###############################################################
#  Generated by:      Cadence Innovus 22.12-s080_1
#  OS:                Linux x86_64(Host ID apcw301i-10-205-43-14.nxdi.in-awsc1.nxp.com)
#  Generated on:      Tue Aug  8 16:31:20 2023
#  Design:            CortexM3Integration
#  Command:           write_lef_abstract 1234.lef
###############################################################

VERSION 5.8 ;

BUSBITCHARS "[]" ;
DIVIDERCHAR "/" ;

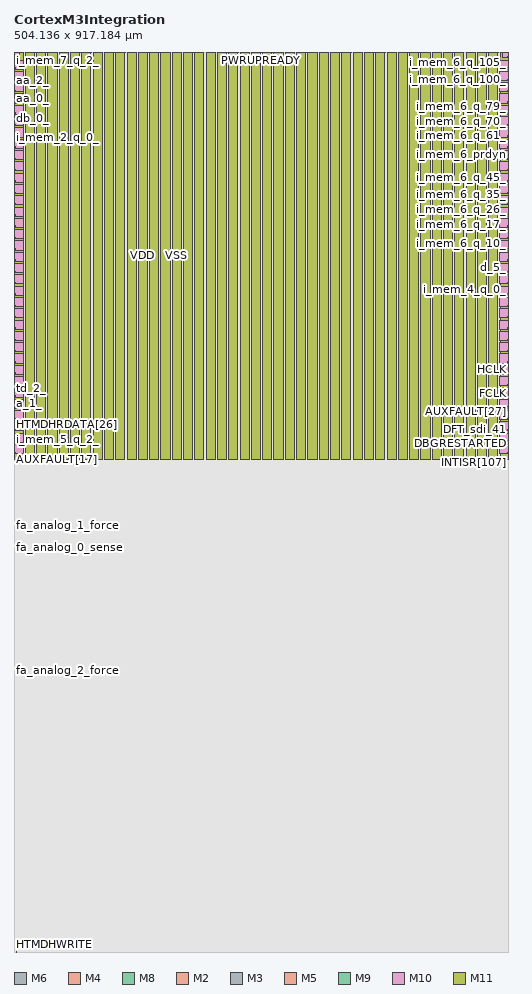
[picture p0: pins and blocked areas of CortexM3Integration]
MACRO CortexM3Integration
  FIXEDMASK ;
  CLASS BLOCK ;
  SIZE 504.136000 BY 917.184000 ;
  FOREIGN CortexM3Integration 0.000000 0.000000 ;
  ORIGIN 0 0 ;
  SYMMETRY X Y R90 ;
  PIN PWRUP
    DIRECTION INPUT ;
    USE SIGNAL ;
    PORT
      LAYER M6 ;
        RECT 0.000000 518.900000 0.375000 518.940000 ;
    END
  END PWRUP
  PIN ISOLATEn
    DIRECTION INPUT ;
    USE SIGNAL ;
    PORT
      LAYER M4 ;
        RECT 503.761000 518.500000 504.136000 518.540000 ;
    END
  END ISOLATEn
  PIN RETAINn
    DIRECTION INPUT ;
    USE SIGNAL ;
    PORT
      LAYER M6 ;
        RECT 503.761000 501.780000 504.136000 501.820000 ;
    END
  END RETAINn
  PIN nTRST
    DIRECTION INPUT ;
    USE SIGNAL ;
    PORT
      LAYER M6 ;
        RECT 0.000000 519.060000 0.375000 519.100000 ;
    END
  END nTRST
  PIN SWCLKTCK
    DIRECTION INPUT ;
    USE SIGNAL ;
    PORT
      LAYER M8 ;
        RECT 504.018000 518.371000 504.136000 518.557000 ;
    END
  END SWCLKTCK
  PIN SWDITMS
    DIRECTION INPUT ;
    USE SIGNAL ;
    PORT
      LAYER M2 ;
        RECT MASK 2 503.907000 518.512000 504.136000 518.544000 ;
    END
  END SWDITMS
  PIN TDI
    DIRECTION INPUT ;
    USE SIGNAL ;
    PORT
      LAYER M8 ;
        RECT 0.000000 519.073000 0.354000 519.135000 ;
    END
  END TDI
  PIN PORESETn
    DIRECTION INPUT ;
    USE SIGNAL ;
    PORT
      LAYER M8 ;
        RECT 503.782000 518.945000 504.136000 519.007000 ;
    END
  END PORESETn
  PIN SYSRESETn
    DIRECTION INPUT ;
    USE SIGNAL ;
    PORT
      LAYER M4 ;
        RECT 503.761000 517.380000 504.136000 517.420000 ;
    END
  END SYSRESETn
  PIN RSTBYPASS
    DIRECTION INPUT ;
    USE SIGNAL ;
    PORT
      LAYER M6 ;
        RECT 0.000000 519.220000 0.375000 519.260000 ;
    END
  END RSTBYPASS
  PIN CGBYPASS
    DIRECTION INPUT ;
    USE SIGNAL ;
    PORT
      LAYER M4 ;
        RECT 503.761000 501.780000 504.136000 501.820000 ;
    END
  END CGBYPASS
  PIN FCLK
    DIRECTION INPUT ;
    USE SIGNAL ;
    PORT
      LAYER M8 ;
        RECT 504.018000 561.507000 504.136000 561.693000 ;
    END
  END FCLK
  PIN HCLK
    DIRECTION INPUT ;
    USE SIGNAL ;
    PORT
      LAYER M8 ;
        RECT 504.018000 593.379000 504.136000 593.565000 ;
    END
  END HCLK
  PIN TRACECLKIN
    DIRECTION INPUT ;
    USE SIGNAL ;
    PORT
      LAYER M6 ;
        RECT 0.000000 519.380000 0.375000 519.420000 ;
    END
  END TRACECLKIN
  PIN STCLK
    DIRECTION INPUT ;
    USE SIGNAL ;
    PORT
      LAYER M8 ;
        RECT 0.000000 519.329000 0.354000 519.391000 ;
    END
  END STCLK
  PIN STCALIB[25]
    DIRECTION INPUT ;
    USE SIGNAL ;
    PORT
      LAYER M2 ;
        RECT MASK 2 503.907000 515.952000 504.136000 515.984000 ;
    END
  END STCALIB[25]
  PIN STCALIB[24]
    DIRECTION INPUT ;
    USE SIGNAL ;
    PORT
      LAYER M6 ;
        RECT 0.000000 518.100000 0.375000 518.140000 ;
    END
  END STCALIB[24]
  PIN STCALIB[23]
    DIRECTION INPUT ;
    USE SIGNAL ;
    PORT
      LAYER M8 ;
        RECT 0.000000 518.049000 0.354000 518.111000 ;
    END
  END STCALIB[23]
  PIN STCALIB[22]
    DIRECTION INPUT ;
    USE SIGNAL ;
    PORT
      LAYER M6 ;
        RECT 503.761000 516.740000 504.136000 516.780000 ;
    END
  END STCALIB[22]
  PIN STCALIB[21]
    DIRECTION INPUT ;
    USE SIGNAL ;
    PORT
      LAYER M8 ;
        RECT 503.782000 516.129000 504.136000 516.191000 ;
    END
  END STCALIB[21]
  PIN STCALIB[20]
    DIRECTION INPUT ;
    USE SIGNAL ;
    PORT
      LAYER M4 ;
        RECT 503.761000 516.740000 504.136000 516.780000 ;
    END
  END STCALIB[20]
  PIN STCALIB[19]
    DIRECTION INPUT ;
    USE SIGNAL ;
    PORT
      LAYER M6 ;
        RECT 503.761000 516.180000 504.136000 516.220000 ;
    END
  END STCALIB[19]
  PIN STCALIB[18]
    DIRECTION INPUT ;
    USE SIGNAL ;
    PORT
      LAYER M6 ;
        RECT 503.761000 518.180000 504.136000 518.220000 ;
    END
  END STCALIB[18]
  PIN STCALIB[17]
    DIRECTION INPUT ;
    USE SIGNAL ;
    PORT
      LAYER M6 ;
        RECT 0.000000 518.260000 0.375000 518.300000 ;
    END
  END STCALIB[17]
  PIN STCALIB[16]
    DIRECTION INPUT ;
    USE SIGNAL ;
    PORT
      LAYER M6 ;
        RECT 503.761000 517.380000 504.136000 517.420000 ;
    END
  END STCALIB[16]
  PIN STCALIB[15]
    DIRECTION INPUT ;
    USE SIGNAL ;
    PORT
      LAYER M2 ;
        RECT MASK 2 503.907000 519.408000 504.136000 519.440000 ;
    END
  END STCALIB[15]
  PIN STCALIB[14]
    DIRECTION INPUT ;
    USE SIGNAL ;
    PORT
      LAYER M8 ;
        RECT 0.000000 518.305000 0.354000 518.367000 ;
    END
  END STCALIB[14]
  PIN STCALIB[13]
    DIRECTION INPUT ;
    USE SIGNAL ;
    PORT
      LAYER M2 ;
        RECT MASK 2 503.907000 518.256000 504.136000 518.288000 ;
    END
  END STCALIB[13]
  PIN STCALIB[12]
    DIRECTION INPUT ;
    USE SIGNAL ;
    PORT
      LAYER M4 ;
        RECT 503.761000 518.180000 504.136000 518.220000 ;
    END
  END STCALIB[12]
  PIN STCALIB[11]
    DIRECTION INPUT ;
    USE SIGNAL ;
    PORT
      LAYER M6 ;
        RECT 0.000000 518.420000 0.375000 518.460000 ;
    END
  END STCALIB[11]
  PIN STCALIB[10]
    DIRECTION INPUT ;
    USE SIGNAL ;
    PORT
      LAYER M2 ;
        RECT MASK 2 503.907000 518.000000 504.136000 518.032000 ;
    END
  END STCALIB[10]
  PIN STCALIB[9]
    DIRECTION INPUT ;
    USE SIGNAL ;
    PORT
      LAYER M8 ;
        RECT 503.782000 517.793000 504.136000 517.855000 ;
    END
  END STCALIB[9]
  PIN STCALIB[8]
    DIRECTION INPUT ;
    USE SIGNAL ;
    PORT
      LAYER M4 ;
        RECT 503.761000 519.220000 504.136000 519.260000 ;
    END
  END STCALIB[8]
  PIN STCALIB[7]
    DIRECTION INPUT ;
    USE SIGNAL ;
    PORT
      LAYER M6 ;
        RECT 0.000000 518.580000 0.375000 518.620000 ;
    END
  END STCALIB[7]
  PIN STCALIB[6]
    DIRECTION INPUT ;
    USE SIGNAL ;
    PORT
      LAYER M8 ;
        RECT 0.000000 518.561000 0.354000 518.623000 ;
    END
  END STCALIB[6]
  PIN STCALIB[5]
    DIRECTION INPUT ;
    USE SIGNAL ;
    PORT
      LAYER M2 ;
        RECT MASK 2 503.907000 517.104000 504.136000 517.136000 ;
    END
  END STCALIB[5]
  PIN STCALIB[4]
    DIRECTION INPUT ;
    USE SIGNAL ;
    PORT
      LAYER M8 ;
        RECT 503.782000 517.281000 504.136000 517.343000 ;
    END
  END STCALIB[4]
  PIN STCALIB[3]
    DIRECTION INPUT ;
    USE SIGNAL ;
    PORT
      LAYER M8 ;
        RECT 503.782000 516.641000 504.136000 516.703000 ;
    END
  END STCALIB[3]
  PIN STCALIB[2]
    DIRECTION INPUT ;
    USE SIGNAL ;
    PORT
      LAYER M8 ;
        RECT 503.782000 519.457000 504.136000 519.519000 ;
    END
  END STCALIB[2]
  PIN STCALIB[1]
    DIRECTION INPUT ;
    USE SIGNAL ;
    PORT
      LAYER M6 ;
        RECT 0.000000 518.740000 0.375000 518.780000 ;
    END
  END STCALIB[1]
  PIN STCALIB[0]
    DIRECTION INPUT ;
    USE SIGNAL ;
    PORT
      LAYER M4 ;
        RECT 503.761000 517.860000 504.136000 517.900000 ;
    END
  END STCALIB[0]
  PIN AUXFAULT[31]
    DIRECTION INPUT ;
    USE SIGNAL ;
    PORT
      LAYER M2 ;
        RECT MASK 2 0.000000 501.744000 0.229000 501.776000 ;
    END
  END AUXFAULT[31]
  PIN AUXFAULT[30]
    DIRECTION INPUT ;
    USE SIGNAL ;
    PORT
      LAYER M4 ;
        RECT 503.761000 551.060000 504.136000 551.100000 ;
    END
  END AUXFAULT[30]
  PIN AUXFAULT[29]
    DIRECTION INPUT ;
    USE SIGNAL ;
    PORT
      LAYER M4 ;
        RECT 0.000000 501.780000 0.375000 501.820000 ;
    END
  END AUXFAULT[29]
  PIN AUXFAULT[28]
    DIRECTION INPUT ;
    USE SIGNAL ;
    PORT
      LAYER M6 ;
        RECT 0.000000 501.780000 0.375000 501.820000 ;
    END
  END AUXFAULT[28]
  PIN AUXFAULT[27]
    DIRECTION INPUT ;
    USE SIGNAL ;
    PORT
      LAYER M2 ;
        RECT MASK 1 503.907000 550.960000 504.136000 550.992000 ;
    END
  END AUXFAULT[27]
  PIN AUXFAULT[26]
    DIRECTION INPUT ;
    USE SIGNAL ;
    PORT
      LAYER M8 ;
        RECT 503.782000 550.817000 504.136000 550.879000 ;
    END
  END AUXFAULT[26]
  PIN AUXFAULT[25]
    DIRECTION INPUT ;
    USE SIGNAL ;
    PORT
      LAYER M8 ;
        RECT 0.000000 501.793000 0.354000 501.855000 ;
    END
  END AUXFAULT[25]
  PIN AUXFAULT[24]
    DIRECTION INPUT ;
    USE SIGNAL ;
    PORT
      LAYER M6 ;
        RECT 503.761000 550.820000 504.136000 550.860000 ;
    END
  END AUXFAULT[24]
  PIN AUXFAULT[23]
    DIRECTION INPUT ;
    USE SIGNAL ;
    PORT
      LAYER M2 ;
        RECT MASK 2 0.000000 501.872000 0.229000 501.904000 ;
    END
  END AUXFAULT[23]
  PIN AUXFAULT[22]
    DIRECTION INPUT ;
    USE SIGNAL ;
    PORT
      LAYER M4 ;
        RECT 503.761000 550.740000 504.136000 550.780000 ;
    END
  END AUXFAULT[22]
  PIN AUXFAULT[21]
    DIRECTION INPUT ;
    USE SIGNAL ;
    PORT
      LAYER M4 ;
        RECT 0.000000 501.940000 0.375000 501.980000 ;
    END
  END AUXFAULT[21]
  PIN AUXFAULT[20]
    DIRECTION INPUT ;
    USE SIGNAL ;
    PORT
      LAYER M6 ;
        RECT 0.000000 501.940000 0.375000 501.980000 ;
    END
  END AUXFAULT[20]
  PIN AUXFAULT[19]
    DIRECTION INPUT ;
    USE SIGNAL ;
    PORT
      LAYER M2 ;
        RECT MASK 1 503.907000 550.704000 504.136000 550.736000 ;
    END
  END AUXFAULT[19]
  PIN AUXFAULT[18]
    DIRECTION INPUT ;
    USE SIGNAL ;
    PORT
      LAYER M6 ;
        RECT 503.761000 550.500000 504.136000 550.540000 ;
    END
  END AUXFAULT[18]
  PIN AUXFAULT[17]
    DIRECTION INPUT ;
    USE SIGNAL ;
    PORT
      LAYER M2 ;
        RECT MASK 2 0.000000 502.000000 0.229000 502.032000 ;
    END
  END AUXFAULT[17]
  PIN AUXFAULT[16]
    DIRECTION INPUT ;
    USE SIGNAL ;
    PORT
      LAYER M2 ;
        RECT MASK 1 503.907000 550.448000 504.136000 550.480000 ;
    END
  END AUXFAULT[16]
  PIN AUXFAULT[15]
    DIRECTION INPUT ;
    USE SIGNAL ;
    PORT
      LAYER M4 ;
        RECT 0.000000 502.100000 0.375000 502.140000 ;
    END
  END AUXFAULT[15]
  PIN AUXFAULT[14]
    DIRECTION INPUT ;
    USE SIGNAL ;
    PORT
      LAYER M6 ;
        RECT 0.000000 502.100000 0.375000 502.140000 ;
    END
  END AUXFAULT[14]
  PIN AUXFAULT[13]
    DIRECTION INPUT ;
    USE SIGNAL ;
    PORT
      LAYER M8 ;
        RECT 0.000000 502.049000 0.354000 502.111000 ;
    END
  END AUXFAULT[13]
  PIN AUXFAULT[12]
    DIRECTION INPUT ;
    USE SIGNAL ;
    PORT
      LAYER M4 ;
        RECT 503.761000 550.420000 504.136000 550.460000 ;
    END
  END AUXFAULT[12]
  PIN AUXFAULT[11]
    DIRECTION INPUT ;
    USE SIGNAL ;
    PORT
      LAYER M8 ;
        RECT 503.782000 550.305000 504.136000 550.367000 ;
    END
  END AUXFAULT[11]
  PIN AUXFAULT[10]
    DIRECTION INPUT ;
    USE SIGNAL ;
    PORT
      LAYER M2 ;
        RECT MASK 1 503.907000 550.192000 504.136000 550.224000 ;
    END
  END AUXFAULT[10]
  PIN AUXFAULT[9]
    DIRECTION INPUT ;
    USE SIGNAL ;
    PORT
      LAYER M2 ;
        RECT MASK 2 0.000000 502.128000 0.229000 502.160000 ;
    END
  END AUXFAULT[9]
  PIN AUXFAULT[8]
    DIRECTION INPUT ;
    USE SIGNAL ;
    PORT
      LAYER M6 ;
        RECT 503.761000 550.180000 504.136000 550.220000 ;
    END
  END AUXFAULT[8]
  PIN AUXFAULT[7]
    DIRECTION INPUT ;
    USE SIGNAL ;
    PORT
      LAYER M2 ;
        RECT MASK 2 0.000000 502.256000 0.229000 502.288000 ;
    END
  END AUXFAULT[7]
  PIN AUXFAULT[6]
    DIRECTION INPUT ;
    USE SIGNAL ;
    PORT
      LAYER M4 ;
        RECT 503.761000 550.100000 504.136000 550.140000 ;
    END
  END AUXFAULT[6]
  PIN AUXFAULT[5]
    DIRECTION INPUT ;
    USE SIGNAL ;
    PORT
      LAYER M4 ;
        RECT 0.000000 502.260000 0.375000 502.300000 ;
    END
  END AUXFAULT[5]
  PIN AUXFAULT[4]
    DIRECTION INPUT ;
    USE SIGNAL ;
    PORT
      LAYER M6 ;
        RECT 0.000000 502.260000 0.375000 502.300000 ;
    END
  END AUXFAULT[4]
  PIN AUXFAULT[3]
    DIRECTION INPUT ;
    USE SIGNAL ;
    PORT
      LAYER M2 ;
        RECT MASK 1 503.907000 549.936000 504.136000 549.968000 ;
    END
  END AUXFAULT[3]
  PIN AUXFAULT[2]
    DIRECTION INPUT ;
    USE SIGNAL ;
    PORT
      LAYER M6 ;
        RECT 503.761000 549.860000 504.136000 549.900000 ;
    END
  END AUXFAULT[2]
  PIN AUXFAULT[1]
    DIRECTION INPUT ;
    USE SIGNAL ;
    PORT
      LAYER M8 ;
        RECT 0.000000 502.305000 0.354000 502.367000 ;
    END
  END AUXFAULT[1]
  PIN AUXFAULT[0]
    DIRECTION INPUT ;
    USE SIGNAL ;
    PORT
      LAYER M8 ;
        RECT 503.782000 549.793000 504.136000 549.855000 ;
    END
  END AUXFAULT[0]
  PIN BIGEND
    DIRECTION INPUT ;
    USE SIGNAL ;
    PORT
      LAYER M2 ;
        RECT MASK 2 503.907000 517.360000 504.136000 517.392000 ;
    END
  END BIGEND
  PIN INTISR[239]
    DIRECTION INPUT ;
    USE SIGNAL ;
    PORT
      LAYER M6 ;
        RECT 503.761000 533.860000 504.136000 533.900000 ;
    END
  END INTISR[239]
  PIN INTISR[238]
    DIRECTION INPUT ;
    USE SIGNAL ;
    PORT
      LAYER M2 ;
        RECT MASK 1 503.907000 533.808000 504.136000 533.840000 ;
    END
  END INTISR[238]
  PIN INTISR[237]
    DIRECTION INPUT ;
    USE SIGNAL ;
    PORT
      LAYER M6 ;
        RECT 0.000000 511.060000 0.375000 511.100000 ;
    END
  END INTISR[237]
  PIN INTISR[236]
    DIRECTION INPUT ;
    USE SIGNAL ;
    PORT
      LAYER M4 ;
        RECT 503.761000 533.780000 504.136000 533.820000 ;
    END
  END INTISR[236]
  PIN INTISR[235]
    DIRECTION INPUT ;
    USE SIGNAL ;
    PORT
      LAYER M8 ;
        RECT 503.782000 533.665000 504.136000 533.727000 ;
    END
  END INTISR[235]
  PIN INTISR[234]
    DIRECTION INPUT ;
    USE SIGNAL ;
    PORT
      LAYER M2 ;
        RECT MASK 1 503.907000 533.552000 504.136000 533.584000 ;
    END
  END INTISR[234]
  PIN INTISR[233]
    DIRECTION INPUT ;
    USE SIGNAL ;
    PORT
      LAYER M8 ;
        RECT 0.000000 511.137000 0.354000 511.199000 ;
    END
  END INTISR[233]
  PIN INTISR[232]
    DIRECTION INPUT ;
    USE SIGNAL ;
    PORT
      LAYER M6 ;
        RECT 503.761000 533.540000 504.136000 533.580000 ;
    END
  END INTISR[232]
  PIN INTISR[231]
    DIRECTION INPUT ;
    USE SIGNAL ;
    PORT
      LAYER M4 ;
        RECT 503.761000 533.460000 504.136000 533.500000 ;
    END
  END INTISR[231]
  PIN INTISR[230]
    DIRECTION INPUT ;
    USE SIGNAL ;
    PORT
      LAYER M6 ;
        RECT 0.000000 511.220000 0.375000 511.260000 ;
    END
  END INTISR[230]
  PIN INTISR[229]
    DIRECTION INPUT ;
    USE SIGNAL ;
    PORT
      LAYER M2 ;
        RECT MASK 1 503.907000 533.296000 504.136000 533.328000 ;
    END
  END INTISR[229]
  PIN INTISR[228]
    DIRECTION INPUT ;
    USE SIGNAL ;
    PORT
      LAYER M6 ;
        RECT 503.761000 533.220000 504.136000 533.260000 ;
    END
  END INTISR[228]
  PIN INTISR[227]
    DIRECTION INPUT ;
    USE SIGNAL ;
    PORT
      LAYER M8 ;
        RECT 503.782000 533.153000 504.136000 533.215000 ;
    END
  END INTISR[227]
  PIN INTISR[226]
    DIRECTION INPUT ;
    USE SIGNAL ;
    PORT
      LAYER M6 ;
        RECT 0.000000 511.380000 0.375000 511.420000 ;
    END
  END INTISR[226]
  PIN INTISR[225]
    DIRECTION INPUT ;
    USE SIGNAL ;
    PORT
      LAYER M4 ;
        RECT 503.761000 533.140000 504.136000 533.180000 ;
    END
  END INTISR[225]
  PIN INTISR[224]
    DIRECTION INPUT ;
    USE SIGNAL ;
    PORT
      LAYER M2 ;
        RECT MASK 1 503.907000 533.040000 504.136000 533.072000 ;
    END
  END INTISR[224]
  PIN INTISR[223]
    DIRECTION INPUT ;
    USE SIGNAL ;
    PORT
      LAYER M8 ;
        RECT 0.000000 511.393000 0.354000 511.455000 ;
    END
  END INTISR[223]
  PIN INTISR[222]
    DIRECTION INPUT ;
    USE SIGNAL ;
    PORT
      LAYER M2 ;
        RECT MASK 1 503.907000 534.064000 504.136000 534.096000 ;
    END
  END INTISR[222]
  PIN INTISR[221]
    DIRECTION INPUT ;
    USE SIGNAL ;
    PORT
      LAYER M2 ;
        RECT MASK 1 503.907000 532.016000 504.136000 532.048000 ;
    END
  END INTISR[221]
  PIN INTISR[220]
    DIRECTION INPUT ;
    USE SIGNAL ;
    PORT
      LAYER M6 ;
        RECT 0.000000 511.540000 0.375000 511.580000 ;
    END
  END INTISR[220]
  PIN INTISR[219]
    DIRECTION INPUT ;
    USE SIGNAL ;
    PORT
      LAYER M6 ;
        RECT 503.761000 531.940000 504.136000 531.980000 ;
    END
  END INTISR[219]
  PIN INTISR[218]
    DIRECTION INPUT ;
    USE SIGNAL ;
    PORT
      LAYER M4 ;
        RECT 503.761000 531.860000 504.136000 531.900000 ;
    END
  END INTISR[218]
  PIN INTISR[217]
    DIRECTION INPUT ;
    USE SIGNAL ;
    PORT
      LAYER M2 ;
        RECT MASK 1 503.907000 531.760000 504.136000 531.792000 ;
    END
  END INTISR[217]
  PIN INTISR[216]
    DIRECTION INPUT ;
    USE SIGNAL ;
    PORT
      LAYER M6 ;
        RECT 0.000000 511.700000 0.375000 511.740000 ;
    END
  END INTISR[216]
  PIN INTISR[215]
    DIRECTION INPUT ;
    USE SIGNAL ;
    PORT
      LAYER M8 ;
        RECT 0.000000 511.649000 0.354000 511.711000 ;
    END
  END INTISR[215]
  PIN INTISR[214]
    DIRECTION INPUT ;
    USE SIGNAL ;
    PORT
      LAYER M6 ;
        RECT 503.761000 531.620000 504.136000 531.660000 ;
    END
  END INTISR[214]
  PIN INTISR[213]
    DIRECTION INPUT ;
    USE SIGNAL ;
    PORT
      LAYER M4 ;
        RECT 503.761000 531.540000 504.136000 531.580000 ;
    END
  END INTISR[213]
  PIN INTISR[212]
    DIRECTION INPUT ;
    USE SIGNAL ;
    PORT
      LAYER M2 ;
        RECT MASK 1 503.907000 531.504000 504.136000 531.536000 ;
    END
  END INTISR[212]
  PIN INTISR[211]
    DIRECTION INPUT ;
    USE SIGNAL ;
    PORT
      LAYER M6 ;
        RECT 503.761000 531.300000 504.136000 531.340000 ;
    END
  END INTISR[211]
  PIN INTISR[210]
    DIRECTION INPUT ;
    USE SIGNAL ;
    PORT
      LAYER M2 ;
        RECT MASK 1 503.907000 531.248000 504.136000 531.280000 ;
    END
  END INTISR[210]
  PIN INTISR[209]
    DIRECTION INPUT ;
    USE SIGNAL ;
    PORT
      LAYER M6 ;
        RECT 0.000000 511.860000 0.375000 511.900000 ;
    END
  END INTISR[209]
  PIN INTISR[208]
    DIRECTION INPUT ;
    USE SIGNAL ;
    PORT
      LAYER M6 ;
        RECT 503.761000 513.620000 504.136000 513.660000 ;
    END
  END INTISR[208]
  PIN INTISR[207]
    DIRECTION INPUT ;
    USE SIGNAL ;
    PORT
      LAYER M2 ;
        RECT MASK 2 503.907000 513.392000 504.136000 513.424000 ;
    END
  END INTISR[207]
  PIN INTISR[206]
    DIRECTION INPUT ;
    USE SIGNAL ;
    PORT
      LAYER M8 ;
        RECT 0.000000 511.905000 0.354000 511.967000 ;
    END
  END INTISR[206]
  PIN INTISR[205]
    DIRECTION INPUT ;
    USE SIGNAL ;
    PORT
      LAYER M6 ;
        RECT 503.761000 513.300000 504.136000 513.340000 ;
    END
  END INTISR[205]
  PIN INTISR[204]
    DIRECTION INPUT ;
    USE SIGNAL ;
    PORT
      LAYER M8 ;
        RECT 503.782000 513.185000 504.136000 513.247000 ;
    END
  END INTISR[204]
  PIN INTISR[203]
    DIRECTION INPUT ;
    USE SIGNAL ;
    PORT
      LAYER M6 ;
        RECT 0.000000 512.020000 0.375000 512.060000 ;
    END
  END INTISR[203]
  PIN INTISR[202]
    DIRECTION INPUT ;
    USE SIGNAL ;
    PORT
      LAYER M6 ;
        RECT 503.761000 512.980000 504.136000 513.020000 ;
    END
  END INTISR[202]
  PIN INTISR[201]
    DIRECTION INPUT ;
    USE SIGNAL ;
    PORT
      LAYER M2 ;
        RECT MASK 2 503.907000 512.752000 504.136000 512.784000 ;
    END
  END INTISR[201]
  PIN INTISR[200]
    DIRECTION INPUT ;
    USE SIGNAL ;
    PORT
      LAYER M8 ;
        RECT 503.782000 512.673000 504.136000 512.735000 ;
    END
  END INTISR[200]
  PIN INTISR[199]
    DIRECTION INPUT ;
    USE SIGNAL ;
    PORT
      LAYER M6 ;
        RECT 0.000000 512.180000 0.375000 512.220000 ;
    END
  END INTISR[199]
  PIN INTISR[198]
    DIRECTION INPUT ;
    USE SIGNAL ;
    PORT
      LAYER M8 ;
        RECT 0.000000 512.161000 0.354000 512.223000 ;
    END
  END INTISR[198]
  PIN INTISR[197]
    DIRECTION INPUT ;
    USE SIGNAL ;
    PORT
      LAYER M6 ;
        RECT 503.761000 512.660000 504.136000 512.700000 ;
    END
  END INTISR[197]
  PIN INTISR[196]
    DIRECTION INPUT ;
    USE SIGNAL ;
    PORT
      LAYER M4 ;
        RECT 503.761000 512.660000 504.136000 512.700000 ;
    END
  END INTISR[196]
  PIN INTISR[195]
    DIRECTION INPUT ;
    USE SIGNAL ;
    PORT
      LAYER M2 ;
        RECT MASK 2 503.907000 512.496000 504.136000 512.528000 ;
    END
  END INTISR[195]
  PIN INTISR[194]
    DIRECTION INPUT ;
    USE SIGNAL ;
    PORT
      LAYER M6 ;
        RECT 503.761000 512.340000 504.136000 512.380000 ;
    END
  END INTISR[194]
  PIN INTISR[193]
    DIRECTION INPUT ;
    USE SIGNAL ;
    PORT
      LAYER M6 ;
        RECT 0.000000 512.340000 0.375000 512.380000 ;
    END
  END INTISR[193]
  PIN INTISR[192]
    DIRECTION INPUT ;
    USE SIGNAL ;
    PORT
      LAYER M6 ;
        RECT 503.761000 512.020000 504.136000 512.060000 ;
    END
  END INTISR[192]
  PIN INTISR[191]
    DIRECTION INPUT ;
    USE SIGNAL ;
    PORT
      LAYER M4 ;
        RECT 503.761000 512.020000 504.136000 512.060000 ;
    END
  END INTISR[191]
  PIN INTISR[190]
    DIRECTION INPUT ;
    USE SIGNAL ;
    PORT
      LAYER M2 ;
        RECT MASK 2 503.907000 511.984000 504.136000 512.016000 ;
    END
  END INTISR[190]
  PIN INTISR[189]
    DIRECTION INPUT ;
    USE SIGNAL ;
    PORT
      LAYER M8 ;
        RECT 0.000000 512.417000 0.354000 512.479000 ;
    END
  END INTISR[189]
  PIN INTISR[188]
    DIRECTION INPUT ;
    USE SIGNAL ;
    PORT
      LAYER M2 ;
        RECT MASK 2 503.907000 511.728000 504.136000 511.760000 ;
    END
  END INTISR[188]
  PIN INTISR[187]
    DIRECTION INPUT ;
    USE SIGNAL ;
    PORT
      LAYER M6 ;
        RECT 503.761000 511.700000 504.136000 511.740000 ;
    END
  END INTISR[187]
  PIN INTISR[186]
    DIRECTION INPUT ;
    USE SIGNAL ;
    PORT
      LAYER M6 ;
        RECT 0.000000 512.500000 0.375000 512.540000 ;
    END
  END INTISR[186]
  PIN INTISR[185]
    DIRECTION INPUT ;
    USE SIGNAL ;
    PORT
      LAYER M4 ;
        RECT 503.761000 511.700000 504.136000 511.740000 ;
    END
  END INTISR[185]
  PIN INTISR[184]
    DIRECTION INPUT ;
    USE SIGNAL ;
    PORT
      LAYER M8 ;
        RECT 503.782000 511.649000 504.136000 511.711000 ;
    END
  END INTISR[184]
  PIN INTISR[183]
    DIRECTION INPUT ;
    USE SIGNAL ;
    PORT
      LAYER M2 ;
        RECT MASK 2 503.907000 511.472000 504.136000 511.504000 ;
    END
  END INTISR[183]
  PIN INTISR[182]
    DIRECTION INPUT ;
    USE SIGNAL ;
    PORT
      LAYER M6 ;
        RECT 0.000000 512.660000 0.375000 512.700000 ;
    END
  END INTISR[182]
  PIN INTISR[181]
    DIRECTION INPUT ;
    USE SIGNAL ;
    PORT
      LAYER M6 ;
        RECT 503.761000 511.380000 504.136000 511.420000 ;
    END
  END INTISR[181]
  PIN INTISR[180]
    DIRECTION INPUT ;
    USE SIGNAL ;
    PORT
      LAYER M4 ;
        RECT 503.761000 511.380000 504.136000 511.420000 ;
    END
  END INTISR[180]
  PIN INTISR[179]
    DIRECTION INPUT ;
    USE SIGNAL ;
    PORT
      LAYER M8 ;
        RECT 0.000000 512.673000 0.354000 512.735000 ;
    END
  END INTISR[179]
  PIN INTISR[178]
    DIRECTION INPUT ;
    USE SIGNAL ;
    PORT
      LAYER M2 ;
        RECT MASK 2 503.907000 511.216000 504.136000 511.248000 ;
    END
  END INTISR[178]
  PIN INTISR[177]
    DIRECTION INPUT ;
    USE SIGNAL ;
    PORT
      LAYER M8 ;
        RECT 503.782000 511.137000 504.136000 511.199000 ;
    END
  END INTISR[177]
  PIN INTISR[176]
    DIRECTION INPUT ;
    USE SIGNAL ;
    PORT
      LAYER M6 ;
        RECT 0.000000 512.820000 0.375000 512.860000 ;
    END
  END INTISR[176]
  PIN INTISR[175]
    DIRECTION INPUT ;
    USE SIGNAL ;
    PORT
      LAYER M6 ;
        RECT 503.761000 511.060000 504.136000 511.100000 ;
    END
  END INTISR[175]
  PIN INTISR[174]
    DIRECTION INPUT ;
    USE SIGNAL ;
    PORT
      LAYER M4 ;
        RECT 503.761000 511.060000 504.136000 511.100000 ;
    END
  END INTISR[174]
  PIN INTISR[173]
    DIRECTION INPUT ;
    USE SIGNAL ;
    PORT
      LAYER M2 ;
        RECT MASK 2 503.907000 510.960000 504.136000 510.992000 ;
    END
  END INTISR[173]
  PIN INTISR[172]
    DIRECTION INPUT ;
    USE SIGNAL ;
    PORT
      LAYER M6 ;
        RECT 0.000000 512.980000 0.375000 513.020000 ;
    END
  END INTISR[172]
  PIN INTISR[171]
    DIRECTION INPUT ;
    USE SIGNAL ;
    PORT
      LAYER M8 ;
        RECT 0.000000 512.929000 0.354000 512.991000 ;
    END
  END INTISR[171]
  PIN INTISR[170]
    DIRECTION INPUT ;
    USE SIGNAL ;
    PORT
      LAYER M6 ;
        RECT 503.761000 510.740000 504.136000 510.780000 ;
    END
  END INTISR[170]
  PIN INTISR[169]
    DIRECTION INPUT ;
    USE SIGNAL ;
    PORT
      LAYER M4 ;
        RECT 503.761000 510.740000 504.136000 510.780000 ;
    END
  END INTISR[169]
  PIN INTISR[168]
    DIRECTION INPUT ;
    USE SIGNAL ;
    PORT
      LAYER M2 ;
        RECT MASK 2 503.907000 510.704000 504.136000 510.736000 ;
    END
  END INTISR[168]
  PIN INTISR[167]
    DIRECTION INPUT ;
    USE SIGNAL ;
    PORT
      LAYER M8 ;
        RECT 503.782000 510.625000 504.136000 510.687000 ;
    END
  END INTISR[167]
  PIN INTISR[166]
    DIRECTION INPUT ;
    USE SIGNAL ;
    PORT
      LAYER M2 ;
        RECT MASK 2 503.907000 510.448000 504.136000 510.480000 ;
    END
  END INTISR[166]
  PIN INTISR[165]
    DIRECTION INPUT ;
    USE SIGNAL ;
    PORT
      LAYER M6 ;
        RECT 0.000000 513.140000 0.375000 513.180000 ;
    END
  END INTISR[165]
  PIN INTISR[164]
    DIRECTION INPUT ;
    USE SIGNAL ;
    PORT
      LAYER M6 ;
        RECT 503.761000 510.420000 504.136000 510.460000 ;
    END
  END INTISR[164]
  PIN INTISR[163]
    DIRECTION INPUT ;
    USE SIGNAL ;
    PORT
      LAYER M4 ;
        RECT 503.761000 510.420000 504.136000 510.460000 ;
    END
  END INTISR[163]
  PIN INTISR[162]
    DIRECTION INPUT ;
    USE SIGNAL ;
    PORT
      LAYER M8 ;
        RECT 0.000000 513.185000 0.354000 513.247000 ;
    END
  END INTISR[162]
  PIN INTISR[161]
    DIRECTION INPUT ;
    USE SIGNAL ;
    PORT
      LAYER M8 ;
        RECT 503.782000 512.161000 504.136000 512.223000 ;
    END
  END INTISR[161]
  PIN INTISR[160]
    DIRECTION INPUT ;
    USE SIGNAL ;
    PORT
      LAYER M2 ;
        RECT MASK 2 503.907000 510.192000 504.136000 510.224000 ;
    END
  END INTISR[160]
  PIN INTISR[159]
    DIRECTION INPUT ;
    USE SIGNAL ;
    PORT
      LAYER M6 ;
        RECT 0.000000 513.300000 0.375000 513.340000 ;
    END
  END INTISR[159]
  PIN INTISR[158]
    DIRECTION INPUT ;
    USE SIGNAL ;
    PORT
      LAYER M8 ;
        RECT 503.782000 510.113000 504.136000 510.175000 ;
    END
  END INTISR[158]
  PIN INTISR[157]
    DIRECTION INPUT ;
    USE SIGNAL ;
    PORT
      LAYER M6 ;
        RECT 503.761000 510.100000 504.136000 510.140000 ;
    END
  END INTISR[157]
  PIN INTISR[156]
    DIRECTION INPUT ;
    USE SIGNAL ;
    PORT
      LAYER M4 ;
        RECT 503.761000 510.100000 504.136000 510.140000 ;
    END
  END INTISR[156]
  PIN INTISR[155]
    DIRECTION INPUT ;
    USE SIGNAL ;
    PORT
      LAYER M6 ;
        RECT 0.000000 513.460000 0.375000 513.500000 ;
    END
  END INTISR[155]
  PIN INTISR[154]
    DIRECTION INPUT ;
    USE SIGNAL ;
    PORT
      LAYER M8 ;
        RECT 0.000000 513.441000 0.354000 513.503000 ;
    END
  END INTISR[154]
  PIN INTISR[153]
    DIRECTION INPUT ;
    USE SIGNAL ;
    PORT
      LAYER M2 ;
        RECT MASK 2 503.907000 509.936000 504.136000 509.968000 ;
    END
  END INTISR[153]
  PIN INTISR[152]
    DIRECTION INPUT ;
    USE SIGNAL ;
    PORT
      LAYER M6 ;
        RECT 503.761000 509.780000 504.136000 509.820000 ;
    END
  END INTISR[152]
  PIN INTISR[151]
    DIRECTION INPUT ;
    USE SIGNAL ;
    PORT
      LAYER M4 ;
        RECT 503.761000 509.780000 504.136000 509.820000 ;
    END
  END INTISR[151]
  PIN INTISR[150]
    DIRECTION INPUT ;
    USE SIGNAL ;
    PORT
      LAYER M2 ;
        RECT MASK 2 503.907000 509.680000 504.136000 509.712000 ;
    END
  END INTISR[150]
  PIN INTISR[149]
    DIRECTION INPUT ;
    USE SIGNAL ;
    PORT
      LAYER M6 ;
        RECT 0.000000 513.620000 0.375000 513.660000 ;
    END
  END INTISR[149]
  PIN INTISR[148]
    DIRECTION INPUT ;
    USE SIGNAL ;
    PORT
      LAYER M8 ;
        RECT 503.782000 509.601000 504.136000 509.663000 ;
    END
  END INTISR[148]
  PIN INTISR[147]
    DIRECTION INPUT ;
    USE SIGNAL ;
    PORT
      LAYER M6 ;
        RECT 503.761000 509.460000 504.136000 509.500000 ;
    END
  END INTISR[147]
  PIN INTISR[146]
    DIRECTION INPUT ;
    USE SIGNAL ;
    PORT
      LAYER M4 ;
        RECT 503.761000 509.460000 504.136000 509.500000 ;
    END
  END INTISR[146]
  PIN INTISR[145]
    DIRECTION INPUT ;
    USE SIGNAL ;
    PORT
      LAYER M8 ;
        RECT 0.000000 513.697000 0.354000 513.759000 ;
    END
  END INTISR[145]
  PIN INTISR[144]
    DIRECTION INPUT ;
    USE SIGNAL ;
    PORT
      LAYER M2 ;
        RECT MASK 2 503.907000 509.424000 504.136000 509.456000 ;
    END
  END INTISR[144]
  PIN INTISR[143]
    DIRECTION INPUT ;
    USE SIGNAL ;
    PORT
      LAYER M2 ;
        RECT MASK 2 503.907000 509.168000 504.136000 509.200000 ;
    END
  END INTISR[143]
  PIN INTISR[142]
    DIRECTION INPUT ;
    USE SIGNAL ;
    PORT
      LAYER M6 ;
        RECT 0.000000 513.780000 0.375000 513.820000 ;
    END
  END INTISR[142]
  PIN INTISR[141]
    DIRECTION INPUT ;
    USE SIGNAL ;
    PORT
      LAYER M6 ;
        RECT 503.761000 509.140000 504.136000 509.180000 ;
    END
  END INTISR[141]
  PIN INTISR[140]
    DIRECTION INPUT ;
    USE SIGNAL ;
    PORT
      LAYER M4 ;
        RECT 503.761000 509.140000 504.136000 509.180000 ;
    END
  END INTISR[140]
  PIN INTISR[139]
    DIRECTION INPUT ;
    USE SIGNAL ;
    PORT
      LAYER M2 ;
        RECT MASK 2 503.907000 508.912000 504.136000 508.944000 ;
    END
  END INTISR[139]
  PIN INTISR[138]
    DIRECTION INPUT ;
    USE SIGNAL ;
    PORT
      LAYER M6 ;
        RECT 0.000000 513.940000 0.375000 513.980000 ;
    END
  END INTISR[138]
  PIN INTISR[137]
    DIRECTION INPUT ;
    USE SIGNAL ;
    PORT
      LAYER M6 ;
        RECT 503.761000 508.820000 504.136000 508.860000 ;
    END
  END INTISR[137]
  PIN INTISR[136]
    DIRECTION INPUT ;
    USE SIGNAL ;
    PORT
      LAYER M4 ;
        RECT 503.761000 508.820000 504.136000 508.860000 ;
    END
  END INTISR[136]
  PIN INTISR[135]
    DIRECTION INPUT ;
    USE SIGNAL ;
    PORT
      LAYER M8 ;
        RECT 0.000000 513.953000 0.354000 514.015000 ;
    END
  END INTISR[135]
  PIN INTISR[134]
    DIRECTION INPUT ;
    USE SIGNAL ;
    PORT
      LAYER M2 ;
        RECT MASK 2 503.907000 508.656000 504.136000 508.688000 ;
    END
  END INTISR[134]
  PIN INTISR[133]
    DIRECTION INPUT ;
    USE SIGNAL ;
    PORT
      LAYER M6 ;
        RECT 503.761000 508.500000 504.136000 508.540000 ;
    END
  END INTISR[133]
  PIN INTISR[132]
    DIRECTION INPUT ;
    USE SIGNAL ;
    PORT
      LAYER M6 ;
        RECT 0.000000 514.100000 0.375000 514.140000 ;
    END
  END INTISR[132]
  PIN INTISR[131]
    DIRECTION INPUT ;
    USE SIGNAL ;
    PORT
      LAYER M4 ;
        RECT 503.761000 512.340000 504.136000 512.380000 ;
    END
  END INTISR[131]
  PIN INTISR[130]
    DIRECTION INPUT ;
    USE SIGNAL ;
    PORT
      LAYER M2 ;
        RECT MASK 2 503.907000 512.240000 504.136000 512.272000 ;
    END
  END INTISR[130]
  PIN INTISR[129]
    DIRECTION INPUT ;
    USE SIGNAL ;
    PORT
      LAYER M2 ;
        RECT MASK 2 503.907000 508.400000 504.136000 508.432000 ;
    END
  END INTISR[129]
  PIN INTISR[128]
    DIRECTION INPUT ;
    USE SIGNAL ;
    PORT
      LAYER M6 ;
        RECT 0.000000 514.260000 0.375000 514.300000 ;
    END
  END INTISR[128]
  PIN INTISR[127]
    DIRECTION INPUT ;
    USE SIGNAL ;
    PORT
      LAYER M8 ;
        RECT 0.000000 514.209000 0.354000 514.271000 ;
    END
  END INTISR[127]
  PIN INTISR[126]
    DIRECTION INPUT ;
    USE SIGNAL ;
    PORT
      LAYER M6 ;
        RECT 503.761000 508.180000 504.136000 508.220000 ;
    END
  END INTISR[126]
  PIN INTISR[125]
    DIRECTION INPUT ;
    USE SIGNAL ;
    PORT
      LAYER M4 ;
        RECT 503.761000 508.180000 504.136000 508.220000 ;
    END
  END INTISR[125]
  PIN INTISR[124]
    DIRECTION INPUT ;
    USE SIGNAL ;
    PORT
      LAYER M2 ;
        RECT MASK 2 503.907000 508.144000 504.136000 508.176000 ;
    END
  END INTISR[124]
  PIN INTISR[123]
    DIRECTION INPUT ;
    USE SIGNAL ;
    PORT
      LAYER M8 ;
        RECT 503.782000 507.937000 504.136000 507.999000 ;
    END
  END INTISR[123]
  PIN INTISR[122]
    DIRECTION INPUT ;
    USE SIGNAL ;
    PORT
      LAYER M2 ;
        RECT MASK 2 503.907000 507.888000 504.136000 507.920000 ;
    END
  END INTISR[122]
  PIN INTISR[121]
    DIRECTION INPUT ;
    USE SIGNAL ;
    PORT
      LAYER M6 ;
        RECT 0.000000 514.420000 0.375000 514.460000 ;
    END
  END INTISR[121]
  PIN INTISR[120]
    DIRECTION INPUT ;
    USE SIGNAL ;
    PORT
      LAYER M6 ;
        RECT 503.761000 507.860000 504.136000 507.900000 ;
    END
  END INTISR[120]
  PIN INTISR[119]
    DIRECTION INPUT ;
    USE SIGNAL ;
    PORT
      LAYER M4 ;
        RECT 503.761000 507.860000 504.136000 507.900000 ;
    END
  END INTISR[119]
  PIN INTISR[118]
    DIRECTION INPUT ;
    USE SIGNAL ;
    PORT
      LAYER M8 ;
        RECT 0.000000 514.465000 0.354000 514.527000 ;
    END
  END INTISR[118]
  PIN INTISR[117]
    DIRECTION INPUT ;
    USE SIGNAL ;
    PORT
      LAYER M2 ;
        RECT MASK 2 503.907000 507.632000 504.136000 507.664000 ;
    END
  END INTISR[117]
  PIN INTISR[116]
    DIRECTION INPUT ;
    USE SIGNAL ;
    PORT
      LAYER M6 ;
        RECT 503.761000 507.540000 504.136000 507.580000 ;
    END
  END INTISR[116]
  PIN INTISR[115]
    DIRECTION INPUT ;
    USE SIGNAL ;
    PORT
      LAYER M6 ;
        RECT 0.000000 514.580000 0.375000 514.620000 ;
    END
  END INTISR[115]
  PIN INTISR[114]
    DIRECTION INPUT ;
    USE SIGNAL ;
    PORT
      LAYER M4 ;
        RECT 503.761000 507.540000 504.136000 507.580000 ;
    END
  END INTISR[114]
  PIN INTISR[113]
    DIRECTION INPUT ;
    USE SIGNAL ;
    PORT
      LAYER M8 ;
        RECT 503.782000 507.425000 504.136000 507.487000 ;
    END
  END INTISR[113]
  PIN INTISR[112]
    DIRECTION INPUT ;
    USE SIGNAL ;
    PORT
      LAYER M2 ;
        RECT MASK 2 503.907000 507.376000 504.136000 507.408000 ;
    END
  END INTISR[112]
  PIN INTISR[111]
    DIRECTION INPUT ;
    USE SIGNAL ;
    PORT
      LAYER M6 ;
        RECT 0.000000 514.740000 0.375000 514.780000 ;
    END
  END INTISR[111]
  PIN INTISR[110]
    DIRECTION INPUT ;
    USE SIGNAL ;
    PORT
      LAYER M8 ;
        RECT 0.000000 514.721000 0.354000 514.783000 ;
    END
  END INTISR[110]
  PIN INTISR[109]
    DIRECTION INPUT ;
    USE SIGNAL ;
    PORT
      LAYER M6 ;
        RECT 503.761000 507.220000 504.136000 507.260000 ;
    END
  END INTISR[109]
  PIN INTISR[108]
    DIRECTION INPUT ;
    USE SIGNAL ;
    PORT
      LAYER M4 ;
        RECT 503.761000 507.220000 504.136000 507.260000 ;
    END
  END INTISR[108]
  PIN INTISR[107]
    DIRECTION INPUT ;
    USE SIGNAL ;
    PORT
      LAYER M2 ;
        RECT MASK 2 503.907000 507.120000 504.136000 507.152000 ;
    END
  END INTISR[107]
  PIN INTISR[106]
    DIRECTION INPUT ;
    USE SIGNAL ;
    PORT
      LAYER M8 ;
        RECT 503.782000 506.913000 504.136000 506.975000 ;
    END
  END INTISR[106]
  PIN INTISR[105]
    DIRECTION INPUT ;
    USE SIGNAL ;
    PORT
      LAYER M6 ;
        RECT 0.000000 514.900000 0.375000 514.940000 ;
    END
  END INTISR[105]
  PIN INTISR[104]
    DIRECTION INPUT ;
    USE SIGNAL ;
    PORT
      LAYER M6 ;
        RECT 503.761000 506.900000 504.136000 506.940000 ;
    END
  END INTISR[104]
  PIN INTISR[103]
    DIRECTION INPUT ;
    USE SIGNAL ;
    PORT
      LAYER M4 ;
        RECT 503.761000 506.900000 504.136000 506.940000 ;
    END
  END INTISR[103]
  PIN INTISR[102]
    DIRECTION INPUT ;
    USE SIGNAL ;
    PORT
      LAYER M2 ;
        RECT MASK 2 503.907000 506.864000 504.136000 506.896000 ;
    END
  END INTISR[102]
  PIN INTISR[101]
    DIRECTION INPUT ;
    USE SIGNAL ;
    PORT
      LAYER M8 ;
        RECT 0.000000 514.977000 0.354000 515.039000 ;
    END
  END INTISR[101]
  PIN INTISR[100]
    DIRECTION INPUT ;
    USE SIGNAL ;
    PORT
      LAYER M4 ;
        RECT 503.761000 508.500000 504.136000 508.540000 ;
    END
  END INTISR[100]
  PIN INTISR[99]
    DIRECTION INPUT ;
    USE SIGNAL ;
    PORT
      LAYER M2 ;
        RECT MASK 2 503.907000 506.608000 504.136000 506.640000 ;
    END
  END INTISR[99]
  PIN INTISR[98]
    DIRECTION INPUT ;
    USE SIGNAL ;
    PORT
      LAYER M6 ;
        RECT 0.000000 515.060000 0.375000 515.100000 ;
    END
  END INTISR[98]
  PIN INTISR[97]
    DIRECTION INPUT ;
    USE SIGNAL ;
    PORT
      LAYER M6 ;
        RECT 503.761000 506.580000 504.136000 506.620000 ;
    END
  END INTISR[97]
  PIN INTISR[96]
    DIRECTION INPUT ;
    USE SIGNAL ;
    PORT
      LAYER M4 ;
        RECT 503.761000 506.580000 504.136000 506.620000 ;
    END
  END INTISR[96]
  PIN INTISR[95]
    DIRECTION INPUT ;
    USE SIGNAL ;
    PORT
      LAYER M8 ;
        RECT 503.782000 506.401000 504.136000 506.463000 ;
    END
  END INTISR[95]
  PIN INTISR[94]
    DIRECTION INPUT ;
    USE SIGNAL ;
    PORT
      LAYER M6 ;
        RECT 0.000000 515.220000 0.375000 515.260000 ;
    END
  END INTISR[94]
  PIN INTISR[93]
    DIRECTION INPUT ;
    USE SIGNAL ;
    PORT
      LAYER M2 ;
        RECT MASK 2 503.907000 506.352000 504.136000 506.384000 ;
    END
  END INTISR[93]
  PIN INTISR[92]
    DIRECTION INPUT ;
    USE SIGNAL ;
    PORT
      LAYER M6 ;
        RECT 503.761000 506.260000 504.136000 506.300000 ;
    END
  END INTISR[92]
  PIN INTISR[91]
    DIRECTION INPUT ;
    USE SIGNAL ;
    PORT
      LAYER M8 ;
        RECT 0.000000 515.233000 0.354000 515.295000 ;
    END
  END INTISR[91]
  PIN INTISR[90]
    DIRECTION INPUT ;
    USE SIGNAL ;
    PORT
      LAYER M4 ;
        RECT 503.761000 506.260000 504.136000 506.300000 ;
    END
  END INTISR[90]
  PIN INTISR[89]
    DIRECTION INPUT ;
    USE SIGNAL ;
    PORT
      LAYER M2 ;
        RECT MASK 2 503.907000 506.096000 504.136000 506.128000 ;
    END
  END INTISR[89]
  PIN INTISR[88]
    DIRECTION INPUT ;
    USE SIGNAL ;
    PORT
      LAYER M6 ;
        RECT 0.000000 515.380000 0.375000 515.420000 ;
    END
  END INTISR[88]
  PIN INTISR[87]
    DIRECTION INPUT ;
    USE SIGNAL ;
    PORT
      LAYER M6 ;
        RECT 503.761000 505.940000 504.136000 505.980000 ;
    END
  END INTISR[87]
  PIN INTISR[86]
    DIRECTION INPUT ;
    USE SIGNAL ;
    PORT
      LAYER M4 ;
        RECT 503.761000 505.940000 504.136000 505.980000 ;
    END
  END INTISR[86]
  PIN INTISR[85]
    DIRECTION INPUT ;
    USE SIGNAL ;
    PORT
      LAYER M8 ;
        RECT 503.782000 505.889000 504.136000 505.951000 ;
    END
  END INTISR[85]
  PIN INTISR[84]
    DIRECTION INPUT ;
    USE SIGNAL ;
    PORT
      LAYER M6 ;
        RECT 0.000000 515.540000 0.375000 515.580000 ;
    END
  END INTISR[84]
  PIN INTISR[83]
    DIRECTION INPUT ;
    USE SIGNAL ;
    PORT
      LAYER M8 ;
        RECT 0.000000 515.489000 0.354000 515.551000 ;
    END
  END INTISR[83]
  PIN INTISR[82]
    DIRECTION INPUT ;
    USE SIGNAL ;
    PORT
      LAYER M2 ;
        RECT MASK 2 503.907000 505.840000 504.136000 505.872000 ;
    END
  END INTISR[82]
  PIN INTISR[81]
    DIRECTION INPUT ;
    USE SIGNAL ;
    PORT
      LAYER M6 ;
        RECT 503.761000 505.620000 504.136000 505.660000 ;
    END
  END INTISR[81]
  PIN INTISR[80]
    DIRECTION INPUT ;
    USE SIGNAL ;
    PORT
      LAYER M4 ;
        RECT 503.761000 505.620000 504.136000 505.660000 ;
    END
  END INTISR[80]
  PIN INTISR[79]
    DIRECTION INPUT ;
    USE SIGNAL ;
    PORT
      LAYER M2 ;
        RECT MASK 2 503.907000 505.584000 504.136000 505.616000 ;
    END
  END INTISR[79]
  PIN INTISR[78]
    DIRECTION INPUT ;
    USE SIGNAL ;
    PORT
      LAYER M8 ;
        RECT 503.782000 505.377000 504.136000 505.439000 ;
    END
  END INTISR[78]
  PIN INTISR[77]
    DIRECTION INPUT ;
    USE SIGNAL ;
    PORT
      LAYER M6 ;
        RECT 0.000000 515.700000 0.375000 515.740000 ;
    END
  END INTISR[77]
  PIN INTISR[76]
    DIRECTION INPUT ;
    USE SIGNAL ;
    PORT
      LAYER M2 ;
        RECT MASK 2 503.907000 505.328000 504.136000 505.360000 ;
    END
  END INTISR[76]
  PIN INTISR[75]
    DIRECTION INPUT ;
    USE SIGNAL ;
    PORT
      LAYER M6 ;
        RECT 503.761000 505.300000 504.136000 505.340000 ;
    END
  END INTISR[75]
  PIN INTISR[74]
    DIRECTION INPUT ;
    USE SIGNAL ;
    PORT
      LAYER M8 ;
        RECT 0.000000 515.745000 0.354000 515.807000 ;
    END
  END INTISR[74]
  PIN INTISR[73]
    DIRECTION INPUT ;
    USE SIGNAL ;
    PORT
      LAYER M4 ;
        RECT 503.761000 505.300000 504.136000 505.340000 ;
    END
  END INTISR[73]
  PIN INTISR[72]
    DIRECTION INPUT ;
    USE SIGNAL ;
    PORT
      LAYER M2 ;
        RECT MASK 2 503.907000 505.072000 504.136000 505.104000 ;
    END
  END INTISR[72]
  PIN INTISR[71]
    DIRECTION INPUT ;
    USE SIGNAL ;
    PORT
      LAYER M6 ;
        RECT 0.000000 515.860000 0.375000 515.900000 ;
    END
  END INTISR[71]
  PIN INTISR[70]
    DIRECTION INPUT ;
    USE SIGNAL ;
    PORT
      LAYER M6 ;
        RECT 503.761000 504.980000 504.136000 505.020000 ;
    END
  END INTISR[70]
  PIN INTISR[69]
    DIRECTION INPUT ;
    USE SIGNAL ;
    PORT
      LAYER M4 ;
        RECT 503.761000 504.980000 504.136000 505.020000 ;
    END
  END INTISR[69]
  PIN INTISR[68]
    DIRECTION INPUT ;
    USE SIGNAL ;
    PORT
      LAYER M2 ;
        RECT MASK 2 503.907000 504.816000 504.136000 504.848000 ;
    END
  END INTISR[68]
  PIN INTISR[67]
    DIRECTION INPUT ;
    USE SIGNAL ;
    PORT
      LAYER M6 ;
        RECT 0.000000 516.020000 0.375000 516.060000 ;
    END
  END INTISR[67]
  PIN INTISR[66]
    DIRECTION INPUT ;
    USE SIGNAL ;
    PORT
      LAYER M8 ;
        RECT 0.000000 516.001000 0.354000 516.063000 ;
    END
  END INTISR[66]
  PIN INTISR[65]
    DIRECTION INPUT ;
    USE SIGNAL ;
    PORT
      LAYER M6 ;
        RECT 503.761000 504.660000 504.136000 504.700000 ;
    END
  END INTISR[65]
  PIN INTISR[64]
    DIRECTION INPUT ;
    USE SIGNAL ;
    PORT
      LAYER M4 ;
        RECT 503.761000 504.660000 504.136000 504.700000 ;
    END
  END INTISR[64]
  PIN INTISR[63]
    DIRECTION INPUT ;
    USE SIGNAL ;
    PORT
      LAYER M2 ;
        RECT MASK 2 503.907000 504.560000 504.136000 504.592000 ;
    END
  END INTISR[63]
  PIN INTISR[62]
    DIRECTION INPUT ;
    USE SIGNAL ;
    PORT
      LAYER M8 ;
        RECT 503.782000 504.353000 504.136000 504.415000 ;
    END
  END INTISR[62]
  PIN INTISR[61]
    DIRECTION INPUT ;
    USE SIGNAL ;
    PORT
      LAYER M6 ;
        RECT 0.000000 516.180000 0.375000 516.220000 ;
    END
  END INTISR[61]
  PIN INTISR[60]
    DIRECTION INPUT ;
    USE SIGNAL ;
    PORT
      LAYER M6 ;
        RECT 503.761000 504.340000 504.136000 504.380000 ;
    END
  END INTISR[60]
  PIN INTISR[59]
    DIRECTION INPUT ;
    USE SIGNAL ;
    PORT
      LAYER M4 ;
        RECT 503.761000 504.340000 504.136000 504.380000 ;
    END
  END INTISR[59]
  PIN INTISR[58]
    DIRECTION INPUT ;
    USE SIGNAL ;
    PORT
      LAYER M2 ;
        RECT MASK 2 503.907000 504.304000 504.136000 504.336000 ;
    END
  END INTISR[58]
  PIN INTISR[57]
    DIRECTION INPUT ;
    USE SIGNAL ;
    PORT
      LAYER M8 ;
        RECT 0.000000 516.257000 0.354000 516.319000 ;
    END
  END INTISR[57]
  PIN INTISR[56]
    DIRECTION INPUT ;
    USE SIGNAL ;
    PORT
      LAYER M2 ;
        RECT MASK 2 503.907000 504.048000 504.136000 504.080000 ;
    END
  END INTISR[56]
  PIN INTISR[55]
    DIRECTION INPUT ;
    USE SIGNAL ;
    PORT
      LAYER M6 ;
        RECT 503.761000 504.020000 504.136000 504.060000 ;
    END
  END INTISR[55]
  PIN INTISR[54]
    DIRECTION INPUT ;
    USE SIGNAL ;
    PORT
      LAYER M6 ;
        RECT 0.000000 516.340000 0.375000 516.380000 ;
    END
  END INTISR[54]
  PIN INTISR[53]
    DIRECTION INPUT ;
    USE SIGNAL ;
    PORT
      LAYER M4 ;
        RECT 503.761000 504.020000 504.136000 504.060000 ;
    END
  END INTISR[53]
  PIN INTISR[52]
    DIRECTION INPUT ;
    USE SIGNAL ;
    PORT
      LAYER M8 ;
        RECT 503.782000 503.841000 504.136000 503.903000 ;
    END
  END INTISR[52]
  PIN INTISR[51]
    DIRECTION INPUT ;
    USE SIGNAL ;
    PORT
      LAYER M2 ;
        RECT MASK 2 503.907000 503.792000 504.136000 503.824000 ;
    END
  END INTISR[51]
  PIN INTISR[50]
    DIRECTION INPUT ;
    USE SIGNAL ;
    PORT
      LAYER M6 ;
        RECT 0.000000 516.500000 0.375000 516.540000 ;
    END
  END INTISR[50]
  PIN INTISR[49]
    DIRECTION INPUT ;
    USE SIGNAL ;
    PORT
      LAYER M6 ;
        RECT 503.761000 503.700000 504.136000 503.740000 ;
    END
  END INTISR[49]
  PIN INTISR[48]
    DIRECTION INPUT ;
    USE SIGNAL ;
    PORT
      LAYER M4 ;
        RECT 503.761000 503.700000 504.136000 503.740000 ;
    END
  END INTISR[48]
  PIN INTISR[47]
    DIRECTION INPUT ;
    USE SIGNAL ;
    PORT
      LAYER M8 ;
        RECT 0.000000 516.513000 0.354000 516.575000 ;
    END
  END INTISR[47]
  PIN INTISR[46]
    DIRECTION INPUT ;
    USE SIGNAL ;
    PORT
      LAYER M2 ;
        RECT MASK 2 503.907000 503.536000 504.136000 503.568000 ;
    END
  END INTISR[46]
  PIN INTISR[45]
    DIRECTION INPUT ;
    USE SIGNAL ;
    PORT
      LAYER M6 ;
        RECT 503.761000 503.380000 504.136000 503.420000 ;
    END
  END INTISR[45]
  PIN INTISR[44]
    DIRECTION INPUT ;
    USE SIGNAL ;
    PORT
      LAYER M6 ;
        RECT 0.000000 516.660000 0.375000 516.700000 ;
    END
  END INTISR[44]
  PIN INTISR[43]
    DIRECTION INPUT ;
    USE SIGNAL ;
    PORT
      LAYER M4 ;
        RECT 503.761000 503.380000 504.136000 503.420000 ;
    END
  END INTISR[43]
  PIN INTISR[42]
    DIRECTION INPUT ;
    USE SIGNAL ;
    PORT
      LAYER M8 ;
        RECT 503.782000 503.329000 504.136000 503.391000 ;
    END
  END INTISR[42]
  PIN INTISR[41]
    DIRECTION INPUT ;
    USE SIGNAL ;
    PORT
      LAYER M2 ;
        RECT MASK 2 503.907000 503.280000 504.136000 503.312000 ;
    END
  END INTISR[41]
  PIN INTISR[40]
    DIRECTION INPUT ;
    USE SIGNAL ;
    PORT
      LAYER M6 ;
        RECT 0.000000 516.820000 0.375000 516.860000 ;
    END
  END INTISR[40]
  PIN INTISR[39]
    DIRECTION INPUT ;
    USE SIGNAL ;
    PORT
      LAYER M8 ;
        RECT 0.000000 516.769000 0.354000 516.831000 ;
    END
  END INTISR[39]
  PIN INTISR[38]
    DIRECTION INPUT ;
    USE SIGNAL ;
    PORT
      LAYER M6 ;
        RECT 503.761000 503.060000 504.136000 503.100000 ;
    END
  END INTISR[38]
  PIN INTISR[37]
    DIRECTION INPUT ;
    USE SIGNAL ;
    PORT
      LAYER M4 ;
        RECT 503.761000 503.060000 504.136000 503.100000 ;
    END
  END INTISR[37]
  PIN INTISR[36]
    DIRECTION INPUT ;
    USE SIGNAL ;
    PORT
      LAYER M8 ;
        RECT 503.782000 504.865000 504.136000 504.927000 ;
    END
  END INTISR[36]
  PIN INTISR[35]
    DIRECTION INPUT ;
    USE SIGNAL ;
    PORT
      LAYER M2 ;
        RECT MASK 2 503.907000 503.024000 504.136000 503.056000 ;
    END
  END INTISR[35]
  PIN INTISR[34]
    DIRECTION INPUT ;
    USE SIGNAL ;
    PORT
      LAYER M8 ;
        RECT 503.782000 502.817000 504.136000 502.879000 ;
    END
  END INTISR[34]
  PIN INTISR[33]
    DIRECTION INPUT ;
    USE SIGNAL ;
    PORT
      LAYER M6 ;
        RECT 0.000000 516.980000 0.375000 517.020000 ;
    END
  END INTISR[33]
  PIN INTISR[32]
    DIRECTION INPUT ;
    USE SIGNAL ;
    PORT
      LAYER M2 ;
        RECT MASK 2 503.907000 502.768000 504.136000 502.800000 ;
    END
  END INTISR[32]
  PIN INTISR[31]
    DIRECTION INPUT ;
    USE SIGNAL ;
    PORT
      LAYER M6 ;
        RECT 503.761000 502.740000 504.136000 502.780000 ;
    END
  END INTISR[31]
  PIN INTISR[30]
    DIRECTION INPUT ;
    USE SIGNAL ;
    PORT
      LAYER M8 ;
        RECT 0.000000 517.025000 0.354000 517.087000 ;
    END
  END INTISR[30]
  PIN INTISR[29]
    DIRECTION INPUT ;
    USE SIGNAL ;
    PORT
      LAYER M4 ;
        RECT 503.761000 502.740000 504.136000 502.780000 ;
    END
  END INTISR[29]
  PIN INTISR[28]
    DIRECTION INPUT ;
    USE SIGNAL ;
    PORT
      LAYER M2 ;
        RECT MASK 2 503.907000 502.512000 504.136000 502.544000 ;
    END
  END INTISR[28]
  PIN INTISR[27]
    DIRECTION INPUT ;
    USE SIGNAL ;
    PORT
      LAYER M6 ;
        RECT 0.000000 517.140000 0.375000 517.180000 ;
    END
  END INTISR[27]
  PIN INTISR[26]
    DIRECTION INPUT ;
    USE SIGNAL ;
    PORT
      LAYER M6 ;
        RECT 503.761000 502.420000 504.136000 502.460000 ;
    END
  END INTISR[26]
  PIN INTISR[25]
    DIRECTION INPUT ;
    USE SIGNAL ;
    PORT
      LAYER M4 ;
        RECT 503.761000 502.420000 504.136000 502.460000 ;
    END
  END INTISR[25]
  PIN INTISR[24]
    DIRECTION INPUT ;
    USE SIGNAL ;
    PORT
      LAYER M8 ;
        RECT 503.782000 502.305000 504.136000 502.367000 ;
    END
  END INTISR[24]
  PIN INTISR[23]
    DIRECTION INPUT ;
    USE SIGNAL ;
    PORT
      LAYER M6 ;
        RECT 0.000000 517.300000 0.375000 517.340000 ;
    END
  END INTISR[23]
  PIN INTISR[22]
    DIRECTION INPUT ;
    USE SIGNAL ;
    PORT
      LAYER M8 ;
        RECT 0.000000 517.281000 0.354000 517.343000 ;
    END
  END INTISR[22]
  PIN INTISR[21]
    DIRECTION INPUT ;
    USE SIGNAL ;
    PORT
      LAYER M2 ;
        RECT MASK 2 503.907000 502.256000 504.136000 502.288000 ;
    END
  END INTISR[21]
  PIN INTISR[20]
    DIRECTION INPUT ;
    USE SIGNAL ;
    PORT
      LAYER M6 ;
        RECT 503.761000 502.100000 504.136000 502.140000 ;
    END
  END INTISR[20]
  PIN INTISR[19]
    DIRECTION INPUT ;
    USE SIGNAL ;
    PORT
      LAYER M4 ;
        RECT 503.761000 502.100000 504.136000 502.140000 ;
    END
  END INTISR[19]
  PIN INTISR[18]
    DIRECTION INPUT ;
    USE SIGNAL ;
    PORT
      LAYER M2 ;
        RECT MASK 2 503.907000 502.000000 504.136000 502.032000 ;
    END
  END INTISR[18]
  PIN INTISR[17]
    DIRECTION INPUT ;
    USE SIGNAL ;
    PORT
      LAYER M6 ;
        RECT 0.000000 517.460000 0.375000 517.500000 ;
    END
  END INTISR[17]
  PIN INTISR[16]
    DIRECTION INPUT ;
    USE SIGNAL ;
    PORT
      LAYER M8 ;
        RECT 503.782000 501.793000 504.136000 501.855000 ;
    END
  END INTISR[16]
  PIN INTISR[15]
    DIRECTION INPUT ;
    USE SIGNAL ;
    PORT
      LAYER M2 ;
        RECT MASK 2 503.907000 513.648000 504.136000 513.680000 ;
    END
  END INTISR[15]
  PIN INTISR[14]
    DIRECTION INPUT ;
    USE SIGNAL ;
    PORT
      LAYER M6 ;
        RECT 503.761000 515.780000 504.136000 515.820000 ;
    END
  END INTISR[14]
  PIN INTISR[13]
    DIRECTION INPUT ;
    USE SIGNAL ;
    PORT
      LAYER M8 ;
        RECT 0.000000 517.537000 0.354000 517.599000 ;
    END
  END INTISR[13]
  PIN INTISR[12]
    DIRECTION INPUT ;
    USE SIGNAL ;
    PORT
      LAYER M4 ;
        RECT 503.761000 515.780000 504.136000 515.820000 ;
    END
  END INTISR[12]
  PIN INTISR[11]
    DIRECTION INPUT ;
    USE SIGNAL ;
    PORT
      LAYER M6 ;
        RECT 503.761000 517.060000 504.136000 517.100000 ;
    END
  END INTISR[11]
  PIN INTISR[10]
    DIRECTION INPUT ;
    USE SIGNAL ;
    PORT
      LAYER M6 ;
        RECT 0.000000 517.620000 0.375000 517.660000 ;
    END
  END INTISR[10]
  PIN INTISR[9]
    DIRECTION INPUT ;
    USE SIGNAL ;
    PORT
      LAYER M2 ;
        RECT MASK 2 503.907000 516.464000 504.136000 516.496000 ;
    END
  END INTISR[9]
  PIN INTISR[8]
    DIRECTION INPUT ;
    USE SIGNAL ;
    PORT
      LAYER M4 ;
        RECT 503.761000 517.060000 504.136000 517.100000 ;
    END
  END INTISR[8]
  PIN INTISR[7]
    DIRECTION INPUT ;
    USE SIGNAL ;
    PORT
      LAYER M6 ;
        RECT 503.761000 517.860000 504.136000 517.900000 ;
    END
  END INTISR[7]
  PIN INTISR[6]
    DIRECTION INPUT ;
    USE SIGNAL ;
    PORT
      LAYER M6 ;
        RECT 0.000000 517.780000 0.375000 517.820000 ;
    END
  END INTISR[6]
  PIN INTISR[5]
    DIRECTION INPUT ;
    USE SIGNAL ;
    PORT
      LAYER M6 ;
        RECT 503.761000 518.500000 504.136000 518.540000 ;
    END
  END INTISR[5]
  PIN INTISR[4]
    DIRECTION INPUT ;
    USE SIGNAL ;
    PORT
      LAYER M2 ;
        RECT MASK 2 503.907000 516.720000 504.136000 516.752000 ;
    END
  END INTISR[4]
  PIN INTISR[3]
    DIRECTION INPUT ;
    USE SIGNAL ;
    PORT
      LAYER M8 ;
        RECT 0.000000 517.793000 0.354000 517.855000 ;
    END
  END INTISR[3]
  PIN INTISR[2]
    DIRECTION INPUT ;
    USE SIGNAL ;
    PORT
      LAYER M2 ;
        RECT MASK 2 503.907000 519.152000 504.136000 519.184000 ;
    END
  END INTISR[2]
  PIN INTISR[1]
    DIRECTION INPUT ;
    USE SIGNAL ;
    PORT
      LAYER M4 ;
        RECT 503.761000 516.180000 504.136000 516.220000 ;
    END
  END INTISR[1]
  PIN INTISR[0]
    DIRECTION INPUT ;
    USE SIGNAL ;
    PORT
      LAYER M6 ;
        RECT 0.000000 517.940000 0.375000 517.980000 ;
    END
  END INTISR[0]
  PIN INTNMI
    DIRECTION INPUT ;
    USE SIGNAL ;
    PORT
      LAYER M6 ;
        RECT 503.761000 519.540000 504.136000 519.580000 ;
    END
  END INTNMI
  PIN HREADYI
    DIRECTION INPUT ;
    USE SIGNAL ;
    PORT
      LAYER M6 ;
        RECT 503.761000 520.500000 504.136000 520.540000 ;
    END
  END HREADYI
  PIN HRDATAI[31]
    DIRECTION INPUT ;
    USE SIGNAL ;
    PORT
      LAYER M4 ;
        RECT 503.761000 542.420000 504.136000 542.460000 ;
    END
  END HRDATAI[31]
  PIN HRDATAI[30]
    DIRECTION INPUT ;
    USE SIGNAL ;
    PORT
      LAYER M8 ;
        RECT 503.782000 542.369000 504.136000 542.431000 ;
    END
  END HRDATAI[30]
  PIN HRDATAI[29]
    DIRECTION INPUT ;
    USE SIGNAL ;
    PORT
      LAYER M6 ;
        RECT 0.000000 506.580000 0.375000 506.620000 ;
    END
  END HRDATAI[29]
  PIN HRDATAI[28]
    DIRECTION INPUT ;
    USE SIGNAL ;
    PORT
      LAYER M2 ;
        RECT MASK 1 503.907000 542.256000 504.136000 542.288000 ;
    END
  END HRDATAI[28]
  PIN HRDATAI[27]
    DIRECTION INPUT ;
    USE SIGNAL ;
    PORT
      LAYER M6 ;
        RECT 503.761000 542.180000 504.136000 542.220000 ;
    END
  END HRDATAI[27]
  PIN HRDATAI[26]
    DIRECTION INPUT ;
    USE SIGNAL ;
    PORT
      LAYER M4 ;
        RECT 503.761000 542.100000 504.136000 542.140000 ;
    END
  END HRDATAI[26]
  PIN HRDATAI[25]
    DIRECTION INPUT ;
    USE SIGNAL ;
    PORT
      LAYER M8 ;
        RECT 0.000000 506.657000 0.354000 506.719000 ;
    END
  END HRDATAI[25]
  PIN HRDATAI[24]
    DIRECTION INPUT ;
    USE SIGNAL ;
    PORT
      LAYER M2 ;
        RECT MASK 1 503.907000 542.000000 504.136000 542.032000 ;
    END
  END HRDATAI[24]
  PIN HRDATAI[23]
    DIRECTION INPUT ;
    USE SIGNAL ;
    PORT
      LAYER M8 ;
        RECT 503.782000 541.857000 504.136000 541.919000 ;
    END
  END HRDATAI[23]
  PIN HRDATAI[22]
    DIRECTION INPUT ;
    USE SIGNAL ;
    PORT
      LAYER M6 ;
        RECT 0.000000 506.740000 0.375000 506.780000 ;
    END
  END HRDATAI[22]
  PIN HRDATAI[21]
    DIRECTION INPUT ;
    USE SIGNAL ;
    PORT
      LAYER M6 ;
        RECT 503.761000 541.860000 504.136000 541.900000 ;
    END
  END HRDATAI[21]
  PIN HRDATAI[20]
    DIRECTION INPUT ;
    USE SIGNAL ;
    PORT
      LAYER M4 ;
        RECT 503.761000 541.780000 504.136000 541.820000 ;
    END
  END HRDATAI[20]
  PIN HRDATAI[19]
    DIRECTION INPUT ;
    USE SIGNAL ;
    PORT
      LAYER M2 ;
        RECT MASK 1 503.907000 541.744000 504.136000 541.776000 ;
    END
  END HRDATAI[19]
  PIN HRDATAI[18]
    DIRECTION INPUT ;
    USE SIGNAL ;
    PORT
      LAYER M6 ;
        RECT 0.000000 506.900000 0.375000 506.940000 ;
    END
  END HRDATAI[18]
  PIN HRDATAI[17]
    DIRECTION INPUT ;
    USE SIGNAL ;
    PORT
      LAYER M6 ;
        RECT 503.761000 541.540000 504.136000 541.580000 ;
    END
  END HRDATAI[17]
  PIN HRDATAI[16]
    DIRECTION INPUT ;
    USE SIGNAL ;
    PORT
      LAYER M2 ;
        RECT MASK 1 503.907000 541.488000 504.136000 541.520000 ;
    END
  END HRDATAI[16]
  PIN HRDATAI[15]
    DIRECTION INPUT ;
    USE SIGNAL ;
    PORT
      LAYER M8 ;
        RECT 0.000000 506.913000 0.354000 506.975000 ;
    END
  END HRDATAI[15]
  PIN HRDATAI[14]
    DIRECTION INPUT ;
    USE SIGNAL ;
    PORT
      LAYER M4 ;
        RECT 503.761000 544.340000 504.136000 544.380000 ;
    END
  END HRDATAI[14]
  PIN HRDATAI[13]
    DIRECTION INPUT ;
    USE SIGNAL ;
    PORT
      LAYER M6 ;
        RECT 503.761000 540.580000 504.136000 540.620000 ;
    END
  END HRDATAI[13]
  PIN HRDATAI[12]
    DIRECTION INPUT ;
    USE SIGNAL ;
    PORT
      LAYER M6 ;
        RECT 0.000000 507.060000 0.375000 507.100000 ;
    END
  END HRDATAI[12]
  PIN HRDATAI[11]
    DIRECTION INPUT ;
    USE SIGNAL ;
    PORT
      LAYER M4 ;
        RECT 503.761000 540.500000 504.136000 540.540000 ;
    END
  END HRDATAI[11]
  PIN HRDATAI[10]
    DIRECTION INPUT ;
    USE SIGNAL ;
    PORT
      LAYER M2 ;
        RECT MASK 1 503.907000 540.464000 504.136000 540.496000 ;
    END
  END HRDATAI[10]
  PIN HRDATAI[9]
    DIRECTION INPUT ;
    USE SIGNAL ;
    PORT
      LAYER M8 ;
        RECT 503.782000 540.321000 504.136000 540.383000 ;
    END
  END HRDATAI[9]
  PIN HRDATAI[8]
    DIRECTION INPUT ;
    USE SIGNAL ;
    PORT
      LAYER M6 ;
        RECT 0.000000 507.220000 0.375000 507.260000 ;
    END
  END HRDATAI[8]
  PIN HRDATAI[7]
    DIRECTION INPUT ;
    USE SIGNAL ;
    PORT
      LAYER M8 ;
        RECT 0.000000 507.169000 0.354000 507.231000 ;
    END
  END HRDATAI[7]
  PIN HRDATAI[6]
    DIRECTION INPUT ;
    USE SIGNAL ;
    PORT
      LAYER M6 ;
        RECT 503.761000 540.260000 504.136000 540.300000 ;
    END
  END HRDATAI[6]
  PIN HRDATAI[5]
    DIRECTION INPUT ;
    USE SIGNAL ;
    PORT
      LAYER M2 ;
        RECT MASK 1 503.907000 540.208000 504.136000 540.240000 ;
    END
  END HRDATAI[5]
  PIN HRDATAI[4]
    DIRECTION INPUT ;
    USE SIGNAL ;
    PORT
      LAYER M4 ;
        RECT 503.761000 540.180000 504.136000 540.220000 ;
    END
  END HRDATAI[4]
  PIN HRDATAI[3]
    DIRECTION INPUT ;
    USE SIGNAL ;
    PORT
      LAYER M2 ;
        RECT MASK 1 503.907000 539.952000 504.136000 539.984000 ;
    END
  END HRDATAI[3]
  PIN HRDATAI[2]
    DIRECTION INPUT ;
    USE SIGNAL ;
    PORT
      LAYER M6 ;
        RECT 503.761000 539.940000 504.136000 539.980000 ;
    END
  END HRDATAI[2]
  PIN HRDATAI[1]
    DIRECTION INPUT ;
    USE SIGNAL ;
    PORT
      LAYER M6 ;
        RECT 0.000000 507.380000 0.375000 507.420000 ;
    END
  END HRDATAI[1]
  PIN HRDATAI[0]
    DIRECTION INPUT ;
    USE SIGNAL ;
    PORT
      LAYER M4 ;
        RECT 503.761000 539.860000 504.136000 539.900000 ;
    END
  END HRDATAI[0]
  PIN HRESPI[1]
    DIRECTION INPUT ;
    USE SIGNAL ;
    PORT
      LAYER M2 ;
        RECT MASK 1 503.907000 538.928000 504.136000 538.960000 ;
    END
  END HRESPI[1]
  PIN HRESPI[0]
    DIRECTION INPUT ;
    USE SIGNAL ;
    PORT
      LAYER M4 ;
        RECT 503.761000 538.900000 504.136000 538.940000 ;
    END
  END HRESPI[0]
  PIN IFLUSH
    DIRECTION INPUT ;
    USE SIGNAL ;
    PORT
      LAYER M6 ;
        RECT 503.761000 519.860000 504.136000 519.900000 ;
    END
  END IFLUSH
  PIN HREADYD
    DIRECTION INPUT ;
    USE SIGNAL ;
    PORT
      LAYER M4 ;
        RECT 503.761000 519.540000 504.136000 519.580000 ;
    END
  END HREADYD
  PIN HRDATAD[31]
    DIRECTION INPUT ;
    USE SIGNAL ;
    PORT
      LAYER M2 ;
        RECT MASK 1 503.907000 544.304000 504.136000 544.336000 ;
    END
  END HRDATAD[31]
  PIN HRDATAD[30]
    DIRECTION INPUT ;
    USE SIGNAL ;
    PORT
      LAYER M6 ;
        RECT 0.000000 505.620000 0.375000 505.660000 ;
    END
  END HRDATAD[30]
  PIN HRDATAD[29]
    DIRECTION INPUT ;
    USE SIGNAL ;
    PORT
      LAYER M8 ;
        RECT 503.782000 544.161000 504.136000 544.223000 ;
    END
  END HRDATAD[29]
  PIN HRDATAD[28]
    DIRECTION INPUT ;
    USE SIGNAL ;
    PORT
      LAYER M6 ;
        RECT 503.761000 544.100000 504.136000 544.140000 ;
    END
  END HRDATAD[28]
  PIN HRDATAD[27]
    DIRECTION INPUT ;
    USE SIGNAL ;
    PORT
      LAYER M8 ;
        RECT 0.000000 505.633000 0.354000 505.695000 ;
    END
  END HRDATAD[27]
  PIN HRDATAD[26]
    DIRECTION INPUT ;
    USE SIGNAL ;
    PORT
      LAYER M2 ;
        RECT MASK 1 503.907000 544.048000 504.136000 544.080000 ;
    END
  END HRDATAD[26]
  PIN HRDATAD[25]
    DIRECTION INPUT ;
    USE SIGNAL ;
    PORT
      LAYER M4 ;
        RECT 503.761000 544.020000 504.136000 544.060000 ;
    END
  END HRDATAD[25]
  PIN HRDATAD[24]
    DIRECTION INPUT ;
    USE SIGNAL ;
    PORT
      LAYER M6 ;
        RECT 0.000000 505.780000 0.375000 505.820000 ;
    END
  END HRDATAD[24]
  PIN HRDATAD[23]
    DIRECTION INPUT ;
    USE SIGNAL ;
    PORT
      LAYER M2 ;
        RECT MASK 1 503.907000 543.792000 504.136000 543.824000 ;
    END
  END HRDATAD[23]
  PIN HRDATAD[22]
    DIRECTION INPUT ;
    USE SIGNAL ;
    PORT
      LAYER M6 ;
        RECT 503.761000 543.780000 504.136000 543.820000 ;
    END
  END HRDATAD[22]
  PIN HRDATAD[21]
    DIRECTION INPUT ;
    USE SIGNAL ;
    PORT
      LAYER M4 ;
        RECT 503.761000 543.700000 504.136000 543.740000 ;
    END
  END HRDATAD[21]
  PIN HRDATAD[20]
    DIRECTION INPUT ;
    USE SIGNAL ;
    PORT
      LAYER M6 ;
        RECT 0.000000 505.940000 0.375000 505.980000 ;
    END
  END HRDATAD[20]
  PIN HRDATAD[19]
    DIRECTION INPUT ;
    USE SIGNAL ;
    PORT
      LAYER M8 ;
        RECT 0.000000 505.889000 0.354000 505.951000 ;
    END
  END HRDATAD[19]
  PIN HRDATAD[18]
    DIRECTION INPUT ;
    USE SIGNAL ;
    PORT
      LAYER M2 ;
        RECT MASK 1 503.907000 543.536000 504.136000 543.568000 ;
    END
  END HRDATAD[18]
  PIN HRDATAD[17]
    DIRECTION INPUT ;
    USE SIGNAL ;
    PORT
      LAYER M6 ;
        RECT 503.761000 543.460000 504.136000 543.500000 ;
    END
  END HRDATAD[17]
  PIN HRDATAD[16]
    DIRECTION INPUT ;
    USE SIGNAL ;
    PORT
      LAYER M4 ;
        RECT 503.761000 543.380000 504.136000 543.420000 ;
    END
  END HRDATAD[16]
  PIN HRDATAD[15]
    DIRECTION INPUT ;
    USE SIGNAL ;
    PORT
      LAYER M2 ;
        RECT MASK 1 503.907000 543.280000 504.136000 543.312000 ;
    END
  END HRDATAD[15]
  PIN HRDATAD[14]
    DIRECTION INPUT ;
    USE SIGNAL ;
    PORT
      LAYER M4 ;
        RECT 503.761000 541.460000 504.136000 541.500000 ;
    END
  END HRDATAD[14]
  PIN HRDATAD[13]
    DIRECTION INPUT ;
    USE SIGNAL ;
    PORT
      LAYER M6 ;
        RECT 0.000000 506.100000 0.375000 506.140000 ;
    END
  END HRDATAD[13]
  PIN HRDATAD[12]
    DIRECTION INPUT ;
    USE SIGNAL ;
    PORT
      LAYER M8 ;
        RECT 503.782000 541.345000 504.136000 541.407000 ;
    END
  END HRDATAD[12]
  PIN HRDATAD[11]
    DIRECTION INPUT ;
    USE SIGNAL ;
    PORT
      LAYER M2 ;
        RECT MASK 1 503.907000 541.232000 504.136000 541.264000 ;
    END
  END HRDATAD[11]
  PIN HRDATAD[10]
    DIRECTION INPUT ;
    USE SIGNAL ;
    PORT
      LAYER M8 ;
        RECT 0.000000 506.145000 0.354000 506.207000 ;
    END
  END HRDATAD[10]
  PIN HRDATAD[9]
    DIRECTION INPUT ;
    USE SIGNAL ;
    PORT
      LAYER M6 ;
        RECT 503.761000 541.220000 504.136000 541.260000 ;
    END
  END HRDATAD[9]
  PIN HRDATAD[8]
    DIRECTION INPUT ;
    USE SIGNAL ;
    PORT
      LAYER M4 ;
        RECT 503.761000 541.140000 504.136000 541.180000 ;
    END
  END HRDATAD[8]
  PIN HRDATAD[7]
    DIRECTION INPUT ;
    USE SIGNAL ;
    PORT
      LAYER M6 ;
        RECT 0.000000 506.260000 0.375000 506.300000 ;
    END
  END HRDATAD[7]
  PIN HRDATAD[6]
    DIRECTION INPUT ;
    USE SIGNAL ;
    PORT
      LAYER M2 ;
        RECT MASK 1 503.907000 540.976000 504.136000 541.008000 ;
    END
  END HRDATAD[6]
  PIN HRDATAD[5]
    DIRECTION INPUT ;
    USE SIGNAL ;
    PORT
      LAYER M6 ;
        RECT 503.761000 540.900000 504.136000 540.940000 ;
    END
  END HRDATAD[5]
  PIN HRDATAD[4]
    DIRECTION INPUT ;
    USE SIGNAL ;
    PORT
      LAYER M8 ;
        RECT 503.782000 540.833000 504.136000 540.895000 ;
    END
  END HRDATAD[4]
  PIN HRDATAD[3]
    DIRECTION INPUT ;
    USE SIGNAL ;
    PORT
      LAYER M6 ;
        RECT 0.000000 506.420000 0.375000 506.460000 ;
    END
  END HRDATAD[3]
  PIN HRDATAD[2]
    DIRECTION INPUT ;
    USE SIGNAL ;
    PORT
      LAYER M8 ;
        RECT 0.000000 506.401000 0.354000 506.463000 ;
    END
  END HRDATAD[2]
  PIN HRDATAD[1]
    DIRECTION INPUT ;
    USE SIGNAL ;
    PORT
      LAYER M4 ;
        RECT 503.761000 540.820000 504.136000 540.860000 ;
    END
  END HRDATAD[1]
  PIN HRDATAD[0]
    DIRECTION INPUT ;
    USE SIGNAL ;
    PORT
      LAYER M2 ;
        RECT MASK 1 503.907000 540.720000 504.136000 540.752000 ;
    END
  END HRDATAD[0]
  PIN HRESPD[1]
    DIRECTION INPUT ;
    USE SIGNAL ;
    PORT
      LAYER M8 ;
        RECT 503.782000 538.785000 504.136000 538.847000 ;
    END
  END HRESPD[1]
  PIN HRESPD[0]
    DIRECTION INPUT ;
    USE SIGNAL ;
    PORT
      LAYER M6 ;
        RECT 0.000000 508.500000 0.375000 508.540000 ;
    END
  END HRESPD[0]
  PIN EXRESPD
    DIRECTION INPUT ;
    USE SIGNAL ;
    PORT
      LAYER M6 ;
        RECT 0.000000 519.540000 0.375000 519.580000 ;
    END
  END EXRESPD
  PIN SE
    DIRECTION INPUT ;
    USE SIGNAL ;
    PORT
      LAYER M2 ;
        RECT MASK 2 503.907000 501.744000 504.136000 501.776000 ;
    END
  END SE
  PIN HREADYS
    DIRECTION INPUT ;
    USE SIGNAL ;
    PORT
      LAYER M2 ;
        RECT MASK 2 503.907000 519.664000 504.136000 519.696000 ;
    END
  END HREADYS
  PIN HRDATAS[31]
    DIRECTION INPUT ;
    USE SIGNAL ;
    PORT
      LAYER M8 ;
        RECT 503.782000 539.809000 504.136000 539.871000 ;
    END
  END HRDATAS[31]
  PIN HRDATAS[30]
    DIRECTION INPUT ;
    USE SIGNAL ;
    PORT
      LAYER M8 ;
        RECT 0.000000 507.425000 0.354000 507.487000 ;
    END
  END HRDATAS[30]
  PIN HRDATAS[29]
    DIRECTION INPUT ;
    USE SIGNAL ;
    PORT
      LAYER M2 ;
        RECT MASK 1 503.907000 539.696000 504.136000 539.728000 ;
    END
  END HRDATAS[29]
  PIN HRDATAS[28]
    DIRECTION INPUT ;
    USE SIGNAL ;
    PORT
      LAYER M6 ;
        RECT 503.761000 539.620000 504.136000 539.660000 ;
    END
  END HRDATAS[28]
  PIN HRDATAS[27]
    DIRECTION INPUT ;
    USE SIGNAL ;
    PORT
      LAYER M6 ;
        RECT 0.000000 507.540000 0.375000 507.580000 ;
    END
  END HRDATAS[27]
  PIN HRDATAS[26]
    DIRECTION INPUT ;
    USE SIGNAL ;
    PORT
      LAYER M4 ;
        RECT 503.761000 539.540000 504.136000 539.580000 ;
    END
  END HRDATAS[26]
  PIN HRDATAS[25]
    DIRECTION INPUT ;
    USE SIGNAL ;
    PORT
      LAYER M2 ;
        RECT MASK 1 503.907000 539.440000 504.136000 539.472000 ;
    END
  END HRDATAS[25]
  PIN HRDATAS[24]
    DIRECTION INPUT ;
    USE SIGNAL ;
    PORT
      LAYER M8 ;
        RECT 503.782000 539.297000 504.136000 539.359000 ;
    END
  END HRDATAS[24]
  PIN HRDATAS[23]
    DIRECTION INPUT ;
    USE SIGNAL ;
    PORT
      LAYER M6 ;
        RECT 0.000000 507.700000 0.375000 507.740000 ;
    END
  END HRDATAS[23]
  PIN HRDATAS[22]
    DIRECTION INPUT ;
    USE SIGNAL ;
    PORT
      LAYER M8 ;
        RECT 0.000000 507.681000 0.354000 507.743000 ;
    END
  END HRDATAS[22]
  PIN HRDATAS[21]
    DIRECTION INPUT ;
    USE SIGNAL ;
    PORT
      LAYER M6 ;
        RECT 503.761000 539.300000 504.136000 539.340000 ;
    END
  END HRDATAS[21]
  PIN HRDATAS[20]
    DIRECTION INPUT ;
    USE SIGNAL ;
    PORT
      LAYER M4 ;
        RECT 503.761000 539.220000 504.136000 539.260000 ;
    END
  END HRDATAS[20]
  PIN HRDATAS[19]
    DIRECTION INPUT ;
    USE SIGNAL ;
    PORT
      LAYER M2 ;
        RECT MASK 1 503.907000 539.184000 504.136000 539.216000 ;
    END
  END HRDATAS[19]
  PIN HRDATAS[18]
    DIRECTION INPUT ;
    USE SIGNAL ;
    PORT
      LAYER M6 ;
        RECT 503.761000 538.980000 504.136000 539.020000 ;
    END
  END HRDATAS[18]
  PIN HRDATAS[17]
    DIRECTION INPUT ;
    USE SIGNAL ;
    PORT
      LAYER M6 ;
        RECT 0.000000 507.860000 0.375000 507.900000 ;
    END
  END HRDATAS[17]
  PIN HRDATAS[16]
    DIRECTION INPUT ;
    USE SIGNAL ;
    PORT
      LAYER M2 ;
        RECT MASK 1 503.907000 538.672000 504.136000 538.704000 ;
    END
  END HRDATAS[16]
  PIN HRDATAS[15]
    DIRECTION INPUT ;
    USE SIGNAL ;
    PORT
      LAYER M6 ;
        RECT 503.761000 538.660000 504.136000 538.700000 ;
    END
  END HRDATAS[15]
  PIN HRDATAS[14]
    DIRECTION INPUT ;
    USE SIGNAL ;
    PORT
      LAYER M4 ;
        RECT 503.761000 538.580000 504.136000 538.620000 ;
    END
  END HRDATAS[14]
  PIN HRDATAS[13]
    DIRECTION INPUT ;
    USE SIGNAL ;
    PORT
      LAYER M8 ;
        RECT 0.000000 507.937000 0.354000 507.999000 ;
    END
  END HRDATAS[13]
  PIN HRDATAS[12]
    DIRECTION INPUT ;
    USE SIGNAL ;
    PORT
      LAYER M2 ;
        RECT MASK 1 503.907000 538.416000 504.136000 538.448000 ;
    END
  END HRDATAS[12]
  PIN HRDATAS[11]
    DIRECTION INPUT ;
    USE SIGNAL ;
    PORT
      LAYER M6 ;
        RECT 503.761000 538.340000 504.136000 538.380000 ;
    END
  END HRDATAS[11]
  PIN HRDATAS[10]
    DIRECTION INPUT ;
    USE SIGNAL ;
    PORT
      LAYER M6 ;
        RECT 0.000000 508.020000 0.375000 508.060000 ;
    END
  END HRDATAS[10]
  PIN HRDATAS[9]
    DIRECTION INPUT ;
    USE SIGNAL ;
    PORT
      LAYER M8 ;
        RECT 503.782000 538.273000 504.136000 538.335000 ;
    END
  END HRDATAS[9]
  PIN HRDATAS[8]
    DIRECTION INPUT ;
    USE SIGNAL ;
    PORT
      LAYER M4 ;
        RECT 503.761000 538.260000 504.136000 538.300000 ;
    END
  END HRDATAS[8]
  PIN HRDATAS[7]
    DIRECTION INPUT ;
    USE SIGNAL ;
    PORT
      LAYER M2 ;
        RECT MASK 1 503.907000 538.160000 504.136000 538.192000 ;
    END
  END HRDATAS[7]
  PIN HRDATAS[6]
    DIRECTION INPUT ;
    USE SIGNAL ;
    PORT
      LAYER M6 ;
        RECT 0.000000 508.180000 0.375000 508.220000 ;
    END
  END HRDATAS[6]
  PIN HRDATAS[5]
    DIRECTION INPUT ;
    USE SIGNAL ;
    PORT
      LAYER M6 ;
        RECT 503.761000 538.020000 504.136000 538.060000 ;
    END
  END HRDATAS[5]
  PIN HRDATAS[4]
    DIRECTION INPUT ;
    USE SIGNAL ;
    PORT
      LAYER M4 ;
        RECT 503.761000 537.940000 504.136000 537.980000 ;
    END
  END HRDATAS[4]
  PIN HRDATAS[3]
    DIRECTION INPUT ;
    USE SIGNAL ;
    PORT
      LAYER M2 ;
        RECT MASK 1 503.907000 537.904000 504.136000 537.936000 ;
    END
  END HRDATAS[3]
  PIN HRDATAS[2]
    DIRECTION INPUT ;
    USE SIGNAL ;
    PORT
      LAYER M6 ;
        RECT 0.000000 508.340000 0.375000 508.380000 ;
    END
  END HRDATAS[2]
  PIN HRDATAS[1]
    DIRECTION INPUT ;
    USE SIGNAL ;
    PORT
      LAYER M8 ;
        RECT 503.782000 537.761000 504.136000 537.823000 ;
    END
  END HRDATAS[1]
  PIN HRDATAS[0]
    DIRECTION INPUT ;
    USE SIGNAL ;
    PORT
      LAYER M6 ;
        RECT 503.761000 537.700000 504.136000 537.740000 ;
    END
  END HRDATAS[0]
  PIN HRESPS[1]
    DIRECTION INPUT ;
    USE SIGNAL ;
    PORT
      LAYER M2 ;
        RECT MASK 1 503.907000 537.648000 504.136000 537.680000 ;
    END
  END HRESPS[1]
  PIN HRESPS[0]
    DIRECTION INPUT ;
    USE SIGNAL ;
    PORT
      LAYER M4 ;
        RECT 503.761000 537.620000 504.136000 537.660000 ;
    END
  END HRESPS[0]
  PIN EXRESPS
    DIRECTION INPUT ;
    USE SIGNAL ;
    PORT
      LAYER M2 ;
        RECT MASK 2 503.907000 516.208000 504.136000 516.240000 ;
    END
  END EXRESPS
  PIN EDBGRQ
    DIRECTION INPUT ;
    USE SIGNAL ;
    PORT
      LAYER M6 ;
        RECT 0.000000 519.700000 0.375000 519.740000 ;
    END
  END EDBGRQ
  PIN DBGRESTART
    DIRECTION INPUT ;
    USE SIGNAL ;
    PORT
      LAYER M2 ;
        RECT MASK 2 503.907000 519.920000 504.136000 519.952000 ;
    END
  END DBGRESTART
  PIN RXEV
    DIRECTION INPUT ;
    USE SIGNAL ;
    PORT
      LAYER M6 ;
        RECT 503.761000 518.980000 504.136000 519.020000 ;
    END
  END RXEV
  PIN SLEEPHOLDREQn
    DIRECTION INPUT ;
    USE SIGNAL ;
    PORT
      LAYER M4 ;
        RECT 503.761000 520.340000 504.136000 520.380000 ;
    END
  END SLEEPHOLDREQn
  PIN WICENREQ
    DIRECTION INPUT ;
    USE SIGNAL ;
    PORT
      LAYER M6 ;
        RECT 0.000000 519.860000 0.375000 519.900000 ;
    END
  END WICENREQ
  PIN FIXMASTERTYPE
    DIRECTION INPUT ;
    USE SIGNAL ;
    PORT
      LAYER M2 ;
        RECT MASK 2 503.907000 520.560000 504.136000 520.592000 ;
    END
  END FIXMASTERTYPE
  PIN TDO
    DIRECTION OUTPUT ;
    USE SIGNAL ;
    PORT
      LAYER M4 ;
        RECT 503.761000 513.140000 504.136000 513.180000 ;
    END
  END TDO
  PIN nTDOEN
    DIRECTION OUTPUT ;
    USE SIGNAL ;
    PORT
      LAYER M2 ;
        RECT MASK 2 503.907000 515.696000 504.136000 515.728000 ;
    END
  END nTDOEN
  PIN SWDOEN
    DIRECTION OUTPUT ;
    USE SIGNAL ;
    PORT
      LAYER M8 ;
        RECT 503.782000 514.465000 504.136000 514.527000 ;
    END
  END SWDOEN
  PIN SWDO
    DIRECTION OUTPUT ;
    USE SIGNAL ;
    PORT
      LAYER M6 ;
        RECT 0.000000 520.020000 0.375000 520.060000 ;
    END
  END SWDO
  PIN SWV
    DIRECTION OUTPUT ;
    USE SIGNAL ;
    PORT
      LAYER M4 ;
        RECT 503.761000 515.140000 504.136000 515.180000 ;
    END
  END SWV
  PIN JTAGNSW
    DIRECTION OUTPUT ;
    USE SIGNAL ;
    PORT
      LAYER M8 ;
        RECT 503.782000 515.361000 504.136000 515.423000 ;
    END
  END JTAGNSW
  PIN TRACECLK
    DIRECTION OUTPUT ;
    USE SIGNAL ;
    PORT
      LAYER M6 ;
        RECT 503.761000 515.460000 504.136000 515.500000 ;
    END
  END TRACECLK
  PIN TRACEDATA[3]
    DIRECTION OUTPUT ;
    USE SIGNAL ;
    PORT
      LAYER M4 ;
        RECT 503.761000 514.820000 504.136000 514.860000 ;
    END
  END TRACEDATA[3]
  PIN TRACEDATA[2]
    DIRECTION OUTPUT ;
    USE SIGNAL ;
    PORT
      LAYER M2 ;
        RECT MASK 2 503.907000 514.544000 504.136000 514.576000 ;
    END
  END TRACEDATA[2]
  PIN TRACEDATA[1]
    DIRECTION OUTPUT ;
    USE SIGNAL ;
    PORT
      LAYER M8 ;
        RECT 0.000000 518.817000 0.354000 518.879000 ;
    END
  END TRACEDATA[1]
  PIN TRACEDATA[0]
    DIRECTION OUTPUT ;
    USE SIGNAL ;
    PORT
      LAYER M6 ;
        RECT 503.761000 515.140000 504.136000 515.180000 ;
    END
  END TRACEDATA[0]
  PIN HTRANSI[1]
    DIRECTION OUTPUT ;
    USE SIGNAL ;
    PORT
      LAYER M6 ;
        RECT 503.761000 537.060000 504.136000 537.100000 ;
    END
  END HTRANSI[1]
  PIN HTRANSI[0]
    DIRECTION OUTPUT ;
    USE SIGNAL ;
    PORT
      LAYER M2 ;
        RECT MASK 1 503.907000 529.968000 504.136000 530.000000 ;
    END
  END HTRANSI[0]
  PIN HSIZEI[2]
    DIRECTION OUTPUT ;
    USE SIGNAL ;
    PORT
      LAYER M6 ;
        RECT 503.761000 530.020000 504.136000 530.060000 ;
    END
  END HSIZEI[2]
  PIN HSIZEI[1]
    DIRECTION OUTPUT ;
    USE SIGNAL ;
    PORT
      LAYER M4 ;
        RECT 503.761000 530.580000 504.136000 530.620000 ;
    END
  END HSIZEI[1]
  PIN HSIZEI[0]
    DIRECTION OUTPUT ;
    USE SIGNAL ;
    PORT
      LAYER M8 ;
        RECT 503.782000 528.801000 504.136000 528.863000 ;
    END
  END HSIZEI[0]
  PIN HADDRI[31]
    DIRECTION OUTPUT ;
    USE SIGNAL ;
    PORT
      LAYER M8 ;
        RECT 503.782000 526.497000 504.136000 526.559000 ;
    END
  END HADDRI[31]
  PIN HADDRI[30]
    DIRECTION OUTPUT ;
    USE SIGNAL ;
    PORT
      LAYER M6 ;
        RECT 503.761000 527.700000 504.136000 527.740000 ;
    END
  END HADDRI[30]
  PIN HADDRI[29]
    DIRECTION OUTPUT ;
    USE SIGNAL ;
    PORT
      LAYER M2 ;
        RECT MASK 1 503.907000 528.816000 504.136000 528.848000 ;
    END
  END HADDRI[29]
  PIN HADDRI[28]
    DIRECTION OUTPUT ;
    USE SIGNAL ;
    PORT
      LAYER M6 ;
        RECT 503.761000 551.140000 504.136000 551.180000 ;
    END
  END HADDRI[28]
  PIN HADDRI[27]
    DIRECTION OUTPUT ;
    USE SIGNAL ;
    PORT
      LAYER M4 ;
        RECT 503.761000 547.860000 504.136000 547.900000 ;
    END
  END HADDRI[27]
  PIN HADDRI[26]
    DIRECTION OUTPUT ;
    USE SIGNAL ;
    PORT
      LAYER M8 ;
        RECT 503.782000 547.745000 504.136000 547.807000 ;
    END
  END HADDRI[26]
  PIN HADDRI[25]
    DIRECTION OUTPUT ;
    USE SIGNAL ;
    PORT
      LAYER M6 ;
        RECT 0.000000 503.540000 0.375000 503.580000 ;
    END
  END HADDRI[25]
  PIN HADDRI[24]
    DIRECTION OUTPUT ;
    USE SIGNAL ;
    PORT
      LAYER M2 ;
        RECT MASK 1 503.907000 547.632000 504.136000 547.664000 ;
    END
  END HADDRI[24]
  PIN HADDRI[23]
    DIRECTION OUTPUT ;
    USE SIGNAL ;
    PORT
      LAYER M6 ;
        RECT 503.761000 547.620000 504.136000 547.660000 ;
    END
  END HADDRI[23]
  PIN HADDRI[22]
    DIRECTION OUTPUT ;
    USE SIGNAL ;
    PORT
      LAYER M8 ;
        RECT 0.000000 503.585000 0.354000 503.647000 ;
    END
  END HADDRI[22]
  PIN HADDRI[21]
    DIRECTION OUTPUT ;
    USE SIGNAL ;
    PORT
      LAYER M4 ;
        RECT 503.761000 547.540000 504.136000 547.580000 ;
    END
  END HADDRI[21]
  PIN HADDRI[20]
    DIRECTION OUTPUT ;
    USE SIGNAL ;
    PORT
      LAYER M2 ;
        RECT MASK 1 503.907000 547.376000 504.136000 547.408000 ;
    END
  END HADDRI[20]
  PIN HADDRI[19]
    DIRECTION OUTPUT ;
    USE SIGNAL ;
    PORT
      LAYER M6 ;
        RECT 0.000000 503.700000 0.375000 503.740000 ;
    END
  END HADDRI[19]
  PIN HADDRI[18]
    DIRECTION OUTPUT ;
    USE SIGNAL ;
    PORT
      LAYER M6 ;
        RECT 503.761000 547.300000 504.136000 547.340000 ;
    END
  END HADDRI[18]
  PIN HADDRI[17]
    DIRECTION OUTPUT ;
    USE SIGNAL ;
    PORT
      LAYER M8 ;
        RECT 503.782000 547.233000 504.136000 547.295000 ;
    END
  END HADDRI[17]
  PIN HADDRI[16]
    DIRECTION OUTPUT ;
    USE SIGNAL ;
    PORT
      LAYER M4 ;
        RECT 503.761000 547.220000 504.136000 547.260000 ;
    END
  END HADDRI[16]
  PIN HADDRI[15]
    DIRECTION OUTPUT ;
    USE SIGNAL ;
    PORT
      LAYER M6 ;
        RECT 0.000000 503.860000 0.375000 503.900000 ;
    END
  END HADDRI[15]
  PIN HADDRI[14]
    DIRECTION OUTPUT ;
    USE SIGNAL ;
    PORT
      LAYER M8 ;
        RECT 0.000000 503.841000 0.354000 503.903000 ;
    END
  END HADDRI[14]
  PIN HADDRI[13]
    DIRECTION OUTPUT ;
    USE SIGNAL ;
    PORT
      LAYER M2 ;
        RECT MASK 1 503.907000 547.120000 504.136000 547.152000 ;
    END
  END HADDRI[13]
  PIN HADDRI[12]
    DIRECTION OUTPUT ;
    USE SIGNAL ;
    PORT
      LAYER M6 ;
        RECT 503.761000 546.980000 504.136000 547.020000 ;
    END
  END HADDRI[12]
  PIN HADDRI[11]
    DIRECTION OUTPUT ;
    USE SIGNAL ;
    PORT
      LAYER M4 ;
        RECT 503.761000 546.900000 504.136000 546.940000 ;
    END
  END HADDRI[11]
  PIN HADDRI[10]
    DIRECTION OUTPUT ;
    USE SIGNAL ;
    PORT
      LAYER M2 ;
        RECT MASK 1 503.907000 546.864000 504.136000 546.896000 ;
    END
  END HADDRI[10]
  PIN HADDRI[9]
    DIRECTION OUTPUT ;
    USE SIGNAL ;
    PORT
      LAYER M6 ;
        RECT 0.000000 504.020000 0.375000 504.060000 ;
    END
  END HADDRI[9]
  PIN HADDRI[8]
    DIRECTION OUTPUT ;
    USE SIGNAL ;
    PORT
      LAYER M8 ;
        RECT 503.782000 546.721000 504.136000 546.783000 ;
    END
  END HADDRI[8]
  PIN HADDRI[7]
    DIRECTION OUTPUT ;
    USE SIGNAL ;
    PORT
      LAYER M6 ;
        RECT 503.761000 546.660000 504.136000 546.700000 ;
    END
  END HADDRI[7]
  PIN HADDRI[6]
    DIRECTION OUTPUT ;
    USE SIGNAL ;
    PORT
      LAYER M2 ;
        RECT MASK 1 503.907000 546.608000 504.136000 546.640000 ;
    END
  END HADDRI[6]
  PIN HADDRI[5]
    DIRECTION OUTPUT ;
    USE SIGNAL ;
    PORT
      LAYER M8 ;
        RECT 0.000000 504.097000 0.354000 504.159000 ;
    END
  END HADDRI[5]
  PIN HADDRI[4]
    DIRECTION OUTPUT ;
    USE SIGNAL ;
    PORT
      LAYER M4 ;
        RECT 503.761000 546.580000 504.136000 546.620000 ;
    END
  END HADDRI[4]
  PIN HADDRI[3]
    DIRECTION OUTPUT ;
    USE SIGNAL ;
    PORT
      LAYER M2 ;
        RECT MASK 1 503.907000 546.352000 504.136000 546.384000 ;
    END
  END HADDRI[3]
  PIN HADDRI[2]
    DIRECTION OUTPUT ;
    USE SIGNAL ;
    PORT
      LAYER M6 ;
        RECT 0.000000 504.180000 0.375000 504.220000 ;
    END
  END HADDRI[2]
  PIN HADDRI[1]
    DIRECTION OUTPUT ;
    USE SIGNAL ;
    PORT
      LAYER M6 ;
        RECT 0.000000 527.380000 0.375000 527.420000 ;
    END
  END HADDRI[1]
  PIN HADDRI[0]
    DIRECTION OUTPUT ;
    USE SIGNAL ;
    PORT
      LAYER M6 ;
        RECT 0.000000 527.540000 0.375000 527.580000 ;
    END
  END HADDRI[0]
  PIN HBURSTI[2]
    DIRECTION OUTPUT ;
    USE SIGNAL ;
    PORT
      LAYER M8 ;
        RECT 0.000000 527.393000 0.354000 527.455000 ;
    END
  END HBURSTI[2]
  PIN HBURSTI[1]
    DIRECTION OUTPUT ;
    USE SIGNAL ;
    PORT
      LAYER M8 ;
        RECT 0.000000 527.137000 0.354000 527.199000 ;
    END
  END HBURSTI[1]
  PIN HBURSTI[0]
    DIRECTION OUTPUT ;
    USE SIGNAL ;
    PORT
      LAYER M8 ;
        RECT 0.000000 527.649000 0.354000 527.711000 ;
    END
  END HBURSTI[0]
  PIN HPROTI[3]
    DIRECTION OUTPUT ;
    USE SIGNAL ;
    PORT
      LAYER M8 ;
        RECT 0.000000 527.905000 0.354000 527.967000 ;
    END
  END HPROTI[3]
  PIN HPROTI[2]
    DIRECTION OUTPUT ;
    USE SIGNAL ;
    PORT
      LAYER M6 ;
        RECT 0.000000 527.940000 0.375000 527.980000 ;
    END
  END HPROTI[2]
  PIN HPROTI[1]
    DIRECTION OUTPUT ;
    USE SIGNAL ;
    PORT
      LAYER M8 ;
        RECT 0.000000 505.377000 0.354000 505.439000 ;
    END
  END HPROTI[1]
  PIN HPROTI[0]
    DIRECTION OUTPUT ;
    USE SIGNAL ;
    PORT
      LAYER M6 ;
        RECT 503.761000 543.140000 504.136000 543.180000 ;
    END
  END HPROTI[0]
  PIN MEMATTRI[1]
    DIRECTION OUTPUT ;
    USE SIGNAL ;
    PORT
      LAYER M8 ;
        RECT 0.000000 528.161000 0.354000 528.223000 ;
    END
  END MEMATTRI[1]
  PIN MEMATTRI[0]
    DIRECTION OUTPUT ;
    USE SIGNAL ;
    PORT
      LAYER M6 ;
        RECT 0.000000 528.180000 0.375000 528.220000 ;
    END
  END MEMATTRI[0]
  PIN HTRANSD[1]
    DIRECTION OUTPUT ;
    USE SIGNAL ;
    PORT
      LAYER M6 ;
        RECT 0.000000 508.820000 0.375000 508.860000 ;
    END
  END HTRANSD[1]
  PIN HTRANSD[0]
    DIRECTION OUTPUT ;
    USE SIGNAL ;
    PORT
      LAYER M4 ;
        RECT 503.761000 536.980000 504.136000 537.020000 ;
    END
  END HTRANSD[0]
  PIN HSIZED[2]
    DIRECTION OUTPUT ;
    USE SIGNAL ;
    PORT
      LAYER M6 ;
        RECT 0.000000 527.700000 0.375000 527.740000 ;
    END
  END HSIZED[2]
  PIN HSIZED[1]
    DIRECTION OUTPUT ;
    USE SIGNAL ;
    PORT
      LAYER M6 ;
        RECT 0.000000 508.660000 0.375000 508.700000 ;
    END
  END HSIZED[1]
  PIN HSIZED[0]
    DIRECTION OUTPUT ;
    USE SIGNAL ;
    PORT
      LAYER M2 ;
        RECT MASK 1 503.907000 537.392000 504.136000 537.424000 ;
    END
  END HSIZED[0]
  PIN HADDRD[31]
    DIRECTION OUTPUT ;
    USE SIGNAL ;
    PORT
      LAYER M4 ;
        RECT 503.761000 527.140000 504.136000 527.180000 ;
    END
  END HADDRD[31]
  PIN HADDRD[30]
    DIRECTION OUTPUT ;
    USE SIGNAL ;
    PORT
      LAYER M6 ;
        RECT 503.761000 528.260000 504.136000 528.300000 ;
    END
  END HADDRD[30]
  PIN HADDRD[29]
    DIRECTION OUTPUT ;
    USE SIGNAL ;
    PORT
      LAYER M4 ;
        RECT 503.761000 529.380000 504.136000 529.420000 ;
    END
  END HADDRD[29]
  PIN HADDRD[28]
    DIRECTION OUTPUT ;
    USE SIGNAL ;
    PORT
      LAYER M4 ;
        RECT 503.761000 549.460000 504.136000 549.500000 ;
    END
  END HADDRD[28]
  PIN HADDRD[27]
    DIRECTION OUTPUT ;
    USE SIGNAL ;
    PORT
      LAYER M2 ;
        RECT MASK 1 503.907000 549.424000 504.136000 549.456000 ;
    END
  END HADDRD[27]
  PIN HADDRD[26]
    DIRECTION OUTPUT ;
    USE SIGNAL ;
    PORT
      LAYER M8 ;
        RECT 503.782000 549.281000 504.136000 549.343000 ;
    END
  END HADDRD[26]
  PIN HADDRD[25]
    DIRECTION OUTPUT ;
    USE SIGNAL ;
    PORT
      LAYER M8 ;
        RECT 0.000000 502.817000 0.354000 502.879000 ;
    END
  END HADDRD[25]
  PIN HADDRD[24]
    DIRECTION OUTPUT ;
    USE SIGNAL ;
    PORT
      LAYER M6 ;
        RECT 503.761000 549.220000 504.136000 549.260000 ;
    END
  END HADDRD[24]
  PIN HADDRD[23]
    DIRECTION OUTPUT ;
    USE SIGNAL ;
    PORT
      LAYER M2 ;
        RECT MASK 2 0.000000 502.896000 0.229000 502.928000 ;
    END
  END HADDRD[23]
  PIN HADDRD[22]
    DIRECTION OUTPUT ;
    USE SIGNAL ;
    PORT
      LAYER M2 ;
        RECT MASK 1 503.907000 549.168000 504.136000 549.200000 ;
    END
  END HADDRD[22]
  PIN HADDRD[21]
    DIRECTION OUTPUT ;
    USE SIGNAL ;
    PORT
      LAYER M4 ;
        RECT 0.000000 502.900000 0.375000 502.940000 ;
    END
  END HADDRD[21]
  PIN HADDRD[20]
    DIRECTION OUTPUT ;
    USE SIGNAL ;
    PORT
      LAYER M6 ;
        RECT 0.000000 502.900000 0.375000 502.940000 ;
    END
  END HADDRD[20]
  PIN HADDRD[19]
    DIRECTION OUTPUT ;
    USE SIGNAL ;
    PORT
      LAYER M4 ;
        RECT 503.761000 549.140000 504.136000 549.180000 ;
    END
  END HADDRD[19]
  PIN HADDRD[18]
    DIRECTION OUTPUT ;
    USE SIGNAL ;
    PORT
      LAYER M2 ;
        RECT MASK 1 503.907000 548.912000 504.136000 548.944000 ;
    END
  END HADDRD[18]
  PIN HADDRD[17]
    DIRECTION OUTPUT ;
    USE SIGNAL ;
    PORT
      LAYER M2 ;
        RECT MASK 2 0.000000 503.024000 0.229000 503.056000 ;
    END
  END HADDRD[17]
  PIN HADDRD[16]
    DIRECTION OUTPUT ;
    USE SIGNAL ;
    PORT
      LAYER M6 ;
        RECT 503.761000 548.900000 504.136000 548.940000 ;
    END
  END HADDRD[16]
  PIN HADDRD[15]
    DIRECTION OUTPUT ;
    USE SIGNAL ;
    PORT
      LAYER M4 ;
        RECT 0.000000 503.060000 0.375000 503.100000 ;
    END
  END HADDRD[15]
  PIN HADDRD[14]
    DIRECTION OUTPUT ;
    USE SIGNAL ;
    PORT
      LAYER M6 ;
        RECT 0.000000 503.060000 0.375000 503.100000 ;
    END
  END HADDRD[14]
  PIN HADDRD[13]
    DIRECTION OUTPUT ;
    USE SIGNAL ;
    PORT
      LAYER M4 ;
        RECT 503.761000 548.820000 504.136000 548.860000 ;
    END
  END HADDRD[13]
  PIN HADDRD[12]
    DIRECTION OUTPUT ;
    USE SIGNAL ;
    PORT
      LAYER M8 ;
        RECT 503.782000 548.769000 504.136000 548.831000 ;
    END
  END HADDRD[12]
  PIN HADDRD[11]
    DIRECTION OUTPUT ;
    USE SIGNAL ;
    PORT
      LAYER M8 ;
        RECT 0.000000 503.073000 0.354000 503.135000 ;
    END
  END HADDRD[11]
  PIN HADDRD[10]
    DIRECTION OUTPUT ;
    USE SIGNAL ;
    PORT
      LAYER M2 ;
        RECT MASK 1 503.907000 548.656000 504.136000 548.688000 ;
    END
  END HADDRD[10]
  PIN HADDRD[9]
    DIRECTION OUTPUT ;
    USE SIGNAL ;
    PORT
      LAYER M2 ;
        RECT MASK 2 0.000000 503.152000 0.229000 503.184000 ;
    END
  END HADDRD[9]
  PIN HADDRD[8]
    DIRECTION OUTPUT ;
    USE SIGNAL ;
    PORT
      LAYER M6 ;
        RECT 503.761000 548.580000 504.136000 548.620000 ;
    END
  END HADDRD[8]
  PIN HADDRD[7]
    DIRECTION OUTPUT ;
    USE SIGNAL ;
    PORT
      LAYER M6 ;
        RECT 0.000000 503.220000 0.375000 503.260000 ;
    END
  END HADDRD[7]
  PIN HADDRD[6]
    DIRECTION OUTPUT ;
    USE SIGNAL ;
    PORT
      LAYER M4 ;
        RECT 503.761000 548.500000 504.136000 548.540000 ;
    END
  END HADDRD[6]
  PIN HADDRD[5]
    DIRECTION OUTPUT ;
    USE SIGNAL ;
    PORT
      LAYER M2 ;
        RECT MASK 1 503.907000 548.400000 504.136000 548.432000 ;
    END
  END HADDRD[5]
  PIN HADDRD[4]
    DIRECTION OUTPUT ;
    USE SIGNAL ;
    PORT
      LAYER M8 ;
        RECT 503.782000 548.257000 504.136000 548.319000 ;
    END
  END HADDRD[4]
  PIN HADDRD[3]
    DIRECTION OUTPUT ;
    USE SIGNAL ;
    PORT
      LAYER M6 ;
        RECT 0.000000 503.380000 0.375000 503.420000 ;
    END
  END HADDRD[3]
  PIN HADDRD[2]
    DIRECTION OUTPUT ;
    USE SIGNAL ;
    PORT
      LAYER M8 ;
        RECT 0.000000 503.329000 0.354000 503.391000 ;
    END
  END HADDRD[2]
  PIN HADDRD[1]
    DIRECTION OUTPUT ;
    USE SIGNAL ;
    PORT
      LAYER M6 ;
        RECT 503.761000 546.340000 504.136000 546.380000 ;
    END
  END HADDRD[1]
  PIN HADDRD[0]
    DIRECTION OUTPUT ;
    USE SIGNAL ;
    PORT
      LAYER M4 ;
        RECT 503.761000 546.260000 504.136000 546.300000 ;
    END
  END HADDRD[0]
  PIN HBURSTD[2]
    DIRECTION OUTPUT ;
    USE SIGNAL ;
    PORT
      LAYER M2 ;
        RECT MASK 2 503.907000 527.600000 504.136000 527.632000 ;
    END
  END HBURSTD[2]
  PIN HBURSTD[1]
    DIRECTION OUTPUT ;
    USE SIGNAL ;
    PORT
      LAYER M8 ;
        RECT 503.782000 527.649000 504.136000 527.711000 ;
    END
  END HBURSTD[1]
  PIN HBURSTD[0]
    DIRECTION OUTPUT ;
    USE SIGNAL ;
    PORT
      LAYER M4 ;
        RECT 503.761000 551.380000 504.136000 551.420000 ;
    END
  END HBURSTD[0]
  PIN HPROTD[3]
    DIRECTION OUTPUT ;
    USE SIGNAL ;
    PORT
      LAYER M8 ;
        RECT 503.782000 529.441000 504.136000 529.503000 ;
    END
  END HPROTD[3]
  PIN HPROTD[2]
    DIRECTION OUTPUT ;
    USE SIGNAL ;
    PORT
      LAYER M6 ;
        RECT 503.761000 528.820000 504.136000 528.860000 ;
    END
  END HPROTD[2]
  PIN HPROTD[1]
    DIRECTION OUTPUT ;
    USE SIGNAL ;
    PORT
      LAYER M4 ;
        RECT 503.761000 543.060000 504.136000 543.100000 ;
    END
  END HPROTD[1]
  PIN HPROTD[0]
    DIRECTION OUTPUT ;
    USE SIGNAL ;
    PORT
      LAYER M2 ;
        RECT MASK 1 503.907000 543.024000 504.136000 543.056000 ;
    END
  END HPROTD[0]
  PIN MEMATTRD[1]
    DIRECTION OUTPUT ;
    USE SIGNAL ;
    PORT
      LAYER M4 ;
        RECT 503.761000 527.700000 504.136000 527.740000 ;
    END
  END MEMATTRD[1]
  PIN MEMATTRD[0]
    DIRECTION OUTPUT ;
    USE SIGNAL ;
    PORT
      LAYER M4 ;
        RECT 503.761000 530.020000 504.136000 530.060000 ;
    END
  END MEMATTRD[0]
  PIN HMASTERD[1]
    DIRECTION OUTPUT ;
    USE SIGNAL ;
    PORT
      LAYER M8 ;
        RECT 503.782000 551.329000 504.136000 551.391000 ;
    END
  END HMASTERD[1]
  PIN HMASTERD[0]
    DIRECTION OUTPUT ;
    USE SIGNAL ;
    PORT
      LAYER M6 ;
        RECT 503.761000 542.820000 504.136000 542.860000 ;
    END
  END HMASTERD[0]
  PIN EXREQD
    DIRECTION OUTPUT ;
    USE SIGNAL ;
    PORT
      LAYER M2 ;
        RECT MASK 1 503.907000 514.992000 504.136000 515.024000 ;
    END
  END EXREQD
  PIN HWRITED
    DIRECTION OUTPUT ;
    USE SIGNAL ;
    PORT
      LAYER M6 ;
        RECT 0.000000 520.180000 0.375000 520.220000 ;
    END
  END HWRITED
  PIN HWDATAD[31]
    DIRECTION OUTPUT ;
    USE SIGNAL ;
    PORT
      LAYER M2 ;
        RECT MASK 1 503.907000 536.880000 504.136000 536.912000 ;
    END
  END HWDATAD[31]
  PIN HWDATAD[30]
    DIRECTION OUTPUT ;
    USE SIGNAL ;
    PORT
      LAYER M8 ;
        RECT 503.782000 536.737000 504.136000 536.799000 ;
    END
  END HWDATAD[30]
  PIN HWDATAD[29]
    DIRECTION OUTPUT ;
    USE SIGNAL ;
    PORT
      LAYER M6 ;
        RECT 503.761000 536.740000 504.136000 536.780000 ;
    END
  END HWDATAD[29]
  PIN HWDATAD[28]
    DIRECTION OUTPUT ;
    USE SIGNAL ;
    PORT
      LAYER M6 ;
        RECT 0.000000 509.140000 0.375000 509.180000 ;
    END
  END HWDATAD[28]
  PIN HWDATAD[27]
    DIRECTION OUTPUT ;
    USE SIGNAL ;
    PORT
      LAYER M4 ;
        RECT 503.761000 536.660000 504.136000 536.700000 ;
    END
  END HWDATAD[27]
  PIN HWDATAD[26]
    DIRECTION OUTPUT ;
    USE SIGNAL ;
    PORT
      LAYER M2 ;
        RECT MASK 1 503.907000 536.624000 504.136000 536.656000 ;
    END
  END HWDATAD[26]
  PIN HWDATAD[25]
    DIRECTION OUTPUT ;
    USE SIGNAL ;
    PORT
      LAYER M6 ;
        RECT 503.761000 536.420000 504.136000 536.460000 ;
    END
  END HWDATAD[25]
  PIN HWDATAD[24]
    DIRECTION OUTPUT ;
    USE SIGNAL ;
    PORT
      LAYER M2 ;
        RECT MASK 1 503.907000 536.368000 504.136000 536.400000 ;
    END
  END HWDATAD[24]
  PIN HWDATAD[23]
    DIRECTION OUTPUT ;
    USE SIGNAL ;
    PORT
      LAYER M6 ;
        RECT 0.000000 509.300000 0.375000 509.340000 ;
    END
  END HWDATAD[23]
  PIN HWDATAD[22]
    DIRECTION OUTPUT ;
    USE SIGNAL ;
    PORT
      LAYER M4 ;
        RECT 503.761000 536.340000 504.136000 536.380000 ;
    END
  END HWDATAD[22]
  PIN HWDATAD[21]
    DIRECTION OUTPUT ;
    USE SIGNAL ;
    PORT
      LAYER M8 ;
        RECT 503.782000 536.225000 504.136000 536.287000 ;
    END
  END HWDATAD[21]
  PIN HWDATAD[20]
    DIRECTION OUTPUT ;
    USE SIGNAL ;
    PORT
      LAYER M2 ;
        RECT MASK 1 503.907000 536.112000 504.136000 536.144000 ;
    END
  END HWDATAD[20]
  PIN HWDATAD[19]
    DIRECTION OUTPUT ;
    USE SIGNAL ;
    PORT
      LAYER M6 ;
        RECT 0.000000 509.460000 0.375000 509.500000 ;
    END
  END HWDATAD[19]
  PIN HWDATAD[18]
    DIRECTION OUTPUT ;
    USE SIGNAL ;
    PORT
      LAYER M6 ;
        RECT 503.761000 536.100000 504.136000 536.140000 ;
    END
  END HWDATAD[18]
  PIN HWDATAD[17]
    DIRECTION OUTPUT ;
    USE SIGNAL ;
    PORT
      LAYER M4 ;
        RECT 503.761000 536.020000 504.136000 536.060000 ;
    END
  END HWDATAD[17]
  PIN HWDATAD[16]
    DIRECTION OUTPUT ;
    USE SIGNAL ;
    PORT
      LAYER M2 ;
        RECT MASK 1 503.907000 535.856000 504.136000 535.888000 ;
    END
  END HWDATAD[16]
  PIN HWDATAD[15]
    DIRECTION OUTPUT ;
    USE SIGNAL ;
    PORT
      LAYER M6 ;
        RECT 0.000000 509.620000 0.375000 509.660000 ;
    END
  END HWDATAD[15]
  PIN HWDATAD[14]
    DIRECTION OUTPUT ;
    USE SIGNAL ;
    PORT
      LAYER M8 ;
        RECT 0.000000 509.601000 0.354000 509.663000 ;
    END
  END HWDATAD[14]
  PIN HWDATAD[13]
    DIRECTION OUTPUT ;
    USE SIGNAL ;
    PORT
      LAYER M4 ;
        RECT 503.761000 537.300000 504.136000 537.340000 ;
    END
  END HWDATAD[13]
  PIN HWDATAD[12]
    DIRECTION OUTPUT ;
    USE SIGNAL ;
    PORT
      LAYER M8 ;
        RECT 503.782000 537.249000 504.136000 537.311000 ;
    END
  END HWDATAD[12]
  PIN HWDATAD[11]
    DIRECTION OUTPUT ;
    USE SIGNAL ;
    PORT
      LAYER M2 ;
        RECT MASK 1 503.907000 537.136000 504.136000 537.168000 ;
    END
  END HWDATAD[11]
  PIN HWDATAD[10]
    DIRECTION OUTPUT ;
    USE SIGNAL ;
    PORT
      LAYER M4 ;
        RECT 503.761000 535.700000 504.136000 535.740000 ;
    END
  END HWDATAD[10]
  PIN HWDATAD[9]
    DIRECTION OUTPUT ;
    USE SIGNAL ;
    PORT
      LAYER M6 ;
        RECT 0.000000 509.780000 0.375000 509.820000 ;
    END
  END HWDATAD[9]
  PIN HWDATAD[8]
    DIRECTION OUTPUT ;
    USE SIGNAL ;
    PORT
      LAYER M2 ;
        RECT MASK 1 503.907000 535.600000 504.136000 535.632000 ;
    END
  END HWDATAD[8]
  PIN HWDATAD[7]
    DIRECTION OUTPUT ;
    USE SIGNAL ;
    PORT
      LAYER M6 ;
        RECT 503.761000 535.460000 504.136000 535.500000 ;
    END
  END HWDATAD[7]
  PIN HWDATAD[6]
    DIRECTION OUTPUT ;
    USE SIGNAL ;
    PORT
      LAYER M4 ;
        RECT 503.761000 535.380000 504.136000 535.420000 ;
    END
  END HWDATAD[6]
  PIN HWDATAD[5]
    DIRECTION OUTPUT ;
    USE SIGNAL ;
    PORT
      LAYER M8 ;
        RECT 0.000000 509.857000 0.354000 509.919000 ;
    END
  END HWDATAD[5]
  PIN HWDATAD[4]
    DIRECTION OUTPUT ;
    USE SIGNAL ;
    PORT
      LAYER M2 ;
        RECT MASK 1 503.907000 535.344000 504.136000 535.376000 ;
    END
  END HWDATAD[4]
  PIN HWDATAD[3]
    DIRECTION OUTPUT ;
    USE SIGNAL ;
    PORT
      LAYER M8 ;
        RECT 503.782000 535.201000 504.136000 535.263000 ;
    END
  END HWDATAD[3]
  PIN HWDATAD[2]
    DIRECTION OUTPUT ;
    USE SIGNAL ;
    PORT
      LAYER M6 ;
        RECT 0.000000 509.940000 0.375000 509.980000 ;
    END
  END HWDATAD[2]
  PIN HWDATAD[1]
    DIRECTION OUTPUT ;
    USE SIGNAL ;
    PORT
      LAYER M6 ;
        RECT 503.761000 535.140000 504.136000 535.180000 ;
    END
  END HWDATAD[1]
  PIN HWDATAD[0]
    DIRECTION OUTPUT ;
    USE SIGNAL ;
    PORT
      LAYER M2 ;
        RECT MASK 1 503.907000 535.088000 504.136000 535.120000 ;
    END
  END HWDATAD[0]
  PIN HTRANSS[1]
    DIRECTION OUTPUT ;
    USE SIGNAL ;
    PORT
      LAYER M6 ;
        RECT 503.761000 535.780000 504.136000 535.820000 ;
    END
  END HTRANSS[1]
  PIN HTRANSS[0]
    DIRECTION OUTPUT ;
    USE SIGNAL ;
    PORT
      LAYER M6 ;
        RECT 0.000000 508.980000 0.375000 509.020000 ;
    END
  END HTRANSS[0]
  PIN HSIZES[2]
    DIRECTION OUTPUT ;
    USE SIGNAL ;
    PORT
      LAYER M4 ;
        RECT 503.761000 528.820000 504.136000 528.860000 ;
    END
  END HSIZES[2]
  PIN HSIZES[1]
    DIRECTION OUTPUT ;
    USE SIGNAL ;
    PORT
      LAYER M6 ;
        RECT 503.761000 537.380000 504.136000 537.420000 ;
    END
  END HSIZES[1]
  PIN HSIZES[0]
    DIRECTION OUTPUT ;
    USE SIGNAL ;
    PORT
      LAYER M8 ;
        RECT 503.782000 535.713000 504.136000 535.775000 ;
    END
  END HSIZES[0]
  PIN HADDRS[31]
    DIRECTION OUTPUT ;
    USE SIGNAL ;
    PORT
      LAYER M8 ;
        RECT 503.782000 546.209000 504.136000 546.271000 ;
    END
  END HADDRS[31]
  PIN HADDRS[30]
    DIRECTION OUTPUT ;
    USE SIGNAL ;
    PORT
      LAYER M2 ;
        RECT MASK 1 503.907000 546.096000 504.136000 546.128000 ;
    END
  END HADDRS[30]
  PIN HADDRS[29]
    DIRECTION OUTPUT ;
    USE SIGNAL ;
    PORT
      LAYER M6 ;
        RECT 503.761000 546.020000 504.136000 546.060000 ;
    END
  END HADDRS[29]
  PIN HADDRS[28]
    DIRECTION OUTPUT ;
    USE SIGNAL ;
    PORT
      LAYER M6 ;
        RECT 0.000000 504.340000 0.375000 504.380000 ;
    END
  END HADDRS[28]
  PIN HADDRS[27]
    DIRECTION OUTPUT ;
    USE SIGNAL ;
    PORT
      LAYER M4 ;
        RECT 503.761000 545.940000 504.136000 545.980000 ;
    END
  END HADDRS[27]
  PIN HADDRS[26]
    DIRECTION OUTPUT ;
    USE SIGNAL ;
    PORT
      LAYER M2 ;
        RECT MASK 1 503.907000 545.840000 504.136000 545.872000 ;
    END
  END HADDRS[26]
  PIN HADDRS[25]
    DIRECTION OUTPUT ;
    USE SIGNAL ;
    PORT
      LAYER M8 ;
        RECT 0.000000 504.353000 0.354000 504.415000 ;
    END
  END HADDRS[25]
  PIN HADDRS[24]
    DIRECTION OUTPUT ;
    USE SIGNAL ;
    PORT
      LAYER M8 ;
        RECT 503.782000 545.697000 504.136000 545.759000 ;
    END
  END HADDRS[24]
  PIN HADDRS[23]
    DIRECTION OUTPUT ;
    USE SIGNAL ;
    PORT
      LAYER M6 ;
        RECT 503.761000 545.700000 504.136000 545.740000 ;
    END
  END HADDRS[23]
  PIN HADDRS[22]
    DIRECTION OUTPUT ;
    USE SIGNAL ;
    PORT
      LAYER M6 ;
        RECT 0.000000 504.500000 0.375000 504.540000 ;
    END
  END HADDRS[22]
  PIN HADDRS[21]
    DIRECTION OUTPUT ;
    USE SIGNAL ;
    PORT
      LAYER M4 ;
        RECT 503.761000 545.620000 504.136000 545.660000 ;
    END
  END HADDRS[21]
  PIN HADDRS[20]
    DIRECTION OUTPUT ;
    USE SIGNAL ;
    PORT
      LAYER M2 ;
        RECT MASK 1 503.907000 545.584000 504.136000 545.616000 ;
    END
  END HADDRS[20]
  PIN HADDRS[19]
    DIRECTION OUTPUT ;
    USE SIGNAL ;
    PORT
      LAYER M6 ;
        RECT 503.761000 545.380000 504.136000 545.420000 ;
    END
  END HADDRS[19]
  PIN HADDRS[18]
    DIRECTION OUTPUT ;
    USE SIGNAL ;
    PORT
      LAYER M6 ;
        RECT 0.000000 504.660000 0.375000 504.700000 ;
    END
  END HADDRS[18]
  PIN HADDRS[17]
    DIRECTION OUTPUT ;
    USE SIGNAL ;
    PORT
      LAYER M8 ;
        RECT 0.000000 504.609000 0.354000 504.671000 ;
    END
  END HADDRS[17]
  PIN HADDRS[16]
    DIRECTION OUTPUT ;
    USE SIGNAL ;
    PORT
      LAYER M2 ;
        RECT MASK 1 503.907000 545.328000 504.136000 545.360000 ;
    END
  END HADDRS[16]
  PIN HADDRS[15]
    DIRECTION OUTPUT ;
    USE SIGNAL ;
    PORT
      LAYER M4 ;
        RECT 503.761000 545.300000 504.136000 545.340000 ;
    END
  END HADDRS[15]
  PIN HADDRS[14]
    DIRECTION OUTPUT ;
    USE SIGNAL ;
    PORT
      LAYER M8 ;
        RECT 503.782000 545.185000 504.136000 545.247000 ;
    END
  END HADDRS[14]
  PIN HADDRS[13]
    DIRECTION OUTPUT ;
    USE SIGNAL ;
    PORT
      LAYER M2 ;
        RECT MASK 1 503.907000 545.072000 504.136000 545.104000 ;
    END
  END HADDRS[13]
  PIN HADDRS[12]
    DIRECTION OUTPUT ;
    USE SIGNAL ;
    PORT
      LAYER M6 ;
        RECT 503.761000 545.060000 504.136000 545.100000 ;
    END
  END HADDRS[12]
  PIN HADDRS[11]
    DIRECTION OUTPUT ;
    USE SIGNAL ;
    PORT
      LAYER M6 ;
        RECT 0.000000 504.820000 0.375000 504.860000 ;
    END
  END HADDRS[11]
  PIN HADDRS[10]
    DIRECTION OUTPUT ;
    USE SIGNAL ;
    PORT
      LAYER M4 ;
        RECT 503.761000 544.980000 504.136000 545.020000 ;
    END
  END HADDRS[10]
  PIN HADDRS[9]
    DIRECTION OUTPUT ;
    USE SIGNAL ;
    PORT
      LAYER M2 ;
        RECT MASK 1 503.907000 544.816000 504.136000 544.848000 ;
    END
  END HADDRS[9]
  PIN HADDRS[8]
    DIRECTION OUTPUT ;
    USE SIGNAL ;
    PORT
      LAYER M8 ;
        RECT 0.000000 504.865000 0.354000 504.927000 ;
    END
  END HADDRS[8]
  PIN HADDRS[7]
    DIRECTION OUTPUT ;
    USE SIGNAL ;
    PORT
      LAYER M6 ;
        RECT 503.761000 544.740000 504.136000 544.780000 ;
    END
  END HADDRS[7]
  PIN HADDRS[6]
    DIRECTION OUTPUT ;
    USE SIGNAL ;
    PORT
      LAYER M8 ;
        RECT 503.782000 544.673000 504.136000 544.735000 ;
    END
  END HADDRS[6]
  PIN HADDRS[5]
    DIRECTION OUTPUT ;
    USE SIGNAL ;
    PORT
      LAYER M6 ;
        RECT 0.000000 504.980000 0.375000 505.020000 ;
    END
  END HADDRS[5]
  PIN HADDRS[4]
    DIRECTION OUTPUT ;
    USE SIGNAL ;
    PORT
      LAYER M4 ;
        RECT 503.761000 544.660000 504.136000 544.700000 ;
    END
  END HADDRS[4]
  PIN HADDRS[3]
    DIRECTION OUTPUT ;
    USE SIGNAL ;
    PORT
      LAYER M2 ;
        RECT MASK 1 503.907000 544.560000 504.136000 544.592000 ;
    END
  END HADDRS[3]
  PIN HADDRS[2]
    DIRECTION OUTPUT ;
    USE SIGNAL ;
    PORT
      LAYER M6 ;
        RECT 503.761000 544.420000 504.136000 544.460000 ;
    END
  END HADDRS[2]
  PIN HADDRS[1]
    DIRECTION OUTPUT ;
    USE SIGNAL ;
    PORT
      LAYER M6 ;
        RECT 0.000000 505.140000 0.375000 505.180000 ;
    END
  END HADDRS[1]
  PIN HADDRS[0]
    DIRECTION OUTPUT ;
    USE SIGNAL ;
    PORT
      LAYER M8 ;
        RECT 0.000000 505.121000 0.354000 505.183000 ;
    END
  END HADDRS[0]
  PIN HBURSTS[2]
    DIRECTION OUTPUT ;
    USE SIGNAL ;
    PORT
      LAYER M4 ;
        RECT 503.761000 528.260000 504.136000 528.300000 ;
    END
  END HBURSTS[2]
  PIN HBURSTS[1]
    DIRECTION OUTPUT ;
    USE SIGNAL ;
    PORT
      LAYER M2 ;
        RECT MASK 2 503.907000 529.392000 504.136000 529.424000 ;
    END
  END HBURSTS[1]
  PIN HBURSTS[0]
    DIRECTION OUTPUT ;
    USE SIGNAL ;
    PORT
      LAYER M2 ;
        RECT MASK 1 503.907000 551.216000 504.136000 551.248000 ;
    END
  END HBURSTS[0]
  PIN HPROTS[3]
    DIRECTION OUTPUT ;
    USE SIGNAL ;
    PORT
      LAYER M2 ;
        RECT MASK 1 503.907000 542.768000 504.136000 542.800000 ;
    END
  END HPROTS[3]
  PIN HPROTS[2]
    DIRECTION OUTPUT ;
    USE SIGNAL ;
    PORT
      LAYER M6 ;
        RECT 0.000000 505.460000 0.375000 505.500000 ;
    END
  END HPROTS[2]
  PIN HPROTS[1]
    DIRECTION OUTPUT ;
    USE SIGNAL ;
    PORT
      LAYER M4 ;
        RECT 503.761000 542.740000 504.136000 542.780000 ;
    END
  END HPROTS[1]
  PIN HPROTS[0]
    DIRECTION OUTPUT ;
    USE SIGNAL ;
    PORT
      LAYER M2 ;
        RECT MASK 1 503.907000 542.512000 504.136000 542.544000 ;
    END
  END HPROTS[0]
  PIN MEMATTRS[1]
    DIRECTION OUTPUT ;
    USE SIGNAL ;
    PORT
      LAYER M4 ;
        RECT 503.761000 513.700000 504.136000 513.740000 ;
    END
  END MEMATTRS[1]
  PIN MEMATTRS[0]
    DIRECTION OUTPUT ;
    USE SIGNAL ;
    PORT
      LAYER M6 ;
        RECT 503.761000 514.820000 504.136000 514.860000 ;
    END
  END MEMATTRS[0]
  PIN HMASTERS[1]
    DIRECTION OUTPUT ;
    USE SIGNAL ;
    PORT
      LAYER M6 ;
        RECT 0.000000 505.300000 0.375000 505.340000 ;
    END
  END HMASTERS[1]
  PIN HMASTERS[0]
    DIRECTION OUTPUT ;
    USE SIGNAL ;
    PORT
      LAYER M6 ;
        RECT 503.761000 542.500000 504.136000 542.540000 ;
    END
  END HMASTERS[0]
  PIN EXREQS
    DIRECTION OUTPUT ;
    USE SIGNAL ;
    PORT
      LAYER M4 ;
        RECT 503.761000 515.460000 504.136000 515.500000 ;
    END
  END EXREQS
  PIN HWRITES
    DIRECTION OUTPUT ;
    USE SIGNAL ;
    PORT
      LAYER M2 ;
        RECT MASK 2 503.907000 515.440000 504.136000 515.472000 ;
    END
  END HWRITES
  PIN HWDATAS[31]
    DIRECTION OUTPUT ;
    USE SIGNAL ;
    PORT
      LAYER M4 ;
        RECT 503.761000 535.060000 504.136000 535.100000 ;
    END
  END HWDATAS[31]
  PIN HWDATAS[30]
    DIRECTION OUTPUT ;
    USE SIGNAL ;
    PORT
      LAYER M6 ;
        RECT 0.000000 510.100000 0.375000 510.140000 ;
    END
  END HWDATAS[30]
  PIN HWDATAS[29]
    DIRECTION OUTPUT ;
    USE SIGNAL ;
    PORT
      LAYER M2 ;
        RECT MASK 1 503.907000 534.832000 504.136000 534.864000 ;
    END
  END HWDATAS[29]
  PIN HWDATAS[28]
    DIRECTION OUTPUT ;
    USE SIGNAL ;
    PORT
      LAYER M6 ;
        RECT 503.761000 534.820000 504.136000 534.860000 ;
    END
  END HWDATAS[28]
  PIN HWDATAS[27]
    DIRECTION OUTPUT ;
    USE SIGNAL ;
    PORT
      LAYER M8 ;
        RECT 0.000000 510.113000 0.354000 510.175000 ;
    END
  END HWDATAS[27]
  PIN HWDATAS[26]
    DIRECTION OUTPUT ;
    USE SIGNAL ;
    PORT
      LAYER M4 ;
        RECT 503.761000 534.740000 504.136000 534.780000 ;
    END
  END HWDATAS[26]
  PIN HWDATAS[25]
    DIRECTION OUTPUT ;
    USE SIGNAL ;
    PORT
      LAYER M8 ;
        RECT 503.782000 534.689000 504.136000 534.751000 ;
    END
  END HWDATAS[25]
  PIN HWDATAS[24]
    DIRECTION OUTPUT ;
    USE SIGNAL ;
    PORT
      LAYER M6 ;
        RECT 0.000000 510.260000 0.375000 510.300000 ;
    END
  END HWDATAS[24]
  PIN HWDATAS[23]
    DIRECTION OUTPUT ;
    USE SIGNAL ;
    PORT
      LAYER M2 ;
        RECT MASK 1 503.907000 534.576000 504.136000 534.608000 ;
    END
  END HWDATAS[23]
  PIN HWDATAS[22]
    DIRECTION OUTPUT ;
    USE SIGNAL ;
    PORT
      LAYER M6 ;
        RECT 503.761000 534.500000 504.136000 534.540000 ;
    END
  END HWDATAS[22]
  PIN HWDATAS[21]
    DIRECTION OUTPUT ;
    USE SIGNAL ;
    PORT
      LAYER M4 ;
        RECT 503.761000 534.420000 504.136000 534.460000 ;
    END
  END HWDATAS[21]
  PIN HWDATAS[20]
    DIRECTION OUTPUT ;
    USE SIGNAL ;
    PORT
      LAYER M6 ;
        RECT 0.000000 510.420000 0.375000 510.460000 ;
    END
  END HWDATAS[20]
  PIN HWDATAS[19]
    DIRECTION OUTPUT ;
    USE SIGNAL ;
    PORT
      LAYER M8 ;
        RECT 0.000000 510.369000 0.354000 510.431000 ;
    END
  END HWDATAS[19]
  PIN HWDATAS[18]
    DIRECTION OUTPUT ;
    USE SIGNAL ;
    PORT
      LAYER M2 ;
        RECT MASK 1 503.907000 534.320000 504.136000 534.352000 ;
    END
  END HWDATAS[18]
  PIN HWDATAS[17]
    DIRECTION OUTPUT ;
    USE SIGNAL ;
    PORT
      LAYER M8 ;
        RECT 503.782000 534.177000 504.136000 534.239000 ;
    END
  END HWDATAS[17]
  PIN HWDATAS[16]
    DIRECTION OUTPUT ;
    USE SIGNAL ;
    PORT
      LAYER M6 ;
        RECT 503.761000 534.180000 504.136000 534.220000 ;
    END
  END HWDATAS[16]
  PIN HWDATAS[15]
    DIRECTION OUTPUT ;
    USE SIGNAL ;
    PORT
      LAYER M4 ;
        RECT 503.761000 534.100000 504.136000 534.140000 ;
    END
  END HWDATAS[15]
  PIN HWDATAS[14]
    DIRECTION OUTPUT ;
    USE SIGNAL ;
    PORT
      LAYER M6 ;
        RECT 503.761000 532.900000 504.136000 532.940000 ;
    END
  END HWDATAS[14]
  PIN HWDATAS[13]
    DIRECTION OUTPUT ;
    USE SIGNAL ;
    PORT
      LAYER M6 ;
        RECT 0.000000 510.580000 0.375000 510.620000 ;
    END
  END HWDATAS[13]
  PIN HWDATAS[12]
    DIRECTION OUTPUT ;
    USE SIGNAL ;
    PORT
      LAYER M4 ;
        RECT 503.761000 532.820000 504.136000 532.860000 ;
    END
  END HWDATAS[12]
  PIN HWDATAS[11]
    DIRECTION OUTPUT ;
    USE SIGNAL ;
    PORT
      LAYER M2 ;
        RECT MASK 1 503.907000 532.784000 504.136000 532.816000 ;
    END
  END HWDATAS[11]
  PIN HWDATAS[10]
    DIRECTION OUTPUT ;
    USE SIGNAL ;
    PORT
      LAYER M8 ;
        RECT 0.000000 510.625000 0.354000 510.687000 ;
    END
  END HWDATAS[10]
  PIN HWDATAS[9]
    DIRECTION OUTPUT ;
    USE SIGNAL ;
    PORT
      LAYER M8 ;
        RECT 503.782000 532.641000 504.136000 532.703000 ;
    END
  END HWDATAS[9]
  PIN HWDATAS[8]
    DIRECTION OUTPUT ;
    USE SIGNAL ;
    PORT
      LAYER M6 ;
        RECT 503.761000 532.580000 504.136000 532.620000 ;
    END
  END HWDATAS[8]
  PIN HWDATAS[7]
    DIRECTION OUTPUT ;
    USE SIGNAL ;
    PORT
      LAYER M6 ;
        RECT 0.000000 510.740000 0.375000 510.780000 ;
    END
  END HWDATAS[7]
  PIN HWDATAS[6]
    DIRECTION OUTPUT ;
    USE SIGNAL ;
    PORT
      LAYER M2 ;
        RECT MASK 1 503.907000 532.528000 504.136000 532.560000 ;
    END
  END HWDATAS[6]
  PIN HWDATAS[5]
    DIRECTION OUTPUT ;
    USE SIGNAL ;
    PORT
      LAYER M4 ;
        RECT 503.761000 532.500000 504.136000 532.540000 ;
    END
  END HWDATAS[5]
  PIN HWDATAS[4]
    DIRECTION OUTPUT ;
    USE SIGNAL ;
    PORT
      LAYER M2 ;
        RECT MASK 1 503.907000 532.272000 504.136000 532.304000 ;
    END
  END HWDATAS[4]
  PIN HWDATAS[3]
    DIRECTION OUTPUT ;
    USE SIGNAL ;
    PORT
      LAYER M6 ;
        RECT 0.000000 510.900000 0.375000 510.940000 ;
    END
  END HWDATAS[3]
  PIN HWDATAS[2]
    DIRECTION OUTPUT ;
    USE SIGNAL ;
    PORT
      LAYER M8 ;
        RECT 0.000000 510.881000 0.354000 510.943000 ;
    END
  END HWDATAS[2]
  PIN HWDATAS[1]
    DIRECTION OUTPUT ;
    USE SIGNAL ;
    PORT
      LAYER M6 ;
        RECT 503.761000 532.260000 504.136000 532.300000 ;
    END
  END HWDATAS[1]
  PIN HWDATAS[0]
    DIRECTION OUTPUT ;
    USE SIGNAL ;
    PORT
      LAYER M4 ;
        RECT 503.761000 532.180000 504.136000 532.220000 ;
    END
  END HWDATAS[0]
  PIN HMASTLOCKS
    DIRECTION OUTPUT ;
    USE SIGNAL ;
    PORT
      LAYER M4 ;
        RECT 503.761000 514.340000 504.136000 514.380000 ;
    END
  END HMASTLOCKS
  PIN BRCHSTAT[3]
    DIRECTION OUTPUT ;
    USE SIGNAL ;
    PORT
      LAYER M2 ;
        RECT MASK 2 0.000000 502.384000 0.229000 502.416000 ;
    END
  END BRCHSTAT[3]
  PIN BRCHSTAT[2]
    DIRECTION OUTPUT ;
    USE SIGNAL ;
    PORT
      LAYER M4 ;
        RECT 503.761000 549.780000 504.136000 549.820000 ;
    END
  END BRCHSTAT[2]
  PIN BRCHSTAT[1]
    DIRECTION OUTPUT ;
    USE SIGNAL ;
    PORT
      LAYER M4 ;
        RECT 0.000000 502.420000 0.375000 502.460000 ;
    END
  END BRCHSTAT[1]
  PIN BRCHSTAT[0]
    DIRECTION OUTPUT ;
    USE SIGNAL ;
    PORT
      LAYER M6 ;
        RECT 0.000000 502.420000 0.375000 502.460000 ;
    END
  END BRCHSTAT[0]
  PIN HALTED
    DIRECTION OUTPUT ;
    USE SIGNAL ;
    PORT
      LAYER M6 ;
        RECT 0.000000 520.340000 0.375000 520.380000 ;
    END
  END HALTED
  PIN LOCKUP
    DIRECTION OUTPUT ;
    USE SIGNAL ;
    PORT
      LAYER M2 ;
        RECT MASK 2 503.907000 513.136000 504.136000 513.168000 ;
    END
  END LOCKUP
  PIN SLEEPING
    DIRECTION OUTPUT ;
    USE SIGNAL ;
    PORT
      LAYER M8 ;
        RECT 503.782000 513.953000 504.136000 514.015000 ;
    END
  END SLEEPING
  PIN SLEEPDEEP
    DIRECTION OUTPUT ;
    USE SIGNAL ;
    PORT
      LAYER M6 ;
        RECT 503.761000 514.260000 504.136000 514.300000 ;
    END
  END SLEEPDEEP
  PIN ETMINTNUM[8]
    DIRECTION OUTPUT ;
    USE SIGNAL ;
    PORT
      LAYER M6 ;
        RECT 503.761000 548.260000 504.136000 548.300000 ;
    END
  END ETMINTNUM[8]
  PIN ETMINTNUM[7]
    DIRECTION OUTPUT ;
    USE SIGNAL ;
    PORT
      LAYER M4 ;
        RECT 0.000000 502.580000 0.375000 502.620000 ;
    END
  END ETMINTNUM[7]
  PIN ETMINTNUM[6]
    DIRECTION OUTPUT ;
    USE SIGNAL ;
    PORT
      LAYER M6 ;
        RECT 0.000000 502.580000 0.375000 502.620000 ;
    END
  END ETMINTNUM[6]
  PIN ETMINTNUM[5]
    DIRECTION OUTPUT ;
    USE SIGNAL ;
    PORT
      LAYER M8 ;
        RECT 0.000000 502.561000 0.354000 502.623000 ;
    END
  END ETMINTNUM[5]
  PIN ETMINTNUM[4]
    DIRECTION OUTPUT ;
    USE SIGNAL ;
    PORT
      LAYER M4 ;
        RECT 503.761000 548.180000 504.136000 548.220000 ;
    END
  END ETMINTNUM[4]
  PIN ETMINTNUM[3]
    DIRECTION OUTPUT ;
    USE SIGNAL ;
    PORT
      LAYER M2 ;
        RECT MASK 1 503.907000 548.144000 504.136000 548.176000 ;
    END
  END ETMINTNUM[3]
  PIN ETMINTNUM[2]
    DIRECTION OUTPUT ;
    USE SIGNAL ;
    PORT
      LAYER M6 ;
        RECT 503.761000 547.940000 504.136000 547.980000 ;
    END
  END ETMINTNUM[2]
  PIN ETMINTNUM[1]
    DIRECTION OUTPUT ;
    USE SIGNAL ;
    PORT
      LAYER M2 ;
        RECT MASK 2 0.000000 502.640000 0.229000 502.672000 ;
    END
  END ETMINTNUM[1]
  PIN ETMINTNUM[0]
    DIRECTION OUTPUT ;
    USE SIGNAL ;
    PORT
      LAYER M2 ;
        RECT MASK 1 503.907000 547.888000 504.136000 547.920000 ;
    END
  END ETMINTNUM[0]
  PIN ETMINTSTAT[2]
    DIRECTION OUTPUT ;
    USE SIGNAL ;
    PORT
      LAYER M2 ;
        RECT MASK 2 0.000000 502.768000 0.229000 502.800000 ;
    END
  END ETMINTSTAT[2]
  PIN ETMINTSTAT[1]
    DIRECTION OUTPUT ;
    USE SIGNAL ;
    PORT
      LAYER M4 ;
        RECT 0.000000 502.740000 0.375000 502.780000 ;
    END
  END ETMINTSTAT[1]
  PIN ETMINTSTAT[0]
    DIRECTION OUTPUT ;
    USE SIGNAL ;
    PORT
      LAYER M6 ;
        RECT 0.000000 502.740000 0.375000 502.780000 ;
    END
  END ETMINTSTAT[0]
  PIN SYSRESETREQ
    DIRECTION OUTPUT ;
    USE SIGNAL ;
    PORT
      LAYER M6 ;
        RECT 0.000000 520.500000 0.375000 520.540000 ;
    END
  END SYSRESETREQ
  PIN TXEV
    DIRECTION OUTPUT ;
    USE SIGNAL ;
    PORT
      LAYER M6 ;
        RECT 503.761000 520.180000 504.136000 520.220000 ;
    END
  END TXEV
  PIN CURRPRI[7]
    DIRECTION OUTPUT ;
    USE SIGNAL ;
    PORT
      LAYER M2 ;
        RECT MASK 1 503.907000 549.680000 504.136000 549.712000 ;
    END
  END CURRPRI[7]
  PIN CURRPRI[6]
    DIRECTION OUTPUT ;
    USE SIGNAL ;
    PORT
      LAYER M6 ;
        RECT 503.761000 549.540000 504.136000 549.580000 ;
    END
  END CURRPRI[6]
  PIN CURRPRI[5]
    DIRECTION OUTPUT ;
    USE SIGNAL ;
    PORT
      LAYER M2 ;
        RECT MASK 2 0.000000 502.512000 0.229000 502.544000 ;
    END
  END CURRPRI[5]
  PIN CURRPRI[4]
    DIRECTION OUTPUT ;
    USE SIGNAL ;
    PORT
      LAYER M6 ;
        RECT 0.000000 528.340000 0.375000 528.380000 ;
    END
  END CURRPRI[4]
  PIN CURRPRI[3]
    DIRECTION OUTPUT ;
    USE SIGNAL ;
    PORT
      LAYER M6 ;
        RECT 0.000000 528.500000 0.375000 528.540000 ;
    END
  END CURRPRI[3]
  PIN CURRPRI[2]
    DIRECTION OUTPUT ;
    USE SIGNAL ;
    PORT
      LAYER M6 ;
        RECT 0.000000 528.660000 0.375000 528.700000 ;
    END
  END CURRPRI[2]
  PIN CURRPRI[1]
    DIRECTION OUTPUT ;
    USE SIGNAL ;
    PORT
      LAYER M6 ;
        RECT 0.000000 528.820000 0.375000 528.860000 ;
    END
  END CURRPRI[1]
  PIN CURRPRI[0]
    DIRECTION OUTPUT ;
    USE SIGNAL ;
    PORT
      LAYER M6 ;
        RECT 0.000000 528.980000 0.375000 529.020000 ;
    END
  END CURRPRI[0]
  PIN DBGRESTARTED
    DIRECTION OUTPUT ;
    USE SIGNAL ;
    PORT
      LAYER M2 ;
        RECT MASK 2 503.907000 517.744000 504.136000 517.776000 ;
    END
  END DBGRESTARTED
  PIN SLEEPHOLDACKn
    DIRECTION OUTPUT ;
    USE SIGNAL ;
    PORT
      LAYER M4 ;
        RECT 503.761000 518.900000 504.136000 518.940000 ;
    END
  END SLEEPHOLDACKn
  PIN GATEHCLK
    DIRECTION OUTPUT ;
    USE SIGNAL ;
    PORT
      LAYER M6 ;
        RECT 0.000000 520.660000 0.375000 520.700000 ;
    END
  END GATEHCLK
  PIN INTERNALSTATE[148]
    DIRECTION OUTPUT ;
    USE SIGNAL ;
    PORT
      LAYER M8 ;
        RECT 0.000000 528.801000 0.354000 528.863000 ;
    END
  END INTERNALSTATE[148]
  PIN INTERNALSTATE[147]
    DIRECTION OUTPUT ;
    USE SIGNAL ;
    PORT
      LAYER M8 ;
        RECT 0.000000 528.545000 0.354000 528.607000 ;
    END
  END INTERNALSTATE[147]
  PIN INTERNALSTATE[146]
    DIRECTION OUTPUT ;
    USE SIGNAL ;
    PORT
      LAYER M8 ;
        RECT 0.000000 529.057000 0.354000 529.119000 ;
    END
  END INTERNALSTATE[146]
  PIN INTERNALSTATE[145]
    DIRECTION OUTPUT ;
    USE SIGNAL ;
    PORT
      LAYER M8 ;
        RECT 0.000000 529.313000 0.354000 529.375000 ;
    END
  END INTERNALSTATE[145]
  PIN INTERNALSTATE[144]
    DIRECTION OUTPUT ;
    USE SIGNAL ;
    PORT
      LAYER M6 ;
        RECT 0.000000 529.300000 0.375000 529.340000 ;
    END
  END INTERNALSTATE[144]
  PIN INTERNALSTATE[143]
    DIRECTION OUTPUT ;
    USE SIGNAL ;
    PORT
      LAYER M6 ;
        RECT 0.000000 529.140000 0.375000 529.180000 ;
    END
  END INTERNALSTATE[143]
  PIN INTERNALSTATE[142]
    DIRECTION OUTPUT ;
    USE SIGNAL ;
    PORT
      LAYER M6 ;
        RECT 0.000000 529.460000 0.375000 529.500000 ;
    END
  END INTERNALSTATE[142]
  PIN INTERNALSTATE[141]
    DIRECTION OUTPUT ;
    USE SIGNAL ;
    PORT
      LAYER M6 ;
        RECT 0.000000 529.620000 0.375000 529.660000 ;
    END
  END INTERNALSTATE[141]
  PIN INTERNALSTATE[140]
    DIRECTION OUTPUT ;
    USE SIGNAL ;
    PORT
      LAYER M6 ;
        RECT 0.000000 529.780000 0.375000 529.820000 ;
    END
  END INTERNALSTATE[140]
  PIN INTERNALSTATE[139]
    DIRECTION OUTPUT ;
    USE SIGNAL ;
    PORT
      LAYER M6 ;
        RECT 0.000000 529.940000 0.375000 529.980000 ;
    END
  END INTERNALSTATE[139]
  PIN INTERNALSTATE[138]
    DIRECTION OUTPUT ;
    USE SIGNAL ;
    PORT
      LAYER M6 ;
        RECT 0.000000 530.100000 0.375000 530.140000 ;
    END
  END INTERNALSTATE[138]
  PIN INTERNALSTATE[137]
    DIRECTION OUTPUT ;
    USE SIGNAL ;
    PORT
      LAYER M6 ;
        RECT 0.000000 530.260000 0.375000 530.300000 ;
    END
  END INTERNALSTATE[137]
  PIN INTERNALSTATE[136]
    DIRECTION OUTPUT ;
    USE SIGNAL ;
    PORT
      LAYER M6 ;
        RECT 0.000000 530.420000 0.375000 530.460000 ;
    END
  END INTERNALSTATE[136]
  PIN INTERNALSTATE[135]
    DIRECTION OUTPUT ;
    USE SIGNAL ;
    PORT
      LAYER M6 ;
        RECT 0.000000 530.580000 0.375000 530.620000 ;
    END
  END INTERNALSTATE[135]
  PIN INTERNALSTATE[134]
    DIRECTION OUTPUT ;
    USE SIGNAL ;
    PORT
      LAYER M6 ;
        RECT 0.000000 530.740000 0.375000 530.780000 ;
    END
  END INTERNALSTATE[134]
  PIN INTERNALSTATE[133]
    DIRECTION OUTPUT ;
    USE SIGNAL ;
    PORT
      LAYER M6 ;
        RECT 0.000000 530.900000 0.375000 530.940000 ;
    END
  END INTERNALSTATE[133]
  PIN INTERNALSTATE[132]
    DIRECTION OUTPUT ;
    USE SIGNAL ;
    PORT
      LAYER M6 ;
        RECT 0.000000 531.060000 0.375000 531.100000 ;
    END
  END INTERNALSTATE[132]
  PIN INTERNALSTATE[131]
    DIRECTION OUTPUT ;
    USE SIGNAL ;
    PORT
      LAYER M6 ;
        RECT 0.000000 531.220000 0.375000 531.260000 ;
    END
  END INTERNALSTATE[131]
  PIN INTERNALSTATE[130]
    DIRECTION OUTPUT ;
    USE SIGNAL ;
    PORT
      LAYER M6 ;
        RECT 0.000000 531.380000 0.375000 531.420000 ;
    END
  END INTERNALSTATE[130]
  PIN INTERNALSTATE[129]
    DIRECTION OUTPUT ;
    USE SIGNAL ;
    PORT
      LAYER M6 ;
        RECT 0.000000 531.540000 0.375000 531.580000 ;
    END
  END INTERNALSTATE[129]
  PIN INTERNALSTATE[128]
    DIRECTION OUTPUT ;
    USE SIGNAL ;
    PORT
      LAYER M6 ;
        RECT 0.000000 531.700000 0.375000 531.740000 ;
    END
  END INTERNALSTATE[128]
  PIN INTERNALSTATE[127]
    DIRECTION OUTPUT ;
    USE SIGNAL ;
    PORT
      LAYER M6 ;
        RECT 0.000000 531.860000 0.375000 531.900000 ;
    END
  END INTERNALSTATE[127]
  PIN INTERNALSTATE[126]
    DIRECTION OUTPUT ;
    USE SIGNAL ;
    PORT
      LAYER M6 ;
        RECT 0.000000 532.020000 0.375000 532.060000 ;
    END
  END INTERNALSTATE[126]
  PIN INTERNALSTATE[125]
    DIRECTION OUTPUT ;
    USE SIGNAL ;
    PORT
      LAYER M6 ;
        RECT 0.000000 532.180000 0.375000 532.220000 ;
    END
  END INTERNALSTATE[125]
  PIN INTERNALSTATE[124]
    DIRECTION OUTPUT ;
    USE SIGNAL ;
    PORT
      LAYER M6 ;
        RECT 0.000000 532.340000 0.375000 532.380000 ;
    END
  END INTERNALSTATE[124]
  PIN INTERNALSTATE[123]
    DIRECTION OUTPUT ;
    USE SIGNAL ;
    PORT
      LAYER M6 ;
        RECT 0.000000 532.500000 0.375000 532.540000 ;
    END
  END INTERNALSTATE[123]
  PIN INTERNALSTATE[122]
    DIRECTION OUTPUT ;
    USE SIGNAL ;
    PORT
      LAYER M6 ;
        RECT 0.000000 532.660000 0.375000 532.700000 ;
    END
  END INTERNALSTATE[122]
  PIN INTERNALSTATE[121]
    DIRECTION OUTPUT ;
    USE SIGNAL ;
    PORT
      LAYER M6 ;
        RECT 0.000000 532.820000 0.375000 532.860000 ;
    END
  END INTERNALSTATE[121]
  PIN INTERNALSTATE[120]
    DIRECTION OUTPUT ;
    USE SIGNAL ;
    PORT
      LAYER M6 ;
        RECT 0.000000 532.980000 0.375000 533.020000 ;
    END
  END INTERNALSTATE[120]
  PIN INTERNALSTATE[119]
    DIRECTION OUTPUT ;
    USE SIGNAL ;
    PORT
      LAYER M6 ;
        RECT 0.000000 533.140000 0.375000 533.180000 ;
    END
  END INTERNALSTATE[119]
  PIN INTERNALSTATE[118]
    DIRECTION OUTPUT ;
    USE SIGNAL ;
    PORT
      LAYER M6 ;
        RECT 0.000000 533.300000 0.375000 533.340000 ;
    END
  END INTERNALSTATE[118]
  PIN INTERNALSTATE[117]
    DIRECTION OUTPUT ;
    USE SIGNAL ;
    PORT
      LAYER M6 ;
        RECT 0.000000 533.460000 0.375000 533.500000 ;
    END
  END INTERNALSTATE[117]
  PIN INTERNALSTATE[116]
    DIRECTION OUTPUT ;
    USE SIGNAL ;
    PORT
      LAYER M6 ;
        RECT 0.000000 533.620000 0.375000 533.660000 ;
    END
  END INTERNALSTATE[116]
  PIN INTERNALSTATE[115]
    DIRECTION OUTPUT ;
    USE SIGNAL ;
    PORT
      LAYER M6 ;
        RECT 0.000000 533.780000 0.375000 533.820000 ;
    END
  END INTERNALSTATE[115]
  PIN INTERNALSTATE[114]
    DIRECTION OUTPUT ;
    USE SIGNAL ;
    PORT
      LAYER M6 ;
        RECT 0.000000 533.940000 0.375000 533.980000 ;
    END
  END INTERNALSTATE[114]
  PIN INTERNALSTATE[113]
    DIRECTION OUTPUT ;
    USE SIGNAL ;
    PORT
      LAYER M6 ;
        RECT 0.000000 534.100000 0.375000 534.140000 ;
    END
  END INTERNALSTATE[113]
  PIN INTERNALSTATE[112]
    DIRECTION OUTPUT ;
    USE SIGNAL ;
    PORT
      LAYER M6 ;
        RECT 0.000000 534.260000 0.375000 534.300000 ;
    END
  END INTERNALSTATE[112]
  PIN INTERNALSTATE[111]
    DIRECTION OUTPUT ;
    USE SIGNAL ;
    PORT
      LAYER M6 ;
        RECT 0.000000 534.420000 0.375000 534.460000 ;
    END
  END INTERNALSTATE[111]
  PIN INTERNALSTATE[110]
    DIRECTION OUTPUT ;
    USE SIGNAL ;
    PORT
      LAYER M6 ;
        RECT 0.000000 534.580000 0.375000 534.620000 ;
    END
  END INTERNALSTATE[110]
  PIN INTERNALSTATE[109]
    DIRECTION OUTPUT ;
    USE SIGNAL ;
    PORT
      LAYER M6 ;
        RECT 0.000000 534.740000 0.375000 534.780000 ;
    END
  END INTERNALSTATE[109]
  PIN INTERNALSTATE[108]
    DIRECTION OUTPUT ;
    USE SIGNAL ;
    PORT
      LAYER M6 ;
        RECT 0.000000 534.900000 0.375000 534.940000 ;
    END
  END INTERNALSTATE[108]
  PIN INTERNALSTATE[107]
    DIRECTION OUTPUT ;
    USE SIGNAL ;
    PORT
      LAYER M6 ;
        RECT 0.000000 535.060000 0.375000 535.100000 ;
    END
  END INTERNALSTATE[107]
  PIN INTERNALSTATE[106]
    DIRECTION OUTPUT ;
    USE SIGNAL ;
    PORT
      LAYER M6 ;
        RECT 0.000000 535.220000 0.375000 535.260000 ;
    END
  END INTERNALSTATE[106]
  PIN INTERNALSTATE[105]
    DIRECTION OUTPUT ;
    USE SIGNAL ;
    PORT
      LAYER M6 ;
        RECT 0.000000 535.380000 0.375000 535.420000 ;
    END
  END INTERNALSTATE[105]
  PIN INTERNALSTATE[104]
    DIRECTION OUTPUT ;
    USE SIGNAL ;
    PORT
      LAYER M6 ;
        RECT 0.000000 535.540000 0.375000 535.580000 ;
    END
  END INTERNALSTATE[104]
  PIN INTERNALSTATE[103]
    DIRECTION OUTPUT ;
    USE SIGNAL ;
    PORT
      LAYER M6 ;
        RECT 0.000000 535.700000 0.375000 535.740000 ;
    END
  END INTERNALSTATE[103]
  PIN INTERNALSTATE[102]
    DIRECTION OUTPUT ;
    USE SIGNAL ;
    PORT
      LAYER M6 ;
        RECT 0.000000 535.860000 0.375000 535.900000 ;
    END
  END INTERNALSTATE[102]
  PIN INTERNALSTATE[101]
    DIRECTION OUTPUT ;
    USE SIGNAL ;
    PORT
      LAYER M6 ;
        RECT 0.000000 536.020000 0.375000 536.060000 ;
    END
  END INTERNALSTATE[101]
  PIN INTERNALSTATE[100]
    DIRECTION OUTPUT ;
    USE SIGNAL ;
    PORT
      LAYER M6 ;
        RECT 0.000000 536.180000 0.375000 536.220000 ;
    END
  END INTERNALSTATE[100]
  PIN INTERNALSTATE[99]
    DIRECTION OUTPUT ;
    USE SIGNAL ;
    PORT
      LAYER M6 ;
        RECT 0.000000 536.340000 0.375000 536.380000 ;
    END
  END INTERNALSTATE[99]
  PIN INTERNALSTATE[98]
    DIRECTION OUTPUT ;
    USE SIGNAL ;
    PORT
      LAYER M6 ;
        RECT 0.000000 536.500000 0.375000 536.540000 ;
    END
  END INTERNALSTATE[98]
  PIN INTERNALSTATE[97]
    DIRECTION OUTPUT ;
    USE SIGNAL ;
    PORT
      LAYER M6 ;
        RECT 0.000000 536.660000 0.375000 536.700000 ;
    END
  END INTERNALSTATE[97]
  PIN INTERNALSTATE[96]
    DIRECTION OUTPUT ;
    USE SIGNAL ;
    PORT
      LAYER M6 ;
        RECT 0.000000 536.820000 0.375000 536.860000 ;
    END
  END INTERNALSTATE[96]
  PIN INTERNALSTATE[95]
    DIRECTION OUTPUT ;
    USE SIGNAL ;
    PORT
      LAYER M6 ;
        RECT 0.000000 536.980000 0.375000 537.020000 ;
    END
  END INTERNALSTATE[95]
  PIN INTERNALSTATE[94]
    DIRECTION OUTPUT ;
    USE SIGNAL ;
    PORT
      LAYER M6 ;
        RECT 0.000000 537.140000 0.375000 537.180000 ;
    END
  END INTERNALSTATE[94]
  PIN INTERNALSTATE[93]
    DIRECTION OUTPUT ;
    USE SIGNAL ;
    PORT
      LAYER M6 ;
        RECT 0.000000 537.300000 0.375000 537.340000 ;
    END
  END INTERNALSTATE[93]
  PIN INTERNALSTATE[92]
    DIRECTION OUTPUT ;
    USE SIGNAL ;
    PORT
      LAYER M6 ;
        RECT 0.000000 537.460000 0.375000 537.500000 ;
    END
  END INTERNALSTATE[92]
  PIN INTERNALSTATE[91]
    DIRECTION OUTPUT ;
    USE SIGNAL ;
    PORT
      LAYER M6 ;
        RECT 0.000000 537.620000 0.375000 537.660000 ;
    END
  END INTERNALSTATE[91]
  PIN INTERNALSTATE[90]
    DIRECTION OUTPUT ;
    USE SIGNAL ;
    PORT
      LAYER M6 ;
        RECT 0.000000 537.780000 0.375000 537.820000 ;
    END
  END INTERNALSTATE[90]
  PIN INTERNALSTATE[89]
    DIRECTION OUTPUT ;
    USE SIGNAL ;
    PORT
      LAYER M6 ;
        RECT 0.000000 537.940000 0.375000 537.980000 ;
    END
  END INTERNALSTATE[89]
  PIN INTERNALSTATE[88]
    DIRECTION OUTPUT ;
    USE SIGNAL ;
    PORT
      LAYER M6 ;
        RECT 0.000000 538.100000 0.375000 538.140000 ;
    END
  END INTERNALSTATE[88]
  PIN INTERNALSTATE[87]
    DIRECTION OUTPUT ;
    USE SIGNAL ;
    PORT
      LAYER M6 ;
        RECT 0.000000 538.260000 0.375000 538.300000 ;
    END
  END INTERNALSTATE[87]
  PIN INTERNALSTATE[86]
    DIRECTION OUTPUT ;
    USE SIGNAL ;
    PORT
      LAYER M6 ;
        RECT 0.000000 538.420000 0.375000 538.460000 ;
    END
  END INTERNALSTATE[86]
  PIN INTERNALSTATE[85]
    DIRECTION OUTPUT ;
    USE SIGNAL ;
    PORT
      LAYER M6 ;
        RECT 0.000000 538.580000 0.375000 538.620000 ;
    END
  END INTERNALSTATE[85]
  PIN INTERNALSTATE[84]
    DIRECTION OUTPUT ;
    USE SIGNAL ;
    PORT
      LAYER M6 ;
        RECT 0.000000 538.740000 0.375000 538.780000 ;
    END
  END INTERNALSTATE[84]
  PIN INTERNALSTATE[83]
    DIRECTION OUTPUT ;
    USE SIGNAL ;
    PORT
      LAYER M6 ;
        RECT 0.000000 538.900000 0.375000 538.940000 ;
    END
  END INTERNALSTATE[83]
  PIN INTERNALSTATE[82]
    DIRECTION OUTPUT ;
    USE SIGNAL ;
    PORT
      LAYER M6 ;
        RECT 0.000000 539.060000 0.375000 539.100000 ;
    END
  END INTERNALSTATE[82]
  PIN INTERNALSTATE[81]
    DIRECTION OUTPUT ;
    USE SIGNAL ;
    PORT
      LAYER M6 ;
        RECT 0.000000 539.220000 0.375000 539.260000 ;
    END
  END INTERNALSTATE[81]
  PIN INTERNALSTATE[80]
    DIRECTION OUTPUT ;
    USE SIGNAL ;
    PORT
      LAYER M6 ;
        RECT 0.000000 539.380000 0.375000 539.420000 ;
    END
  END INTERNALSTATE[80]
  PIN INTERNALSTATE[79]
    DIRECTION OUTPUT ;
    USE SIGNAL ;
    PORT
      LAYER M6 ;
        RECT 0.000000 539.540000 0.375000 539.580000 ;
    END
  END INTERNALSTATE[79]
  PIN INTERNALSTATE[78]
    DIRECTION OUTPUT ;
    USE SIGNAL ;
    PORT
      LAYER M6 ;
        RECT 0.000000 539.700000 0.375000 539.740000 ;
    END
  END INTERNALSTATE[78]
  PIN INTERNALSTATE[77]
    DIRECTION OUTPUT ;
    USE SIGNAL ;
    PORT
      LAYER M6 ;
        RECT 0.000000 539.860000 0.375000 539.900000 ;
    END
  END INTERNALSTATE[77]
  PIN INTERNALSTATE[76]
    DIRECTION OUTPUT ;
    USE SIGNAL ;
    PORT
      LAYER M6 ;
        RECT 0.000000 540.020000 0.375000 540.060000 ;
    END
  END INTERNALSTATE[76]
  PIN INTERNALSTATE[75]
    DIRECTION OUTPUT ;
    USE SIGNAL ;
    PORT
      LAYER M6 ;
        RECT 0.000000 540.180000 0.375000 540.220000 ;
    END
  END INTERNALSTATE[75]
  PIN INTERNALSTATE[74]
    DIRECTION OUTPUT ;
    USE SIGNAL ;
    PORT
      LAYER M6 ;
        RECT 0.000000 540.340000 0.375000 540.380000 ;
    END
  END INTERNALSTATE[74]
  PIN INTERNALSTATE[73]
    DIRECTION OUTPUT ;
    USE SIGNAL ;
    PORT
      LAYER M6 ;
        RECT 0.000000 540.500000 0.375000 540.540000 ;
    END
  END INTERNALSTATE[73]
  PIN INTERNALSTATE[72]
    DIRECTION OUTPUT ;
    USE SIGNAL ;
    PORT
      LAYER M6 ;
        RECT 0.000000 540.660000 0.375000 540.700000 ;
    END
  END INTERNALSTATE[72]
  PIN INTERNALSTATE[71]
    DIRECTION OUTPUT ;
    USE SIGNAL ;
    PORT
      LAYER M6 ;
        RECT 0.000000 540.820000 0.375000 540.860000 ;
    END
  END INTERNALSTATE[71]
  PIN INTERNALSTATE[70]
    DIRECTION OUTPUT ;
    USE SIGNAL ;
    PORT
      LAYER M6 ;
        RECT 0.000000 540.980000 0.375000 541.020000 ;
    END
  END INTERNALSTATE[70]
  PIN INTERNALSTATE[69]
    DIRECTION OUTPUT ;
    USE SIGNAL ;
    PORT
      LAYER M6 ;
        RECT 0.000000 541.140000 0.375000 541.180000 ;
    END
  END INTERNALSTATE[69]
  PIN INTERNALSTATE[68]
    DIRECTION OUTPUT ;
    USE SIGNAL ;
    PORT
      LAYER M6 ;
        RECT 0.000000 541.300000 0.375000 541.340000 ;
    END
  END INTERNALSTATE[68]
  PIN INTERNALSTATE[67]
    DIRECTION OUTPUT ;
    USE SIGNAL ;
    PORT
      LAYER M6 ;
        RECT 0.000000 541.460000 0.375000 541.500000 ;
    END
  END INTERNALSTATE[67]
  PIN INTERNALSTATE[66]
    DIRECTION OUTPUT ;
    USE SIGNAL ;
    PORT
      LAYER M6 ;
        RECT 0.000000 541.620000 0.375000 541.660000 ;
    END
  END INTERNALSTATE[66]
  PIN INTERNALSTATE[65]
    DIRECTION OUTPUT ;
    USE SIGNAL ;
    PORT
      LAYER M6 ;
        RECT 0.000000 541.780000 0.375000 541.820000 ;
    END
  END INTERNALSTATE[65]
  PIN INTERNALSTATE[64]
    DIRECTION OUTPUT ;
    USE SIGNAL ;
    PORT
      LAYER M6 ;
        RECT 0.000000 541.940000 0.375000 541.980000 ;
    END
  END INTERNALSTATE[64]
  PIN INTERNALSTATE[63]
    DIRECTION OUTPUT ;
    USE SIGNAL ;
    PORT
      LAYER M6 ;
        RECT 0.000000 542.100000 0.375000 542.140000 ;
    END
  END INTERNALSTATE[63]
  PIN INTERNALSTATE[62]
    DIRECTION OUTPUT ;
    USE SIGNAL ;
    PORT
      LAYER M6 ;
        RECT 0.000000 542.260000 0.375000 542.300000 ;
    END
  END INTERNALSTATE[62]
  PIN INTERNALSTATE[61]
    DIRECTION OUTPUT ;
    USE SIGNAL ;
    PORT
      LAYER M6 ;
        RECT 0.000000 542.420000 0.375000 542.460000 ;
    END
  END INTERNALSTATE[61]
  PIN INTERNALSTATE[60]
    DIRECTION OUTPUT ;
    USE SIGNAL ;
    PORT
      LAYER M6 ;
        RECT 0.000000 542.580000 0.375000 542.620000 ;
    END
  END INTERNALSTATE[60]
  PIN INTERNALSTATE[59]
    DIRECTION OUTPUT ;
    USE SIGNAL ;
    PORT
      LAYER M6 ;
        RECT 0.000000 542.740000 0.375000 542.780000 ;
    END
  END INTERNALSTATE[59]
  PIN INTERNALSTATE[58]
    DIRECTION OUTPUT ;
    USE SIGNAL ;
    PORT
      LAYER M6 ;
        RECT 0.000000 542.900000 0.375000 542.940000 ;
    END
  END INTERNALSTATE[58]
  PIN INTERNALSTATE[57]
    DIRECTION OUTPUT ;
    USE SIGNAL ;
    PORT
      LAYER M6 ;
        RECT 0.000000 543.060000 0.375000 543.100000 ;
    END
  END INTERNALSTATE[57]
  PIN INTERNALSTATE[56]
    DIRECTION OUTPUT ;
    USE SIGNAL ;
    PORT
      LAYER M6 ;
        RECT 0.000000 543.220000 0.375000 543.260000 ;
    END
  END INTERNALSTATE[56]
  PIN INTERNALSTATE[55]
    DIRECTION OUTPUT ;
    USE SIGNAL ;
    PORT
      LAYER M6 ;
        RECT 0.000000 543.380000 0.375000 543.420000 ;
    END
  END INTERNALSTATE[55]
  PIN INTERNALSTATE[54]
    DIRECTION OUTPUT ;
    USE SIGNAL ;
    PORT
      LAYER M6 ;
        RECT 0.000000 543.540000 0.375000 543.580000 ;
    END
  END INTERNALSTATE[54]
  PIN INTERNALSTATE[53]
    DIRECTION OUTPUT ;
    USE SIGNAL ;
    PORT
      LAYER M6 ;
        RECT 0.000000 543.700000 0.375000 543.740000 ;
    END
  END INTERNALSTATE[53]
  PIN INTERNALSTATE[52]
    DIRECTION OUTPUT ;
    USE SIGNAL ;
    PORT
      LAYER M6 ;
        RECT 0.000000 543.860000 0.375000 543.900000 ;
    END
  END INTERNALSTATE[52]
  PIN INTERNALSTATE[51]
    DIRECTION OUTPUT ;
    USE SIGNAL ;
    PORT
      LAYER M6 ;
        RECT 0.000000 544.020000 0.375000 544.060000 ;
    END
  END INTERNALSTATE[51]
  PIN INTERNALSTATE[50]
    DIRECTION OUTPUT ;
    USE SIGNAL ;
    PORT
      LAYER M6 ;
        RECT 0.000000 544.180000 0.375000 544.220000 ;
    END
  END INTERNALSTATE[50]
  PIN INTERNALSTATE[49]
    DIRECTION OUTPUT ;
    USE SIGNAL ;
    PORT
      LAYER M6 ;
        RECT 0.000000 544.340000 0.375000 544.380000 ;
    END
  END INTERNALSTATE[49]
  PIN INTERNALSTATE[48]
    DIRECTION OUTPUT ;
    USE SIGNAL ;
    PORT
      LAYER M6 ;
        RECT 0.000000 544.500000 0.375000 544.540000 ;
    END
  END INTERNALSTATE[48]
  PIN INTERNALSTATE[47]
    DIRECTION OUTPUT ;
    USE SIGNAL ;
    PORT
      LAYER M6 ;
        RECT 0.000000 544.660000 0.375000 544.700000 ;
    END
  END INTERNALSTATE[47]
  PIN INTERNALSTATE[46]
    DIRECTION OUTPUT ;
    USE SIGNAL ;
    PORT
      LAYER M6 ;
        RECT 0.000000 544.820000 0.375000 544.860000 ;
    END
  END INTERNALSTATE[46]
  PIN INTERNALSTATE[45]
    DIRECTION OUTPUT ;
    USE SIGNAL ;
    PORT
      LAYER M6 ;
        RECT 0.000000 544.980000 0.375000 545.020000 ;
    END
  END INTERNALSTATE[45]
  PIN INTERNALSTATE[44]
    DIRECTION OUTPUT ;
    USE SIGNAL ;
    PORT
      LAYER M6 ;
        RECT 0.000000 545.140000 0.375000 545.180000 ;
    END
  END INTERNALSTATE[44]
  PIN INTERNALSTATE[43]
    DIRECTION OUTPUT ;
    USE SIGNAL ;
    PORT
      LAYER M6 ;
        RECT 0.000000 545.300000 0.375000 545.340000 ;
    END
  END INTERNALSTATE[43]
  PIN INTERNALSTATE[42]
    DIRECTION OUTPUT ;
    USE SIGNAL ;
    PORT
      LAYER M6 ;
        RECT 0.000000 545.460000 0.375000 545.500000 ;
    END
  END INTERNALSTATE[42]
  PIN INTERNALSTATE[41]
    DIRECTION OUTPUT ;
    USE SIGNAL ;
    PORT
      LAYER M6 ;
        RECT 0.000000 545.620000 0.375000 545.660000 ;
    END
  END INTERNALSTATE[41]
  PIN INTERNALSTATE[40]
    DIRECTION OUTPUT ;
    USE SIGNAL ;
    PORT
      LAYER M6 ;
        RECT 0.000000 545.780000 0.375000 545.820000 ;
    END
  END INTERNALSTATE[40]
  PIN INTERNALSTATE[39]
    DIRECTION OUTPUT ;
    USE SIGNAL ;
    PORT
      LAYER M6 ;
        RECT 0.000000 545.940000 0.375000 545.980000 ;
    END
  END INTERNALSTATE[39]
  PIN INTERNALSTATE[38]
    DIRECTION OUTPUT ;
    USE SIGNAL ;
    PORT
      LAYER M6 ;
        RECT 0.000000 546.100000 0.375000 546.140000 ;
    END
  END INTERNALSTATE[38]
  PIN INTERNALSTATE[37]
    DIRECTION OUTPUT ;
    USE SIGNAL ;
    PORT
      LAYER M6 ;
        RECT 0.000000 546.260000 0.375000 546.300000 ;
    END
  END INTERNALSTATE[37]
  PIN INTERNALSTATE[36]
    DIRECTION OUTPUT ;
    USE SIGNAL ;
    PORT
      LAYER M6 ;
        RECT 0.000000 546.420000 0.375000 546.460000 ;
    END
  END INTERNALSTATE[36]
  PIN INTERNALSTATE[35]
    DIRECTION OUTPUT ;
    USE SIGNAL ;
    PORT
      LAYER M6 ;
        RECT 0.000000 546.580000 0.375000 546.620000 ;
    END
  END INTERNALSTATE[35]
  PIN INTERNALSTATE[34]
    DIRECTION OUTPUT ;
    USE SIGNAL ;
    PORT
      LAYER M6 ;
        RECT 0.000000 546.740000 0.375000 546.780000 ;
    END
  END INTERNALSTATE[34]
  PIN INTERNALSTATE[33]
    DIRECTION OUTPUT ;
    USE SIGNAL ;
    PORT
      LAYER M6 ;
        RECT 0.000000 546.900000 0.375000 546.940000 ;
    END
  END INTERNALSTATE[33]
  PIN INTERNALSTATE[32]
    DIRECTION OUTPUT ;
    USE SIGNAL ;
    PORT
      LAYER M6 ;
        RECT 0.000000 547.060000 0.375000 547.100000 ;
    END
  END INTERNALSTATE[32]
  PIN INTERNALSTATE[31]
    DIRECTION OUTPUT ;
    USE SIGNAL ;
    PORT
      LAYER M6 ;
        RECT 0.000000 547.220000 0.375000 547.260000 ;
    END
  END INTERNALSTATE[31]
  PIN INTERNALSTATE[30]
    DIRECTION OUTPUT ;
    USE SIGNAL ;
    PORT
      LAYER M6 ;
        RECT 0.000000 547.380000 0.375000 547.420000 ;
    END
  END INTERNALSTATE[30]
  PIN INTERNALSTATE[29]
    DIRECTION OUTPUT ;
    USE SIGNAL ;
    PORT
      LAYER M6 ;
        RECT 0.000000 547.540000 0.375000 547.580000 ;
    END
  END INTERNALSTATE[29]
  PIN INTERNALSTATE[28]
    DIRECTION OUTPUT ;
    USE SIGNAL ;
    PORT
      LAYER M6 ;
        RECT 0.000000 547.700000 0.375000 547.740000 ;
    END
  END INTERNALSTATE[28]
  PIN INTERNALSTATE[27]
    DIRECTION OUTPUT ;
    USE SIGNAL ;
    PORT
      LAYER M6 ;
        RECT 0.000000 547.860000 0.375000 547.900000 ;
    END
  END INTERNALSTATE[27]
  PIN INTERNALSTATE[26]
    DIRECTION OUTPUT ;
    USE SIGNAL ;
    PORT
      LAYER M6 ;
        RECT 0.000000 548.020000 0.375000 548.060000 ;
    END
  END INTERNALSTATE[26]
  PIN INTERNALSTATE[25]
    DIRECTION OUTPUT ;
    USE SIGNAL ;
    PORT
      LAYER M6 ;
        RECT 0.000000 548.180000 0.375000 548.220000 ;
    END
  END INTERNALSTATE[25]
  PIN INTERNALSTATE[24]
    DIRECTION OUTPUT ;
    USE SIGNAL ;
    PORT
      LAYER M6 ;
        RECT 0.000000 548.340000 0.375000 548.380000 ;
    END
  END INTERNALSTATE[24]
  PIN INTERNALSTATE[23]
    DIRECTION OUTPUT ;
    USE SIGNAL ;
    PORT
      LAYER M6 ;
        RECT 0.000000 548.500000 0.375000 548.540000 ;
    END
  END INTERNALSTATE[23]
  PIN INTERNALSTATE[22]
    DIRECTION OUTPUT ;
    USE SIGNAL ;
    PORT
      LAYER M6 ;
        RECT 0.000000 548.660000 0.375000 548.700000 ;
    END
  END INTERNALSTATE[22]
  PIN INTERNALSTATE[21]
    DIRECTION OUTPUT ;
    USE SIGNAL ;
    PORT
      LAYER M6 ;
        RECT 0.000000 548.820000 0.375000 548.860000 ;
    END
  END INTERNALSTATE[21]
  PIN INTERNALSTATE[20]
    DIRECTION OUTPUT ;
    USE SIGNAL ;
    PORT
      LAYER M6 ;
        RECT 0.000000 548.980000 0.375000 549.020000 ;
    END
  END INTERNALSTATE[20]
  PIN INTERNALSTATE[19]
    DIRECTION OUTPUT ;
    USE SIGNAL ;
    PORT
      LAYER M6 ;
        RECT 0.000000 549.140000 0.375000 549.180000 ;
    END
  END INTERNALSTATE[19]
  PIN INTERNALSTATE[18]
    DIRECTION OUTPUT ;
    USE SIGNAL ;
    PORT
      LAYER M6 ;
        RECT 0.000000 549.300000 0.375000 549.340000 ;
    END
  END INTERNALSTATE[18]
  PIN INTERNALSTATE[17]
    DIRECTION OUTPUT ;
    USE SIGNAL ;
    PORT
      LAYER M6 ;
        RECT 0.000000 549.460000 0.375000 549.500000 ;
    END
  END INTERNALSTATE[17]
  PIN INTERNALSTATE[16]
    DIRECTION OUTPUT ;
    USE SIGNAL ;
    PORT
      LAYER M6 ;
        RECT 0.000000 549.620000 0.375000 549.660000 ;
    END
  END INTERNALSTATE[16]
  PIN INTERNALSTATE[15]
    DIRECTION OUTPUT ;
    USE SIGNAL ;
    PORT
      LAYER M6 ;
        RECT 0.000000 549.780000 0.375000 549.820000 ;
    END
  END INTERNALSTATE[15]
  PIN INTERNALSTATE[14]
    DIRECTION OUTPUT ;
    USE SIGNAL ;
    PORT
      LAYER M6 ;
        RECT 0.000000 549.940000 0.375000 549.980000 ;
    END
  END INTERNALSTATE[14]
  PIN INTERNALSTATE[13]
    DIRECTION OUTPUT ;
    USE SIGNAL ;
    PORT
      LAYER M6 ;
        RECT 0.000000 550.100000 0.375000 550.140000 ;
    END
  END INTERNALSTATE[13]
  PIN INTERNALSTATE[12]
    DIRECTION OUTPUT ;
    USE SIGNAL ;
    PORT
      LAYER M6 ;
        RECT 0.000000 550.260000 0.375000 550.300000 ;
    END
  END INTERNALSTATE[12]
  PIN INTERNALSTATE[11]
    DIRECTION OUTPUT ;
    USE SIGNAL ;
    PORT
      LAYER M6 ;
        RECT 0.000000 550.420000 0.375000 550.460000 ;
    END
  END INTERNALSTATE[11]
  PIN INTERNALSTATE[10]
    DIRECTION OUTPUT ;
    USE SIGNAL ;
    PORT
      LAYER M6 ;
        RECT 0.000000 550.580000 0.375000 550.620000 ;
    END
  END INTERNALSTATE[10]
  PIN INTERNALSTATE[9]
    DIRECTION OUTPUT ;
    USE SIGNAL ;
    PORT
      LAYER M6 ;
        RECT 0.000000 550.740000 0.375000 550.780000 ;
    END
  END INTERNALSTATE[9]
  PIN INTERNALSTATE[8]
    DIRECTION OUTPUT ;
    USE SIGNAL ;
    PORT
      LAYER M6 ;
        RECT 0.000000 550.900000 0.375000 550.940000 ;
    END
  END INTERNALSTATE[8]
  PIN INTERNALSTATE[7]
    DIRECTION OUTPUT ;
    USE SIGNAL ;
    PORT
      LAYER M6 ;
        RECT 0.000000 551.060000 0.375000 551.100000 ;
    END
  END INTERNALSTATE[7]
  PIN INTERNALSTATE[6]
    DIRECTION OUTPUT ;
    USE SIGNAL ;
    PORT
      LAYER M6 ;
        RECT 0.000000 551.220000 0.375000 551.260000 ;
    END
  END INTERNALSTATE[6]
  PIN INTERNALSTATE[5]
    DIRECTION OUTPUT ;
    USE SIGNAL ;
    PORT
      LAYER M6 ;
        RECT 0.000000 551.380000 0.375000 551.420000 ;
    END
  END INTERNALSTATE[5]
  PIN INTERNALSTATE[4]
    DIRECTION OUTPUT ;
    USE SIGNAL ;
    PORT
      LAYER M6 ;
        RECT 0.000000 551.540000 0.375000 551.580000 ;
    END
  END INTERNALSTATE[4]
  PIN INTERNALSTATE[3]
    DIRECTION OUTPUT ;
    USE SIGNAL ;
    PORT
      LAYER M6 ;
        RECT 0.000000 551.700000 0.375000 551.740000 ;
    END
  END INTERNALSTATE[3]
  PIN INTERNALSTATE[2]
    DIRECTION OUTPUT ;
    USE SIGNAL ;
    PORT
      LAYER M6 ;
        RECT 0.000000 551.860000 0.375000 551.900000 ;
    END
  END INTERNALSTATE[2]
  PIN INTERNALSTATE[1]
    DIRECTION OUTPUT ;
    USE SIGNAL ;
    PORT
      LAYER M6 ;
        RECT 0.000000 552.020000 0.375000 552.060000 ;
    END
  END INTERNALSTATE[1]
  PIN INTERNALSTATE[0]
    DIRECTION OUTPUT ;
    USE SIGNAL ;
    PORT
      LAYER M6 ;
        RECT 0.000000 552.180000 0.375000 552.220000 ;
    END
  END INTERNALSTATE[0]
  PIN HTMDHADDR[31]
    DIRECTION OUTPUT ;
    USE SIGNAL ;
    PORT
      LAYER M8 ;
        RECT 0.000000 551.969000 0.354000 552.031000 ;
    END
  END HTMDHADDR[31]
  PIN HTMDHADDR[30]
    DIRECTION OUTPUT ;
    USE SIGNAL ;
    PORT
      LAYER M8 ;
        RECT 0.000000 551.713000 0.354000 551.775000 ;
    END
  END HTMDHADDR[30]
  PIN HTMDHADDR[29]
    DIRECTION OUTPUT ;
    USE SIGNAL ;
    PORT
      LAYER M8 ;
        RECT 0.000000 551.457000 0.354000 551.519000 ;
    END
  END HTMDHADDR[29]
  PIN HTMDHADDR[28]
    DIRECTION OUTPUT ;
    USE SIGNAL ;
    PORT
      LAYER M8 ;
        RECT 0.000000 551.201000 0.354000 551.263000 ;
    END
  END HTMDHADDR[28]
  PIN HTMDHADDR[27]
    DIRECTION OUTPUT ;
    USE SIGNAL ;
    PORT
      LAYER M8 ;
        RECT 0.000000 550.945000 0.354000 551.007000 ;
    END
  END HTMDHADDR[27]
  PIN HTMDHADDR[26]
    DIRECTION OUTPUT ;
    USE SIGNAL ;
    PORT
      LAYER M8 ;
        RECT 0.000000 550.689000 0.354000 550.751000 ;
    END
  END HTMDHADDR[26]
  PIN HTMDHADDR[25]
    DIRECTION OUTPUT ;
    USE SIGNAL ;
    PORT
      LAYER M8 ;
        RECT 0.000000 550.433000 0.354000 550.495000 ;
    END
  END HTMDHADDR[25]
  PIN HTMDHADDR[24]
    DIRECTION OUTPUT ;
    USE SIGNAL ;
    PORT
      LAYER M8 ;
        RECT 0.000000 550.177000 0.354000 550.239000 ;
    END
  END HTMDHADDR[24]
  PIN HTMDHADDR[23]
    DIRECTION OUTPUT ;
    USE SIGNAL ;
    PORT
      LAYER M8 ;
        RECT 0.000000 549.921000 0.354000 549.983000 ;
    END
  END HTMDHADDR[23]
  PIN HTMDHADDR[22]
    DIRECTION OUTPUT ;
    USE SIGNAL ;
    PORT
      LAYER M8 ;
        RECT 0.000000 549.665000 0.354000 549.727000 ;
    END
  END HTMDHADDR[22]
  PIN HTMDHADDR[21]
    DIRECTION OUTPUT ;
    USE SIGNAL ;
    PORT
      LAYER M8 ;
        RECT 0.000000 549.409000 0.354000 549.471000 ;
    END
  END HTMDHADDR[21]
  PIN HTMDHADDR[20]
    DIRECTION OUTPUT ;
    USE SIGNAL ;
    PORT
      LAYER M8 ;
        RECT 0.000000 549.153000 0.354000 549.215000 ;
    END
  END HTMDHADDR[20]
  PIN HTMDHADDR[19]
    DIRECTION OUTPUT ;
    USE SIGNAL ;
    PORT
      LAYER M8 ;
        RECT 0.000000 548.897000 0.354000 548.959000 ;
    END
  END HTMDHADDR[19]
  PIN HTMDHADDR[18]
    DIRECTION OUTPUT ;
    USE SIGNAL ;
    PORT
      LAYER M8 ;
        RECT 0.000000 548.641000 0.354000 548.703000 ;
    END
  END HTMDHADDR[18]
  PIN HTMDHADDR[17]
    DIRECTION OUTPUT ;
    USE SIGNAL ;
    PORT
      LAYER M8 ;
        RECT 0.000000 548.385000 0.354000 548.447000 ;
    END
  END HTMDHADDR[17]
  PIN HTMDHADDR[16]
    DIRECTION OUTPUT ;
    USE SIGNAL ;
    PORT
      LAYER M8 ;
        RECT 0.000000 548.129000 0.354000 548.191000 ;
    END
  END HTMDHADDR[16]
  PIN HTMDHADDR[15]
    DIRECTION OUTPUT ;
    USE SIGNAL ;
    PORT
      LAYER M8 ;
        RECT 0.000000 547.873000 0.354000 547.935000 ;
    END
  END HTMDHADDR[15]
  PIN HTMDHADDR[14]
    DIRECTION OUTPUT ;
    USE SIGNAL ;
    PORT
      LAYER M8 ;
        RECT 0.000000 547.617000 0.354000 547.679000 ;
    END
  END HTMDHADDR[14]
  PIN HTMDHADDR[13]
    DIRECTION OUTPUT ;
    USE SIGNAL ;
    PORT
      LAYER M8 ;
        RECT 0.000000 547.361000 0.354000 547.423000 ;
    END
  END HTMDHADDR[13]
  PIN HTMDHADDR[12]
    DIRECTION OUTPUT ;
    USE SIGNAL ;
    PORT
      LAYER M8 ;
        RECT 0.000000 547.105000 0.354000 547.167000 ;
    END
  END HTMDHADDR[12]
  PIN HTMDHADDR[11]
    DIRECTION OUTPUT ;
    USE SIGNAL ;
    PORT
      LAYER M8 ;
        RECT 0.000000 546.849000 0.354000 546.911000 ;
    END
  END HTMDHADDR[11]
  PIN HTMDHADDR[10]
    DIRECTION OUTPUT ;
    USE SIGNAL ;
    PORT
      LAYER M8 ;
        RECT 0.000000 546.593000 0.354000 546.655000 ;
    END
  END HTMDHADDR[10]
  PIN HTMDHADDR[9]
    DIRECTION OUTPUT ;
    USE SIGNAL ;
    PORT
      LAYER M8 ;
        RECT 0.000000 546.337000 0.354000 546.399000 ;
    END
  END HTMDHADDR[9]
  PIN HTMDHADDR[8]
    DIRECTION OUTPUT ;
    USE SIGNAL ;
    PORT
      LAYER M8 ;
        RECT 0.000000 546.081000 0.354000 546.143000 ;
    END
  END HTMDHADDR[8]
  PIN HTMDHADDR[7]
    DIRECTION OUTPUT ;
    USE SIGNAL ;
    PORT
      LAYER M8 ;
        RECT 0.000000 545.825000 0.354000 545.887000 ;
    END
  END HTMDHADDR[7]
  PIN HTMDHADDR[6]
    DIRECTION OUTPUT ;
    USE SIGNAL ;
    PORT
      LAYER M8 ;
        RECT 0.000000 545.569000 0.354000 545.631000 ;
    END
  END HTMDHADDR[6]
  PIN HTMDHADDR[5]
    DIRECTION OUTPUT ;
    USE SIGNAL ;
    PORT
      LAYER M8 ;
        RECT 0.000000 545.313000 0.354000 545.375000 ;
    END
  END HTMDHADDR[5]
  PIN HTMDHADDR[4]
    DIRECTION OUTPUT ;
    USE SIGNAL ;
    PORT
      LAYER M8 ;
        RECT 0.000000 545.057000 0.354000 545.119000 ;
    END
  END HTMDHADDR[4]
  PIN HTMDHADDR[3]
    DIRECTION OUTPUT ;
    USE SIGNAL ;
    PORT
      LAYER M8 ;
        RECT 0.000000 544.801000 0.354000 544.863000 ;
    END
  END HTMDHADDR[3]
  PIN HTMDHADDR[2]
    DIRECTION OUTPUT ;
    USE SIGNAL ;
    PORT
      LAYER M8 ;
        RECT 0.000000 544.545000 0.354000 544.607000 ;
    END
  END HTMDHADDR[2]
  PIN HTMDHADDR[1]
    DIRECTION OUTPUT ;
    USE SIGNAL ;
    PORT
      LAYER M8 ;
        RECT 0.000000 544.289000 0.354000 544.351000 ;
    END
  END HTMDHADDR[1]
  PIN HTMDHADDR[0]
    DIRECTION OUTPUT ;
    USE SIGNAL ;
    PORT
      LAYER M8 ;
        RECT 0.000000 542.497000 0.354000 542.559000 ;
    END
  END HTMDHADDR[0]
  PIN HTMDHTRANS[1]
    DIRECTION OUTPUT ;
    USE SIGNAL ;
    PORT
      LAYER M8 ;
        RECT 0.000000 542.241000 0.354000 542.303000 ;
    END
  END HTMDHTRANS[1]
  PIN HTMDHTRANS[0]
    DIRECTION OUTPUT ;
    USE SIGNAL ;
    PORT
      LAYER M8 ;
        RECT 0.000000 541.985000 0.354000 542.047000 ;
    END
  END HTMDHTRANS[0]
  PIN HTMDHSIZE[2]
    DIRECTION OUTPUT ;
    USE SIGNAL ;
    PORT
      LAYER M8 ;
        RECT 0.000000 541.729000 0.354000 541.791000 ;
    END
  END HTMDHSIZE[2]
  PIN HTMDHSIZE[1]
    DIRECTION OUTPUT ;
    USE SIGNAL ;
    PORT
      LAYER M8 ;
        RECT 0.000000 541.473000 0.354000 541.535000 ;
    END
  END HTMDHSIZE[1]
  PIN HTMDHSIZE[0]
    DIRECTION OUTPUT ;
    USE SIGNAL ;
    PORT
      LAYER M8 ;
        RECT 0.000000 541.217000 0.354000 541.279000 ;
    END
  END HTMDHSIZE[0]
  PIN HTMDHBURST[2]
    DIRECTION OUTPUT ;
    USE SIGNAL ;
    PORT
      LAYER M8 ;
        RECT 0.000000 540.961000 0.354000 541.023000 ;
    END
  END HTMDHBURST[2]
  PIN HTMDHBURST[1]
    DIRECTION OUTPUT ;
    USE SIGNAL ;
    PORT
      LAYER M8 ;
        RECT 0.000000 540.705000 0.354000 540.767000 ;
    END
  END HTMDHBURST[1]
  PIN HTMDHBURST[0]
    DIRECTION OUTPUT ;
    USE SIGNAL ;
    PORT
      LAYER M8 ;
        RECT 0.000000 540.449000 0.354000 540.511000 ;
    END
  END HTMDHBURST[0]
  PIN HTMDHPROT[3]
    DIRECTION OUTPUT ;
    USE SIGNAL ;
    PORT
      LAYER M8 ;
        RECT 0.000000 540.193000 0.354000 540.255000 ;
    END
  END HTMDHPROT[3]
  PIN HTMDHPROT[2]
    DIRECTION OUTPUT ;
    USE SIGNAL ;
    PORT
      LAYER M8 ;
        RECT 0.000000 539.937000 0.354000 539.999000 ;
    END
  END HTMDHPROT[2]
  PIN HTMDHPROT[1]
    DIRECTION OUTPUT ;
    USE SIGNAL ;
    PORT
      LAYER M8 ;
        RECT 0.000000 539.681000 0.354000 539.743000 ;
    END
  END HTMDHPROT[1]
  PIN HTMDHPROT[0]
    DIRECTION OUTPUT ;
    USE SIGNAL ;
    PORT
      LAYER M8 ;
        RECT 0.000000 539.425000 0.354000 539.487000 ;
    END
  END HTMDHPROT[0]
  PIN HTMDHWDATA[31]
    DIRECTION OUTPUT ;
    USE SIGNAL ;
    PORT
      LAYER M8 ;
        RECT 0.000000 539.169000 0.354000 539.231000 ;
    END
  END HTMDHWDATA[31]
  PIN HTMDHWDATA[30]
    DIRECTION OUTPUT ;
    USE SIGNAL ;
    PORT
      LAYER M8 ;
        RECT 0.000000 538.913000 0.354000 538.975000 ;
    END
  END HTMDHWDATA[30]
  PIN HTMDHWDATA[29]
    DIRECTION OUTPUT ;
    USE SIGNAL ;
    PORT
      LAYER M8 ;
        RECT 0.000000 538.657000 0.354000 538.719000 ;
    END
  END HTMDHWDATA[29]
  PIN HTMDHWDATA[28]
    DIRECTION OUTPUT ;
    USE SIGNAL ;
    PORT
      LAYER M8 ;
        RECT 0.000000 538.401000 0.354000 538.463000 ;
    END
  END HTMDHWDATA[28]
  PIN HTMDHWDATA[27]
    DIRECTION OUTPUT ;
    USE SIGNAL ;
    PORT
      LAYER M8 ;
        RECT 0.000000 538.145000 0.354000 538.207000 ;
    END
  END HTMDHWDATA[27]
  PIN HTMDHWDATA[26]
    DIRECTION OUTPUT ;
    USE SIGNAL ;
    PORT
      LAYER M8 ;
        RECT 0.000000 537.889000 0.354000 537.951000 ;
    END
  END HTMDHWDATA[26]
  PIN HTMDHWDATA[25]
    DIRECTION OUTPUT ;
    USE SIGNAL ;
    PORT
      LAYER M8 ;
        RECT 0.000000 537.633000 0.354000 537.695000 ;
    END
  END HTMDHWDATA[25]
  PIN HTMDHWDATA[24]
    DIRECTION OUTPUT ;
    USE SIGNAL ;
    PORT
      LAYER M8 ;
        RECT 0.000000 537.377000 0.354000 537.439000 ;
    END
  END HTMDHWDATA[24]
  PIN HTMDHWDATA[23]
    DIRECTION OUTPUT ;
    USE SIGNAL ;
    PORT
      LAYER M8 ;
        RECT 0.000000 537.121000 0.354000 537.183000 ;
    END
  END HTMDHWDATA[23]
  PIN HTMDHWDATA[22]
    DIRECTION OUTPUT ;
    USE SIGNAL ;
    PORT
      LAYER M8 ;
        RECT 0.000000 536.865000 0.354000 536.927000 ;
    END
  END HTMDHWDATA[22]
  PIN HTMDHWDATA[21]
    DIRECTION OUTPUT ;
    USE SIGNAL ;
    PORT
      LAYER M8 ;
        RECT 0.000000 536.609000 0.354000 536.671000 ;
    END
  END HTMDHWDATA[21]
  PIN HTMDHWDATA[20]
    DIRECTION OUTPUT ;
    USE SIGNAL ;
    PORT
      LAYER M8 ;
        RECT 0.000000 536.353000 0.354000 536.415000 ;
    END
  END HTMDHWDATA[20]
  PIN HTMDHWDATA[19]
    DIRECTION OUTPUT ;
    USE SIGNAL ;
    PORT
      LAYER M8 ;
        RECT 0.000000 536.097000 0.354000 536.159000 ;
    END
  END HTMDHWDATA[19]
  PIN HTMDHWDATA[18]
    DIRECTION OUTPUT ;
    USE SIGNAL ;
    PORT
      LAYER M8 ;
        RECT 0.000000 535.841000 0.354000 535.903000 ;
    END
  END HTMDHWDATA[18]
  PIN HTMDHWDATA[17]
    DIRECTION OUTPUT ;
    USE SIGNAL ;
    PORT
      LAYER M8 ;
        RECT 0.000000 535.585000 0.354000 535.647000 ;
    END
  END HTMDHWDATA[17]
  PIN HTMDHWDATA[16]
    DIRECTION OUTPUT ;
    USE SIGNAL ;
    PORT
      LAYER M8 ;
        RECT 0.000000 535.329000 0.354000 535.391000 ;
    END
  END HTMDHWDATA[16]
  PIN HTMDHWDATA[15]
    DIRECTION OUTPUT ;
    USE SIGNAL ;
    PORT
      LAYER M8 ;
        RECT 0.000000 535.073000 0.354000 535.135000 ;
    END
  END HTMDHWDATA[15]
  PIN HTMDHWDATA[14]
    DIRECTION OUTPUT ;
    USE SIGNAL ;
    PORT
      LAYER M8 ;
        RECT 0.000000 534.817000 0.354000 534.879000 ;
    END
  END HTMDHWDATA[14]
  PIN HTMDHWDATA[13]
    DIRECTION OUTPUT ;
    USE SIGNAL ;
    PORT
      LAYER M8 ;
        RECT 0.000000 534.561000 0.354000 534.623000 ;
    END
  END HTMDHWDATA[13]
  PIN HTMDHWDATA[12]
    DIRECTION OUTPUT ;
    USE SIGNAL ;
    PORT
      LAYER M8 ;
        RECT 0.000000 534.305000 0.354000 534.367000 ;
    END
  END HTMDHWDATA[12]
  PIN HTMDHWDATA[11]
    DIRECTION OUTPUT ;
    USE SIGNAL ;
    PORT
      LAYER M8 ;
        RECT 0.000000 534.049000 0.354000 534.111000 ;
    END
  END HTMDHWDATA[11]
  PIN HTMDHWDATA[10]
    DIRECTION OUTPUT ;
    USE SIGNAL ;
    PORT
      LAYER M8 ;
        RECT 0.000000 533.793000 0.354000 533.855000 ;
    END
  END HTMDHWDATA[10]
  PIN HTMDHWDATA[9]
    DIRECTION OUTPUT ;
    USE SIGNAL ;
    PORT
      LAYER M8 ;
        RECT 0.000000 533.537000 0.354000 533.599000 ;
    END
  END HTMDHWDATA[9]
  PIN HTMDHWDATA[8]
    DIRECTION OUTPUT ;
    USE SIGNAL ;
    PORT
      LAYER M8 ;
        RECT 0.000000 533.281000 0.354000 533.343000 ;
    END
  END HTMDHWDATA[8]
  PIN HTMDHWDATA[7]
    DIRECTION OUTPUT ;
    USE SIGNAL ;
    PORT
      LAYER M8 ;
        RECT 0.000000 533.025000 0.354000 533.087000 ;
    END
  END HTMDHWDATA[7]
  PIN HTMDHWDATA[6]
    DIRECTION OUTPUT ;
    USE SIGNAL ;
    PORT
      LAYER M8 ;
        RECT 0.000000 532.769000 0.354000 532.831000 ;
    END
  END HTMDHWDATA[6]
  PIN HTMDHWDATA[5]
    DIRECTION OUTPUT ;
    USE SIGNAL ;
    PORT
      LAYER M8 ;
        RECT 0.000000 530.977000 0.354000 531.039000 ;
    END
  END HTMDHWDATA[5]
  PIN HTMDHWDATA[4]
    DIRECTION OUTPUT ;
    USE SIGNAL ;
    PORT
      LAYER M8 ;
        RECT 0.000000 530.721000 0.354000 530.783000 ;
    END
  END HTMDHWDATA[4]
  PIN HTMDHWDATA[3]
    DIRECTION OUTPUT ;
    USE SIGNAL ;
    PORT
      LAYER M8 ;
        RECT 0.000000 530.465000 0.354000 530.527000 ;
    END
  END HTMDHWDATA[3]
  PIN HTMDHWDATA[2]
    DIRECTION OUTPUT ;
    USE SIGNAL ;
    PORT
      LAYER M8 ;
        RECT 0.000000 530.209000 0.354000 530.271000 ;
    END
  END HTMDHWDATA[2]
  PIN HTMDHWDATA[1]
    DIRECTION OUTPUT ;
    USE SIGNAL ;
    PORT
      LAYER M8 ;
        RECT 0.000000 529.953000 0.354000 530.015000 ;
    END
  END HTMDHWDATA[1]
  PIN HTMDHWDATA[0]
    DIRECTION OUTPUT ;
    USE SIGNAL ;
    PORT
      LAYER M8 ;
        RECT 0.000000 529.697000 0.354000 529.759000 ;
    END
  END HTMDHWDATA[0]
  PIN HTMDHWRITE
    DIRECTION OUTPUT ;
    USE SIGNAL ;
    PORT
      LAYER M2 ;
        RECT MASK 1 0.000000 1.968000 0.229000 2.000000 ;
    END
  END HTMDHWRITE
  PIN HTMDHRDATA[31]
    DIRECTION OUTPUT ;
    USE SIGNAL ;
    PORT
      LAYER M4 ;
        RECT 0.000000 537.140000 0.375000 537.180000 ;
    END
  END HTMDHRDATA[31]
  PIN HTMDHRDATA[30]
    DIRECTION OUTPUT ;
    USE SIGNAL ;
    PORT
      LAYER M2 ;
        RECT MASK 1 0.000000 537.136000 0.229000 537.168000 ;
    END
  END HTMDHRDATA[30]
  PIN HTMDHRDATA[29]
    DIRECTION OUTPUT ;
    USE SIGNAL ;
    PORT
      LAYER M2 ;
        RECT MASK 1 0.000000 537.264000 0.229000 537.296000 ;
    END
  END HTMDHRDATA[29]
  PIN HTMDHRDATA[28]
    DIRECTION OUTPUT ;
    USE SIGNAL ;
    PORT
      LAYER M2 ;
        RECT MASK 1 0.000000 537.392000 0.229000 537.424000 ;
    END
  END HTMDHRDATA[28]
  PIN HTMDHRDATA[27]
    DIRECTION OUTPUT ;
    USE SIGNAL ;
    PORT
      LAYER M2 ;
        RECT MASK 1 0.000000 537.520000 0.229000 537.552000 ;
    END
  END HTMDHRDATA[27]
  PIN HTMDHRDATA[26]
    DIRECTION OUTPUT ;
    USE SIGNAL ;
    PORT
      LAYER M2 ;
        RECT MASK 1 0.000000 537.648000 0.229000 537.680000 ;
    END
  END HTMDHRDATA[26]
  PIN HTMDHRDATA[25]
    DIRECTION OUTPUT ;
    USE SIGNAL ;
    PORT
      LAYER M4 ;
        RECT 0.000000 537.620000 0.375000 537.660000 ;
    END
  END HTMDHRDATA[25]
  PIN HTMDHRDATA[24]
    DIRECTION OUTPUT ;
    USE SIGNAL ;
    PORT
      LAYER M4 ;
        RECT 0.000000 537.460000 0.375000 537.500000 ;
    END
  END HTMDHRDATA[24]
  PIN HTMDHRDATA[23]
    DIRECTION OUTPUT ;
    USE SIGNAL ;
    PORT
      LAYER M4 ;
        RECT 0.000000 537.300000 0.375000 537.340000 ;
    END
  END HTMDHRDATA[23]
  PIN HTMDHRDATA[22]
    DIRECTION OUTPUT ;
    USE SIGNAL ;
    PORT
      LAYER M6 ;
        RECT 0.000000 552.340000 0.375000 552.380000 ;
    END
  END HTMDHRDATA[22]
  PIN HTMDHRDATA[21]
    DIRECTION OUTPUT ;
    USE SIGNAL ;
    PORT
      LAYER M6 ;
        RECT 0.000000 552.500000 0.375000 552.540000 ;
    END
  END HTMDHRDATA[21]
  PIN HTMDHRDATA[20]
    DIRECTION OUTPUT ;
    USE SIGNAL ;
    PORT
      LAYER M6 ;
        RECT 0.000000 552.660000 0.375000 552.700000 ;
    END
  END HTMDHRDATA[20]
  PIN HTMDHRDATA[19]
    DIRECTION OUTPUT ;
    USE SIGNAL ;
    PORT
      LAYER M6 ;
        RECT 0.000000 552.820000 0.375000 552.860000 ;
    END
  END HTMDHRDATA[19]
  PIN HTMDHRDATA[18]
    DIRECTION OUTPUT ;
    USE SIGNAL ;
    PORT
      LAYER M6 ;
        RECT 0.000000 552.980000 0.375000 553.020000 ;
    END
  END HTMDHRDATA[18]
  PIN HTMDHRDATA[17]
    DIRECTION OUTPUT ;
    USE SIGNAL ;
    PORT
      LAYER M6 ;
        RECT 0.000000 553.140000 0.375000 553.180000 ;
    END
  END HTMDHRDATA[17]
  PIN HTMDHRDATA[16]
    DIRECTION OUTPUT ;
    USE SIGNAL ;
    PORT
      LAYER M6 ;
        RECT 0.000000 553.300000 0.375000 553.340000 ;
    END
  END HTMDHRDATA[16]
  PIN HTMDHRDATA[15]
    DIRECTION OUTPUT ;
    USE SIGNAL ;
    PORT
      LAYER M6 ;
        RECT 0.000000 553.460000 0.375000 553.500000 ;
    END
  END HTMDHRDATA[15]
  PIN HTMDHRDATA[14]
    DIRECTION OUTPUT ;
    USE SIGNAL ;
    PORT
      LAYER M6 ;
        RECT 0.000000 553.620000 0.375000 553.660000 ;
    END
  END HTMDHRDATA[14]
  PIN HTMDHRDATA[13]
    DIRECTION OUTPUT ;
    USE SIGNAL ;
    PORT
      LAYER M6 ;
        RECT 0.000000 553.780000 0.375000 553.820000 ;
    END
  END HTMDHRDATA[13]
  PIN HTMDHRDATA[12]
    DIRECTION OUTPUT ;
    USE SIGNAL ;
    PORT
      LAYER M6 ;
        RECT 0.000000 553.940000 0.375000 553.980000 ;
    END
  END HTMDHRDATA[12]
  PIN HTMDHRDATA[11]
    DIRECTION OUTPUT ;
    USE SIGNAL ;
    PORT
      LAYER M6 ;
        RECT 0.000000 554.100000 0.375000 554.140000 ;
    END
  END HTMDHRDATA[11]
  PIN HTMDHRDATA[10]
    DIRECTION OUTPUT ;
    USE SIGNAL ;
    PORT
      LAYER M6 ;
        RECT 0.000000 554.260000 0.375000 554.300000 ;
    END
  END HTMDHRDATA[10]
  PIN HTMDHRDATA[9]
    DIRECTION OUTPUT ;
    USE SIGNAL ;
    PORT
      LAYER M6 ;
        RECT 0.000000 554.420000 0.375000 554.460000 ;
    END
  END HTMDHRDATA[9]
  PIN HTMDHRDATA[8]
    DIRECTION OUTPUT ;
    USE SIGNAL ;
    PORT
      LAYER M6 ;
        RECT 0.000000 554.580000 0.375000 554.620000 ;
    END
  END HTMDHRDATA[8]
  PIN HTMDHRDATA[7]
    DIRECTION OUTPUT ;
    USE SIGNAL ;
    PORT
      LAYER M6 ;
        RECT 0.000000 554.740000 0.375000 554.780000 ;
    END
  END HTMDHRDATA[7]
  PIN HTMDHRDATA[6]
    DIRECTION OUTPUT ;
    USE SIGNAL ;
    PORT
      LAYER M6 ;
        RECT 0.000000 554.900000 0.375000 554.940000 ;
    END
  END HTMDHRDATA[6]
  PIN HTMDHRDATA[5]
    DIRECTION OUTPUT ;
    USE SIGNAL ;
    PORT
      LAYER M6 ;
        RECT 0.000000 555.060000 0.375000 555.100000 ;
    END
  END HTMDHRDATA[5]
  PIN HTMDHRDATA[4]
    DIRECTION OUTPUT ;
    USE SIGNAL ;
    PORT
      LAYER M6 ;
        RECT 0.000000 555.220000 0.375000 555.260000 ;
    END
  END HTMDHRDATA[4]
  PIN HTMDHRDATA[3]
    DIRECTION OUTPUT ;
    USE SIGNAL ;
    PORT
      LAYER M6 ;
        RECT 0.000000 555.380000 0.375000 555.420000 ;
    END
  END HTMDHRDATA[3]
  PIN HTMDHRDATA[2]
    DIRECTION OUTPUT ;
    USE SIGNAL ;
    PORT
      LAYER M6 ;
        RECT 0.000000 555.540000 0.375000 555.580000 ;
    END
  END HTMDHRDATA[2]
  PIN HTMDHRDATA[1]
    DIRECTION OUTPUT ;
    USE SIGNAL ;
    PORT
      LAYER M6 ;
        RECT 0.000000 555.700000 0.375000 555.740000 ;
    END
  END HTMDHRDATA[1]
  PIN HTMDHRDATA[0]
    DIRECTION OUTPUT ;
    USE SIGNAL ;
    PORT
      LAYER M6 ;
        RECT 0.000000 555.860000 0.375000 555.900000 ;
    END
  END HTMDHRDATA[0]
  PIN HTMDHREADY
    DIRECTION OUTPUT ;
    USE SIGNAL ;
    PORT
      LAYER M4 ;
        RECT 0.000000 1.940000 0.375000 1.980000 ;
    END
  END HTMDHREADY
  PIN HTMDHRESP[1]
    DIRECTION OUTPUT ;
    USE SIGNAL ;
    PORT
      LAYER M8 ;
        RECT 0.000000 555.681000 0.354000 555.743000 ;
    END
  END HTMDHRESP[1]
  PIN HTMDHRESP[0]
    DIRECTION OUTPUT ;
    USE SIGNAL ;
    PORT
      LAYER M8 ;
        RECT 0.000000 555.937000 0.354000 555.999000 ;
    END
  END HTMDHRESP[0]
  PIN WICENACK
    DIRECTION OUTPUT ;
    USE SIGNAL ;
    PORT
      LAYER M6 ;
        RECT 0.000000 1.940000 0.375000 1.980000 ;
    END
  END WICENACK
  PIN WAKEUP
    DIRECTION OUTPUT ;
    USE SIGNAL ;
    PORT
      LAYER M8 ;
        RECT 0.000000 552.225000 0.354000 552.287000 ;
    END
  END WAKEUP
  PIN PWRUPREADY
    DIRECTION OUTPUT ;
    USE SIGNAL ;
    PORT
      LAYER M3 ;
        RECT MASK 2 252.086000 916.991000 252.124000 917.184000 ;
    END
  END PWRUPREADY
  PIN dft_scanenable
    DIRECTION INPUT ;
    USE SIGNAL ;
    PORT
      LAYER M6 ;
        RECT 503.761000 520.820000 504.136000 520.860000 ;
    END
  END dft_scanenable
  PIN dft_tstmode
    DIRECTION INPUT ;
    USE SIGNAL ;
    PORT
      LAYER M2 ;
        RECT MASK 2 503.907000 521.072000 504.136000 521.104000 ;
    END
  END dft_tstmode
  PIN DFT_sdi_1
    DIRECTION INPUT ;
    USE SIGNAL ;
    PORT
      LAYER M6 ;
        RECT 503.761000 521.620000 504.136000 521.660000 ;
    END
  END DFT_sdi_1
  PIN DFT_sdo_1
    DIRECTION OUTPUT ;
    USE SIGNAL ;
    PORT
      LAYER M2 ;
        RECT MASK 2 503.907000 518.896000 504.136000 518.928000 ;
    END
  END DFT_sdo_1
  PIN DFT_sdi_2
    DIRECTION INPUT ;
    USE SIGNAL ;
    PORT
      LAYER M6 ;
        RECT 0.000000 520.820000 0.375000 520.860000 ;
    END
  END DFT_sdi_2
  PIN DFT_sdo_2
    DIRECTION OUTPUT ;
    USE SIGNAL ;
    PORT
      LAYER M4 ;
        RECT 503.761000 520.020000 504.136000 520.060000 ;
    END
  END DFT_sdo_2
  PIN DFT_sdi_3
    DIRECTION INPUT ;
    USE SIGNAL ;
    PORT
      LAYER M4 ;
        RECT 503.761000 520.820000 504.136000 520.860000 ;
    END
  END DFT_sdi_3
  PIN DFT_sdo_3
    DIRECTION OUTPUT ;
    USE SIGNAL ;
    PORT
      LAYER M4 ;
        RECT 503.761000 514.020000 504.136000 514.060000 ;
    END
  END DFT_sdo_3
  PIN DFT_sdi_4
    DIRECTION INPUT ;
    USE SIGNAL ;
    PORT
      LAYER M6 ;
        RECT 0.000000 520.980000 0.375000 521.020000 ;
    END
  END DFT_sdi_4
  PIN DFT_sdo_4
    DIRECTION OUTPUT ;
    USE SIGNAL ;
    PORT
      LAYER M2 ;
        RECT MASK 2 503.907000 514.288000 504.136000 514.320000 ;
    END
  END DFT_sdo_4
  PIN DFT_sdi_5
    DIRECTION INPUT ;
    USE SIGNAL ;
    PORT
      LAYER M2 ;
        RECT MASK 2 503.907000 520.816000 504.136000 520.848000 ;
    END
  END DFT_sdi_5
  PIN DFT_sdo_5
    DIRECTION OUTPUT ;
    USE SIGNAL ;
    PORT
      LAYER M2 ;
        RECT MASK 1 503.907000 530.992000 504.136000 531.024000 ;
    END
  END DFT_sdo_5
  PIN DFT_sdi_6
    DIRECTION INPUT ;
    USE SIGNAL ;
    PORT
      LAYER M6 ;
        RECT 0.000000 521.140000 0.375000 521.180000 ;
    END
  END DFT_sdi_6
  PIN DFT_sdo_6
    DIRECTION OUTPUT ;
    USE SIGNAL ;
    PORT
      LAYER M8 ;
        RECT 0.000000 521.121000 0.354000 521.183000 ;
    END
  END DFT_sdo_6
  PIN DFT_sdi_7
    DIRECTION INPUT ;
    USE SIGNAL ;
    PORT
      LAYER M8 ;
        RECT 503.782000 521.249000 504.136000 521.311000 ;
    END
  END DFT_sdi_7
  PIN DFT_sdo_7
    DIRECTION OUTPUT ;
    USE SIGNAL ;
    PORT
      LAYER M6 ;
        RECT 503.761000 530.980000 504.136000 531.020000 ;
    END
  END DFT_sdo_7
  PIN DFT_sdi_8
    DIRECTION INPUT ;
    USE SIGNAL ;
    PORT
      LAYER M4 ;
        RECT 503.761000 521.620000 504.136000 521.660000 ;
    END
  END DFT_sdi_8
  PIN DFT_sdo_8
    DIRECTION OUTPUT ;
    USE SIGNAL ;
    PORT
      LAYER M4 ;
        RECT 503.761000 530.900000 504.136000 530.940000 ;
    END
  END DFT_sdo_8
  PIN DFT_sdi_9
    DIRECTION INPUT ;
    USE SIGNAL ;
    PORT
      LAYER M6 ;
        RECT 0.000000 521.300000 0.375000 521.340000 ;
    END
  END DFT_sdi_9
  PIN DFT_sdo_9
    DIRECTION OUTPUT ;
    USE SIGNAL ;
    PORT
      LAYER M2 ;
        RECT MASK 1 503.907000 530.736000 504.136000 530.768000 ;
    END
  END DFT_sdo_9
  PIN DFT_sdi_10
    DIRECTION INPUT ;
    USE SIGNAL ;
    PORT
      LAYER M2 ;
        RECT MASK 2 503.907000 520.176000 504.136000 520.208000 ;
    END
  END DFT_sdi_10
  PIN DFT_sdo_10
    DIRECTION OUTPUT ;
    USE SIGNAL ;
    PORT
      LAYER M6 ;
        RECT 503.761000 530.660000 504.136000 530.700000 ;
    END
  END DFT_sdo_10
  PIN DFT_sdi_11
    DIRECTION INPUT ;
    USE SIGNAL ;
    PORT
      LAYER M8 ;
        RECT 0.000000 521.377000 0.354000 521.439000 ;
    END
  END DFT_sdi_11
  PIN DFT_sdo_11
    DIRECTION OUTPUT ;
    USE SIGNAL ;
    PORT
      LAYER M2 ;
        RECT MASK 2 503.907000 522.224000 504.136000 522.256000 ;
    END
  END DFT_sdo_11
  PIN DFT_sdi_12
    DIRECTION INPUT ;
    USE SIGNAL ;
    PORT
      LAYER M8 ;
        RECT 503.782000 522.401000 504.136000 522.463000 ;
    END
  END DFT_sdi_12
  PIN DFT_sdo_12
    DIRECTION OUTPUT ;
    USE SIGNAL ;
    PORT
      LAYER M6 ;
        RECT 0.000000 521.460000 0.375000 521.500000 ;
    END
  END DFT_sdo_12
  PIN DFT_sdi_13
    DIRECTION INPUT ;
    USE SIGNAL ;
    PORT
      LAYER M2 ;
        RECT MASK 2 503.907000 513.904000 504.136000 513.936000 ;
    END
  END DFT_sdi_13
  PIN DFT_sdo_13
    DIRECTION OUTPUT ;
    USE SIGNAL ;
    PORT
      LAYER M6 ;
        RECT 503.761000 522.820000 504.136000 522.860000 ;
    END
  END DFT_sdo_13
  PIN DFT_sdi_14
    DIRECTION INPUT ;
    USE SIGNAL ;
    PORT
      LAYER M4 ;
        RECT 503.761000 522.820000 504.136000 522.860000 ;
    END
  END DFT_sdi_14
  PIN DFT_sdo_14
    DIRECTION OUTPUT ;
    USE SIGNAL ;
    PORT
      LAYER M6 ;
        RECT 0.000000 521.620000 0.375000 521.660000 ;
    END
  END DFT_sdo_14
  PIN DFT_sdi_15
    DIRECTION INPUT ;
    USE SIGNAL ;
    PORT
      LAYER M6 ;
        RECT 503.761000 521.300000 504.136000 521.340000 ;
    END
  END DFT_sdi_15
  PIN DFT_sdo_15
    DIRECTION OUTPUT ;
    USE SIGNAL ;
    PORT
      LAYER M2 ;
        RECT MASK 2 503.907000 522.864000 504.136000 522.896000 ;
    END
  END DFT_sdo_15
  PIN DFT_sdi_16
    DIRECTION INPUT ;
    USE SIGNAL ;
    PORT
      LAYER M8 ;
        RECT 0.000000 521.633000 0.354000 521.695000 ;
    END
  END DFT_sdi_16
  PIN DFT_sdo_16
    DIRECTION OUTPUT ;
    USE SIGNAL ;
    PORT
      LAYER M8 ;
        RECT 503.782000 530.465000 504.136000 530.527000 ;
    END
  END DFT_sdo_16
  PIN DFT_sdi_17
    DIRECTION INPUT ;
    USE SIGNAL ;
    PORT
      LAYER M8 ;
        RECT 503.782000 521.889000 504.136000 521.951000 ;
    END
  END DFT_sdi_17
  PIN DFT_sdo_17
    DIRECTION OUTPUT ;
    USE SIGNAL ;
    PORT
      LAYER M6 ;
        RECT 0.000000 521.780000 0.375000 521.820000 ;
    END
  END DFT_sdo_17
  PIN DFT_sdi_18
    DIRECTION INPUT ;
    USE SIGNAL ;
    PORT
      LAYER M6 ;
        RECT 503.761000 521.940000 504.136000 521.980000 ;
    END
  END DFT_sdi_18
  PIN DFT_sdo_18
    DIRECTION OUTPUT ;
    USE SIGNAL ;
    PORT
      LAYER M2 ;
        RECT MASK 1 503.907000 530.480000 504.136000 530.512000 ;
    END
  END DFT_sdo_18
  PIN DFT_sdi_19
    DIRECTION INPUT ;
    USE SIGNAL ;
    PORT
      LAYER M4 ;
        RECT 503.761000 521.940000 504.136000 521.980000 ;
    END
  END DFT_sdi_19
  PIN DFT_sdo_19
    DIRECTION OUTPUT ;
    USE SIGNAL ;
    PORT
      LAYER M6 ;
        RECT 0.000000 521.940000 0.375000 521.980000 ;
    END
  END DFT_sdo_19
  PIN DFT_sdi_20
    DIRECTION INPUT ;
    USE SIGNAL ;
    PORT
      LAYER M8 ;
        RECT 0.000000 521.889000 0.354000 521.951000 ;
    END
  END DFT_sdi_20
  PIN DFT_sdo_20
    DIRECTION OUTPUT ;
    USE SIGNAL ;
    PORT
      LAYER M6 ;
        RECT 503.761000 530.340000 504.136000 530.380000 ;
    END
  END DFT_sdo_20
  PIN DFT_sdi_21
    DIRECTION INPUT ;
    USE SIGNAL ;
    PORT
      LAYER M2 ;
        RECT MASK 2 503.907000 521.968000 504.136000 522.000000 ;
    END
  END DFT_sdi_21
  PIN DFT_sdo_21
    DIRECTION OUTPUT ;
    USE SIGNAL ;
    PORT
      LAYER M8 ;
        RECT 503.782000 523.169000 504.136000 523.231000 ;
    END
  END DFT_sdo_21
  PIN DFT_sdi_22
    DIRECTION INPUT ;
    USE SIGNAL ;
    PORT
      LAYER M2 ;
        RECT MASK 2 503.907000 523.376000 504.136000 523.408000 ;
    END
  END DFT_sdi_22
  PIN DFT_sdo_22
    DIRECTION OUTPUT ;
    USE SIGNAL ;
    PORT
      LAYER M8 ;
        RECT 503.782000 523.681000 504.136000 523.743000 ;
    END
  END DFT_sdo_22
  PIN DFT_sdi_23
    DIRECTION INPUT ;
    USE SIGNAL ;
    PORT
      LAYER M6 ;
        RECT 0.000000 522.100000 0.375000 522.140000 ;
    END
  END DFT_sdi_23
  PIN DFT_sdo_23
    DIRECTION OUTPUT ;
    USE SIGNAL ;
    PORT
      LAYER M6 ;
        RECT 503.761000 523.940000 504.136000 523.980000 ;
    END
  END DFT_sdo_23
  PIN DFT_sdi_24
    DIRECTION INPUT ;
    USE SIGNAL ;
    PORT
      LAYER M4 ;
        RECT 503.761000 521.300000 504.136000 521.340000 ;
    END
  END DFT_sdi_24
  PIN DFT_sdo_24
    DIRECTION OUTPUT ;
    USE SIGNAL ;
    PORT
      LAYER M8 ;
        RECT 0.000000 522.145000 0.354000 522.207000 ;
    END
  END DFT_sdo_24
  PIN DFT_sdi_25
    DIRECTION INPUT ;
    USE SIGNAL ;
    PORT
      LAYER M2 ;
        RECT MASK 2 503.907000 521.712000 504.136000 521.744000 ;
    END
  END DFT_sdi_25
  PIN DFT_sdo_25
    DIRECTION OUTPUT ;
    USE SIGNAL ;
    PORT
      LAYER M4 ;
        RECT 503.761000 523.940000 504.136000 523.980000 ;
    END
  END DFT_sdo_25
  PIN DFT_sdi_26
    DIRECTION INPUT ;
    USE SIGNAL ;
    PORT
      LAYER M6 ;
        RECT 0.000000 522.260000 0.375000 522.300000 ;
    END
  END DFT_sdi_26
  PIN DFT_sdo_26
    DIRECTION OUTPUT ;
    USE SIGNAL ;
    PORT
      LAYER M2 ;
        RECT MASK 1 503.907000 530.224000 504.136000 530.256000 ;
    END
  END DFT_sdo_26
  PIN DFT_sdi_27
    DIRECTION INPUT ;
    USE SIGNAL ;
    PORT
      LAYER M6 ;
        RECT 503.761000 523.140000 504.136000 523.180000 ;
    END
  END DFT_sdi_27
  PIN DFT_sdo_27
    DIRECTION OUTPUT ;
    USE SIGNAL ;
    PORT
      LAYER M8 ;
        RECT 503.782000 529.953000 504.136000 530.015000 ;
    END
  END DFT_sdo_27
  PIN DFT_sdi_28
    DIRECTION INPUT ;
    USE SIGNAL ;
    PORT
      LAYER M6 ;
        RECT 0.000000 522.420000 0.375000 522.460000 ;
    END
  END DFT_sdi_28
  PIN DFT_sdo_28
    DIRECTION OUTPUT ;
    USE SIGNAL ;
    PORT
      LAYER M8 ;
        RECT 0.000000 522.401000 0.354000 522.463000 ;
    END
  END DFT_sdo_28
  PIN DFT_sdi_29
    DIRECTION INPUT ;
    USE SIGNAL ;
    PORT
      LAYER M6 ;
        RECT 503.761000 522.500000 504.136000 522.540000 ;
    END
  END DFT_sdi_29
  PIN DFT_sdo_29
    DIRECTION OUTPUT ;
    USE SIGNAL ;
    PORT
      LAYER M4 ;
        RECT 503.761000 529.700000 504.136000 529.740000 ;
    END
  END DFT_sdo_29
  PIN DFT_sdi_30
    DIRECTION INPUT ;
    USE SIGNAL ;
    PORT
      LAYER M4 ;
        RECT 503.761000 523.140000 504.136000 523.180000 ;
    END
  END DFT_sdi_30
  PIN DFT_sdo_30
    DIRECTION OUTPUT ;
    USE SIGNAL ;
    PORT
      LAYER M2 ;
        RECT MASK 2 503.907000 529.648000 504.136000 529.680000 ;
    END
  END DFT_sdo_30
  PIN DFT_sdi_31
    DIRECTION INPUT ;
    USE SIGNAL ;
    PORT
      LAYER M6 ;
        RECT 0.000000 522.580000 0.375000 522.620000 ;
    END
  END DFT_sdi_31
  PIN DFT_sdo_31
    DIRECTION OUTPUT ;
    USE SIGNAL ;
    PORT
      LAYER M6 ;
        RECT 503.761000 529.460000 504.136000 529.500000 ;
    END
  END DFT_sdo_31
  PIN DFT_sdi_32
    DIRECTION INPUT ;
    USE SIGNAL ;
    PORT
      LAYER M4 ;
        RECT 503.761000 522.500000 504.136000 522.540000 ;
    END
  END DFT_sdi_32
  PIN DFT_sdo_32
    DIRECTION OUTPUT ;
    USE SIGNAL ;
    PORT
      LAYER M2 ;
        RECT MASK 2 503.907000 524.016000 504.136000 524.048000 ;
    END
  END DFT_sdo_32
  PIN DFT_sdi_33
    DIRECTION INPUT ;
    USE SIGNAL ;
    PORT
      LAYER M8 ;
        RECT 0.000000 522.657000 0.354000 522.719000 ;
    END
  END DFT_sdi_33
  PIN DFT_sdo_33
    DIRECTION OUTPUT ;
    USE SIGNAL ;
    PORT
      LAYER M2 ;
        RECT MASK 2 503.907000 525.040000 504.136000 525.072000 ;
    END
  END DFT_sdo_33
  PIN DFT_sdi_34
    DIRECTION INPUT ;
    USE SIGNAL ;
    PORT
      LAYER M2 ;
        RECT MASK 2 503.907000 523.120000 504.136000 523.152000 ;
    END
  END DFT_sdi_34
  PIN DFT_sdo_34
    DIRECTION OUTPUT ;
    USE SIGNAL ;
    PORT
      LAYER M6 ;
        RECT 0.000000 522.740000 0.375000 522.780000 ;
    END
  END DFT_sdo_34
  PIN DFT_sdi_35
    DIRECTION INPUT ;
    USE SIGNAL ;
    PORT
      LAYER M2 ;
        RECT MASK 2 503.907000 521.328000 504.136000 521.360000 ;
    END
  END DFT_sdi_35
  PIN DFT_sdo_35
    DIRECTION OUTPUT ;
    USE SIGNAL ;
    PORT
      LAYER M6 ;
        RECT 503.761000 526.260000 504.136000 526.300000 ;
    END
  END DFT_sdo_35
  PIN DFT_sdi_36
    DIRECTION INPUT ;
    USE SIGNAL ;
    PORT
      LAYER M8 ;
        RECT 503.782000 524.193000 504.136000 524.255000 ;
    END
  END DFT_sdi_36
  PIN DFT_sdo_36
    DIRECTION OUTPUT ;
    USE SIGNAL ;
    PORT
      LAYER M6 ;
        RECT 0.000000 522.900000 0.375000 522.940000 ;
    END
  END DFT_sdo_36
  PIN DFT_sdi_37
    DIRECTION INPUT ;
    USE SIGNAL ;
    PORT
      LAYER M6 ;
        RECT 503.761000 524.260000 504.136000 524.300000 ;
    END
  END DFT_sdi_37
  PIN DFT_sdo_37
    DIRECTION OUTPUT ;
    USE SIGNAL ;
    PORT
      LAYER M6 ;
        RECT 503.761000 529.140000 504.136000 529.180000 ;
    END
  END DFT_sdo_37
  PIN DFT_sdi_38
    DIRECTION INPUT ;
    USE SIGNAL ;
    PORT
      LAYER M8 ;
        RECT 0.000000 522.913000 0.354000 522.975000 ;
    END
  END DFT_sdi_38
  PIN DFT_sdo_38
    DIRECTION OUTPUT ;
    USE SIGNAL ;
    PORT
      LAYER M2 ;
        RECT MASK 1 503.907000 529.072000 504.136000 529.104000 ;
    END
  END DFT_sdo_38
  PIN DFT_sdi_39
    DIRECTION INPUT ;
    USE SIGNAL ;
    PORT
      LAYER M4 ;
        RECT 503.761000 524.260000 504.136000 524.300000 ;
    END
  END DFT_sdi_39
  PIN DFT_sdo_39
    DIRECTION OUTPUT ;
    USE SIGNAL ;
    PORT
      LAYER M6 ;
        RECT 0.000000 523.060000 0.375000 523.100000 ;
    END
  END DFT_sdo_39
  PIN DFT_sdi_40
    DIRECTION INPUT ;
    USE SIGNAL ;
    PORT
      LAYER M4 ;
        RECT 503.761000 531.220000 504.136000 531.260000 ;
    END
  END DFT_sdi_40
  PIN DFT_sdo_40
    DIRECTION OUTPUT ;
    USE SIGNAL ;
    PORT
      LAYER M8 ;
        RECT 503.782000 530.977000 504.136000 531.039000 ;
    END
  END DFT_sdo_40
  PIN DFT_sdi_41
    DIRECTION INPUT ;
    USE SIGNAL ;
    PORT
      LAYER M2 ;
        RECT MASK 2 503.907000 524.528000 504.136000 524.560000 ;
    END
  END DFT_sdi_41
  PIN DFT_sdo_41
    DIRECTION OUTPUT ;
    USE SIGNAL ;
    PORT
      LAYER M6 ;
        RECT 0.000000 523.220000 0.375000 523.260000 ;
    END
  END DFT_sdo_41
  PIN DFT_sdi_42
    DIRECTION INPUT ;
    USE SIGNAL ;
    PORT
      LAYER M8 ;
        RECT 0.000000 523.169000 0.354000 523.231000 ;
    END
  END DFT_sdi_42
  PIN DFT_sdo_42
    DIRECTION OUTPUT ;
    USE SIGNAL ;
    PORT
      LAYER M2 ;
        RECT MASK 2 503.907000 526.064000 504.136000 526.096000 ;
    END
  END DFT_sdo_42
  PIN DFT_sdi_43
    DIRECTION INPUT ;
    USE SIGNAL ;
    PORT
      LAYER M2 ;
        RECT MASK 2 503.907000 522.480000 504.136000 522.512000 ;
    END
  END DFT_sdi_43
  PIN DFT_sdo_43
    DIRECTION OUTPUT ;
    USE SIGNAL ;
    PORT
      LAYER M2 ;
        RECT MASK 2 503.907000 527.344000 504.136000 527.376000 ;
    END
  END DFT_sdo_43
  PIN DFT_sdi_44
    DIRECTION INPUT ;
    USE SIGNAL ;
    PORT
      LAYER M6 ;
        RECT 503.761000 523.620000 504.136000 523.660000 ;
    END
  END DFT_sdi_44
  PIN DFT_sdo_44
    DIRECTION OUTPUT ;
    USE SIGNAL ;
    PORT
      LAYER M2 ;
        RECT MASK 2 503.907000 528.368000 504.136000 528.400000 ;
    END
  END DFT_sdo_44
  PIN DFT_sdi_45
    DIRECTION INPUT ;
    USE SIGNAL ;
    PORT
      LAYER M6 ;
        RECT 0.000000 523.380000 0.375000 523.420000 ;
    END
  END DFT_sdi_45
  PIN DFT_sdo_45
    DIRECTION OUTPUT ;
    USE SIGNAL ;
    PORT
      LAYER M6 ;
        RECT 503.761000 527.220000 504.136000 527.260000 ;
    END
  END DFT_sdo_45
  PIN DFT_sdi_46
    DIRECTION INPUT ;
    USE SIGNAL ;
    PORT
      LAYER M4 ;
        RECT 503.761000 525.060000 504.136000 525.100000 ;
    END
  END DFT_sdi_46
  PIN DFT_sdo_46
    DIRECTION OUTPUT ;
    USE SIGNAL ;
    PORT
      LAYER M8 ;
        RECT 0.000000 523.425000 0.354000 523.487000 ;
    END
  END DFT_sdo_46
  PIN DFT_sdi_47
    DIRECTION INPUT ;
    USE SIGNAL ;
    PORT
      LAYER M6 ;
        RECT 503.761000 525.220000 504.136000 525.260000 ;
    END
  END DFT_sdi_47
  PIN DFT_sdo_47
    DIRECTION OUTPUT ;
    USE SIGNAL ;
    PORT
      LAYER M8 ;
        RECT 503.782000 527.009000 504.136000 527.071000 ;
    END
  END DFT_sdo_47
  PIN DFT_sdi_48
    DIRECTION INPUT ;
    USE SIGNAL ;
    PORT
      LAYER M6 ;
        RECT 0.000000 523.540000 0.375000 523.580000 ;
    END
  END DFT_sdi_48
  PIN DFT_sdo_48
    DIRECTION OUTPUT ;
    USE SIGNAL ;
    PORT
      LAYER M2 ;
        RECT MASK 2 503.907000 526.448000 504.136000 526.480000 ;
    END
  END DFT_sdo_48
  PIN DFT_sdi_49
    DIRECTION INPUT ;
    USE SIGNAL ;
    PORT
      LAYER M8 ;
        RECT 503.782000 525.217000 504.136000 525.279000 ;
    END
  END DFT_sdi_49
  PIN DFT_sdo_49
    DIRECTION OUTPUT ;
    USE SIGNAL ;
    PORT
      LAYER M2 ;
        RECT MASK 2 503.907000 525.296000 504.136000 525.328000 ;
    END
  END DFT_sdo_49
  PIN DFT_sdi_50
    DIRECTION INPUT ;
    USE SIGNAL ;
    PORT
      LAYER M6 ;
        RECT 0.000000 523.700000 0.375000 523.740000 ;
    END
  END DFT_sdi_50
  PIN DFT_sdo_50
    DIRECTION OUTPUT ;
    USE SIGNAL ;
    PORT
      LAYER M8 ;
        RECT 0.000000 523.681000 0.354000 523.743000 ;
    END
  END DFT_sdo_50
  PIN DFT_sdi_51
    DIRECTION INPUT ;
    USE SIGNAL ;
    PORT
      LAYER M2 ;
        RECT MASK 2 503.907000 524.272000 504.136000 524.304000 ;
    END
  END DFT_sdi_51
  PIN DFT_sdo_51
    DIRECTION OUTPUT ;
    USE SIGNAL ;
    PORT
      LAYER M8 ;
        RECT 503.782000 525.729000 504.136000 525.791000 ;
    END
  END DFT_sdo_51
  PIN DFT_sdi_52
    DIRECTION INPUT ;
    USE SIGNAL ;
    PORT
      LAYER M4 ;
        RECT 503.761000 523.620000 504.136000 523.660000 ;
    END
  END DFT_sdi_52
  PIN DFT_sdo_52
    DIRECTION OUTPUT ;
    USE SIGNAL ;
    PORT
      LAYER M8 ;
        RECT 503.782000 528.161000 504.136000 528.223000 ;
    END
  END DFT_sdo_52
  PIN DFT_sdi_53
    DIRECTION INPUT ;
    USE SIGNAL ;
    PORT
      LAYER M6 ;
        RECT 0.000000 523.860000 0.375000 523.900000 ;
    END
  END DFT_sdi_53
  PIN DFT_sdo_53
    DIRECTION OUTPUT ;
    USE SIGNAL ;
    PORT
      LAYER M6 ;
        RECT 503.761000 525.540000 504.136000 525.580000 ;
    END
  END DFT_sdo_53
  PIN DFT_sdi_54
    DIRECTION INPUT ;
    USE SIGNAL ;
    PORT
      LAYER M8 ;
        RECT 503.782000 524.705000 504.136000 524.767000 ;
    END
  END DFT_sdi_54
  PIN DFT_sdo_54
    DIRECTION OUTPUT ;
    USE SIGNAL ;
    PORT
      LAYER M6 ;
        RECT 503.761000 526.900000 504.136000 526.940000 ;
    END
  END DFT_sdo_54
  PIN DFT_sdi_55
    DIRECTION INPUT ;
    USE SIGNAL ;
    PORT
      LAYER M8 ;
        RECT 0.000000 523.937000 0.354000 523.999000 ;
    END
  END DFT_sdi_55
  PIN DFT_sdo_55
    DIRECTION OUTPUT ;
    USE SIGNAL ;
    PORT
      LAYER M4 ;
        RECT 503.761000 526.260000 504.136000 526.300000 ;
    END
  END DFT_sdo_55
  PIN DFT_sdi_56
    DIRECTION INPUT ;
    USE SIGNAL ;
    PORT
      LAYER M6 ;
        RECT 503.761000 525.940000 504.136000 525.980000 ;
    END
  END DFT_sdi_56
  PIN DFT_sdo_56
    DIRECTION OUTPUT ;
    USE SIGNAL ;
    PORT
      LAYER M6 ;
        RECT 0.000000 524.020000 0.375000 524.060000 ;
    END
  END DFT_sdo_56
  PIN DFT_sdi_57
    DIRECTION INPUT ;
    USE SIGNAL ;
    PORT
      LAYER M4 ;
        RECT 503.761000 525.940000 504.136000 525.980000 ;
    END
  END DFT_sdi_57
  PIN DFT_sdo_57
    DIRECTION OUTPUT ;
    USE SIGNAL ;
    PORT
      LAYER M6 ;
        RECT 503.761000 524.660000 504.136000 524.700000 ;
    END
  END DFT_sdo_57
  PIN DFT_sdi_58
    DIRECTION INPUT ;
    USE SIGNAL ;
    PORT
      LAYER M6 ;
        RECT 503.761000 526.580000 504.136000 526.620000 ;
    END
  END DFT_sdi_58
  PIN DFT_sdo_58
    DIRECTION OUTPUT ;
    USE SIGNAL ;
    PORT
      LAYER M6 ;
        RECT 0.000000 524.180000 0.375000 524.220000 ;
    END
  END DFT_sdo_58
  PIN DFT_sdi_59
    DIRECTION INPUT ;
    USE SIGNAL ;
    PORT
      LAYER M2 ;
        RECT MASK 2 503.907000 527.088000 504.136000 527.120000 ;
    END
  END DFT_sdi_59
  PIN DFT_sdo_59
    DIRECTION OUTPUT ;
    USE SIGNAL ;
    PORT
      LAYER M2 ;
        RECT MASK 2 503.907000 525.808000 504.136000 525.840000 ;
    END
  END DFT_sdo_59
  PIN DFT_sdi_60
    DIRECTION INPUT ;
    USE SIGNAL ;
    PORT
      LAYER M8 ;
        RECT 0.000000 524.193000 0.354000 524.255000 ;
    END
  END DFT_sdi_60
  PIN DFT_sdo_60
    DIRECTION OUTPUT ;
    USE SIGNAL ;
    PORT
      LAYER M2 ;
        RECT MASK 2 503.907000 528.112000 504.136000 528.144000 ;
    END
  END DFT_sdo_60
  PIN DFT_sdi_61
    DIRECTION INPUT ;
    USE SIGNAL ;
    PORT
      LAYER M4 ;
        RECT 503.761000 526.580000 504.136000 526.620000 ;
    END
  END DFT_sdi_61
  PIN DFT_sdo_61
    DIRECTION OUTPUT ;
    USE SIGNAL ;
    PORT
      LAYER M6 ;
        RECT 0.000000 524.340000 0.375000 524.380000 ;
    END
  END DFT_sdo_61
  PIN DFT_sdi_62
    DIRECTION INPUT ;
    USE SIGNAL ;
    PORT
      LAYER M4 ;
        RECT 503.761000 525.380000 504.136000 525.420000 ;
    END
  END DFT_sdi_62
  PIN DFT_sdo_62
    DIRECTION OUTPUT ;
    USE SIGNAL ;
    PORT
      LAYER M2 ;
        RECT MASK 2 503.907000 525.552000 504.136000 525.584000 ;
    END
  END DFT_sdo_62
  PIN DFT_sdi_63
    DIRECTION INPUT ;
    USE SIGNAL ;
    PORT
      LAYER M4 ;
        RECT 503.761000 524.740000 504.136000 524.780000 ;
    END
  END DFT_sdi_63
  PIN DFT_sdo_63
    DIRECTION OUTPUT ;
    USE SIGNAL ;
    PORT
      LAYER M6 ;
        RECT 0.000000 524.500000 0.375000 524.540000 ;
    END
  END DFT_sdo_63
  PIN DFT_sdi_64
    DIRECTION INPUT ;
    USE SIGNAL ;
    PORT
      LAYER M8 ;
        RECT 0.000000 524.449000 0.354000 524.511000 ;
    END
  END DFT_sdi_64
  PIN DFT_sdo_64
    DIRECTION OUTPUT ;
    USE SIGNAL ;
    PORT
      LAYER M2 ;
        RECT MASK 2 503.907000 526.704000 504.136000 526.736000 ;
    END
  END DFT_sdo_64
  PIN DFT_sdi_65
    DIRECTION INPUT ;
    USE SIGNAL ;
    PORT
      LAYER M2 ;
        RECT MASK 2 503.907000 523.632000 504.136000 523.664000 ;
    END
  END DFT_sdi_65
  PIN DFT_sdo_65
    DIRECTION OUTPUT ;
    USE SIGNAL ;
    PORT
      LAYER M6 ;
        RECT 503.761000 513.940000 504.136000 513.980000 ;
    END
  END DFT_sdo_65
  PIN DFT_sdi_66
    DIRECTION INPUT ;
    USE SIGNAL ;
    PORT
      LAYER M2 ;
        RECT MASK 2 503.907000 524.784000 504.136000 524.816000 ;
    END
  END DFT_sdi_66
  PIN DFT_sdo_66
    DIRECTION OUTPUT ;
    USE SIGNAL ;
    PORT
      LAYER M2 ;
        RECT MASK 2 503.907000 527.856000 504.136000 527.888000 ;
    END
  END DFT_sdo_66
  PIN cen
    DIRECTION INPUT ;
    USE SIGNAL ;
    PORT
      LAYER M2 ;
        RECT MASK 1 0.000000 562.239000 0.229000 562.271000 ;
    END
  END cen
  PIN clk
    DIRECTION INPUT ;
    USE SIGNAL ;
    PORT
      LAYER M2 ;
        RECT MASK 2 0.000000 553.567000 0.229000 553.599000 ;
    END
  END clk
  PIN ctlsi
    DIRECTION INPUT ;
    USE SIGNAL ;
    PORT
      LAYER M2 ;
        RECT MASK 1 0.000000 551.487000 0.229000 551.519000 ;
    END
  END ctlsi
  PIN dftrambyp
    DIRECTION INPUT ;
    USE SIGNAL ;
    PORT
      LAYER M2 ;
        RECT MASK 1 0.000000 549.567000 0.229000 549.599000 ;
    END
  END dftrambyp
  PIN emas
    DIRECTION INPUT ;
    USE SIGNAL ;
    PORT
      LAYER M2 ;
        RECT MASK 1 0.000000 551.103000 0.229000 551.135000 ;
    END
  END emas
  PIN gwen
    DIRECTION INPUT ;
    USE SIGNAL ;
    PORT
      LAYER M2 ;
        RECT MASK 2 0.000000 549.727000 0.229000 549.759000 ;
    END
  END gwen
  PIN rawl
    DIRECTION INPUT ;
    USE SIGNAL ;
    PORT
      LAYER M2 ;
        RECT MASK 1 0.000000 546.111000 0.229000 546.143000 ;
    END
  END rawl
  PIN rdt
    DIRECTION INPUT ;
    USE SIGNAL ;
    PORT
      LAYER M2 ;
        RECT MASK 2 0.000000 558.945000 0.229000 558.977000 ;
    END
  END rdt
  PIN ret1n
    DIRECTION INPUT ;
    USE SIGNAL ;
    PORT
      LAYER M2 ;
        RECT MASK 2 0.000000 550.111000 0.229000 550.143000 ;
    END
  END ret1n
  PIN se
    DIRECTION INPUT ;
    USE SIGNAL ;
    PORT
      LAYER M4 ;
        RECT 0.000000 558.500000 0.375000 558.540000 ;
    END
  END se
  PIN stov
    DIRECTION INPUT ;
    USE SIGNAL ;
    PORT
      LAYER M2 ;
        RECT MASK 2 0.000000 551.263000 0.229000 551.295000 ;
    END
  END stov
  PIN tcen
    DIRECTION INPUT ;
    USE SIGNAL ;
    PORT
      LAYER M2 ;
        RECT MASK 2 0.000000 551.647000 0.229000 551.679000 ;
    END
  END tcen
  PIN ten
    DIRECTION INPUT ;
    USE SIGNAL ;
    PORT
      LAYER M2 ;
        RECT MASK 2 0.000000 548.959000 0.229000 548.991000 ;
    END
  END ten
  PIN tgwen
    DIRECTION INPUT ;
    USE SIGNAL ;
    PORT
      LAYER M2 ;
        RECT MASK 1 0.000000 551.871000 0.229000 551.903000 ;
    END
  END tgwen
  PIN wabl
    DIRECTION INPUT ;
    USE SIGNAL ;
    PORT
      LAYER M2 ;
        RECT MASK 2 0.000000 563.935000 0.229000 563.967000 ;
    END
  END wabl
  PIN warasi
    DIRECTION INPUT ;
    USE SIGNAL ;
    PORT
      LAYER M2 ;
        RECT MASK 2 0.000000 564.319000 0.229000 564.351000 ;
    END
  END warasi
  PIN i_mem_1_ctlso
    DIRECTION OUTPUT ;
    USE SIGNAL ;
    PORT
      LAYER M2 ;
        RECT MASK 1 0.000000 549.185000 0.229000 549.217000 ;
    END
  END i_mem_1_ctlso
  PIN i_mem_1_waraso
    DIRECTION OUTPUT ;
    USE SIGNAL ;
    PORT
      LAYER M2 ;
        RECT MASK 2 0.000000 552.416000 0.229000 552.448000 ;
    END
  END i_mem_1_waraso
  PIN cena
    DIRECTION INPUT ;
    USE SIGNAL ;
    PORT
      LAYER M2 ;
        RECT MASK 1 0.000000 878.271000 0.229000 878.303000 ;
    END
  END cena
  PIN cenb
    DIRECTION INPUT ;
    USE SIGNAL ;
    PORT
      LAYER M2 ;
        RECT MASK 2 0.000000 878.431000 0.229000 878.463000 ;
    END
  END cenb
  PIN emap
    DIRECTION INPUT ;
    USE SIGNAL ;
    PORT
      LAYER M2 ;
        RECT MASK 1 0.000000 867.648000 0.229000 867.680000 ;
    END
  END emap
  PIN stovab
    DIRECTION INPUT ;
    USE SIGNAL ;
    PORT
      LAYER M2 ;
        RECT MASK 1 0.000000 872.896000 0.229000 872.928000 ;
    END
  END stovab
  PIN cl
    DIRECTION INPUT ;
    USE SIGNAL ;
    PORT
      LAYER M2 ;
        RECT MASK 1 503.907000 687.904000 504.136000 687.936000 ;
    END
  END cl
  PIN cs
    DIRECTION INPUT ;
    USE SIGNAL ;
    PORT
      LAYER M2 ;
        RECT MASK 1 503.907000 688.204000 504.136000 688.236000 ;
    END
  END cs
  PIN ipt_byp_sc
    DIRECTION INPUT ;
    USE SIGNAL ;
    PORT
      LAYER M2 ;
        RECT MASK 1 503.907000 691.504000 504.136000 691.536000 ;
    END
  END ipt_byp_sc
  PIN ipt_mem_se
    DIRECTION INPUT ;
    USE SIGNAL ;
    PORT
      LAYER M2 ;
        RECT MASK 2 503.907000 691.204000 504.136000 691.236000 ;
    END
  END ipt_mem_se
  PIN ipt_mode
    DIRECTION INPUT ;
    USE SIGNAL ;
    PORT
      LAYER M2 ;
        RECT MASK 2 503.907000 690.306000 504.136000 690.338000 ;
    END
  END ipt_mode
  PIN ipt_rst_q
    DIRECTION INPUT ;
    USE SIGNAL ;
    PORT
      LAYER M2 ;
        RECT MASK 1 503.907000 690.604000 504.136000 690.636000 ;
    END
  END ipt_rst_q
  PIN ipt_si_dl
    DIRECTION INPUT ;
    USE SIGNAL ;
    PORT
      LAYER M2 ;
        RECT MASK 2 503.907000 674.274000 504.136000 674.306000 ;
    END
  END ipt_si_dl
  PIN ipt_si_dr
    DIRECTION INPUT ;
    USE SIGNAL ;
    PORT
      LAYER M2 ;
        RECT MASK 1 503.907000 701.856000 504.136000 701.888000 ;
    END
  END ipt_si_dr
  PIN ipt_si_i
    DIRECTION INPUT ;
    USE SIGNAL ;
    PORT
      LAYER M2 ;
        RECT MASK 1 503.907000 696.492000 504.136000 696.524000 ;
    END
  END ipt_si_i
  PIN ipt_st_dis
    DIRECTION INPUT ;
    USE SIGNAL ;
    PORT
      LAYER M2 ;
        RECT MASK 2 503.907000 690.904000 504.136000 690.936000 ;
    END
  END ipt_st_dis
  PIN web
    DIRECTION INPUT ;
    USE SIGNAL ;
    PORT
      LAYER M2 ;
        RECT MASK 2 503.907000 688.504000 504.136000 688.536000 ;
    END
  END web
  PIN i_mem_4_ipt_so_dl
    DIRECTION OUTPUT ;
    USE SIGNAL ;
    PORT
      LAYER M2 ;
        RECT MASK 2 503.907000 677.482000 504.136000 677.514000 ;
    END
  END i_mem_4_ipt_so_dl
  PIN i_mem_4_ipt_so_dr
    DIRECTION OUTPUT ;
    USE SIGNAL ;
    PORT
      LAYER M2 ;
        RECT MASK 2 503.907000 696.192000 504.136000 696.224000 ;
    END
  END i_mem_4_ipt_so_dr
  PIN i_mem_4_ipt_so_i
    DIRECTION OUTPUT ;
    USE SIGNAL ;
    PORT
      LAYER M2 ;
        RECT MASK 1 503.907000 694.804000 504.136000 694.836000 ;
    END
  END i_mem_4_ipt_so_i
  PIN i_mem_5_ctlso
    DIRECTION OUTPUT ;
    USE SIGNAL ;
    PORT
      LAYER M2 ;
        RECT MASK 1 0.000000 514.625000 0.229000 514.657000 ;
    END
  END i_mem_5_ctlso
  PIN i_mem_5_waraso
    DIRECTION OUTPUT ;
    USE SIGNAL ;
    PORT
      LAYER M2 ;
        RECT MASK 2 0.000000 517.856000 0.229000 517.888000 ;
    END
  END i_mem_5_waraso
  PIN ken
    DIRECTION INPUT ;
    USE SIGNAL ;
    PORT
      LAYER M2 ;
        RECT MASK 1 503.907000 811.792000 504.136000 811.824000 ;
    END
  END ken
  PIN pgen
    DIRECTION INPUT ;
    USE SIGNAL ;
    PORT
      LAYER M2 ;
        RECT MASK 2 503.907000 807.154000 504.136000 807.186000 ;
    END
  END pgen
  PIN i_mem_6_ctlso
    DIRECTION OUTPUT ;
    USE SIGNAL ;
    PORT
      LAYER M2 ;
        RECT MASK 2 503.907000 814.194000 504.136000 814.226000 ;
    END
  END i_mem_6_ctlso
  PIN i_mem_6_prdyn
    DIRECTION OUTPUT ;
    USE SIGNAL ;
    PORT
      LAYER M2 ;
        RECT MASK 2 503.907000 812.912000 504.136000 812.944000 ;
    END
  END i_mem_6_prdyn
  PIN fa_aux_input
    DIRECTION INPUT ;
    USE SIGNAL ;
    PORT
      LAYER M6 ;
        RECT 0.000000 524.660000 0.375000 524.700000 ;
    END
  END fa_aux_input
  PIN fa_cnt_en
    DIRECTION INPUT ;
    USE SIGNAL ;
    PORT
      LAYER M6 ;
        RECT 0.000000 524.820000 0.375000 524.860000 ;
    END
  END fa_cnt_en
  PIN fa_reset_b
    DIRECTION INPUT ;
    USE SIGNAL ;
    PORT
      LAYER M6 ;
        RECT 0.000000 524.980000 0.375000 525.020000 ;
    END
  END fa_reset_b
  PIN fa_sclk
    DIRECTION INPUT ;
    USE SIGNAL ;
    PORT
      LAYER M8 ;
        RECT 0.000000 524.705000 0.354000 524.767000 ;
    END
  END fa_sclk
  PIN fa_sdi
    DIRECTION INPUT ;
    USE SIGNAL ;
    PORT
      LAYER M6 ;
        RECT 0.000000 525.140000 0.375000 525.180000 ;
    END
  END fa_sdi
  PIN fa_sh_en
    DIRECTION INPUT ;
    USE SIGNAL ;
    PORT
      LAYER M6 ;
        RECT 0.000000 525.300000 0.375000 525.340000 ;
    END
  END fa_sh_en
  PIN fa_sh_out_en
    DIRECTION INPUT ;
    USE SIGNAL ;
    PORT
      LAYER M8 ;
        RECT 0.000000 524.961000 0.354000 525.023000 ;
    END
  END fa_sh_out_en
  PIN i_mem_8_fa_out
    DIRECTION OUTPUT ;
    USE SIGNAL ;
    PORT
      LAYER M6 ;
        RECT 0.000000 525.460000 0.375000 525.500000 ;
    END
  END i_mem_8_fa_out
  PIN a_9_
    DIRECTION INPUT ;
    USE SIGNAL ;
    PORT
      LAYER M2 ;
        RECT MASK 2 0.000000 560.863000 0.229000 560.895000 ;
    END
  END a_9_
  PIN a_8_
    DIRECTION INPUT ;
    USE SIGNAL ;
    PORT
      LAYER M2 ;
        RECT MASK 2 0.000000 559.711000 0.229000 559.743000 ;
    END
  END a_8_
  PIN a_7_
    DIRECTION INPUT ;
    USE SIGNAL ;
    PORT
      LAYER M2 ;
        RECT MASK 2 0.000000 559.327000 0.229000 559.359000 ;
    END
  END a_7_
  PIN a_6_
    DIRECTION INPUT ;
    USE SIGNAL ;
    PORT
      LAYER M2 ;
        RECT MASK 2 0.000000 558.560000 0.229000 558.592000 ;
    END
  END a_6_
  PIN a_5_
    DIRECTION INPUT ;
    USE SIGNAL ;
    PORT
      LAYER M2 ;
        RECT MASK 2 0.000000 557.023000 0.229000 557.055000 ;
    END
  END a_5_
  PIN a_4_
    DIRECTION INPUT ;
    USE SIGNAL ;
    PORT
      LAYER M2 ;
        RECT MASK 2 0.000000 555.103000 0.229000 555.135000 ;
    END
  END a_4_
  PIN a_3_
    DIRECTION INPUT ;
    USE SIGNAL ;
    PORT
      LAYER M2 ;
        RECT MASK 2 0.000000 556.639000 0.229000 556.671000 ;
    END
  END a_3_
  PIN a_2_
    DIRECTION INPUT ;
    USE SIGNAL ;
    PORT
      LAYER M2 ;
        RECT MASK 1 0.000000 559.551000 0.229000 559.583000 ;
    END
  END a_2_
  PIN a_1_
    DIRECTION INPUT ;
    USE SIGNAL ;
    PORT
      LAYER M2 ;
        RECT MASK 2 0.000000 550.879000 0.229000 550.911000 ;
    END
  END a_1_
  PIN a_0_
    DIRECTION INPUT ;
    USE SIGNAL ;
    PORT
      LAYER M2 ;
        RECT MASK 2 0.000000 552.799000 0.229000 552.831000 ;
    END
  END a_0_
  PIN d_3_
    DIRECTION INPUT ;
    USE SIGNAL ;
    PORT
      LAYER M2 ;
        RECT MASK 2 0.000000 568.079000 0.229000 568.111000 ;
    END
  END d_3_
  PIN d_2_
    DIRECTION INPUT ;
    USE SIGNAL ;
    PORT
      LAYER M2 ;
        RECT MASK 1 0.000000 564.815000 0.229000 564.847000 ;
    END
  END d_2_
  PIN d_1_
    DIRECTION INPUT ;
    USE SIGNAL ;
    PORT
      LAYER M2 ;
        RECT MASK 1 0.000000 544.577000 0.229000 544.609000 ;
    END
  END d_1_
  PIN d_0_
    DIRECTION INPUT ;
    USE SIGNAL ;
    PORT
      LAYER M2 ;
        RECT MASK 2 0.000000 541.313000 0.229000 541.345000 ;
    END
  END d_0_
  PIN ema_2_
    DIRECTION INPUT ;
    USE SIGNAL ;
    PORT
      LAYER M2 ;
        RECT MASK 1 0.000000 549.951000 0.229000 549.983000 ;
    END
  END ema_2_
  PIN ema_1_
    DIRECTION INPUT ;
    USE SIGNAL ;
    PORT
      LAYER M2 ;
        RECT MASK 1 0.000000 547.647000 0.229000 547.679000 ;
    END
  END ema_1_
  PIN ema_0_
    DIRECTION INPUT ;
    USE SIGNAL ;
    PORT
      LAYER M2 ;
        RECT MASK 2 0.000000 547.423000 0.229000 547.455000 ;
    END
  END ema_0_
  PIN emaw_1_
    DIRECTION INPUT ;
    USE SIGNAL ;
    PORT
      LAYER M2 ;
        RECT MASK 2 0.000000 548.191000 0.229000 548.223000 ;
    END
  END emaw_1_
  PIN emaw_0_
    DIRECTION INPUT ;
    USE SIGNAL ;
    PORT
      LAYER M2 ;
        RECT MASK 1 0.000000 548.031000 0.229000 548.063000 ;
    END
  END emaw_0_
  PIN rawlm_1_
    DIRECTION INPUT ;
    USE SIGNAL ;
    PORT
      LAYER M2 ;
        RECT MASK 2 0.000000 558.175000 0.229000 558.207000 ;
    END
  END rawlm_1_
  PIN rawlm_0_
    DIRECTION INPUT ;
    USE SIGNAL ;
    PORT
      LAYER M2 ;
        RECT MASK 1 0.000000 555.713000 0.229000 555.745000 ;
    END
  END rawlm_0_
  PIN si_1_
    DIRECTION INPUT ;
    USE SIGNAL ;
    PORT
      LAYER M2 ;
        RECT MASK 1 0.000000 571.408000 0.229000 571.440000 ;
    END
  END si_1_
  PIN si_0_
    DIRECTION INPUT ;
    USE SIGNAL ;
    PORT
      LAYER M2 ;
        RECT MASK 2 0.000000 537.984000 0.229000 538.016000 ;
    END
  END si_0_
  PIN ta_9_
    DIRECTION INPUT ;
    USE SIGNAL ;
    PORT
      LAYER M2 ;
        RECT MASK 2 0.000000 562.015000 0.229000 562.047000 ;
    END
  END ta_9_
  PIN ta_8_
    DIRECTION INPUT ;
    USE SIGNAL ;
    PORT
      LAYER M2 ;
        RECT MASK 1 0.000000 559.167000 0.229000 559.199000 ;
    END
  END ta_8_
  PIN ta_7_
    DIRECTION INPUT ;
    USE SIGNAL ;
    PORT
      LAYER M2 ;
        RECT MASK 2 0.000000 560.479000 0.229000 560.511000 ;
    END
  END ta_7_
  PIN ta_6_
    DIRECTION INPUT ;
    USE SIGNAL ;
    PORT
      LAYER M2 ;
        RECT MASK 1 0.000000 558.400000 0.229000 558.432000 ;
    END
  END ta_6_
  PIN ta_5_
    DIRECTION INPUT ;
    USE SIGNAL ;
    PORT
      LAYER M2 ;
        RECT MASK 1 0.000000 557.248000 0.229000 557.280000 ;
    END
  END ta_5_
  PIN ta_4_
    DIRECTION INPUT ;
    USE SIGNAL ;
    PORT
      LAYER M2 ;
        RECT MASK 2 0.000000 554.335000 0.229000 554.367000 ;
    END
  END ta_4_
  PIN ta_3_
    DIRECTION INPUT ;
    USE SIGNAL ;
    PORT
      LAYER M2 ;
        RECT MASK 1 0.000000 556.479000 0.229000 556.511000 ;
    END
  END ta_3_
  PIN ta_2_
    DIRECTION INPUT ;
    USE SIGNAL ;
    PORT
      LAYER M2 ;
        RECT MASK 2 0.000000 554.719000 0.229000 554.751000 ;
    END
  END ta_2_
  PIN ta_1_
    DIRECTION INPUT ;
    USE SIGNAL ;
    PORT
      LAYER M2 ;
        RECT MASK 2 0.000000 553.951000 0.229000 553.983000 ;
    END
  END ta_1_
  PIN ta_0_
    DIRECTION INPUT ;
    USE SIGNAL ;
    PORT
      LAYER M2 ;
        RECT MASK 2 0.000000 553.183000 0.229000 553.215000 ;
    END
  END ta_0_
  PIN td_3_
    DIRECTION INPUT ;
    USE SIGNAL ;
    PORT
      LAYER M2 ;
        RECT MASK 2 0.000000 569.103000 0.229000 569.135000 ;
    END
  END td_3_
  PIN td_2_
    DIRECTION INPUT ;
    USE SIGNAL ;
    PORT
      LAYER M2 ;
        RECT MASK 1 0.000000 565.839000 0.229000 565.871000 ;
    END
  END td_2_
  PIN td_1_
    DIRECTION INPUT ;
    USE SIGNAL ;
    PORT
      LAYER M2 ;
        RECT MASK 1 0.000000 543.553000 0.229000 543.585000 ;
    END
  END td_1_
  PIN td_0_
    DIRECTION INPUT ;
    USE SIGNAL ;
    PORT
      LAYER M2 ;
        RECT MASK 2 0.000000 540.289000 0.229000 540.321000 ;
    END
  END td_0_
  PIN wablm_1_
    DIRECTION INPUT ;
    USE SIGNAL ;
    PORT
      LAYER M2 ;
        RECT MASK 1 0.000000 557.360000 0.229000 557.392000 ;
    END
  END wablm_1_
  PIN wablm_0_
    DIRECTION INPUT ;
    USE SIGNAL ;
    PORT
      LAYER M2 ;
        RECT MASK 1 0.000000 545.727000 0.229000 545.759000 ;
    END
  END wablm_0_
  PIN aa_5_
    DIRECTION INPUT ;
    USE SIGNAL ;
    PORT
      LAYER M2 ;
        RECT MASK 1 0.000000 874.943000 0.229000 874.975000 ;
    END
  END aa_5_
  PIN aa_4_
    DIRECTION INPUT ;
    USE SIGNAL ;
    PORT
      LAYER M2 ;
        RECT MASK 2 0.000000 874.079000 0.229000 874.111000 ;
    END
  END aa_4_
  PIN aa_3_
    DIRECTION INPUT ;
    USE SIGNAL ;
    PORT
      LAYER M2 ;
        RECT MASK 1 0.000000 873.759000 0.229000 873.791000 ;
    END
  END aa_3_
  PIN aa_2_
    DIRECTION INPUT ;
    USE SIGNAL ;
    PORT
      LAYER M2 ;
        RECT MASK 1 0.000000 880.176000 0.229000 880.208000 ;
    END
  END aa_2_
  PIN aa_1_
    DIRECTION INPUT ;
    USE SIGNAL ;
    PORT
      LAYER M2 ;
        RECT MASK 2 0.000000 869.887000 0.229000 869.919000 ;
    END
  END aa_1_
  PIN aa_0_
    DIRECTION INPUT ;
    USE SIGNAL ;
    PORT
      LAYER M2 ;
        RECT MASK 2 0.000000 869.344000 0.229000 869.376000 ;
    END
  END aa_0_
  PIN ab_5_
    DIRECTION INPUT ;
    USE SIGNAL ;
    PORT
      LAYER M2 ;
        RECT MASK 1 0.000000 874.784000 0.229000 874.816000 ;
    END
  END ab_5_
  PIN ab_4_
    DIRECTION INPUT ;
    USE SIGNAL ;
    PORT
      LAYER M2 ;
        RECT MASK 1 0.000000 874.399000 0.229000 874.431000 ;
    END
  END ab_4_
  PIN ab_3_
    DIRECTION INPUT ;
    USE SIGNAL ;
    PORT
      LAYER M2 ;
        RECT MASK 2 0.000000 873.439000 0.229000 873.471000 ;
    END
  END ab_3_
  PIN ab_2_
    DIRECTION INPUT ;
    USE SIGNAL ;
    PORT
      LAYER M2 ;
        RECT MASK 1 0.000000 880.064000 0.229000 880.096000 ;
    END
  END ab_2_
  PIN ab_1_
    DIRECTION INPUT ;
    USE SIGNAL ;
    PORT
      LAYER M2 ;
        RECT MASK 1 0.000000 870.207000 0.229000 870.239000 ;
    END
  END ab_1_
  PIN ab_0_
    DIRECTION INPUT ;
    USE SIGNAL ;
    PORT
      LAYER M4 ;
        RECT 0.000000 869.300000 0.375000 869.340000 ;
    END
  END ab_0_
  PIN db_3_
    DIRECTION INPUT ;
    USE SIGNAL ;
    PORT
      LAYER M2 ;
        RECT MASK 2 0.000000 884.335000 0.229000 884.367000 ;
    END
  END db_3_
  PIN db_2_
    DIRECTION INPUT ;
    USE SIGNAL ;
    PORT
      LAYER M2 ;
        RECT MASK 2 0.000000 882.319000 0.229000 882.351000 ;
    END
  END db_2_
  PIN db_1_
    DIRECTION INPUT ;
    USE SIGNAL ;
    PORT
      LAYER M2 ;
        RECT MASK 2 0.000000 859.617000 0.229000 859.649000 ;
    END
  END db_1_
  PIN db_0_
    DIRECTION INPUT ;
    USE SIGNAL ;
    PORT
      LAYER M2 ;
        RECT MASK 2 0.000000 857.601000 0.229000 857.633000 ;
    END
  END db_0_
  PIN d_7_
    DIRECTION INPUT ;
    USE SIGNAL ;
    PORT
      LAYER M2 ;
        RECT MASK 1 503.907000 700.488000 504.136000 700.520000 ;
    END
  END d_7_
  PIN d_6_
    DIRECTION INPUT ;
    USE SIGNAL ;
    PORT
      LAYER M2 ;
        RECT MASK 2 503.907000 698.856000 504.136000 698.888000 ;
    END
  END d_6_
  PIN d_5_
    DIRECTION INPUT ;
    USE SIGNAL ;
    PORT
      LAYER M2 ;
        RECT MASK 2 503.907000 697.224000 504.136000 697.256000 ;
    END
  END d_5_
  PIN d_4_
    DIRECTION INPUT ;
    USE SIGNAL ;
    PORT
      LAYER M2 ;
        RECT MASK 1 503.907000 695.592000 504.136000 695.624000 ;
    END
  END d_4_
  PIN pwrmode_3_
    DIRECTION INPUT ;
    USE SIGNAL ;
    PORT
      LAYER M2 ;
        RECT MASK 1 503.907000 688.804000 504.136000 688.836000 ;
    END
  END pwrmode_3_
  PIN pwrmode_2_
    DIRECTION INPUT ;
    USE SIGNAL ;
    PORT
      LAYER M2 ;
        RECT MASK 2 503.907000 689.104000 504.136000 689.136000 ;
    END
  END pwrmode_2_
  PIN pwrmode_1_
    DIRECTION INPUT ;
    USE SIGNAL ;
    PORT
      LAYER M2 ;
        RECT MASK 2 503.907000 689.404000 504.136000 689.436000 ;
    END
  END pwrmode_1_
  PIN pwrmode_0_
    DIRECTION INPUT ;
    USE SIGNAL ;
    PORT
      LAYER M2 ;
        RECT MASK 1 503.907000 689.704000 504.136000 689.736000 ;
    END
  END pwrmode_0_
  PIN ram_1_
    DIRECTION INPUT ;
    USE SIGNAL ;
    PORT
      LAYER M2 ;
        RECT MASK 1 503.907000 687.304000 504.136000 687.336000 ;
    END
  END ram_1_
  PIN ram_0_
    DIRECTION INPUT ;
    USE SIGNAL ;
    PORT
      LAYER M2 ;
        RECT MASK 2 503.907000 687.604000 504.136000 687.636000 ;
    END
  END ram_0_
  PIN rm_4_
    DIRECTION INPUT ;
    USE SIGNAL ;
    PORT
      LAYER M2 ;
        RECT MASK 1 503.907000 692.404000 504.136000 692.436000 ;
    END
  END rm_4_
  PIN rm_3_
    DIRECTION INPUT ;
    USE SIGNAL ;
    PORT
      LAYER M2 ;
        RECT MASK 2 503.907000 692.704000 504.136000 692.736000 ;
    END
  END rm_3_
  PIN rm_2_
    DIRECTION INPUT ;
    USE SIGNAL ;
    PORT
      LAYER M2 ;
        RECT MASK 2 503.907000 693.004000 504.136000 693.036000 ;
    END
  END rm_2_
  PIN rm_1_
    DIRECTION INPUT ;
    USE SIGNAL ;
    PORT
      LAYER M2 ;
        RECT MASK 1 503.907000 693.304000 504.136000 693.336000 ;
    END
  END rm_1_
  PIN rm_0_
    DIRECTION INPUT ;
    USE SIGNAL ;
    PORT
      LAYER M2 ;
        RECT MASK 2 503.907000 693.604000 504.136000 693.636000 ;
    END
  END rm_0_
  PIN wam_1_
    DIRECTION INPUT ;
    USE SIGNAL ;
    PORT
      LAYER M2 ;
        RECT MASK 2 503.907000 691.804000 504.136000 691.836000 ;
    END
  END wam_1_
  PIN wam_0_
    DIRECTION INPUT ;
    USE SIGNAL ;
    PORT
      LAYER M2 ;
        RECT MASK 2 503.907000 692.104000 504.136000 692.136000 ;
    END
  END wam_0_
  PIN wm_2_
    DIRECTION INPUT ;
    USE SIGNAL ;
    PORT
      LAYER M2 ;
        RECT MASK 1 503.907000 693.904000 504.136000 693.936000 ;
    END
  END wm_2_
  PIN wm_1_
    DIRECTION INPUT ;
    USE SIGNAL ;
    PORT
      LAYER M2 ;
        RECT MASK 1 503.907000 694.204000 504.136000 694.236000 ;
    END
  END wm_1_
  PIN wm_0_
    DIRECTION INPUT ;
    USE SIGNAL ;
    PORT
      LAYER M2 ;
        RECT MASK 2 503.907000 694.504000 504.136000 694.536000 ;
    END
  END wm_0_
  PIN fa_block_uid_2_
    DIRECTION INPUT ;
    USE SIGNAL ;
    PORT
      LAYER M6 ;
        RECT 0.000000 525.620000 0.375000 525.660000 ;
    END
  END fa_block_uid_2_
  PIN fa_block_uid_1_
    DIRECTION INPUT ;
    USE SIGNAL ;
    PORT
      LAYER M8 ;
        RECT 0.000000 525.217000 0.354000 525.279000 ;
    END
  END fa_block_uid_1_
  PIN fa_block_uid_0_
    DIRECTION INPUT ;
    USE SIGNAL ;
    PORT
      LAYER M6 ;
        RECT 0.000000 525.780000 0.375000 525.820000 ;
    END
  END fa_block_uid_0_
  PIN i_mem_1_q_3_
    DIRECTION OUTPUT ;
    USE SIGNAL ;
    PORT
      LAYER M2 ;
        RECT MASK 1 0.000000 568.625000 0.229000 568.657000 ;
    END
  END i_mem_1_q_3_
  PIN i_mem_1_q_2_
    DIRECTION OUTPUT ;
    USE SIGNAL ;
    PORT
      LAYER M2 ;
        RECT MASK 2 0.000000 565.361000 0.229000 565.393000 ;
    END
  END i_mem_1_q_2_
  PIN i_mem_1_q_1_
    DIRECTION OUTPUT ;
    USE SIGNAL ;
    PORT
      LAYER M2 ;
        RECT MASK 1 0.000000 544.031000 0.229000 544.063000 ;
    END
  END i_mem_1_q_1_
  PIN i_mem_1_q_0_
    DIRECTION OUTPUT ;
    USE SIGNAL ;
    PORT
      LAYER M2 ;
        RECT MASK 2 0.000000 540.767000 0.229000 540.799000 ;
    END
  END i_mem_1_q_0_
  PIN i_mem_1_so_1_
    DIRECTION OUTPUT ;
    USE SIGNAL ;
    PORT
      LAYER M2 ;
        RECT MASK 1 0.000000 555.327000 0.229000 555.359000 ;
    END
  END i_mem_1_so_1_
  PIN i_mem_1_so_0_
    DIRECTION OUTPUT ;
    USE SIGNAL ;
    PORT
      LAYER M2 ;
        RECT MASK 1 0.000000 560.319000 0.229000 560.351000 ;
    END
  END i_mem_1_so_0_
  PIN i_mem_2_q_3_
    DIRECTION OUTPUT ;
    USE SIGNAL ;
    PORT
      LAYER M2 ;
        RECT MASK 2 0.000000 854.737000 0.229000 854.769000 ;
    END
  END i_mem_2_q_3_
  PIN i_mem_2_q_2_
    DIRECTION OUTPUT ;
    USE SIGNAL ;
    PORT
      LAYER M2 ;
        RECT MASK 2 0.000000 852.721000 0.229000 852.753000 ;
    END
  END i_mem_2_q_2_
  PIN i_mem_2_q_1_
    DIRECTION OUTPUT ;
    USE SIGNAL ;
    PORT
      LAYER M2 ;
        RECT MASK 2 0.000000 831.615000 0.229000 831.647000 ;
    END
  END i_mem_2_q_1_
  PIN i_mem_2_q_0_
    DIRECTION OUTPUT ;
    USE SIGNAL ;
    PORT
      LAYER M2 ;
        RECT MASK 1 0.000000 829.599000 0.229000 829.631000 ;
    END
  END i_mem_2_q_0_
  PIN i_mem_3_qa_3_
    DIRECTION OUTPUT ;
    USE SIGNAL ;
    PORT
      LAYER M2 ;
        RECT MASK 2 0.000000 882.897000 0.229000 882.929000 ;
    END
  END i_mem_3_qa_3_
  PIN i_mem_3_qa_2_
    DIRECTION OUTPUT ;
    USE SIGNAL ;
    PORT
      LAYER M2 ;
        RECT MASK 2 0.000000 880.881000 0.229000 880.913000 ;
    END
  END i_mem_3_qa_2_
  PIN i_mem_3_qa_1_
    DIRECTION OUTPUT ;
    USE SIGNAL ;
    PORT
      LAYER M2 ;
        RECT MASK 2 0.000000 861.055000 0.229000 861.087000 ;
    END
  END i_mem_3_qa_1_
  PIN i_mem_3_qa_0_
    DIRECTION OUTPUT ;
    USE SIGNAL ;
    PORT
      LAYER M2 ;
        RECT MASK 1 0.000000 859.039000 0.229000 859.071000 ;
    END
  END i_mem_3_qa_0_
  PIN i_mem_4_q_7_
    DIRECTION OUTPUT ;
    USE SIGNAL ;
    PORT
      LAYER M2 ;
        RECT MASK 2 503.907000 700.808000 504.136000 700.840000 ;
    END
  END i_mem_4_q_7_
  PIN i_mem_4_q_6_
    DIRECTION OUTPUT ;
    USE SIGNAL ;
    PORT
      LAYER M2 ;
        RECT MASK 1 503.907000 699.176000 504.136000 699.208000 ;
    END
  END i_mem_4_q_6_
  PIN i_mem_4_q_5_
    DIRECTION OUTPUT ;
    USE SIGNAL ;
    PORT
      LAYER M2 ;
        RECT MASK 1 503.907000 697.544000 504.136000 697.576000 ;
    END
  END i_mem_4_q_5_
  PIN i_mem_4_q_4_
    DIRECTION OUTPUT ;
    USE SIGNAL ;
    PORT
      LAYER M2 ;
        RECT MASK 2 503.907000 695.912000 504.136000 695.944000 ;
    END
  END i_mem_4_q_4_
  PIN i_mem_4_q_3_
    DIRECTION OUTPUT ;
    USE SIGNAL ;
    PORT
      LAYER M2 ;
        RECT MASK 2 503.907000 680.072000 504.136000 680.104000 ;
    END
  END i_mem_4_q_3_
  PIN i_mem_4_q_2_
    DIRECTION OUTPUT ;
    USE SIGNAL ;
    PORT
      LAYER M2 ;
        RECT MASK 1 503.907000 678.440000 504.136000 678.472000 ;
    END
  END i_mem_4_q_2_
  PIN i_mem_4_q_1_
    DIRECTION OUTPUT ;
    USE SIGNAL ;
    PORT
      LAYER M2 ;
        RECT MASK 1 503.907000 676.808000 504.136000 676.840000 ;
    END
  END i_mem_4_q_1_
  PIN i_mem_4_q_0_
    DIRECTION OUTPUT ;
    USE SIGNAL ;
    PORT
      LAYER M2 ;
        RECT MASK 2 503.907000 675.176000 504.136000 675.208000 ;
    END
  END i_mem_4_q_0_
  PIN i_mem_5_q_3_
    DIRECTION OUTPUT ;
    USE SIGNAL ;
    PORT
      LAYER M2 ;
        RECT MASK 1 0.000000 534.065000 0.229000 534.097000 ;
    END
  END i_mem_5_q_3_
  PIN i_mem_5_q_2_
    DIRECTION OUTPUT ;
    USE SIGNAL ;
    PORT
      LAYER M2 ;
        RECT MASK 2 0.000000 530.801000 0.229000 530.833000 ;
    END
  END i_mem_5_q_2_
  PIN i_mem_5_q_1_
    DIRECTION OUTPUT ;
    USE SIGNAL ;
    PORT
      LAYER M2 ;
        RECT MASK 1 0.000000 509.471000 0.229000 509.503000 ;
    END
  END i_mem_5_q_1_
  PIN i_mem_5_q_0_
    DIRECTION OUTPUT ;
    USE SIGNAL ;
    PORT
      LAYER M2 ;
        RECT MASK 2 0.000000 506.207000 0.229000 506.239000 ;
    END
  END i_mem_5_q_0_
  PIN i_mem_5_so_1_
    DIRECTION OUTPUT ;
    USE SIGNAL ;
    PORT
      LAYER M2 ;
        RECT MASK 1 0.000000 520.767000 0.229000 520.799000 ;
    END
  END i_mem_5_so_1_
  PIN i_mem_5_so_0_
    DIRECTION OUTPUT ;
    USE SIGNAL ;
    PORT
      LAYER M2 ;
        RECT MASK 1 0.000000 525.759000 0.229000 525.791000 ;
    END
  END i_mem_5_so_0_
  PIN i_mem_6_q_115_
    DIRECTION OUTPUT ;
    USE SIGNAL ;
    PORT
      LAYER M2 ;
        RECT MASK 2 503.907000 914.559000 504.136000 914.591000 ;
    END
  END i_mem_6_q_115_
  PIN i_mem_6_q_114_
    DIRECTION OUTPUT ;
    USE SIGNAL ;
    PORT
      LAYER M2 ;
        RECT MASK 2 503.907000 913.023000 504.136000 913.055000 ;
    END
  END i_mem_6_q_114_
  PIN i_mem_6_q_113_
    DIRECTION OUTPUT ;
    USE SIGNAL ;
    PORT
      LAYER M2 ;
        RECT MASK 2 503.907000 911.487000 504.136000 911.519000 ;
    END
  END i_mem_6_q_113_
  PIN i_mem_6_q_112_
    DIRECTION OUTPUT ;
    USE SIGNAL ;
    PORT
      LAYER M2 ;
        RECT MASK 2 503.907000 909.951000 504.136000 909.983000 ;
    END
  END i_mem_6_q_112_
  PIN i_mem_6_q_111_
    DIRECTION OUTPUT ;
    USE SIGNAL ;
    PORT
      LAYER M2 ;
        RECT MASK 2 503.907000 907.791000 504.136000 907.823000 ;
    END
  END i_mem_6_q_111_
  PIN i_mem_6_q_110_
    DIRECTION OUTPUT ;
    USE SIGNAL ;
    PORT
      LAYER M2 ;
        RECT MASK 2 503.907000 906.255000 504.136000 906.287000 ;
    END
  END i_mem_6_q_110_
  PIN i_mem_6_q_109_
    DIRECTION OUTPUT ;
    USE SIGNAL ;
    PORT
      LAYER M2 ;
        RECT MASK 2 503.907000 904.719000 504.136000 904.751000 ;
    END
  END i_mem_6_q_109_
  PIN i_mem_6_q_108_
    DIRECTION OUTPUT ;
    USE SIGNAL ;
    PORT
      LAYER M2 ;
        RECT MASK 2 503.907000 903.183000 504.136000 903.215000 ;
    END
  END i_mem_6_q_108_
  PIN i_mem_6_q_107_
    DIRECTION OUTPUT ;
    USE SIGNAL ;
    PORT
      LAYER M2 ;
        RECT MASK 1 503.907000 901.023000 504.136000 901.055000 ;
    END
  END i_mem_6_q_107_
  PIN i_mem_6_q_106_
    DIRECTION OUTPUT ;
    USE SIGNAL ;
    PORT
      LAYER M2 ;
        RECT MASK 1 503.907000 899.487000 504.136000 899.519000 ;
    END
  END i_mem_6_q_106_
  PIN i_mem_6_q_105_
    DIRECTION OUTPUT ;
    USE SIGNAL ;
    PORT
      LAYER M2 ;
        RECT MASK 1 503.907000 897.951000 504.136000 897.983000 ;
    END
  END i_mem_6_q_105_
  PIN i_mem_6_q_104_
    DIRECTION OUTPUT ;
    USE SIGNAL ;
    PORT
      LAYER M2 ;
        RECT MASK 1 503.907000 896.415000 504.136000 896.447000 ;
    END
  END i_mem_6_q_104_
  PIN i_mem_6_q_103_
    DIRECTION OUTPUT ;
    USE SIGNAL ;
    PORT
      LAYER M2 ;
        RECT MASK 1 503.907000 894.255000 504.136000 894.287000 ;
    END
  END i_mem_6_q_103_
  PIN i_mem_6_q_102_
    DIRECTION OUTPUT ;
    USE SIGNAL ;
    PORT
      LAYER M2 ;
        RECT MASK 1 503.907000 892.719000 504.136000 892.751000 ;
    END
  END i_mem_6_q_102_
  PIN i_mem_6_q_101_
    DIRECTION OUTPUT ;
    USE SIGNAL ;
    PORT
      LAYER M2 ;
        RECT MASK 1 503.907000 891.183000 504.136000 891.215000 ;
    END
  END i_mem_6_q_101_
  PIN i_mem_6_q_100_
    DIRECTION OUTPUT ;
    USE SIGNAL ;
    PORT
      LAYER M2 ;
        RECT MASK 1 503.907000 889.647000 504.136000 889.679000 ;
    END
  END i_mem_6_q_100_
  PIN i_mem_6_q_99_
    DIRECTION OUTPUT ;
    USE SIGNAL ;
    PORT
      LAYER M2 ;
        RECT MASK 1 503.907000 887.487000 504.136000 887.519000 ;
    END
  END i_mem_6_q_99_
  PIN i_mem_6_q_98_
    DIRECTION OUTPUT ;
    USE SIGNAL ;
    PORT
      LAYER M2 ;
        RECT MASK 1 503.907000 885.951000 504.136000 885.983000 ;
    END
  END i_mem_6_q_98_
  PIN i_mem_6_q_97_
    DIRECTION OUTPUT ;
    USE SIGNAL ;
    PORT
      LAYER M2 ;
        RECT MASK 1 503.907000 884.415000 504.136000 884.447000 ;
    END
  END i_mem_6_q_97_
  PIN i_mem_6_q_96_
    DIRECTION OUTPUT ;
    USE SIGNAL ;
    PORT
      LAYER M2 ;
        RECT MASK 1 503.907000 882.879000 504.136000 882.911000 ;
    END
  END i_mem_6_q_96_
  PIN i_mem_6_q_95_
    DIRECTION OUTPUT ;
    USE SIGNAL ;
    PORT
      LAYER M2 ;
        RECT MASK 1 503.907000 880.719000 504.136000 880.751000 ;
    END
  END i_mem_6_q_95_
  PIN i_mem_6_q_94_
    DIRECTION OUTPUT ;
    USE SIGNAL ;
    PORT
      LAYER M2 ;
        RECT MASK 1 503.907000 879.183000 504.136000 879.215000 ;
    END
  END i_mem_6_q_94_
  PIN i_mem_6_q_93_
    DIRECTION OUTPUT ;
    USE SIGNAL ;
    PORT
      LAYER M2 ;
        RECT MASK 1 503.907000 877.647000 504.136000 877.679000 ;
    END
  END i_mem_6_q_93_
  PIN i_mem_6_q_92_
    DIRECTION OUTPUT ;
    USE SIGNAL ;
    PORT
      LAYER M2 ;
        RECT MASK 1 503.907000 876.111000 504.136000 876.143000 ;
    END
  END i_mem_6_q_92_
  PIN i_mem_6_q_91_
    DIRECTION OUTPUT ;
    USE SIGNAL ;
    PORT
      LAYER M2 ;
        RECT MASK 2 503.907000 873.951000 504.136000 873.983000 ;
    END
  END i_mem_6_q_91_
  PIN i_mem_6_q_90_
    DIRECTION OUTPUT ;
    USE SIGNAL ;
    PORT
      LAYER M2 ;
        RECT MASK 2 503.907000 872.415000 504.136000 872.447000 ;
    END
  END i_mem_6_q_90_
  PIN i_mem_6_q_89_
    DIRECTION OUTPUT ;
    USE SIGNAL ;
    PORT
      LAYER M2 ;
        RECT MASK 2 503.907000 870.879000 504.136000 870.911000 ;
    END
  END i_mem_6_q_89_
  PIN i_mem_6_q_88_
    DIRECTION OUTPUT ;
    USE SIGNAL ;
    PORT
      LAYER M2 ;
        RECT MASK 2 503.907000 869.343000 504.136000 869.375000 ;
    END
  END i_mem_6_q_88_
  PIN i_mem_6_q_87_
    DIRECTION OUTPUT ;
    USE SIGNAL ;
    PORT
      LAYER M2 ;
        RECT MASK 2 503.907000 867.183000 504.136000 867.215000 ;
    END
  END i_mem_6_q_87_
  PIN i_mem_6_q_86_
    DIRECTION OUTPUT ;
    USE SIGNAL ;
    PORT
      LAYER M2 ;
        RECT MASK 2 503.907000 865.647000 504.136000 865.679000 ;
    END
  END i_mem_6_q_86_
  PIN i_mem_6_q_85_
    DIRECTION OUTPUT ;
    USE SIGNAL ;
    PORT
      LAYER M2 ;
        RECT MASK 2 503.907000 864.111000 504.136000 864.143000 ;
    END
  END i_mem_6_q_85_
  PIN i_mem_6_q_84_
    DIRECTION OUTPUT ;
    USE SIGNAL ;
    PORT
      LAYER M2 ;
        RECT MASK 2 503.907000 862.575000 504.136000 862.607000 ;
    END
  END i_mem_6_q_84_
  PIN i_mem_6_q_83_
    DIRECTION OUTPUT ;
    USE SIGNAL ;
    PORT
      LAYER M2 ;
        RECT MASK 2 503.907000 860.415000 504.136000 860.447000 ;
    END
  END i_mem_6_q_83_
  PIN i_mem_6_q_82_
    DIRECTION OUTPUT ;
    USE SIGNAL ;
    PORT
      LAYER M2 ;
        RECT MASK 2 503.907000 858.879000 504.136000 858.911000 ;
    END
  END i_mem_6_q_82_
  PIN i_mem_6_q_81_
    DIRECTION OUTPUT ;
    USE SIGNAL ;
    PORT
      LAYER M2 ;
        RECT MASK 2 503.907000 857.343000 504.136000 857.375000 ;
    END
  END i_mem_6_q_81_
  PIN i_mem_6_q_80_
    DIRECTION OUTPUT ;
    USE SIGNAL ;
    PORT
      LAYER M2 ;
        RECT MASK 2 503.907000 855.807000 504.136000 855.839000 ;
    END
  END i_mem_6_q_80_
  PIN i_mem_6_q_79_
    DIRECTION OUTPUT ;
    USE SIGNAL ;
    PORT
      LAYER M2 ;
        RECT MASK 2 503.907000 853.647000 504.136000 853.679000 ;
    END
  END i_mem_6_q_79_
  PIN i_mem_6_q_78_
    DIRECTION OUTPUT ;
    USE SIGNAL ;
    PORT
      LAYER M2 ;
        RECT MASK 2 503.907000 852.111000 504.136000 852.143000 ;
    END
  END i_mem_6_q_78_
  PIN i_mem_6_q_77_
    DIRECTION OUTPUT ;
    USE SIGNAL ;
    PORT
      LAYER M2 ;
        RECT MASK 2 503.907000 850.575000 504.136000 850.607000 ;
    END
  END i_mem_6_q_77_
  PIN i_mem_6_q_76_
    DIRECTION OUTPUT ;
    USE SIGNAL ;
    PORT
      LAYER M2 ;
        RECT MASK 2 503.907000 849.039000 504.136000 849.071000 ;
    END
  END i_mem_6_q_76_
  PIN i_mem_6_q_75_
    DIRECTION OUTPUT ;
    USE SIGNAL ;
    PORT
      LAYER M2 ;
        RECT MASK 1 503.907000 846.879000 504.136000 846.911000 ;
    END
  END i_mem_6_q_75_
  PIN i_mem_6_q_74_
    DIRECTION OUTPUT ;
    USE SIGNAL ;
    PORT
      LAYER M2 ;
        RECT MASK 1 503.907000 845.343000 504.136000 845.375000 ;
    END
  END i_mem_6_q_74_
  PIN i_mem_6_q_73_
    DIRECTION OUTPUT ;
    USE SIGNAL ;
    PORT
      LAYER M2 ;
        RECT MASK 1 503.907000 843.807000 504.136000 843.839000 ;
    END
  END i_mem_6_q_73_
  PIN i_mem_6_q_72_
    DIRECTION OUTPUT ;
    USE SIGNAL ;
    PORT
      LAYER M2 ;
        RECT MASK 1 503.907000 842.271000 504.136000 842.303000 ;
    END
  END i_mem_6_q_72_
  PIN i_mem_6_q_71_
    DIRECTION OUTPUT ;
    USE SIGNAL ;
    PORT
      LAYER M2 ;
        RECT MASK 1 503.907000 840.111000 504.136000 840.143000 ;
    END
  END i_mem_6_q_71_
  PIN i_mem_6_q_70_
    DIRECTION OUTPUT ;
    USE SIGNAL ;
    PORT
      LAYER M2 ;
        RECT MASK 1 503.907000 838.575000 504.136000 838.607000 ;
    END
  END i_mem_6_q_70_
  PIN i_mem_6_q_69_
    DIRECTION OUTPUT ;
    USE SIGNAL ;
    PORT
      LAYER M2 ;
        RECT MASK 1 503.907000 837.039000 504.136000 837.071000 ;
    END
  END i_mem_6_q_69_
  PIN i_mem_6_q_68_
    DIRECTION OUTPUT ;
    USE SIGNAL ;
    PORT
      LAYER M2 ;
        RECT MASK 1 503.907000 835.503000 504.136000 835.535000 ;
    END
  END i_mem_6_q_68_
  PIN i_mem_6_q_67_
    DIRECTION OUTPUT ;
    USE SIGNAL ;
    PORT
      LAYER M2 ;
        RECT MASK 1 503.907000 833.343000 504.136000 833.375000 ;
    END
  END i_mem_6_q_67_
  PIN i_mem_6_q_66_
    DIRECTION OUTPUT ;
    USE SIGNAL ;
    PORT
      LAYER M2 ;
        RECT MASK 1 503.907000 831.807000 504.136000 831.839000 ;
    END
  END i_mem_6_q_66_
  PIN i_mem_6_q_65_
    DIRECTION OUTPUT ;
    USE SIGNAL ;
    PORT
      LAYER M2 ;
        RECT MASK 1 503.907000 830.271000 504.136000 830.303000 ;
    END
  END i_mem_6_q_65_
  PIN i_mem_6_q_64_
    DIRECTION OUTPUT ;
    USE SIGNAL ;
    PORT
      LAYER M2 ;
        RECT MASK 1 503.907000 828.735000 504.136000 828.767000 ;
    END
  END i_mem_6_q_64_
  PIN i_mem_6_q_63_
    DIRECTION OUTPUT ;
    USE SIGNAL ;
    PORT
      LAYER M2 ;
        RECT MASK 1 503.907000 826.575000 504.136000 826.607000 ;
    END
  END i_mem_6_q_63_
  PIN i_mem_6_q_62_
    DIRECTION OUTPUT ;
    USE SIGNAL ;
    PORT
      LAYER M2 ;
        RECT MASK 1 503.907000 825.039000 504.136000 825.071000 ;
    END
  END i_mem_6_q_62_
  PIN i_mem_6_q_61_
    DIRECTION OUTPUT ;
    USE SIGNAL ;
    PORT
      LAYER M2 ;
        RECT MASK 1 503.907000 823.503000 504.136000 823.535000 ;
    END
  END i_mem_6_q_61_
  PIN i_mem_6_q_60_
    DIRECTION OUTPUT ;
    USE SIGNAL ;
    PORT
      LAYER M2 ;
        RECT MASK 1 503.907000 821.967000 504.136000 821.999000 ;
    END
  END i_mem_6_q_60_
  PIN i_mem_6_q_59_
    DIRECTION OUTPUT ;
    USE SIGNAL ;
    PORT
      LAYER M2 ;
        RECT MASK 2 503.907000 819.807000 504.136000 819.839000 ;
    END
  END i_mem_6_q_59_
  PIN i_mem_6_q_58_
    DIRECTION OUTPUT ;
    USE SIGNAL ;
    PORT
      LAYER M2 ;
        RECT MASK 2 503.907000 818.271000 504.136000 818.303000 ;
    END
  END i_mem_6_q_58_
  PIN i_mem_6_q_57_
    DIRECTION OUTPUT ;
    USE SIGNAL ;
    PORT
      LAYER M2 ;
        RECT MASK 1 503.907000 801.183000 504.136000 801.215000 ;
    END
  END i_mem_6_q_57_
  PIN i_mem_6_q_56_
    DIRECTION OUTPUT ;
    USE SIGNAL ;
    PORT
      LAYER M2 ;
        RECT MASK 1 503.907000 799.647000 504.136000 799.679000 ;
    END
  END i_mem_6_q_56_
  PIN i_mem_6_q_55_
    DIRECTION OUTPUT ;
    USE SIGNAL ;
    PORT
      LAYER M2 ;
        RECT MASK 1 503.907000 797.487000 504.136000 797.519000 ;
    END
  END i_mem_6_q_55_
  PIN i_mem_6_q_54_
    DIRECTION OUTPUT ;
    USE SIGNAL ;
    PORT
      LAYER M2 ;
        RECT MASK 1 503.907000 795.951000 504.136000 795.983000 ;
    END
  END i_mem_6_q_54_
  PIN i_mem_6_q_53_
    DIRECTION OUTPUT ;
    USE SIGNAL ;
    PORT
      LAYER M2 ;
        RECT MASK 1 503.907000 794.415000 504.136000 794.447000 ;
    END
  END i_mem_6_q_53_
  PIN i_mem_6_q_52_
    DIRECTION OUTPUT ;
    USE SIGNAL ;
    PORT
      LAYER M2 ;
        RECT MASK 1 503.907000 792.879000 504.136000 792.911000 ;
    END
  END i_mem_6_q_52_
  PIN i_mem_6_q_51_
    DIRECTION OUTPUT ;
    USE SIGNAL ;
    PORT
      LAYER M2 ;
        RECT MASK 1 503.907000 790.719000 504.136000 790.751000 ;
    END
  END i_mem_6_q_51_
  PIN i_mem_6_q_50_
    DIRECTION OUTPUT ;
    USE SIGNAL ;
    PORT
      LAYER M2 ;
        RECT MASK 1 503.907000 789.183000 504.136000 789.215000 ;
    END
  END i_mem_6_q_50_
  PIN i_mem_6_q_49_
    DIRECTION OUTPUT ;
    USE SIGNAL ;
    PORT
      LAYER M2 ;
        RECT MASK 1 503.907000 787.647000 504.136000 787.679000 ;
    END
  END i_mem_6_q_49_
  PIN i_mem_6_q_48_
    DIRECTION OUTPUT ;
    USE SIGNAL ;
    PORT
      LAYER M2 ;
        RECT MASK 1 503.907000 786.111000 504.136000 786.143000 ;
    END
  END i_mem_6_q_48_
  PIN i_mem_6_q_47_
    DIRECTION OUTPUT ;
    USE SIGNAL ;
    PORT
      LAYER M2 ;
        RECT MASK 1 503.907000 783.951000 504.136000 783.983000 ;
    END
  END i_mem_6_q_47_
  PIN i_mem_6_q_46_
    DIRECTION OUTPUT ;
    USE SIGNAL ;
    PORT
      LAYER M2 ;
        RECT MASK 1 503.907000 782.415000 504.136000 782.447000 ;
    END
  END i_mem_6_q_46_
  PIN i_mem_6_q_45_
    DIRECTION OUTPUT ;
    USE SIGNAL ;
    PORT
      LAYER M2 ;
        RECT MASK 1 503.907000 780.879000 504.136000 780.911000 ;
    END
  END i_mem_6_q_45_
  PIN i_mem_6_q_44_
    DIRECTION OUTPUT ;
    USE SIGNAL ;
    PORT
      LAYER M2 ;
        RECT MASK 1 503.907000 779.343000 504.136000 779.375000 ;
    END
  END i_mem_6_q_44_
  PIN i_mem_6_q_43_
    DIRECTION OUTPUT ;
    USE SIGNAL ;
    PORT
      LAYER M2 ;
        RECT MASK 2 503.907000 777.183000 504.136000 777.215000 ;
    END
  END i_mem_6_q_43_
  PIN i_mem_6_q_42_
    DIRECTION OUTPUT ;
    USE SIGNAL ;
    PORT
      LAYER M2 ;
        RECT MASK 2 503.907000 775.647000 504.136000 775.679000 ;
    END
  END i_mem_6_q_42_
  PIN i_mem_6_q_41_
    DIRECTION OUTPUT ;
    USE SIGNAL ;
    PORT
      LAYER M2 ;
        RECT MASK 2 503.907000 774.111000 504.136000 774.143000 ;
    END
  END i_mem_6_q_41_
  PIN i_mem_6_q_40_
    DIRECTION OUTPUT ;
    USE SIGNAL ;
    PORT
      LAYER M2 ;
        RECT MASK 2 503.907000 772.575000 504.136000 772.607000 ;
    END
  END i_mem_6_q_40_
  PIN i_mem_6_q_39_
    DIRECTION OUTPUT ;
    USE SIGNAL ;
    PORT
      LAYER M2 ;
        RECT MASK 2 503.907000 770.415000 504.136000 770.447000 ;
    END
  END i_mem_6_q_39_
  PIN i_mem_6_q_38_
    DIRECTION OUTPUT ;
    USE SIGNAL ;
    PORT
      LAYER M2 ;
        RECT MASK 2 503.907000 768.879000 504.136000 768.911000 ;
    END
  END i_mem_6_q_38_
  PIN i_mem_6_q_37_
    DIRECTION OUTPUT ;
    USE SIGNAL ;
    PORT
      LAYER M2 ;
        RECT MASK 2 503.907000 767.343000 504.136000 767.375000 ;
    END
  END i_mem_6_q_37_
  PIN i_mem_6_q_36_
    DIRECTION OUTPUT ;
    USE SIGNAL ;
    PORT
      LAYER M2 ;
        RECT MASK 2 503.907000 765.807000 504.136000 765.839000 ;
    END
  END i_mem_6_q_36_
  PIN i_mem_6_q_35_
    DIRECTION OUTPUT ;
    USE SIGNAL ;
    PORT
      LAYER M2 ;
        RECT MASK 2 503.907000 763.647000 504.136000 763.679000 ;
    END
  END i_mem_6_q_35_
  PIN i_mem_6_q_34_
    DIRECTION OUTPUT ;
    USE SIGNAL ;
    PORT
      LAYER M2 ;
        RECT MASK 2 503.907000 762.111000 504.136000 762.143000 ;
    END
  END i_mem_6_q_34_
  PIN i_mem_6_q_33_
    DIRECTION OUTPUT ;
    USE SIGNAL ;
    PORT
      LAYER M2 ;
        RECT MASK 2 503.907000 760.575000 504.136000 760.607000 ;
    END
  END i_mem_6_q_33_
  PIN i_mem_6_q_32_
    DIRECTION OUTPUT ;
    USE SIGNAL ;
    PORT
      LAYER M2 ;
        RECT MASK 2 503.907000 759.039000 504.136000 759.071000 ;
    END
  END i_mem_6_q_32_
  PIN i_mem_6_q_31_
    DIRECTION OUTPUT ;
    USE SIGNAL ;
    PORT
      LAYER M2 ;
        RECT MASK 2 503.907000 756.879000 504.136000 756.911000 ;
    END
  END i_mem_6_q_31_
  PIN i_mem_6_q_30_
    DIRECTION OUTPUT ;
    USE SIGNAL ;
    PORT
      LAYER M2 ;
        RECT MASK 2 503.907000 755.343000 504.136000 755.375000 ;
    END
  END i_mem_6_q_30_
  PIN i_mem_6_q_29_
    DIRECTION OUTPUT ;
    USE SIGNAL ;
    PORT
      LAYER M2 ;
        RECT MASK 2 503.907000 753.807000 504.136000 753.839000 ;
    END
  END i_mem_6_q_29_
  PIN i_mem_6_q_28_
    DIRECTION OUTPUT ;
    USE SIGNAL ;
    PORT
      LAYER M2 ;
        RECT MASK 2 503.907000 752.271000 504.136000 752.303000 ;
    END
  END i_mem_6_q_28_
  PIN i_mem_6_q_27_
    DIRECTION OUTPUT ;
    USE SIGNAL ;
    PORT
      LAYER M2 ;
        RECT MASK 1 503.907000 750.111000 504.136000 750.143000 ;
    END
  END i_mem_6_q_27_
  PIN i_mem_6_q_26_
    DIRECTION OUTPUT ;
    USE SIGNAL ;
    PORT
      LAYER M2 ;
        RECT MASK 1 503.907000 748.575000 504.136000 748.607000 ;
    END
  END i_mem_6_q_26_
  PIN i_mem_6_q_25_
    DIRECTION OUTPUT ;
    USE SIGNAL ;
    PORT
      LAYER M2 ;
        RECT MASK 1 503.907000 747.039000 504.136000 747.071000 ;
    END
  END i_mem_6_q_25_
  PIN i_mem_6_q_24_
    DIRECTION OUTPUT ;
    USE SIGNAL ;
    PORT
      LAYER M2 ;
        RECT MASK 1 503.907000 745.503000 504.136000 745.535000 ;
    END
  END i_mem_6_q_24_
  PIN i_mem_6_q_23_
    DIRECTION OUTPUT ;
    USE SIGNAL ;
    PORT
      LAYER M2 ;
        RECT MASK 1 503.907000 743.343000 504.136000 743.375000 ;
    END
  END i_mem_6_q_23_
  PIN i_mem_6_q_22_
    DIRECTION OUTPUT ;
    USE SIGNAL ;
    PORT
      LAYER M2 ;
        RECT MASK 1 503.907000 741.807000 504.136000 741.839000 ;
    END
  END i_mem_6_q_22_
  PIN i_mem_6_q_21_
    DIRECTION OUTPUT ;
    USE SIGNAL ;
    PORT
      LAYER M2 ;
        RECT MASK 1 503.907000 740.271000 504.136000 740.303000 ;
    END
  END i_mem_6_q_21_
  PIN i_mem_6_q_20_
    DIRECTION OUTPUT ;
    USE SIGNAL ;
    PORT
      LAYER M2 ;
        RECT MASK 1 503.907000 738.735000 504.136000 738.767000 ;
    END
  END i_mem_6_q_20_
  PIN i_mem_6_q_19_
    DIRECTION OUTPUT ;
    USE SIGNAL ;
    PORT
      LAYER M2 ;
        RECT MASK 1 503.907000 736.575000 504.136000 736.607000 ;
    END
  END i_mem_6_q_19_
  PIN i_mem_6_q_18_
    DIRECTION OUTPUT ;
    USE SIGNAL ;
    PORT
      LAYER M2 ;
        RECT MASK 1 503.907000 735.039000 504.136000 735.071000 ;
    END
  END i_mem_6_q_18_
  PIN i_mem_6_q_17_
    DIRECTION OUTPUT ;
    USE SIGNAL ;
    PORT
      LAYER M2 ;
        RECT MASK 1 503.907000 733.503000 504.136000 733.535000 ;
    END
  END i_mem_6_q_17_
  PIN i_mem_6_q_16_
    DIRECTION OUTPUT ;
    USE SIGNAL ;
    PORT
      LAYER M2 ;
        RECT MASK 1 503.907000 731.967000 504.136000 731.999000 ;
    END
  END i_mem_6_q_16_
  PIN i_mem_6_q_15_
    DIRECTION OUTPUT ;
    USE SIGNAL ;
    PORT
      LAYER M2 ;
        RECT MASK 1 503.907000 729.807000 504.136000 729.839000 ;
    END
  END i_mem_6_q_15_
  PIN i_mem_6_q_14_
    DIRECTION OUTPUT ;
    USE SIGNAL ;
    PORT
      LAYER M2 ;
        RECT MASK 1 503.907000 728.271000 504.136000 728.303000 ;
    END
  END i_mem_6_q_14_
  PIN i_mem_6_q_13_
    DIRECTION OUTPUT ;
    USE SIGNAL ;
    PORT
      LAYER M2 ;
        RECT MASK 1 503.907000 726.735000 504.136000 726.767000 ;
    END
  END i_mem_6_q_13_
  PIN i_mem_6_q_12_
    DIRECTION OUTPUT ;
    USE SIGNAL ;
    PORT
      LAYER M2 ;
        RECT MASK 1 503.907000 725.199000 504.136000 725.231000 ;
    END
  END i_mem_6_q_12_
  PIN i_mem_6_q_11_
    DIRECTION OUTPUT ;
    USE SIGNAL ;
    PORT
      LAYER M2 ;
        RECT MASK 2 503.907000 723.039000 504.136000 723.071000 ;
    END
  END i_mem_6_q_11_
  PIN i_mem_6_q_10_
    DIRECTION OUTPUT ;
    USE SIGNAL ;
    PORT
      LAYER M2 ;
        RECT MASK 2 503.907000 721.503000 504.136000 721.535000 ;
    END
  END i_mem_6_q_10_
  PIN i_mem_6_q_9_
    DIRECTION OUTPUT ;
    USE SIGNAL ;
    PORT
      LAYER M2 ;
        RECT MASK 2 503.907000 719.967000 504.136000 719.999000 ;
    END
  END i_mem_6_q_9_
  PIN i_mem_6_q_8_
    DIRECTION OUTPUT ;
    USE SIGNAL ;
    PORT
      LAYER M2 ;
        RECT MASK 2 503.907000 718.431000 504.136000 718.463000 ;
    END
  END i_mem_6_q_8_
  PIN i_mem_6_q_7_
    DIRECTION OUTPUT ;
    USE SIGNAL ;
    PORT
      LAYER M2 ;
        RECT MASK 2 503.907000 716.271000 504.136000 716.303000 ;
    END
  END i_mem_6_q_7_
  PIN i_mem_6_q_6_
    DIRECTION OUTPUT ;
    USE SIGNAL ;
    PORT
      LAYER M2 ;
        RECT MASK 2 503.907000 714.735000 504.136000 714.767000 ;
    END
  END i_mem_6_q_6_
  PIN i_mem_6_q_5_
    DIRECTION OUTPUT ;
    USE SIGNAL ;
    PORT
      LAYER M2 ;
        RECT MASK 2 503.907000 713.199000 504.136000 713.231000 ;
    END
  END i_mem_6_q_5_
  PIN i_mem_6_q_4_
    DIRECTION OUTPUT ;
    USE SIGNAL ;
    PORT
      LAYER M2 ;
        RECT MASK 2 503.907000 711.663000 504.136000 711.695000 ;
    END
  END i_mem_6_q_4_
  PIN i_mem_6_q_3_
    DIRECTION OUTPUT ;
    USE SIGNAL ;
    PORT
      LAYER M2 ;
        RECT MASK 2 503.907000 709.503000 504.136000 709.535000 ;
    END
  END i_mem_6_q_3_
  PIN i_mem_6_q_2_
    DIRECTION OUTPUT ;
    USE SIGNAL ;
    PORT
      LAYER M2 ;
        RECT MASK 2 503.907000 707.967000 504.136000 707.999000 ;
    END
  END i_mem_6_q_2_
  PIN i_mem_6_q_1_
    DIRECTION OUTPUT ;
    USE SIGNAL ;
    PORT
      LAYER M2 ;
        RECT MASK 2 503.907000 706.431000 504.136000 706.463000 ;
    END
  END i_mem_6_q_1_
  PIN i_mem_6_q_0_
    DIRECTION OUTPUT ;
    USE SIGNAL ;
    PORT
      LAYER M2 ;
        RECT MASK 2 503.907000 704.895000 504.136000 704.927000 ;
    END
  END i_mem_6_q_0_
  PIN i_mem_6_so_1_
    DIRECTION OUTPUT ;
    USE SIGNAL ;
    PORT
      LAYER M2 ;
        RECT MASK 2 503.907000 813.552000 504.136000 813.584000 ;
    END
  END i_mem_6_so_1_
  PIN i_mem_6_so_0_
    DIRECTION OUTPUT ;
    USE SIGNAL ;
    PORT
      LAYER M2 ;
        RECT MASK 2 503.907000 814.034000 504.136000 814.066000 ;
    END
  END i_mem_6_so_0_
  PIN i_mem_7_q_3_
    DIRECTION OUTPUT ;
    USE SIGNAL ;
    PORT
      LAYER M2 ;
        RECT MASK 2 0.000000 913.391000 0.229000 913.423000 ;
    END
  END i_mem_7_q_3_
  PIN i_mem_7_q_2_
    DIRECTION OUTPUT ;
    USE SIGNAL ;
    PORT
      LAYER M2 ;
        RECT MASK 2 0.000000 911.375000 0.229000 911.407000 ;
    END
  END i_mem_7_q_2_
  PIN i_mem_7_q_1_
    DIRECTION OUTPUT ;
    USE SIGNAL ;
    PORT
      LAYER M2 ;
        RECT MASK 2 0.000000 890.465000 0.229000 890.497000 ;
    END
  END i_mem_7_q_1_
  PIN i_mem_7_q_0_
    DIRECTION OUTPUT ;
    USE SIGNAL ;
    PORT
      LAYER M2 ;
        RECT MASK 2 0.000000 888.449000 0.229000 888.481000 ;
    END
  END i_mem_7_q_0_
  PIN i_mem_8_fa_aux_ctl_14_
    DIRECTION OUTPUT ;
    USE SIGNAL ;
    PORT
      LAYER M8 ;
        RECT 0.000000 525.473000 0.354000 525.535000 ;
    END
  END i_mem_8_fa_aux_ctl_14_
  PIN i_mem_8_fa_aux_ctl_13_
    DIRECTION OUTPUT ;
    USE SIGNAL ;
    PORT
      LAYER M6 ;
        RECT 0.000000 525.940000 0.375000 525.980000 ;
    END
  END i_mem_8_fa_aux_ctl_13_
  PIN i_mem_8_fa_aux_ctl_12_
    DIRECTION OUTPUT ;
    USE SIGNAL ;
    PORT
      LAYER M6 ;
        RECT 0.000000 526.100000 0.375000 526.140000 ;
    END
  END i_mem_8_fa_aux_ctl_12_
  PIN i_mem_8_fa_aux_ctl_11_
    DIRECTION OUTPUT ;
    USE SIGNAL ;
    PORT
      LAYER M8 ;
        RECT 0.000000 525.729000 0.354000 525.791000 ;
    END
  END i_mem_8_fa_aux_ctl_11_
  PIN i_mem_8_fa_aux_ctl_10_
    DIRECTION OUTPUT ;
    USE SIGNAL ;
    PORT
      LAYER M6 ;
        RECT 0.000000 526.260000 0.375000 526.300000 ;
    END
  END i_mem_8_fa_aux_ctl_10_
  PIN i_mem_8_fa_aux_ctl_9_
    DIRECTION OUTPUT ;
    USE SIGNAL ;
    PORT
      LAYER M8 ;
        RECT 0.000000 525.985000 0.354000 526.047000 ;
    END
  END i_mem_8_fa_aux_ctl_9_
  PIN i_mem_8_fa_aux_ctl_8_
    DIRECTION OUTPUT ;
    USE SIGNAL ;
    PORT
      LAYER M6 ;
        RECT 0.000000 526.420000 0.375000 526.460000 ;
    END
  END i_mem_8_fa_aux_ctl_8_
  PIN i_mem_8_fa_aux_ctl_7_
    DIRECTION OUTPUT ;
    USE SIGNAL ;
    PORT
      LAYER M6 ;
        RECT 0.000000 526.580000 0.375000 526.620000 ;
    END
  END i_mem_8_fa_aux_ctl_7_
  PIN i_mem_8_fa_aux_ctl_6_
    DIRECTION OUTPUT ;
    USE SIGNAL ;
    PORT
      LAYER M8 ;
        RECT 0.000000 526.241000 0.354000 526.303000 ;
    END
  END i_mem_8_fa_aux_ctl_6_
  PIN i_mem_8_fa_aux_ctl_5_
    DIRECTION OUTPUT ;
    USE SIGNAL ;
    PORT
      LAYER M6 ;
        RECT 0.000000 526.740000 0.375000 526.780000 ;
    END
  END i_mem_8_fa_aux_ctl_5_
  PIN i_mem_8_fa_aux_ctl_4_
    DIRECTION OUTPUT ;
    USE SIGNAL ;
    PORT
      LAYER M6 ;
        RECT 0.000000 526.900000 0.375000 526.940000 ;
    END
  END i_mem_8_fa_aux_ctl_4_
  PIN i_mem_8_fa_aux_ctl_3_
    DIRECTION OUTPUT ;
    USE SIGNAL ;
    PORT
      LAYER M8 ;
        RECT 0.000000 526.497000 0.354000 526.559000 ;
    END
  END i_mem_8_fa_aux_ctl_3_
  PIN i_mem_8_fa_aux_ctl_2_
    DIRECTION OUTPUT ;
    USE SIGNAL ;
    PORT
      LAYER M6 ;
        RECT 0.000000 527.060000 0.375000 527.100000 ;
    END
  END i_mem_8_fa_aux_ctl_2_
  PIN i_mem_8_fa_aux_ctl_1_
    DIRECTION OUTPUT ;
    USE SIGNAL ;
    PORT
      LAYER M8 ;
        RECT 0.000000 526.753000 0.354000 526.815000 ;
    END
  END i_mem_8_fa_aux_ctl_1_
  PIN i_mem_8_fa_aux_ctl_0_
    DIRECTION OUTPUT ;
    USE SIGNAL ;
    PORT
      LAYER M6 ;
        RECT 0.000000 527.220000 0.375000 527.260000 ;
    END
  END i_mem_8_fa_aux_ctl_0_
  PIN fa_analog_0_force
    DIRECTION INOUT ;
    USE SIGNAL ;
    PORT
      LAYER M3 ;
        RECT MASK 2 2.046000 0.000000 2.084000 0.193000 ;
    END
  END fa_analog_0_force
  PIN fa_analog_0_sense
    DIRECTION INOUT ;
    USE SIGNAL ;
    PORT
      LAYER M8 ;
        RECT 0.000000 412.449000 0.354000 412.511000 ;
    END
  END fa_analog_0_sense
  PIN fa_analog_1_force
    DIRECTION INOUT ;
    USE SIGNAL ;
    PORT
      LAYER M8 ;
        RECT 0.000000 426.017000 0.354000 426.079000 ;
    END
  END fa_analog_1_force
  PIN fa_analog_1_sense
    DIRECTION INOUT ;
    USE SIGNAL ;
    PORT
      LAYER M8 ;
        RECT 0.000000 291.489000 0.354000 291.551000 ;
    END
  END fa_analog_1_sense
  PIN fa_analog_2_force
    DIRECTION INOUT ;
    USE SIGNAL ;
    PORT
      LAYER M8 ;
        RECT 0.000000 286.369000 0.354000 286.431000 ;
    END
  END fa_analog_2_force
  PIN fa_analog_2_sense
    DIRECTION INOUT ;
    USE SIGNAL ;
    PORT
      LAYER M8 ;
        RECT 0.000000 281.377000 0.354000 281.439000 ;
    END
  END fa_analog_2_sense
  PIN VDD
    DIRECTION INPUT ;
    USE POWER ;
    PORT
      LAYER M5 ;
        RECT 497.060000 916.744000 497.500000 917.184000 ;
    END
    PORT
      LAYER M5 ;
        RECT 489.380000 916.744000 489.820000 917.184000 ;
    END
    PORT
      LAYER M5 ;
        RECT 481.700000 916.744000 482.140000 917.184000 ;
    END
    PORT
      LAYER M5 ;
        RECT 474.020000 916.744000 474.460000 917.184000 ;
    END
    PORT
      LAYER M5 ;
        RECT 466.340000 916.744000 466.780000 917.184000 ;
    END
    PORT
      LAYER M5 ;
        RECT 458.660000 916.744000 459.100000 917.184000 ;
    END
    PORT
      LAYER M5 ;
        RECT 450.980000 916.744000 451.420000 917.184000 ;
    END
    PORT
      LAYER M5 ;
        RECT 443.300000 916.744000 443.740000 917.184000 ;
    END
    PORT
      LAYER M5 ;
        RECT 435.620000 916.744000 436.060000 917.184000 ;
    END
    PORT
      LAYER M5 ;
        RECT 427.940000 916.744000 428.380000 917.184000 ;
    END
    PORT
      LAYER M5 ;
        RECT 420.260000 916.744000 420.700000 917.184000 ;
    END
    PORT
      LAYER M5 ;
        RECT 412.580000 916.744000 413.020000 917.184000 ;
    END
    PORT
      LAYER M5 ;
        RECT 404.900000 916.744000 405.340000 917.184000 ;
    END
    PORT
      LAYER M5 ;
        RECT 397.220000 916.744000 397.660000 917.184000 ;
    END
    PORT
      LAYER M5 ;
        RECT 389.540000 916.744000 389.980000 917.184000 ;
    END
    PORT
      LAYER M5 ;
        RECT 381.860000 916.744000 382.300000 917.184000 ;
    END
    PORT
      LAYER M5 ;
        RECT 374.180000 916.744000 374.620000 917.184000 ;
    END
    PORT
      LAYER M5 ;
        RECT 366.500000 916.744000 366.940000 917.184000 ;
    END
    PORT
      LAYER M5 ;
        RECT 358.820000 916.744000 359.260000 917.184000 ;
    END
    PORT
      LAYER M5 ;
        RECT 351.140000 916.744000 351.580000 917.184000 ;
    END
    PORT
      LAYER M5 ;
        RECT 343.460000 916.744000 343.900000 917.184000 ;
    END
    PORT
      LAYER M5 ;
        RECT 335.780000 916.744000 336.220000 917.184000 ;
    END
    PORT
      LAYER M5 ;
        RECT 328.100000 916.744000 328.540000 917.184000 ;
    END
    PORT
      LAYER M5 ;
        RECT 320.420000 916.744000 320.860000 917.184000 ;
    END
    PORT
      LAYER M5 ;
        RECT 312.740000 916.744000 313.180000 917.184000 ;
    END
    PORT
      LAYER M5 ;
        RECT 305.060000 916.744000 305.500000 917.184000 ;
    END
    PORT
      LAYER M5 ;
        RECT 297.380000 916.744000 297.820000 917.184000 ;
    END
    PORT
      LAYER M5 ;
        RECT 289.700000 916.744000 290.140000 917.184000 ;
    END
    PORT
      LAYER M5 ;
        RECT 282.020000 916.744000 282.460000 917.184000 ;
    END
    PORT
      LAYER M5 ;
        RECT 274.340000 916.744000 274.780000 917.184000 ;
    END
    PORT
      LAYER M5 ;
        RECT 266.660000 916.744000 267.100000 917.184000 ;
    END
    PORT
      LAYER M5 ;
        RECT 258.980000 916.744000 259.420000 917.184000 ;
    END
    PORT
      LAYER M5 ;
        RECT 251.300000 916.744000 251.740000 917.184000 ;
    END
    PORT
      LAYER M5 ;
        RECT 243.620000 916.744000 244.060000 917.184000 ;
    END
    PORT
      LAYER M5 ;
        RECT 235.940000 916.744000 236.380000 917.184000 ;
    END
    PORT
      LAYER M5 ;
        RECT 228.260000 916.744000 228.700000 917.184000 ;
    END
    PORT
      LAYER M5 ;
        RECT 220.580000 916.744000 221.020000 917.184000 ;
    END
    PORT
      LAYER M5 ;
        RECT 212.900000 916.744000 213.340000 917.184000 ;
    END
    PORT
      LAYER M5 ;
        RECT 205.220000 916.744000 205.660000 917.184000 ;
    END
    PORT
      LAYER M5 ;
        RECT 197.540000 916.744000 197.980000 917.184000 ;
    END
    PORT
      LAYER M5 ;
        RECT 189.860000 916.744000 190.300000 917.184000 ;
    END
    PORT
      LAYER M5 ;
        RECT 182.180000 916.744000 182.620000 917.184000 ;
    END
    PORT
      LAYER M5 ;
        RECT 174.500000 916.744000 174.940000 917.184000 ;
    END
    PORT
      LAYER M5 ;
        RECT 166.820000 916.744000 167.260000 917.184000 ;
    END
    PORT
      LAYER M5 ;
        RECT 159.140000 916.744000 159.580000 917.184000 ;
    END
    PORT
      LAYER M5 ;
        RECT 151.460000 916.744000 151.900000 917.184000 ;
    END
    PORT
      LAYER M5 ;
        RECT 143.780000 916.744000 144.220000 917.184000 ;
    END
    PORT
      LAYER M5 ;
        RECT 136.100000 916.744000 136.540000 917.184000 ;
    END
    PORT
      LAYER M5 ;
        RECT 128.420000 916.744000 128.860000 917.184000 ;
    END
    PORT
      LAYER M5 ;
        RECT 120.740000 916.744000 121.180000 917.184000 ;
    END
    PORT
      LAYER M5 ;
        RECT 113.060000 916.744000 113.500000 917.184000 ;
    END
    PORT
      LAYER M5 ;
        RECT 105.380000 916.744000 105.820000 917.184000 ;
    END
    PORT
      LAYER M5 ;
        RECT 97.700000 916.744000 98.140000 917.184000 ;
    END
    PORT
      LAYER M5 ;
        RECT 90.020000 916.744000 90.460000 917.184000 ;
    END
    PORT
      LAYER M5 ;
        RECT 82.340000 916.744000 82.780000 917.184000 ;
    END
    PORT
      LAYER M5 ;
        RECT 74.660000 916.744000 75.100000 917.184000 ;
    END
    PORT
      LAYER M5 ;
        RECT 66.980000 916.744000 67.420000 917.184000 ;
    END
    PORT
      LAYER M5 ;
        RECT 59.300000 916.744000 59.740000 917.184000 ;
    END
    PORT
      LAYER M5 ;
        RECT 51.620000 916.744000 52.060000 917.184000 ;
    END
    PORT
      LAYER M5 ;
        RECT 43.940000 916.744000 44.380000 917.184000 ;
    END
    PORT
      LAYER M5 ;
        RECT 36.260000 916.744000 36.700000 917.184000 ;
    END
    PORT
      LAYER M5 ;
        RECT 28.580000 916.744000 29.020000 917.184000 ;
    END
    PORT
      LAYER M5 ;
        RECT 20.900000 916.744000 21.340000 917.184000 ;
    END
    PORT
      LAYER M5 ;
        RECT 13.220000 916.744000 13.660000 917.184000 ;
    END
    PORT
      LAYER M5 ;
        RECT 5.540000 916.744000 5.980000 917.184000 ;
    END
    PORT
      LAYER M8 ;
        RECT 502.812000 911.338000 504.136000 912.662000 ;
    END
    PORT
      LAYER M8 ;
        RECT 0.000000 911.338000 1.324000 912.662000 ;
    END
    PORT
      LAYER M8 ;
        RECT 502.812000 888.298000 504.136000 889.622000 ;
    END
    PORT
      LAYER M8 ;
        RECT 0.000000 888.298000 1.324000 889.622000 ;
    END
    PORT
      LAYER M8 ;
        RECT 502.812000 865.258000 504.136000 866.582000 ;
    END
    PORT
      LAYER M8 ;
        RECT 0.000000 865.258000 1.324000 866.582000 ;
    END
    PORT
      LAYER M8 ;
        RECT 502.812000 842.218000 504.136000 843.542000 ;
    END
    PORT
      LAYER M8 ;
        RECT 0.000000 842.218000 1.324000 843.542000 ;
    END
    PORT
      LAYER M8 ;
        RECT 502.812000 819.178000 504.136000 820.502000 ;
    END
    PORT
      LAYER M8 ;
        RECT 0.000000 819.178000 1.324000 820.502000 ;
    END
    PORT
      LAYER M8 ;
        RECT 502.812000 796.138000 504.136000 797.462000 ;
    END
    PORT
      LAYER M8 ;
        RECT 0.000000 796.138000 1.324000 797.462000 ;
    END
    PORT
      LAYER M8 ;
        RECT 502.812000 773.098000 504.136000 774.422000 ;
    END
    PORT
      LAYER M8 ;
        RECT 0.000000 773.098000 1.324000 774.422000 ;
    END
    PORT
      LAYER M8 ;
        RECT 502.812000 750.058000 504.136000 751.382000 ;
    END
    PORT
      LAYER M8 ;
        RECT 0.000000 750.058000 1.324000 751.382000 ;
    END
    PORT
      LAYER M8 ;
        RECT 502.812000 727.018000 504.136000 728.342000 ;
    END
    PORT
      LAYER M8 ;
        RECT 0.000000 727.018000 1.324000 728.342000 ;
    END
    PORT
      LAYER M8 ;
        RECT 502.812000 703.978000 504.136000 705.302000 ;
    END
    PORT
      LAYER M8 ;
        RECT 0.000000 703.978000 1.324000 705.302000 ;
    END
    PORT
      LAYER M8 ;
        RECT 502.812000 680.938000 504.136000 682.262000 ;
    END
    PORT
      LAYER M8 ;
        RECT 0.000000 680.938000 1.324000 682.262000 ;
    END
    PORT
      LAYER M8 ;
        RECT 502.812000 657.898000 504.136000 659.222000 ;
    END
    PORT
      LAYER M8 ;
        RECT 0.000000 657.898000 1.324000 659.222000 ;
    END
    PORT
      LAYER M8 ;
        RECT 502.812000 634.858000 504.136000 636.182000 ;
    END
    PORT
      LAYER M8 ;
        RECT 0.000000 634.858000 1.324000 636.182000 ;
    END
    PORT
      LAYER M8 ;
        RECT 502.812000 611.818000 504.136000 613.142000 ;
    END
    PORT
      LAYER M8 ;
        RECT 0.000000 611.818000 1.324000 613.142000 ;
    END
    PORT
      LAYER M8 ;
        RECT 502.812000 588.778000 504.136000 590.102000 ;
    END
    PORT
      LAYER M8 ;
        RECT 0.000000 588.778000 1.324000 590.102000 ;
    END
    PORT
      LAYER M8 ;
        RECT 502.812000 565.738000 504.136000 567.062000 ;
    END
    PORT
      LAYER M8 ;
        RECT 0.000000 565.738000 1.324000 567.062000 ;
    END
    PORT
      LAYER M8 ;
        RECT 502.812000 542.698000 504.136000 544.022000 ;
    END
    PORT
      LAYER M8 ;
        RECT 0.000000 542.698000 1.324000 544.022000 ;
    END
    PORT
      LAYER M8 ;
        RECT 502.812000 519.658000 504.136000 520.982000 ;
    END
    PORT
      LAYER M8 ;
        RECT 0.000000 519.658000 1.324000 520.982000 ;
    END
    PORT
      LAYER M9 ;
        RECT 496.996000 916.616000 497.564000 917.184000 ;
    END
    PORT
      LAYER M9 ;
        RECT 489.316000 916.616000 489.884000 917.184000 ;
    END
    PORT
      LAYER M9 ;
        RECT 481.636000 916.616000 482.204000 917.184000 ;
    END
    PORT
      LAYER M9 ;
        RECT 473.956000 916.616000 474.524000 917.184000 ;
    END
    PORT
      LAYER M9 ;
        RECT 466.276000 916.616000 466.844000 917.184000 ;
    END
    PORT
      LAYER M9 ;
        RECT 458.596000 916.616000 459.164000 917.184000 ;
    END
    PORT
      LAYER M9 ;
        RECT 450.916000 916.616000 451.484000 917.184000 ;
    END
    PORT
      LAYER M9 ;
        RECT 443.236000 916.616000 443.804000 917.184000 ;
    END
    PORT
      LAYER M9 ;
        RECT 435.556000 916.616000 436.124000 917.184000 ;
    END
    PORT
      LAYER M9 ;
        RECT 427.876000 916.616000 428.444000 917.184000 ;
    END
    PORT
      LAYER M9 ;
        RECT 420.196000 916.616000 420.764000 917.184000 ;
    END
    PORT
      LAYER M9 ;
        RECT 412.516000 916.616000 413.084000 917.184000 ;
    END
    PORT
      LAYER M9 ;
        RECT 404.836000 916.616000 405.404000 917.184000 ;
    END
    PORT
      LAYER M9 ;
        RECT 397.156000 916.616000 397.724000 917.184000 ;
    END
    PORT
      LAYER M9 ;
        RECT 389.476000 916.616000 390.044000 917.184000 ;
    END
    PORT
      LAYER M9 ;
        RECT 381.796000 916.616000 382.364000 917.184000 ;
    END
    PORT
      LAYER M9 ;
        RECT 374.116000 916.616000 374.684000 917.184000 ;
    END
    PORT
      LAYER M9 ;
        RECT 366.436000 916.616000 367.004000 917.184000 ;
    END
    PORT
      LAYER M9 ;
        RECT 358.756000 916.616000 359.324000 917.184000 ;
    END
    PORT
      LAYER M9 ;
        RECT 351.076000 916.616000 351.644000 917.184000 ;
    END
    PORT
      LAYER M9 ;
        RECT 343.396000 916.616000 343.964000 917.184000 ;
    END
    PORT
      LAYER M9 ;
        RECT 335.716000 916.616000 336.284000 917.184000 ;
    END
    PORT
      LAYER M9 ;
        RECT 328.036000 916.616000 328.604000 917.184000 ;
    END
    PORT
      LAYER M9 ;
        RECT 320.356000 916.616000 320.924000 917.184000 ;
    END
    PORT
      LAYER M9 ;
        RECT 312.676000 916.616000 313.244000 917.184000 ;
    END
    PORT
      LAYER M9 ;
        RECT 304.996000 916.616000 305.564000 917.184000 ;
    END
    PORT
      LAYER M9 ;
        RECT 297.316000 916.616000 297.884000 917.184000 ;
    END
    PORT
      LAYER M9 ;
        RECT 289.636000 916.616000 290.204000 917.184000 ;
    END
    PORT
      LAYER M9 ;
        RECT 281.956000 916.616000 282.524000 917.184000 ;
    END
    PORT
      LAYER M9 ;
        RECT 274.276000 916.616000 274.844000 917.184000 ;
    END
    PORT
      LAYER M9 ;
        RECT 266.596000 916.616000 267.164000 917.184000 ;
    END
    PORT
      LAYER M9 ;
        RECT 258.916000 916.616000 259.484000 917.184000 ;
    END
    PORT
      LAYER M9 ;
        RECT 251.236000 916.616000 251.804000 917.184000 ;
    END
    PORT
      LAYER M9 ;
        RECT 243.556000 916.616000 244.124000 917.184000 ;
    END
    PORT
      LAYER M9 ;
        RECT 235.876000 916.616000 236.444000 917.184000 ;
    END
    PORT
      LAYER M9 ;
        RECT 228.196000 916.616000 228.764000 917.184000 ;
    END
    PORT
      LAYER M9 ;
        RECT 220.516000 916.616000 221.084000 917.184000 ;
    END
    PORT
      LAYER M9 ;
        RECT 212.836000 916.616000 213.404000 917.184000 ;
    END
    PORT
      LAYER M9 ;
        RECT 205.156000 916.616000 205.724000 917.184000 ;
    END
    PORT
      LAYER M9 ;
        RECT 197.476000 916.616000 198.044000 917.184000 ;
    END
    PORT
      LAYER M9 ;
        RECT 189.796000 916.616000 190.364000 917.184000 ;
    END
    PORT
      LAYER M9 ;
        RECT 182.116000 916.616000 182.684000 917.184000 ;
    END
    PORT
      LAYER M9 ;
        RECT 174.436000 916.616000 175.004000 917.184000 ;
    END
    PORT
      LAYER M9 ;
        RECT 166.756000 916.616000 167.324000 917.184000 ;
    END
    PORT
      LAYER M9 ;
        RECT 159.076000 916.616000 159.644000 917.184000 ;
    END
    PORT
      LAYER M9 ;
        RECT 151.396000 916.616000 151.964000 917.184000 ;
    END
    PORT
      LAYER M9 ;
        RECT 143.716000 916.616000 144.284000 917.184000 ;
    END
    PORT
      LAYER M9 ;
        RECT 136.036000 916.616000 136.604000 917.184000 ;
    END
    PORT
      LAYER M9 ;
        RECT 128.356000 916.616000 128.924000 917.184000 ;
    END
    PORT
      LAYER M9 ;
        RECT 120.676000 916.616000 121.244000 917.184000 ;
    END
    PORT
      LAYER M9 ;
        RECT 112.996000 916.616000 113.564000 917.184000 ;
    END
    PORT
      LAYER M9 ;
        RECT 105.316000 916.616000 105.884000 917.184000 ;
    END
    PORT
      LAYER M9 ;
        RECT 97.636000 916.616000 98.204000 917.184000 ;
    END
    PORT
      LAYER M9 ;
        RECT 89.956000 916.616000 90.524000 917.184000 ;
    END
    PORT
      LAYER M9 ;
        RECT 82.276000 916.616000 82.844000 917.184000 ;
    END
    PORT
      LAYER M9 ;
        RECT 74.596000 916.616000 75.164000 917.184000 ;
    END
    PORT
      LAYER M9 ;
        RECT 66.916000 916.616000 67.484000 917.184000 ;
    END
    PORT
      LAYER M9 ;
        RECT 59.236000 916.616000 59.804000 917.184000 ;
    END
    PORT
      LAYER M9 ;
        RECT 51.556000 916.616000 52.124000 917.184000 ;
    END
    PORT
      LAYER M9 ;
        RECT 43.876000 916.616000 44.444000 917.184000 ;
    END
    PORT
      LAYER M9 ;
        RECT 36.196000 916.616000 36.764000 917.184000 ;
    END
    PORT
      LAYER M9 ;
        RECT 28.516000 916.616000 29.084000 917.184000 ;
    END
    PORT
      LAYER M9 ;
        RECT 20.836000 916.616000 21.404000 917.184000 ;
    END
    PORT
      LAYER M9 ;
        RECT 13.156000 916.616000 13.724000 917.184000 ;
    END
    PORT
      LAYER M9 ;
        RECT 5.476000 916.616000 6.044000 917.184000 ;
    END
    PORT
      LAYER M10 ;
        RECT 498.142000 911.190000 504.136000 917.184000 ;
    END
    PORT
      LAYER M10 ;
        RECT 0.000000 911.190000 5.994000 917.184000 ;
    END
    PORT
      LAYER M10 ;
        RECT 494.836000 888.150000 504.136000 897.450000 ;
    END
    PORT
      LAYER M10 ;
        RECT 0.000000 888.150000 9.300000 897.450000 ;
    END
    PORT
      LAYER M10 ;
        RECT 494.836000 865.110000 504.136000 874.410000 ;
    END
    PORT
      LAYER M10 ;
        RECT 0.000000 865.110000 9.300000 874.410000 ;
    END
    PORT
      LAYER M10 ;
        RECT 494.836000 842.070000 504.136000 851.370000 ;
    END
    PORT
      LAYER M10 ;
        RECT 0.000000 842.070000 9.300000 851.370000 ;
    END
    PORT
      LAYER M10 ;
        RECT 494.836000 819.030000 504.136000 828.330000 ;
    END
    PORT
      LAYER M10 ;
        RECT 0.000000 819.030000 9.300000 828.330000 ;
    END
    PORT
      LAYER M10 ;
        RECT 494.836000 795.990000 504.136000 805.290000 ;
    END
    PORT
      LAYER M10 ;
        RECT 0.000000 795.990000 9.300000 805.290000 ;
    END
    PORT
      LAYER M10 ;
        RECT 494.836000 772.950000 504.136000 782.250000 ;
    END
    PORT
      LAYER M10 ;
        RECT 0.000000 772.950000 9.300000 782.250000 ;
    END
    PORT
      LAYER M10 ;
        RECT 494.836000 749.910000 504.136000 759.210000 ;
    END
    PORT
      LAYER M10 ;
        RECT 0.000000 749.910000 9.300000 759.210000 ;
    END
    PORT
      LAYER M10 ;
        RECT 494.836000 726.870000 504.136000 736.170000 ;
    END
    PORT
      LAYER M10 ;
        RECT 0.000000 726.870000 9.300000 736.170000 ;
    END
    PORT
      LAYER M10 ;
        RECT 494.836000 703.830000 504.136000 713.130000 ;
    END
    PORT
      LAYER M10 ;
        RECT 0.000000 703.830000 9.300000 713.130000 ;
    END
    PORT
      LAYER M10 ;
        RECT 494.836000 680.790000 504.136000 690.090000 ;
    END
    PORT
      LAYER M10 ;
        RECT 0.000000 680.790000 9.300000 690.090000 ;
    END
    PORT
      LAYER M10 ;
        RECT 494.836000 657.750000 504.136000 667.050000 ;
    END
    PORT
      LAYER M10 ;
        RECT 0.000000 657.750000 9.300000 667.050000 ;
    END
    PORT
      LAYER M10 ;
        RECT 494.836000 634.710000 504.136000 644.010000 ;
    END
    PORT
      LAYER M10 ;
        RECT 0.000000 634.710000 9.300000 644.010000 ;
    END
    PORT
      LAYER M10 ;
        RECT 494.836000 611.670000 504.136000 620.970000 ;
    END
    PORT
      LAYER M10 ;
        RECT 0.000000 611.670000 9.300000 620.970000 ;
    END
    PORT
      LAYER M10 ;
        RECT 494.836000 588.630000 504.136000 597.930000 ;
    END
    PORT
      LAYER M10 ;
        RECT 0.000000 588.630000 9.300000 597.930000 ;
    END
    PORT
      LAYER M10 ;
        RECT 494.836000 565.590000 504.136000 574.890000 ;
    END
    PORT
      LAYER M10 ;
        RECT 0.000000 565.590000 9.300000 574.890000 ;
    END
    PORT
      LAYER M10 ;
        RECT 494.836000 542.550000 504.136000 551.850000 ;
    END
    PORT
      LAYER M10 ;
        RECT 0.000000 542.550000 9.300000 551.850000 ;
    END
    PORT
      LAYER M10 ;
        RECT 494.836000 519.510000 504.136000 528.810000 ;
    END
    PORT
      LAYER M10 ;
        RECT 0.000000 519.510000 9.300000 528.810000 ;
    END
    PORT
      LAYER M11 ;
        RECT 11.520000 502.146000 20.820000 917.184000 ;
    END
    PORT
      LAYER M11 ;
        RECT 34.560000 502.146000 43.860000 917.184000 ;
    END
    PORT
      LAYER M11 ;
        RECT 57.600000 502.146000 66.900000 917.184000 ;
    END
    PORT
      LAYER M11 ;
        RECT 80.640000 502.146000 89.940000 917.184000 ;
    END
    PORT
      LAYER M11 ;
        RECT 103.680000 502.146000 112.980000 917.184000 ;
    END
    PORT
      LAYER M11 ;
        RECT 126.720000 502.146000 136.020000 917.184000 ;
    END
    PORT
      LAYER M11 ;
        RECT 149.760000 502.146000 159.060000 917.184000 ;
    END
    PORT
      LAYER M11 ;
        RECT 172.800000 502.146000 182.100000 917.184000 ;
    END
    PORT
      LAYER M11 ;
        RECT 195.840000 502.146000 205.140000 917.184000 ;
    END
    PORT
      LAYER M11 ;
        RECT 218.880000 502.146000 228.180000 917.184000 ;
    END
    PORT
      LAYER M11 ;
        RECT 241.920000 502.146000 251.220000 917.184000 ;
    END
    PORT
      LAYER M11 ;
        RECT 264.960000 502.146000 274.260000 917.184000 ;
    END
    PORT
      LAYER M11 ;
        RECT 288.000000 502.146000 297.300000 917.184000 ;
    END
    PORT
      LAYER M11 ;
        RECT 311.040000 502.146000 320.340000 917.184000 ;
    END
    PORT
      LAYER M11 ;
        RECT 334.080000 502.146000 343.380000 917.184000 ;
    END
    PORT
      LAYER M11 ;
        RECT 357.120000 502.146000 366.420000 917.184000 ;
    END
    PORT
      LAYER M11 ;
        RECT 380.160000 502.146000 389.460000 917.184000 ;
    END
    PORT
      LAYER M11 ;
        RECT 403.200000 502.146000 412.500000 917.184000 ;
    END
    PORT
      LAYER M11 ;
        RECT 426.240000 502.146000 435.540000 917.184000 ;
    END
    PORT
      LAYER M11 ;
        RECT 449.280000 502.146000 458.580000 917.184000 ;
    END
    PORT
      LAYER M11 ;
        RECT 472.320000 502.146000 481.620000 917.184000 ;
    END
    PORT
      LAYER M11 ;
        RECT 495.360000 502.146000 504.136000 917.184000 ;
    END
  END VDD
  PIN VSS
    DIRECTION INPUT ;
    USE GROUND ;
    PORT
      LAYER M5 ;
        RECT 493.220000 916.744000 493.660000 917.184000 ;
    END
    PORT
      LAYER M5 ;
        RECT 485.540000 916.744000 485.980000 917.184000 ;
    END
    PORT
      LAYER M5 ;
        RECT 477.860000 916.744000 478.300000 917.184000 ;
    END
    PORT
      LAYER M5 ;
        RECT 470.180000 916.744000 470.620000 917.184000 ;
    END
    PORT
      LAYER M5 ;
        RECT 462.500000 916.744000 462.940000 917.184000 ;
    END
    PORT
      LAYER M5 ;
        RECT 454.820000 916.744000 455.260000 917.184000 ;
    END
    PORT
      LAYER M5 ;
        RECT 447.140000 916.744000 447.580000 917.184000 ;
    END
    PORT
      LAYER M5 ;
        RECT 439.460000 916.744000 439.900000 917.184000 ;
    END
    PORT
      LAYER M5 ;
        RECT 431.780000 916.744000 432.220000 917.184000 ;
    END
    PORT
      LAYER M5 ;
        RECT 424.100000 916.744000 424.540000 917.184000 ;
    END
    PORT
      LAYER M5 ;
        RECT 416.420000 916.744000 416.860000 917.184000 ;
    END
    PORT
      LAYER M5 ;
        RECT 408.740000 916.744000 409.180000 917.184000 ;
    END
    PORT
      LAYER M5 ;
        RECT 401.060000 916.744000 401.500000 917.184000 ;
    END
    PORT
      LAYER M5 ;
        RECT 393.380000 916.744000 393.820000 917.184000 ;
    END
    PORT
      LAYER M5 ;
        RECT 385.700000 916.744000 386.140000 917.184000 ;
    END
    PORT
      LAYER M5 ;
        RECT 378.020000 916.744000 378.460000 917.184000 ;
    END
    PORT
      LAYER M5 ;
        RECT 370.340000 916.744000 370.780000 917.184000 ;
    END
    PORT
      LAYER M5 ;
        RECT 362.660000 916.744000 363.100000 917.184000 ;
    END
    PORT
      LAYER M5 ;
        RECT 354.980000 916.744000 355.420000 917.184000 ;
    END
    PORT
      LAYER M5 ;
        RECT 347.300000 916.744000 347.740000 917.184000 ;
    END
    PORT
      LAYER M5 ;
        RECT 339.620000 916.744000 340.060000 917.184000 ;
    END
    PORT
      LAYER M5 ;
        RECT 331.940000 916.744000 332.380000 917.184000 ;
    END
    PORT
      LAYER M5 ;
        RECT 324.260000 916.744000 324.700000 917.184000 ;
    END
    PORT
      LAYER M5 ;
        RECT 316.580000 916.744000 317.020000 917.184000 ;
    END
    PORT
      LAYER M5 ;
        RECT 308.900000 916.744000 309.340000 917.184000 ;
    END
    PORT
      LAYER M5 ;
        RECT 301.220000 916.744000 301.660000 917.184000 ;
    END
    PORT
      LAYER M5 ;
        RECT 293.540000 916.744000 293.980000 917.184000 ;
    END
    PORT
      LAYER M5 ;
        RECT 285.860000 916.744000 286.300000 917.184000 ;
    END
    PORT
      LAYER M5 ;
        RECT 278.180000 916.744000 278.620000 917.184000 ;
    END
    PORT
      LAYER M5 ;
        RECT 270.500000 916.744000 270.940000 917.184000 ;
    END
    PORT
      LAYER M5 ;
        RECT 262.820000 916.744000 263.260000 917.184000 ;
    END
    PORT
      LAYER M5 ;
        RECT 255.140000 916.744000 255.580000 917.184000 ;
    END
    PORT
      LAYER M5 ;
        RECT 247.460000 916.744000 247.900000 917.184000 ;
    END
    PORT
      LAYER M5 ;
        RECT 239.780000 916.744000 240.220000 917.184000 ;
    END
    PORT
      LAYER M5 ;
        RECT 232.100000 916.744000 232.540000 917.184000 ;
    END
    PORT
      LAYER M5 ;
        RECT 224.420000 916.744000 224.860000 917.184000 ;
    END
    PORT
      LAYER M5 ;
        RECT 216.740000 916.744000 217.180000 917.184000 ;
    END
    PORT
      LAYER M5 ;
        RECT 209.060000 916.744000 209.500000 917.184000 ;
    END
    PORT
      LAYER M5 ;
        RECT 201.380000 916.744000 201.820000 917.184000 ;
    END
    PORT
      LAYER M5 ;
        RECT 193.700000 916.744000 194.140000 917.184000 ;
    END
    PORT
      LAYER M5 ;
        RECT 186.020000 916.744000 186.460000 917.184000 ;
    END
    PORT
      LAYER M5 ;
        RECT 178.340000 916.744000 178.780000 917.184000 ;
    END
    PORT
      LAYER M5 ;
        RECT 170.660000 916.744000 171.100000 917.184000 ;
    END
    PORT
      LAYER M5 ;
        RECT 162.980000 916.744000 163.420000 917.184000 ;
    END
    PORT
      LAYER M5 ;
        RECT 155.300000 916.744000 155.740000 917.184000 ;
    END
    PORT
      LAYER M5 ;
        RECT 147.620000 916.744000 148.060000 917.184000 ;
    END
    PORT
      LAYER M5 ;
        RECT 139.940000 916.744000 140.380000 917.184000 ;
    END
    PORT
      LAYER M5 ;
        RECT 132.260000 916.744000 132.700000 917.184000 ;
    END
    PORT
      LAYER M5 ;
        RECT 124.580000 916.744000 125.020000 917.184000 ;
    END
    PORT
      LAYER M5 ;
        RECT 116.900000 916.744000 117.340000 917.184000 ;
    END
    PORT
      LAYER M5 ;
        RECT 109.220000 916.744000 109.660000 917.184000 ;
    END
    PORT
      LAYER M5 ;
        RECT 101.540000 916.744000 101.980000 917.184000 ;
    END
    PORT
      LAYER M5 ;
        RECT 93.860000 916.744000 94.300000 917.184000 ;
    END
    PORT
      LAYER M5 ;
        RECT 86.180000 916.744000 86.620000 917.184000 ;
    END
    PORT
      LAYER M5 ;
        RECT 78.500000 916.744000 78.940000 917.184000 ;
    END
    PORT
      LAYER M5 ;
        RECT 70.820000 916.744000 71.260000 917.184000 ;
    END
    PORT
      LAYER M5 ;
        RECT 63.140000 916.744000 63.580000 917.184000 ;
    END
    PORT
      LAYER M5 ;
        RECT 55.460000 916.744000 55.900000 917.184000 ;
    END
    PORT
      LAYER M5 ;
        RECT 47.780000 916.744000 48.220000 917.184000 ;
    END
    PORT
      LAYER M5 ;
        RECT 40.100000 916.744000 40.540000 917.184000 ;
    END
    PORT
      LAYER M5 ;
        RECT 32.420000 916.744000 32.860000 917.184000 ;
    END
    PORT
      LAYER M5 ;
        RECT 24.740000 916.744000 25.180000 917.184000 ;
    END
    PORT
      LAYER M5 ;
        RECT 17.060000 916.744000 17.500000 917.184000 ;
    END
    PORT
      LAYER M5 ;
        RECT 9.380000 916.744000 9.820000 917.184000 ;
    END
    PORT
      LAYER M5 ;
        RECT 1.700000 916.744000 2.140000 917.184000 ;
    END
    PORT
      LAYER M8 ;
        RECT 502.812000 899.818000 504.136000 901.142000 ;
    END
    PORT
      LAYER M8 ;
        RECT 0.000000 899.818000 1.324000 901.142000 ;
    END
    PORT
      LAYER M8 ;
        RECT 502.812000 876.778000 504.136000 878.102000 ;
    END
    PORT
      LAYER M8 ;
        RECT 0.000000 876.778000 1.324000 878.102000 ;
    END
    PORT
      LAYER M8 ;
        RECT 502.812000 853.738000 504.136000 855.062000 ;
    END
    PORT
      LAYER M8 ;
        RECT 0.000000 853.738000 1.324000 855.062000 ;
    END
    PORT
      LAYER M8 ;
        RECT 502.812000 830.698000 504.136000 832.022000 ;
    END
    PORT
      LAYER M8 ;
        RECT 0.000000 830.698000 1.324000 832.022000 ;
    END
    PORT
      LAYER M8 ;
        RECT 502.812000 807.658000 504.136000 808.982000 ;
    END
    PORT
      LAYER M8 ;
        RECT 0.000000 807.658000 1.324000 808.982000 ;
    END
    PORT
      LAYER M8 ;
        RECT 502.812000 784.618000 504.136000 785.942000 ;
    END
    PORT
      LAYER M8 ;
        RECT 0.000000 784.618000 1.324000 785.942000 ;
    END
    PORT
      LAYER M8 ;
        RECT 502.812000 761.578000 504.136000 762.902000 ;
    END
    PORT
      LAYER M8 ;
        RECT 0.000000 761.578000 1.324000 762.902000 ;
    END
    PORT
      LAYER M8 ;
        RECT 502.812000 738.538000 504.136000 739.862000 ;
    END
    PORT
      LAYER M8 ;
        RECT 0.000000 738.538000 1.324000 739.862000 ;
    END
    PORT
      LAYER M8 ;
        RECT 502.812000 715.498000 504.136000 716.822000 ;
    END
    PORT
      LAYER M8 ;
        RECT 0.000000 715.498000 1.324000 716.822000 ;
    END
    PORT
      LAYER M8 ;
        RECT 502.812000 692.458000 504.136000 693.782000 ;
    END
    PORT
      LAYER M8 ;
        RECT 0.000000 692.458000 1.324000 693.782000 ;
    END
    PORT
      LAYER M8 ;
        RECT 502.812000 669.418000 504.136000 670.742000 ;
    END
    PORT
      LAYER M8 ;
        RECT 0.000000 669.418000 1.324000 670.742000 ;
    END
    PORT
      LAYER M8 ;
        RECT 502.812000 646.378000 504.136000 647.702000 ;
    END
    PORT
      LAYER M8 ;
        RECT 0.000000 646.378000 1.324000 647.702000 ;
    END
    PORT
      LAYER M8 ;
        RECT 502.812000 623.338000 504.136000 624.662000 ;
    END
    PORT
      LAYER M8 ;
        RECT 0.000000 623.338000 1.324000 624.662000 ;
    END
    PORT
      LAYER M8 ;
        RECT 502.812000 600.298000 504.136000 601.622000 ;
    END
    PORT
      LAYER M8 ;
        RECT 0.000000 600.298000 1.324000 601.622000 ;
    END
    PORT
      LAYER M8 ;
        RECT 502.812000 577.258000 504.136000 578.582000 ;
    END
    PORT
      LAYER M8 ;
        RECT 0.000000 577.258000 1.324000 578.582000 ;
    END
    PORT
      LAYER M8 ;
        RECT 502.812000 554.218000 504.136000 555.542000 ;
    END
    PORT
      LAYER M8 ;
        RECT 0.000000 554.218000 1.324000 555.542000 ;
    END
    PORT
      LAYER M8 ;
        RECT 502.812000 531.178000 504.136000 532.502000 ;
    END
    PORT
      LAYER M8 ;
        RECT 0.000000 531.178000 1.324000 532.502000 ;
    END
    PORT
      LAYER M8 ;
        RECT 502.812000 508.138000 504.136000 509.462000 ;
    END
    PORT
      LAYER M8 ;
        RECT 0.000000 508.138000 1.324000 509.462000 ;
    END
    PORT
      LAYER M9 ;
        RECT 500.836000 916.616000 501.404000 917.184000 ;
    END
    PORT
      LAYER M9 ;
        RECT 493.156000 916.616000 493.724000 917.184000 ;
    END
    PORT
      LAYER M9 ;
        RECT 485.476000 916.616000 486.044000 917.184000 ;
    END
    PORT
      LAYER M9 ;
        RECT 477.796000 916.616000 478.364000 917.184000 ;
    END
    PORT
      LAYER M9 ;
        RECT 470.116000 916.616000 470.684000 917.184000 ;
    END
    PORT
      LAYER M9 ;
        RECT 462.436000 916.616000 463.004000 917.184000 ;
    END
    PORT
      LAYER M9 ;
        RECT 454.756000 916.616000 455.324000 917.184000 ;
    END
    PORT
      LAYER M9 ;
        RECT 447.076000 916.616000 447.644000 917.184000 ;
    END
    PORT
      LAYER M9 ;
        RECT 439.396000 916.616000 439.964000 917.184000 ;
    END
    PORT
      LAYER M9 ;
        RECT 431.716000 916.616000 432.284000 917.184000 ;
    END
    PORT
      LAYER M9 ;
        RECT 424.036000 916.616000 424.604000 917.184000 ;
    END
    PORT
      LAYER M9 ;
        RECT 416.356000 916.616000 416.924000 917.184000 ;
    END
    PORT
      LAYER M9 ;
        RECT 408.676000 916.616000 409.244000 917.184000 ;
    END
    PORT
      LAYER M9 ;
        RECT 400.996000 916.616000 401.564000 917.184000 ;
    END
    PORT
      LAYER M9 ;
        RECT 393.316000 916.616000 393.884000 917.184000 ;
    END
    PORT
      LAYER M9 ;
        RECT 385.636000 916.616000 386.204000 917.184000 ;
    END
    PORT
      LAYER M9 ;
        RECT 377.956000 916.616000 378.524000 917.184000 ;
    END
    PORT
      LAYER M9 ;
        RECT 370.276000 916.616000 370.844000 917.184000 ;
    END
    PORT
      LAYER M9 ;
        RECT 362.596000 916.616000 363.164000 917.184000 ;
    END
    PORT
      LAYER M9 ;
        RECT 354.916000 916.616000 355.484000 917.184000 ;
    END
    PORT
      LAYER M9 ;
        RECT 347.236000 916.616000 347.804000 917.184000 ;
    END
    PORT
      LAYER M9 ;
        RECT 339.556000 916.616000 340.124000 917.184000 ;
    END
    PORT
      LAYER M9 ;
        RECT 331.876000 916.616000 332.444000 917.184000 ;
    END
    PORT
      LAYER M9 ;
        RECT 324.196000 916.616000 324.764000 917.184000 ;
    END
    PORT
      LAYER M9 ;
        RECT 316.516000 916.616000 317.084000 917.184000 ;
    END
    PORT
      LAYER M9 ;
        RECT 308.836000 916.616000 309.404000 917.184000 ;
    END
    PORT
      LAYER M9 ;
        RECT 301.156000 916.616000 301.724000 917.184000 ;
    END
    PORT
      LAYER M9 ;
        RECT 293.476000 916.616000 294.044000 917.184000 ;
    END
    PORT
      LAYER M9 ;
        RECT 285.796000 916.616000 286.364000 917.184000 ;
    END
    PORT
      LAYER M9 ;
        RECT 278.116000 916.616000 278.684000 917.184000 ;
    END
    PORT
      LAYER M9 ;
        RECT 270.436000 916.616000 271.004000 917.184000 ;
    END
    PORT
      LAYER M9 ;
        RECT 262.756000 916.616000 263.324000 917.184000 ;
    END
    PORT
      LAYER M9 ;
        RECT 255.076000 916.616000 255.644000 917.184000 ;
    END
    PORT
      LAYER M9 ;
        RECT 247.396000 916.616000 247.964000 917.184000 ;
    END
    PORT
      LAYER M9 ;
        RECT 239.716000 916.616000 240.284000 917.184000 ;
    END
    PORT
      LAYER M9 ;
        RECT 232.036000 916.616000 232.604000 917.184000 ;
    END
    PORT
      LAYER M9 ;
        RECT 224.356000 916.616000 224.924000 917.184000 ;
    END
    PORT
      LAYER M9 ;
        RECT 216.676000 916.616000 217.244000 917.184000 ;
    END
    PORT
      LAYER M9 ;
        RECT 208.996000 916.616000 209.564000 917.184000 ;
    END
    PORT
      LAYER M9 ;
        RECT 201.316000 916.616000 201.884000 917.184000 ;
    END
    PORT
      LAYER M9 ;
        RECT 193.636000 916.616000 194.204000 917.184000 ;
    END
    PORT
      LAYER M9 ;
        RECT 185.956000 916.616000 186.524000 917.184000 ;
    END
    PORT
      LAYER M9 ;
        RECT 178.276000 916.616000 178.844000 917.184000 ;
    END
    PORT
      LAYER M9 ;
        RECT 170.596000 916.616000 171.164000 917.184000 ;
    END
    PORT
      LAYER M9 ;
        RECT 162.916000 916.616000 163.484000 917.184000 ;
    END
    PORT
      LAYER M9 ;
        RECT 155.236000 916.616000 155.804000 917.184000 ;
    END
    PORT
      LAYER M9 ;
        RECT 147.556000 916.616000 148.124000 917.184000 ;
    END
    PORT
      LAYER M9 ;
        RECT 139.876000 916.616000 140.444000 917.184000 ;
    END
    PORT
      LAYER M9 ;
        RECT 132.196000 916.616000 132.764000 917.184000 ;
    END
    PORT
      LAYER M9 ;
        RECT 124.516000 916.616000 125.084000 917.184000 ;
    END
    PORT
      LAYER M9 ;
        RECT 116.836000 916.616000 117.404000 917.184000 ;
    END
    PORT
      LAYER M9 ;
        RECT 109.156000 916.616000 109.724000 917.184000 ;
    END
    PORT
      LAYER M9 ;
        RECT 101.476000 916.616000 102.044000 917.184000 ;
    END
    PORT
      LAYER M9 ;
        RECT 93.796000 916.616000 94.364000 917.184000 ;
    END
    PORT
      LAYER M9 ;
        RECT 86.116000 916.616000 86.684000 917.184000 ;
    END
    PORT
      LAYER M9 ;
        RECT 78.436000 916.616000 79.004000 917.184000 ;
    END
    PORT
      LAYER M9 ;
        RECT 70.756000 916.616000 71.324000 917.184000 ;
    END
    PORT
      LAYER M9 ;
        RECT 63.076000 916.616000 63.644000 917.184000 ;
    END
    PORT
      LAYER M9 ;
        RECT 55.396000 916.616000 55.964000 917.184000 ;
    END
    PORT
      LAYER M9 ;
        RECT 47.716000 916.616000 48.284000 917.184000 ;
    END
    PORT
      LAYER M9 ;
        RECT 40.036000 916.616000 40.604000 917.184000 ;
    END
    PORT
      LAYER M9 ;
        RECT 32.356000 916.616000 32.924000 917.184000 ;
    END
    PORT
      LAYER M9 ;
        RECT 24.676000 916.616000 25.244000 917.184000 ;
    END
    PORT
      LAYER M9 ;
        RECT 16.996000 916.616000 17.564000 917.184000 ;
    END
    PORT
      LAYER M9 ;
        RECT 9.316000 916.616000 9.884000 917.184000 ;
    END
    PORT
      LAYER M9 ;
        RECT 1.636000 916.616000 2.204000 917.184000 ;
    END
    PORT
      LAYER M10 ;
        RECT 494.836000 899.670000 504.136000 908.970000 ;
    END
    PORT
      LAYER M10 ;
        RECT 0.000000 899.670000 9.300000 908.970000 ;
    END
    PORT
      LAYER M10 ;
        RECT 494.836000 876.630000 504.136000 885.930000 ;
    END
    PORT
      LAYER M10 ;
        RECT 0.000000 876.630000 9.300000 885.930000 ;
    END
    PORT
      LAYER M10 ;
        RECT 494.836000 853.590000 504.136000 862.890000 ;
    END
    PORT
      LAYER M10 ;
        RECT 0.000000 853.590000 9.300000 862.890000 ;
    END
    PORT
      LAYER M10 ;
        RECT 494.836000 830.550000 504.136000 839.850000 ;
    END
    PORT
      LAYER M10 ;
        RECT 0.000000 830.550000 9.300000 839.850000 ;
    END
    PORT
      LAYER M10 ;
        RECT 494.836000 807.510000 504.136000 816.810000 ;
    END
    PORT
      LAYER M10 ;
        RECT 0.000000 807.510000 9.300000 816.810000 ;
    END
    PORT
      LAYER M10 ;
        RECT 494.836000 784.470000 504.136000 793.770000 ;
    END
    PORT
      LAYER M10 ;
        RECT 0.000000 784.470000 9.300000 793.770000 ;
    END
    PORT
      LAYER M10 ;
        RECT 494.836000 761.430000 504.136000 770.730000 ;
    END
    PORT
      LAYER M10 ;
        RECT 0.000000 761.430000 9.300000 770.730000 ;
    END
    PORT
      LAYER M10 ;
        RECT 494.836000 738.390000 504.136000 747.690000 ;
    END
    PORT
      LAYER M10 ;
        RECT 0.000000 738.390000 9.300000 747.690000 ;
    END
    PORT
      LAYER M10 ;
        RECT 494.836000 715.350000 504.136000 724.650000 ;
    END
    PORT
      LAYER M10 ;
        RECT 0.000000 715.350000 9.300000 724.650000 ;
    END
    PORT
      LAYER M10 ;
        RECT 494.836000 692.310000 504.136000 701.610000 ;
    END
    PORT
      LAYER M10 ;
        RECT 0.000000 692.310000 9.300000 701.610000 ;
    END
    PORT
      LAYER M10 ;
        RECT 494.836000 669.270000 504.136000 678.570000 ;
    END
    PORT
      LAYER M10 ;
        RECT 0.000000 669.270000 9.300000 678.570000 ;
    END
    PORT
      LAYER M10 ;
        RECT 494.836000 646.230000 504.136000 655.530000 ;
    END
    PORT
      LAYER M10 ;
        RECT 0.000000 646.230000 9.300000 655.530000 ;
    END
    PORT
      LAYER M10 ;
        RECT 494.836000 623.190000 504.136000 632.490000 ;
    END
    PORT
      LAYER M10 ;
        RECT 0.000000 623.190000 9.300000 632.490000 ;
    END
    PORT
      LAYER M10 ;
        RECT 494.836000 600.150000 504.136000 609.450000 ;
    END
    PORT
      LAYER M10 ;
        RECT 0.000000 600.150000 9.300000 609.450000 ;
    END
    PORT
      LAYER M10 ;
        RECT 494.836000 577.110000 504.136000 586.410000 ;
    END
    PORT
      LAYER M10 ;
        RECT 0.000000 577.110000 9.300000 586.410000 ;
    END
    PORT
      LAYER M10 ;
        RECT 494.836000 554.070000 504.136000 563.370000 ;
    END
    PORT
      LAYER M10 ;
        RECT 0.000000 554.070000 9.300000 563.370000 ;
    END
    PORT
      LAYER M10 ;
        RECT 494.836000 531.030000 504.136000 540.330000 ;
    END
    PORT
      LAYER M10 ;
        RECT 0.000000 531.030000 9.300000 540.330000 ;
    END
    PORT
      LAYER M10 ;
        RECT 494.836000 507.990000 504.136000 517.290000 ;
    END
    PORT
      LAYER M10 ;
        RECT 0.000000 507.990000 9.300000 517.290000 ;
    END
    PORT
      LAYER M11 ;
        RECT 0.000000 502.146000 9.300000 917.184000 ;
    END
    PORT
      LAYER M11 ;
        RECT 23.040000 502.146000 32.340000 917.184000 ;
    END
    PORT
      LAYER M11 ;
        RECT 46.080000 502.146000 55.380000 917.184000 ;
    END
    PORT
      LAYER M11 ;
        RECT 69.120000 502.146000 78.420000 917.184000 ;
    END
    PORT
      LAYER M11 ;
        RECT 92.160000 502.146000 101.460000 917.184000 ;
    END
    PORT
      LAYER M11 ;
        RECT 115.200000 502.146000 124.500000 917.184000 ;
    END
    PORT
      LAYER M11 ;
        RECT 138.240000 502.146000 147.540000 917.184000 ;
    END
    PORT
      LAYER M11 ;
        RECT 161.280000 502.146000 170.580000 917.184000 ;
    END
    PORT
      LAYER M11 ;
        RECT 184.320000 502.146000 193.620000 917.184000 ;
    END
    PORT
      LAYER M11 ;
        RECT 207.360000 502.146000 216.660000 917.184000 ;
    END
    PORT
      LAYER M11 ;
        RECT 230.400000 502.146000 239.700000 917.184000 ;
    END
    PORT
      LAYER M11 ;
        RECT 253.440000 502.146000 262.740000 917.184000 ;
    END
    PORT
      LAYER M11 ;
        RECT 276.480000 502.146000 285.780000 917.184000 ;
    END
    PORT
      LAYER M11 ;
        RECT 299.520000 502.146000 308.820000 917.184000 ;
    END
    PORT
      LAYER M11 ;
        RECT 322.560000 502.146000 331.860000 917.184000 ;
    END
    PORT
      LAYER M11 ;
        RECT 345.600000 502.146000 354.900000 917.184000 ;
    END
    PORT
      LAYER M11 ;
        RECT 368.640000 502.146000 377.940000 917.184000 ;
    END
    PORT
      LAYER M11 ;
        RECT 391.680000 502.146000 400.980000 917.184000 ;
    END
    PORT
      LAYER M11 ;
        RECT 414.720000 502.146000 424.020000 917.184000 ;
    END
    PORT
      LAYER M11 ;
        RECT 437.760000 502.146000 447.060000 917.184000 ;
    END
    PORT
      LAYER M11 ;
        RECT 460.800000 502.146000 470.100000 917.184000 ;
    END
    PORT
      LAYER M11 ;
        RECT 483.840000 502.146000 493.140000 917.184000 ;
    END
  END VSS
  OBS
    LAYER M1 ;
      RECT 0.000000 0.000000 504.136000 917.184000 ;
    LAYER M2 ;
      RECT 0.000000 914.897000 504.136000 917.184000 ;
      RECT 0.000000 914.253000 503.601000 914.897000 ;
      RECT 0.000000 913.729000 504.136000 914.253000 ;
      RECT 0.535000 913.361000 504.136000 913.729000 ;
      RECT 0.535000 913.085000 503.601000 913.361000 ;
      RECT 0.000000 912.717000 503.601000 913.085000 ;
      RECT 0.000000 911.825000 504.136000 912.717000 ;
      RECT 0.000000 911.713000 503.601000 911.825000 ;
      RECT 0.535000 911.181000 503.601000 911.713000 ;
      RECT 0.535000 911.069000 504.136000 911.181000 ;
      RECT 0.000000 910.289000 504.136000 911.069000 ;
      RECT 0.000000 909.645000 503.601000 910.289000 ;
      RECT 0.000000 908.129000 504.136000 909.645000 ;
      RECT 0.000000 907.485000 503.601000 908.129000 ;
      RECT 0.000000 906.593000 504.136000 907.485000 ;
      RECT 0.000000 905.949000 503.601000 906.593000 ;
      RECT 0.000000 905.057000 504.136000 905.949000 ;
      RECT 0.000000 904.413000 503.601000 905.057000 ;
      RECT 0.000000 903.521000 504.136000 904.413000 ;
      RECT 0.000000 902.877000 503.601000 903.521000 ;
      RECT 0.000000 901.361000 504.136000 902.877000 ;
      RECT 0.000000 900.717000 503.601000 901.361000 ;
      RECT 0.000000 899.825000 504.136000 900.717000 ;
      RECT 0.000000 899.181000 503.601000 899.825000 ;
      RECT 0.000000 898.289000 504.136000 899.181000 ;
      RECT 0.000000 897.645000 503.601000 898.289000 ;
      RECT 0.000000 896.753000 504.136000 897.645000 ;
      RECT 0.000000 896.109000 503.601000 896.753000 ;
      RECT 0.000000 894.593000 504.136000 896.109000 ;
      RECT 0.000000 893.949000 503.601000 894.593000 ;
      RECT 0.000000 893.057000 504.136000 893.949000 ;
      RECT 0.000000 892.413000 503.601000 893.057000 ;
      RECT 0.000000 891.521000 504.136000 892.413000 ;
      RECT 0.000000 890.877000 503.601000 891.521000 ;
      RECT 0.000000 890.803000 504.136000 890.877000 ;
      RECT 0.535000 890.159000 504.136000 890.803000 ;
      RECT 0.000000 889.985000 504.136000 890.159000 ;
      RECT 0.000000 889.341000 503.601000 889.985000 ;
      RECT 0.000000 888.787000 504.136000 889.341000 ;
      RECT 0.535000 888.143000 504.136000 888.787000 ;
      RECT 0.000000 887.825000 504.136000 888.143000 ;
      RECT 0.000000 887.181000 503.601000 887.825000 ;
      RECT 0.000000 886.289000 504.136000 887.181000 ;
      RECT 0.000000 885.645000 503.601000 886.289000 ;
      RECT 0.000000 884.753000 504.136000 885.645000 ;
      RECT 0.000000 884.673000 503.601000 884.753000 ;
      RECT 0.535000 884.109000 503.601000 884.673000 ;
      RECT 0.535000 884.029000 504.136000 884.109000 ;
      RECT 0.000000 883.235000 504.136000 884.029000 ;
      RECT 0.535000 883.217000 504.136000 883.235000 ;
      RECT 0.535000 882.573000 503.601000 883.217000 ;
      RECT 0.535000 882.013000 504.136000 882.573000 ;
      RECT 0.000000 881.219000 504.136000 882.013000 ;
      RECT 0.535000 881.057000 504.136000 881.219000 ;
      RECT 0.535000 880.575000 503.601000 881.057000 ;
      RECT 0.000000 880.514000 503.601000 880.575000 ;
      RECT 0.535000 880.413000 503.601000 880.514000 ;
      RECT 0.535000 879.758000 504.136000 880.413000 ;
      RECT 0.000000 879.521000 504.136000 879.758000 ;
      RECT 0.000000 878.877000 503.601000 879.521000 ;
      RECT 0.000000 878.769000 504.136000 878.877000 ;
      RECT 0.535000 877.985000 504.136000 878.769000 ;
      RECT 0.535000 877.965000 503.601000 877.985000 ;
      RECT 0.000000 877.341000 503.601000 877.965000 ;
      RECT 0.000000 876.449000 504.136000 877.341000 ;
      RECT 0.000000 875.805000 503.601000 876.449000 ;
      RECT 0.000000 875.281000 504.136000 875.805000 ;
      RECT 0.535000 874.289000 504.136000 875.281000 ;
      RECT 0.535000 873.645000 503.601000 874.289000 ;
      RECT 0.535000 872.753000 504.136000 873.645000 ;
      RECT 0.535000 872.590000 503.601000 872.753000 ;
      RECT 0.000000 872.109000 503.601000 872.590000 ;
      RECT 0.000000 871.217000 504.136000 872.109000 ;
      RECT 0.000000 870.573000 503.601000 871.217000 ;
      RECT 0.000000 870.545000 504.136000 870.573000 ;
      RECT 0.535000 869.681000 504.136000 870.545000 ;
      RECT 0.535000 869.038000 503.601000 869.681000 ;
      RECT 0.000000 869.037000 503.601000 869.038000 ;
      RECT 0.000000 867.986000 504.136000 869.037000 ;
      RECT 0.535000 867.521000 504.136000 867.986000 ;
      RECT 0.535000 867.342000 503.601000 867.521000 ;
      RECT 0.000000 866.877000 503.601000 867.342000 ;
      RECT 0.000000 865.985000 504.136000 866.877000 ;
      RECT 0.000000 865.341000 503.601000 865.985000 ;
      RECT 0.000000 864.449000 504.136000 865.341000 ;
      RECT 0.000000 863.805000 503.601000 864.449000 ;
      RECT 0.000000 862.913000 504.136000 863.805000 ;
      RECT 0.000000 862.269000 503.601000 862.913000 ;
      RECT 0.000000 861.393000 504.136000 862.269000 ;
      RECT 0.535000 860.753000 504.136000 861.393000 ;
      RECT 0.535000 860.749000 503.601000 860.753000 ;
      RECT 0.000000 860.109000 503.601000 860.749000 ;
      RECT 0.000000 859.955000 504.136000 860.109000 ;
      RECT 0.535000 859.217000 504.136000 859.955000 ;
      RECT 0.535000 858.733000 503.601000 859.217000 ;
      RECT 0.000000 858.573000 503.601000 858.733000 ;
      RECT 0.000000 857.939000 504.136000 858.573000 ;
      RECT 0.535000 857.681000 504.136000 857.939000 ;
      RECT 0.535000 857.295000 503.601000 857.681000 ;
      RECT 0.000000 857.037000 503.601000 857.295000 ;
      RECT 0.000000 856.145000 504.136000 857.037000 ;
      RECT 0.000000 855.501000 503.601000 856.145000 ;
      RECT 0.000000 855.075000 504.136000 855.501000 ;
      RECT 0.535000 854.431000 504.136000 855.075000 ;
      RECT 0.000000 853.985000 504.136000 854.431000 ;
      RECT 0.000000 853.341000 503.601000 853.985000 ;
      RECT 0.000000 853.059000 504.136000 853.341000 ;
      RECT 0.535000 852.449000 504.136000 853.059000 ;
      RECT 0.535000 852.415000 503.601000 852.449000 ;
      RECT 0.000000 851.805000 503.601000 852.415000 ;
      RECT 0.000000 850.913000 504.136000 851.805000 ;
      RECT 0.000000 850.269000 503.601000 850.913000 ;
      RECT 0.000000 849.377000 504.136000 850.269000 ;
      RECT 0.000000 848.733000 503.601000 849.377000 ;
      RECT 0.000000 847.217000 504.136000 848.733000 ;
      RECT 0.000000 846.573000 503.601000 847.217000 ;
      RECT 0.000000 845.681000 504.136000 846.573000 ;
      RECT 0.000000 845.037000 503.601000 845.681000 ;
      RECT 0.000000 844.145000 504.136000 845.037000 ;
      RECT 0.000000 843.501000 503.601000 844.145000 ;
      RECT 0.000000 842.609000 504.136000 843.501000 ;
      RECT 0.000000 841.965000 503.601000 842.609000 ;
      RECT 0.000000 840.449000 504.136000 841.965000 ;
      RECT 0.000000 839.805000 503.601000 840.449000 ;
      RECT 0.000000 838.913000 504.136000 839.805000 ;
      RECT 0.000000 838.269000 503.601000 838.913000 ;
      RECT 0.000000 837.377000 504.136000 838.269000 ;
      RECT 0.000000 836.733000 503.601000 837.377000 ;
      RECT 0.000000 835.841000 504.136000 836.733000 ;
      RECT 0.000000 835.197000 503.601000 835.841000 ;
      RECT 0.000000 833.681000 504.136000 835.197000 ;
      RECT 0.000000 833.037000 503.601000 833.681000 ;
      RECT 0.000000 832.145000 504.136000 833.037000 ;
      RECT 0.000000 831.953000 503.601000 832.145000 ;
      RECT 0.535000 831.501000 503.601000 831.953000 ;
      RECT 0.535000 831.309000 504.136000 831.501000 ;
      RECT 0.000000 830.609000 504.136000 831.309000 ;
      RECT 0.000000 829.965000 503.601000 830.609000 ;
      RECT 0.000000 829.937000 504.136000 829.965000 ;
      RECT 0.535000 829.293000 504.136000 829.937000 ;
      RECT 0.000000 829.073000 504.136000 829.293000 ;
      RECT 0.000000 828.429000 503.601000 829.073000 ;
      RECT 0.000000 826.913000 504.136000 828.429000 ;
      RECT 0.000000 826.269000 503.601000 826.913000 ;
      RECT 0.000000 825.377000 504.136000 826.269000 ;
      RECT 0.000000 824.733000 503.601000 825.377000 ;
      RECT 0.000000 823.841000 504.136000 824.733000 ;
      RECT 0.000000 823.197000 503.601000 823.841000 ;
      RECT 0.000000 822.305000 504.136000 823.197000 ;
      RECT 0.000000 821.661000 503.601000 822.305000 ;
      RECT 0.000000 820.145000 504.136000 821.661000 ;
      RECT 0.000000 819.501000 503.601000 820.145000 ;
      RECT 0.000000 818.609000 504.136000 819.501000 ;
      RECT 0.000000 817.965000 503.601000 818.609000 ;
      RECT 0.000000 814.532000 504.136000 817.965000 ;
      RECT 0.000000 812.606000 503.601000 814.532000 ;
      RECT 0.000000 812.130000 504.136000 812.606000 ;
      RECT 0.000000 811.486000 503.601000 812.130000 ;
      RECT 0.000000 807.492000 504.136000 811.486000 ;
      RECT 0.000000 806.848000 503.601000 807.492000 ;
      RECT 0.000000 801.521000 504.136000 806.848000 ;
      RECT 0.000000 800.877000 503.601000 801.521000 ;
      RECT 0.000000 799.985000 504.136000 800.877000 ;
      RECT 0.000000 799.341000 503.601000 799.985000 ;
      RECT 0.000000 797.825000 504.136000 799.341000 ;
      RECT 0.000000 797.181000 503.601000 797.825000 ;
      RECT 0.000000 796.289000 504.136000 797.181000 ;
      RECT 0.000000 795.645000 503.601000 796.289000 ;
      RECT 0.000000 794.753000 504.136000 795.645000 ;
      RECT 0.000000 794.109000 503.601000 794.753000 ;
      RECT 0.000000 793.217000 504.136000 794.109000 ;
      RECT 0.000000 792.573000 503.601000 793.217000 ;
      RECT 0.000000 791.057000 504.136000 792.573000 ;
      RECT 0.000000 790.413000 503.601000 791.057000 ;
      RECT 0.000000 789.521000 504.136000 790.413000 ;
      RECT 0.000000 788.877000 503.601000 789.521000 ;
      RECT 0.000000 787.985000 504.136000 788.877000 ;
      RECT 0.000000 787.341000 503.601000 787.985000 ;
      RECT 0.000000 786.449000 504.136000 787.341000 ;
      RECT 0.000000 785.805000 503.601000 786.449000 ;
      RECT 0.000000 784.289000 504.136000 785.805000 ;
      RECT 0.000000 783.645000 503.601000 784.289000 ;
      RECT 0.000000 782.753000 504.136000 783.645000 ;
      RECT 0.000000 782.109000 503.601000 782.753000 ;
      RECT 0.000000 781.217000 504.136000 782.109000 ;
      RECT 0.000000 780.573000 503.601000 781.217000 ;
      RECT 0.000000 779.681000 504.136000 780.573000 ;
      RECT 0.000000 779.037000 503.601000 779.681000 ;
      RECT 0.000000 777.521000 504.136000 779.037000 ;
      RECT 0.000000 776.877000 503.601000 777.521000 ;
      RECT 0.000000 775.985000 504.136000 776.877000 ;
      RECT 0.000000 775.341000 503.601000 775.985000 ;
      RECT 0.000000 774.449000 504.136000 775.341000 ;
      RECT 0.000000 773.805000 503.601000 774.449000 ;
      RECT 0.000000 772.913000 504.136000 773.805000 ;
      RECT 0.000000 772.269000 503.601000 772.913000 ;
      RECT 0.000000 770.753000 504.136000 772.269000 ;
      RECT 0.000000 770.109000 503.601000 770.753000 ;
      RECT 0.000000 769.217000 504.136000 770.109000 ;
      RECT 0.000000 768.573000 503.601000 769.217000 ;
      RECT 0.000000 767.681000 504.136000 768.573000 ;
      RECT 0.000000 767.037000 503.601000 767.681000 ;
      RECT 0.000000 766.145000 504.136000 767.037000 ;
      RECT 0.000000 765.501000 503.601000 766.145000 ;
      RECT 0.000000 763.985000 504.136000 765.501000 ;
      RECT 0.000000 763.341000 503.601000 763.985000 ;
      RECT 0.000000 762.449000 504.136000 763.341000 ;
      RECT 0.000000 761.805000 503.601000 762.449000 ;
      RECT 0.000000 760.913000 504.136000 761.805000 ;
      RECT 0.000000 760.269000 503.601000 760.913000 ;
      RECT 0.000000 759.377000 504.136000 760.269000 ;
      RECT 0.000000 758.733000 503.601000 759.377000 ;
      RECT 0.000000 757.217000 504.136000 758.733000 ;
      RECT 0.000000 756.573000 503.601000 757.217000 ;
      RECT 0.000000 755.681000 504.136000 756.573000 ;
      RECT 0.000000 755.037000 503.601000 755.681000 ;
      RECT 0.000000 754.145000 504.136000 755.037000 ;
      RECT 0.000000 753.501000 503.601000 754.145000 ;
      RECT 0.000000 752.609000 504.136000 753.501000 ;
      RECT 0.000000 751.965000 503.601000 752.609000 ;
      RECT 0.000000 750.449000 504.136000 751.965000 ;
      RECT 0.000000 749.805000 503.601000 750.449000 ;
      RECT 0.000000 748.913000 504.136000 749.805000 ;
      RECT 0.000000 748.269000 503.601000 748.913000 ;
      RECT 0.000000 747.377000 504.136000 748.269000 ;
      RECT 0.000000 746.733000 503.601000 747.377000 ;
      RECT 0.000000 745.841000 504.136000 746.733000 ;
      RECT 0.000000 745.197000 503.601000 745.841000 ;
      RECT 0.000000 743.681000 504.136000 745.197000 ;
      RECT 0.000000 743.037000 503.601000 743.681000 ;
      RECT 0.000000 742.145000 504.136000 743.037000 ;
      RECT 0.000000 741.501000 503.601000 742.145000 ;
      RECT 0.000000 740.609000 504.136000 741.501000 ;
      RECT 0.000000 739.965000 503.601000 740.609000 ;
      RECT 0.000000 739.073000 504.136000 739.965000 ;
      RECT 0.000000 738.429000 503.601000 739.073000 ;
      RECT 0.000000 736.913000 504.136000 738.429000 ;
      RECT 0.000000 736.269000 503.601000 736.913000 ;
      RECT 0.000000 735.377000 504.136000 736.269000 ;
      RECT 0.000000 734.733000 503.601000 735.377000 ;
      RECT 0.000000 733.841000 504.136000 734.733000 ;
      RECT 0.000000 733.197000 503.601000 733.841000 ;
      RECT 0.000000 732.305000 504.136000 733.197000 ;
      RECT 0.000000 731.661000 503.601000 732.305000 ;
      RECT 0.000000 730.145000 504.136000 731.661000 ;
      RECT 0.000000 729.501000 503.601000 730.145000 ;
      RECT 0.000000 728.609000 504.136000 729.501000 ;
      RECT 0.000000 727.965000 503.601000 728.609000 ;
      RECT 0.000000 727.073000 504.136000 727.965000 ;
      RECT 0.000000 726.429000 503.601000 727.073000 ;
      RECT 0.000000 725.537000 504.136000 726.429000 ;
      RECT 0.000000 724.893000 503.601000 725.537000 ;
      RECT 0.000000 723.377000 504.136000 724.893000 ;
      RECT 0.000000 722.733000 503.601000 723.377000 ;
      RECT 0.000000 721.841000 504.136000 722.733000 ;
      RECT 0.000000 721.197000 503.601000 721.841000 ;
      RECT 0.000000 720.305000 504.136000 721.197000 ;
      RECT 0.000000 719.661000 503.601000 720.305000 ;
      RECT 0.000000 718.769000 504.136000 719.661000 ;
      RECT 0.000000 718.125000 503.601000 718.769000 ;
      RECT 0.000000 716.609000 504.136000 718.125000 ;
      RECT 0.000000 715.965000 503.601000 716.609000 ;
      RECT 0.000000 715.073000 504.136000 715.965000 ;
      RECT 0.000000 714.429000 503.601000 715.073000 ;
      RECT 0.000000 713.537000 504.136000 714.429000 ;
      RECT 0.000000 712.893000 503.601000 713.537000 ;
      RECT 0.000000 712.001000 504.136000 712.893000 ;
      RECT 0.000000 711.357000 503.601000 712.001000 ;
      RECT 0.000000 709.841000 504.136000 711.357000 ;
      RECT 0.000000 709.197000 503.601000 709.841000 ;
      RECT 0.000000 708.305000 504.136000 709.197000 ;
      RECT 0.000000 707.661000 503.601000 708.305000 ;
      RECT 0.000000 706.769000 504.136000 707.661000 ;
      RECT 0.000000 706.125000 503.601000 706.769000 ;
      RECT 0.000000 705.233000 504.136000 706.125000 ;
      RECT 0.000000 704.589000 503.601000 705.233000 ;
      RECT 0.000000 702.194000 504.136000 704.589000 ;
      RECT 0.000000 701.550000 503.601000 702.194000 ;
      RECT 0.000000 701.146000 504.136000 701.550000 ;
      RECT 0.000000 700.182000 503.601000 701.146000 ;
      RECT 0.000000 699.514000 504.136000 700.182000 ;
      RECT 0.000000 698.550000 503.601000 699.514000 ;
      RECT 0.000000 697.882000 504.136000 698.550000 ;
      RECT 0.000000 696.918000 503.601000 697.882000 ;
      RECT 0.000000 696.830000 504.136000 696.918000 ;
      RECT 0.000000 695.286000 503.601000 696.830000 ;
      RECT 0.000000 695.142000 504.136000 695.286000 ;
      RECT 0.000000 686.998000 503.601000 695.142000 ;
      RECT 0.000000 680.410000 504.136000 686.998000 ;
      RECT 0.000000 679.766000 503.601000 680.410000 ;
      RECT 0.000000 678.778000 504.136000 679.766000 ;
      RECT 0.000000 678.134000 503.601000 678.778000 ;
      RECT 0.000000 677.820000 504.136000 678.134000 ;
      RECT 0.000000 677.176000 503.601000 677.820000 ;
      RECT 0.000000 677.146000 504.136000 677.176000 ;
      RECT 0.000000 676.502000 503.601000 677.146000 ;
      RECT 0.000000 675.514000 504.136000 676.502000 ;
      RECT 0.000000 674.870000 503.601000 675.514000 ;
      RECT 0.000000 674.612000 504.136000 674.870000 ;
      RECT 0.000000 673.968000 503.601000 674.612000 ;
      RECT 0.000000 571.746000 504.136000 673.968000 ;
      RECT 0.535000 571.102000 504.136000 571.746000 ;
      RECT 0.000000 569.441000 504.136000 571.102000 ;
      RECT 0.535000 567.773000 504.136000 569.441000 ;
      RECT 0.000000 566.177000 504.136000 567.773000 ;
      RECT 0.535000 563.629000 504.136000 566.177000 ;
      RECT 0.000000 562.577000 504.136000 563.629000 ;
      RECT 0.535000 561.709000 504.136000 562.577000 ;
      RECT 0.000000 561.201000 504.136000 561.709000 ;
      RECT 0.535000 557.869000 504.136000 561.201000 ;
      RECT 0.000000 557.698000 504.136000 557.869000 ;
      RECT 0.535000 556.173000 504.136000 557.698000 ;
      RECT 0.000000 556.051000 504.136000 556.173000 ;
      RECT 0.535000 551.554000 504.136000 556.051000 ;
      RECT 0.535000 550.573000 503.601000 551.554000 ;
      RECT 0.000000 550.449000 503.601000 550.573000 ;
      RECT 0.535000 548.653000 503.601000 550.449000 ;
      RECT 0.000000 548.529000 503.601000 548.653000 ;
      RECT 0.535000 547.117000 503.601000 548.529000 ;
      RECT 0.000000 546.449000 503.601000 547.117000 ;
      RECT 0.535000 545.421000 503.601000 546.449000 ;
      RECT 0.000000 544.915000 503.601000 545.421000 ;
      RECT 0.535000 543.247000 503.601000 544.915000 ;
      RECT 0.000000 541.651000 503.601000 543.247000 ;
      RECT 0.535000 539.983000 503.601000 541.651000 ;
      RECT 0.000000 538.322000 503.601000 539.983000 ;
      RECT 0.535000 536.830000 503.601000 538.322000 ;
      RECT 0.000000 534.403000 503.601000 536.830000 ;
      RECT 0.535000 533.759000 503.601000 534.403000 ;
      RECT 0.000000 531.139000 503.601000 533.759000 ;
      RECT 0.535000 530.495000 503.601000 531.139000 ;
      RECT 0.000000 526.097000 503.601000 530.495000 ;
      RECT 0.535000 525.453000 503.601000 526.097000 ;
      RECT 0.000000 521.105000 503.601000 525.453000 ;
      RECT 0.535000 520.461000 503.601000 521.105000 ;
      RECT 0.000000 518.194000 503.601000 520.461000 ;
      RECT 0.535000 517.550000 503.601000 518.194000 ;
      RECT 0.000000 514.963000 503.601000 517.550000 ;
      RECT 0.535000 514.319000 503.601000 514.963000 ;
      RECT 0.000000 509.809000 503.601000 514.319000 ;
      RECT 0.535000 509.165000 503.601000 509.809000 ;
      RECT 0.000000 506.545000 503.601000 509.165000 ;
      RECT 0.535000 505.901000 503.601000 506.545000 ;
      RECT 0.000000 503.490000 503.601000 505.901000 ;
      RECT 0.535000 501.438000 503.601000 503.490000 ;
      RECT 0.000000 2.306000 504.136000 501.438000 ;
      RECT 0.535000 1.662000 504.136000 2.306000 ;
      RECT 0.000000 0.000000 504.136000 1.662000 ;
    LAYER M3 ;
      RECT 252.430000 916.685000 504.136000 917.184000 ;
      RECT 0.000000 916.685000 251.780000 917.184000 ;
      RECT 0.000000 0.499000 504.136000 916.685000 ;
      RECT 2.390000 0.000000 504.136000 0.499000 ;
      RECT 0.000000 0.000000 1.740000 0.499000 ;
    LAYER M4 ;
      RECT 0.000000 869.790000 504.136000 917.184000 ;
      RECT 0.825000 868.850000 504.136000 869.790000 ;
      RECT 0.000000 558.990000 504.136000 868.850000 ;
      RECT 0.825000 558.050000 504.136000 558.990000 ;
      RECT 0.000000 551.870000 504.136000 558.050000 ;
      RECT 0.000000 538.110000 503.311000 551.870000 ;
      RECT 0.825000 536.690000 503.311000 538.110000 ;
      RECT 0.000000 503.550000 503.311000 536.690000 ;
      RECT 0.825000 501.330000 503.311000 503.550000 ;
      RECT 0.000000 2.430000 504.136000 501.330000 ;
      RECT 0.825000 1.490000 504.136000 2.430000 ;
      RECT 0.000000 0.000000 504.136000 1.490000 ;
    LAYER M5 ;
      RECT 497.950000 916.294000 504.136000 917.184000 ;
      RECT 494.110000 916.294000 496.610000 917.184000 ;
      RECT 490.270000 916.294000 492.770000 917.184000 ;
      RECT 486.430000 916.294000 488.930000 917.184000 ;
      RECT 482.590000 916.294000 485.090000 917.184000 ;
      RECT 478.750000 916.294000 481.250000 917.184000 ;
      RECT 474.910000 916.294000 477.410000 917.184000 ;
      RECT 471.070000 916.294000 473.570000 917.184000 ;
      RECT 467.230000 916.294000 469.730000 917.184000 ;
      RECT 463.390000 916.294000 465.890000 917.184000 ;
      RECT 459.550000 916.294000 462.050000 917.184000 ;
      RECT 455.710000 916.294000 458.210000 917.184000 ;
      RECT 451.870000 916.294000 454.370000 917.184000 ;
      RECT 448.030000 916.294000 450.530000 917.184000 ;
      RECT 444.190000 916.294000 446.690000 917.184000 ;
      RECT 440.350000 916.294000 442.850000 917.184000 ;
      RECT 436.510000 916.294000 439.010000 917.184000 ;
      RECT 432.670000 916.294000 435.170000 917.184000 ;
      RECT 428.830000 916.294000 431.330000 917.184000 ;
      RECT 424.990000 916.294000 427.490000 917.184000 ;
      RECT 421.150000 916.294000 423.650000 917.184000 ;
      RECT 417.310000 916.294000 419.810000 917.184000 ;
      RECT 413.470000 916.294000 415.970000 917.184000 ;
      RECT 409.630000 916.294000 412.130000 917.184000 ;
      RECT 405.790000 916.294000 408.290000 917.184000 ;
      RECT 401.950000 916.294000 404.450000 917.184000 ;
      RECT 398.110000 916.294000 400.610000 917.184000 ;
      RECT 394.270000 916.294000 396.770000 917.184000 ;
      RECT 390.430000 916.294000 392.930000 917.184000 ;
      RECT 386.590000 916.294000 389.090000 917.184000 ;
      RECT 382.750000 916.294000 385.250000 917.184000 ;
      RECT 378.910000 916.294000 381.410000 917.184000 ;
      RECT 375.070000 916.294000 377.570000 917.184000 ;
      RECT 371.230000 916.294000 373.730000 917.184000 ;
      RECT 367.390000 916.294000 369.890000 917.184000 ;
      RECT 363.550000 916.294000 366.050000 917.184000 ;
      RECT 359.710000 916.294000 362.210000 917.184000 ;
      RECT 355.870000 916.294000 358.370000 917.184000 ;
      RECT 352.030000 916.294000 354.530000 917.184000 ;
      RECT 348.190000 916.294000 350.690000 917.184000 ;
      RECT 344.350000 916.294000 346.850000 917.184000 ;
      RECT 340.510000 916.294000 343.010000 917.184000 ;
      RECT 336.670000 916.294000 339.170000 917.184000 ;
      RECT 332.830000 916.294000 335.330000 917.184000 ;
      RECT 328.990000 916.294000 331.490000 917.184000 ;
      RECT 325.150000 916.294000 327.650000 917.184000 ;
      RECT 321.310000 916.294000 323.810000 917.184000 ;
      RECT 317.470000 916.294000 319.970000 917.184000 ;
      RECT 313.630000 916.294000 316.130000 917.184000 ;
      RECT 309.790000 916.294000 312.290000 917.184000 ;
      RECT 305.950000 916.294000 308.450000 917.184000 ;
      RECT 302.110000 916.294000 304.610000 917.184000 ;
      RECT 298.270000 916.294000 300.770000 917.184000 ;
      RECT 294.430000 916.294000 296.930000 917.184000 ;
      RECT 290.590000 916.294000 293.090000 917.184000 ;
      RECT 286.750000 916.294000 289.250000 917.184000 ;
      RECT 282.910000 916.294000 285.410000 917.184000 ;
      RECT 279.070000 916.294000 281.570000 917.184000 ;
      RECT 275.230000 916.294000 277.730000 917.184000 ;
      RECT 271.390000 916.294000 273.890000 917.184000 ;
      RECT 267.550000 916.294000 270.050000 917.184000 ;
      RECT 263.710000 916.294000 266.210000 917.184000 ;
      RECT 259.870000 916.294000 262.370000 917.184000 ;
      RECT 256.030000 916.294000 258.530000 917.184000 ;
      RECT 252.190000 916.294000 254.690000 917.184000 ;
      RECT 248.350000 916.294000 250.850000 917.184000 ;
      RECT 244.510000 916.294000 247.010000 917.184000 ;
      RECT 240.670000 916.294000 243.170000 917.184000 ;
      RECT 236.830000 916.294000 239.330000 917.184000 ;
      RECT 232.990000 916.294000 235.490000 917.184000 ;
      RECT 229.150000 916.294000 231.650000 917.184000 ;
      RECT 225.310000 916.294000 227.810000 917.184000 ;
      RECT 221.470000 916.294000 223.970000 917.184000 ;
      RECT 217.630000 916.294000 220.130000 917.184000 ;
      RECT 213.790000 916.294000 216.290000 917.184000 ;
      RECT 209.950000 916.294000 212.450000 917.184000 ;
      RECT 206.110000 916.294000 208.610000 917.184000 ;
      RECT 202.270000 916.294000 204.770000 917.184000 ;
      RECT 198.430000 916.294000 200.930000 917.184000 ;
      RECT 194.590000 916.294000 197.090000 917.184000 ;
      RECT 190.750000 916.294000 193.250000 917.184000 ;
      RECT 186.910000 916.294000 189.410000 917.184000 ;
      RECT 183.070000 916.294000 185.570000 917.184000 ;
      RECT 179.230000 916.294000 181.730000 917.184000 ;
      RECT 175.390000 916.294000 177.890000 917.184000 ;
      RECT 171.550000 916.294000 174.050000 917.184000 ;
      RECT 167.710000 916.294000 170.210000 917.184000 ;
      RECT 163.870000 916.294000 166.370000 917.184000 ;
      RECT 160.030000 916.294000 162.530000 917.184000 ;
      RECT 156.190000 916.294000 158.690000 917.184000 ;
      RECT 152.350000 916.294000 154.850000 917.184000 ;
      RECT 148.510000 916.294000 151.010000 917.184000 ;
      RECT 144.670000 916.294000 147.170000 917.184000 ;
      RECT 140.830000 916.294000 143.330000 917.184000 ;
      RECT 136.990000 916.294000 139.490000 917.184000 ;
      RECT 133.150000 916.294000 135.650000 917.184000 ;
      RECT 129.310000 916.294000 131.810000 917.184000 ;
      RECT 125.470000 916.294000 127.970000 917.184000 ;
      RECT 121.630000 916.294000 124.130000 917.184000 ;
      RECT 117.790000 916.294000 120.290000 917.184000 ;
      RECT 113.950000 916.294000 116.450000 917.184000 ;
      RECT 110.110000 916.294000 112.610000 917.184000 ;
      RECT 106.270000 916.294000 108.770000 917.184000 ;
      RECT 102.430000 916.294000 104.930000 917.184000 ;
      RECT 98.590000 916.294000 101.090000 917.184000 ;
      RECT 94.750000 916.294000 97.250000 917.184000 ;
      RECT 90.910000 916.294000 93.410000 917.184000 ;
      RECT 87.070000 916.294000 89.570000 917.184000 ;
      RECT 83.230000 916.294000 85.730000 917.184000 ;
      RECT 79.390000 916.294000 81.890000 917.184000 ;
      RECT 75.550000 916.294000 78.050000 917.184000 ;
      RECT 71.710000 916.294000 74.210000 917.184000 ;
      RECT 67.870000 916.294000 70.370000 917.184000 ;
      RECT 64.030000 916.294000 66.530000 917.184000 ;
      RECT 60.190000 916.294000 62.690000 917.184000 ;
      RECT 56.350000 916.294000 58.850000 917.184000 ;
      RECT 52.510000 916.294000 55.010000 917.184000 ;
      RECT 48.670000 916.294000 51.170000 917.184000 ;
      RECT 44.830000 916.294000 47.330000 917.184000 ;
      RECT 40.990000 916.294000 43.490000 917.184000 ;
      RECT 37.150000 916.294000 39.650000 917.184000 ;
      RECT 33.310000 916.294000 35.810000 917.184000 ;
      RECT 29.470000 916.294000 31.970000 917.184000 ;
      RECT 25.630000 916.294000 28.130000 917.184000 ;
      RECT 21.790000 916.294000 24.290000 917.184000 ;
      RECT 17.950000 916.294000 20.450000 917.184000 ;
      RECT 14.110000 916.294000 16.610000 917.184000 ;
      RECT 10.270000 916.294000 12.770000 917.184000 ;
      RECT 6.430000 916.294000 8.930000 917.184000 ;
      RECT 2.590000 916.294000 5.090000 917.184000 ;
      RECT 0.000000 916.294000 1.250000 917.184000 ;
      RECT 0.000000 0.000000 504.136000 916.294000 ;
    LAYER M6 ;
      RECT 0.000000 556.350000 504.136000 917.184000 ;
      RECT 0.825000 551.630000 504.136000 556.350000 ;
      RECT 0.825000 501.330000 503.311000 551.630000 ;
      RECT 0.000000 2.430000 504.136000 501.330000 ;
      RECT 0.825000 1.490000 504.136000 2.430000 ;
      RECT 0.000000 0.000000 504.136000 1.490000 ;
    LAYER M7 ;
      RECT 0.000000 0.000000 504.136000 917.184000 ;
    LAYER M8 ;
      RECT 0.000000 913.112000 504.136000 917.184000 ;
      RECT 1.774000 910.888000 502.362000 913.112000 ;
      RECT 0.000000 901.592000 504.136000 910.888000 ;
      RECT 1.774000 899.368000 502.362000 901.592000 ;
      RECT 0.000000 890.072000 504.136000 899.368000 ;
      RECT 1.774000 887.848000 502.362000 890.072000 ;
      RECT 0.000000 878.552000 504.136000 887.848000 ;
      RECT 1.774000 876.328000 502.362000 878.552000 ;
      RECT 0.000000 867.032000 504.136000 876.328000 ;
      RECT 1.774000 864.808000 502.362000 867.032000 ;
      RECT 0.000000 855.512000 504.136000 864.808000 ;
      RECT 1.774000 853.288000 502.362000 855.512000 ;
      RECT 0.000000 843.992000 504.136000 853.288000 ;
      RECT 1.774000 841.768000 502.362000 843.992000 ;
      RECT 0.000000 832.472000 504.136000 841.768000 ;
      RECT 1.774000 830.248000 502.362000 832.472000 ;
      RECT 0.000000 820.952000 504.136000 830.248000 ;
      RECT 1.774000 818.728000 502.362000 820.952000 ;
      RECT 0.000000 809.432000 504.136000 818.728000 ;
      RECT 1.774000 807.208000 502.362000 809.432000 ;
      RECT 0.000000 797.912000 504.136000 807.208000 ;
      RECT 1.774000 795.688000 502.362000 797.912000 ;
      RECT 0.000000 786.392000 504.136000 795.688000 ;
      RECT 1.774000 784.168000 502.362000 786.392000 ;
      RECT 0.000000 774.872000 504.136000 784.168000 ;
      RECT 1.774000 772.648000 502.362000 774.872000 ;
      RECT 0.000000 763.352000 504.136000 772.648000 ;
      RECT 1.774000 761.128000 502.362000 763.352000 ;
      RECT 0.000000 751.832000 504.136000 761.128000 ;
      RECT 1.774000 749.608000 502.362000 751.832000 ;
      RECT 0.000000 740.312000 504.136000 749.608000 ;
      RECT 1.774000 738.088000 502.362000 740.312000 ;
      RECT 0.000000 728.792000 504.136000 738.088000 ;
      RECT 1.774000 726.568000 502.362000 728.792000 ;
      RECT 0.000000 717.272000 504.136000 726.568000 ;
      RECT 1.774000 715.048000 502.362000 717.272000 ;
      RECT 0.000000 705.752000 504.136000 715.048000 ;
      RECT 1.774000 703.528000 502.362000 705.752000 ;
      RECT 0.000000 694.232000 504.136000 703.528000 ;
      RECT 1.774000 692.008000 502.362000 694.232000 ;
      RECT 0.000000 682.712000 504.136000 692.008000 ;
      RECT 1.774000 680.488000 502.362000 682.712000 ;
      RECT 0.000000 671.192000 504.136000 680.488000 ;
      RECT 1.774000 668.968000 502.362000 671.192000 ;
      RECT 0.000000 659.672000 504.136000 668.968000 ;
      RECT 1.774000 657.448000 502.362000 659.672000 ;
      RECT 0.000000 648.152000 504.136000 657.448000 ;
      RECT 1.774000 645.928000 502.362000 648.152000 ;
      RECT 0.000000 636.632000 504.136000 645.928000 ;
      RECT 1.774000 634.408000 502.362000 636.632000 ;
      RECT 0.000000 625.112000 504.136000 634.408000 ;
      RECT 1.774000 622.888000 502.362000 625.112000 ;
      RECT 0.000000 613.592000 504.136000 622.888000 ;
      RECT 1.774000 611.368000 502.362000 613.592000 ;
      RECT 0.000000 602.072000 504.136000 611.368000 ;
      RECT 1.774000 599.848000 502.362000 602.072000 ;
      RECT 0.000000 594.015000 504.136000 599.848000 ;
      RECT 0.000000 592.929000 503.568000 594.015000 ;
      RECT 0.000000 590.552000 504.136000 592.929000 ;
      RECT 1.774000 588.328000 502.362000 590.552000 ;
      RECT 0.000000 579.032000 504.136000 588.328000 ;
      RECT 1.774000 576.808000 502.362000 579.032000 ;
      RECT 0.000000 567.512000 504.136000 576.808000 ;
      RECT 1.774000 565.288000 502.362000 567.512000 ;
      RECT 0.000000 562.143000 504.136000 565.288000 ;
      RECT 0.000000 561.057000 503.568000 562.143000 ;
      RECT 0.000000 556.449000 504.136000 561.057000 ;
      RECT 0.804000 555.992000 504.136000 556.449000 ;
      RECT 1.774000 553.768000 502.362000 555.992000 ;
      RECT 0.000000 552.737000 504.136000 553.768000 ;
      RECT 0.804000 551.841000 504.136000 552.737000 ;
      RECT 0.804000 544.472000 503.332000 551.841000 ;
      RECT 1.774000 542.248000 502.362000 544.472000 ;
      RECT 0.804000 532.952000 503.332000 542.248000 ;
      RECT 1.774000 530.728000 502.362000 532.952000 ;
      RECT 0.804000 521.432000 503.332000 530.728000 ;
      RECT 1.774000 519.208000 502.362000 521.432000 ;
      RECT 0.804000 518.495000 503.332000 519.208000 ;
      RECT 0.804000 518.305000 503.568000 518.495000 ;
      RECT 0.804000 509.912000 503.332000 518.305000 ;
      RECT 1.774000 507.688000 502.362000 509.912000 ;
      RECT 0.804000 501.343000 503.332000 507.688000 ;
      RECT 0.000000 426.529000 504.136000 501.343000 ;
      RECT 0.804000 425.567000 504.136000 426.529000 ;
      RECT 0.000000 412.961000 504.136000 425.567000 ;
      RECT 0.804000 411.999000 504.136000 412.961000 ;
      RECT 0.000000 292.001000 504.136000 411.999000 ;
      RECT 0.804000 291.039000 504.136000 292.001000 ;
      RECT 0.000000 286.881000 504.136000 291.039000 ;
      RECT 0.804000 285.919000 504.136000 286.881000 ;
      RECT 0.000000 281.889000 504.136000 285.919000 ;
      RECT 0.804000 280.927000 504.136000 281.889000 ;
      RECT 0.000000 0.000000 504.136000 280.927000 ;
    LAYER M9 ;
      RECT 501.854000 916.166000 504.136000 917.184000 ;
      RECT 498.014000 916.166000 500.386000 917.184000 ;
      RECT 494.174000 916.166000 496.546000 917.184000 ;
      RECT 490.334000 916.166000 492.706000 917.184000 ;
      RECT 486.494000 916.166000 488.866000 917.184000 ;
      RECT 482.654000 916.166000 485.026000 917.184000 ;
      RECT 478.814000 916.166000 481.186000 917.184000 ;
      RECT 474.974000 916.166000 477.346000 917.184000 ;
      RECT 471.134000 916.166000 473.506000 917.184000 ;
      RECT 467.294000 916.166000 469.666000 917.184000 ;
      RECT 463.454000 916.166000 465.826000 917.184000 ;
      RECT 459.614000 916.166000 461.986000 917.184000 ;
      RECT 455.774000 916.166000 458.146000 917.184000 ;
      RECT 451.934000 916.166000 454.306000 917.184000 ;
      RECT 448.094000 916.166000 450.466000 917.184000 ;
      RECT 444.254000 916.166000 446.626000 917.184000 ;
      RECT 440.414000 916.166000 442.786000 917.184000 ;
      RECT 436.574000 916.166000 438.946000 917.184000 ;
      RECT 432.734000 916.166000 435.106000 917.184000 ;
      RECT 428.894000 916.166000 431.266000 917.184000 ;
      RECT 425.054000 916.166000 427.426000 917.184000 ;
      RECT 421.214000 916.166000 423.586000 917.184000 ;
      RECT 417.374000 916.166000 419.746000 917.184000 ;
      RECT 413.534000 916.166000 415.906000 917.184000 ;
      RECT 409.694000 916.166000 412.066000 917.184000 ;
      RECT 405.854000 916.166000 408.226000 917.184000 ;
      RECT 402.014000 916.166000 404.386000 917.184000 ;
      RECT 398.174000 916.166000 400.546000 917.184000 ;
      RECT 394.334000 916.166000 396.706000 917.184000 ;
      RECT 390.494000 916.166000 392.866000 917.184000 ;
      RECT 386.654000 916.166000 389.026000 917.184000 ;
      RECT 382.814000 916.166000 385.186000 917.184000 ;
      RECT 378.974000 916.166000 381.346000 917.184000 ;
      RECT 375.134000 916.166000 377.506000 917.184000 ;
      RECT 371.294000 916.166000 373.666000 917.184000 ;
      RECT 367.454000 916.166000 369.826000 917.184000 ;
      RECT 363.614000 916.166000 365.986000 917.184000 ;
      RECT 359.774000 916.166000 362.146000 917.184000 ;
      RECT 355.934000 916.166000 358.306000 917.184000 ;
      RECT 352.094000 916.166000 354.466000 917.184000 ;
      RECT 348.254000 916.166000 350.626000 917.184000 ;
      RECT 344.414000 916.166000 346.786000 917.184000 ;
      RECT 340.574000 916.166000 342.946000 917.184000 ;
      RECT 336.734000 916.166000 339.106000 917.184000 ;
      RECT 332.894000 916.166000 335.266000 917.184000 ;
      RECT 329.054000 916.166000 331.426000 917.184000 ;
      RECT 325.214000 916.166000 327.586000 917.184000 ;
      RECT 321.374000 916.166000 323.746000 917.184000 ;
      RECT 317.534000 916.166000 319.906000 917.184000 ;
      RECT 313.694000 916.166000 316.066000 917.184000 ;
      RECT 309.854000 916.166000 312.226000 917.184000 ;
      RECT 306.014000 916.166000 308.386000 917.184000 ;
      RECT 302.174000 916.166000 304.546000 917.184000 ;
      RECT 298.334000 916.166000 300.706000 917.184000 ;
      RECT 294.494000 916.166000 296.866000 917.184000 ;
      RECT 290.654000 916.166000 293.026000 917.184000 ;
      RECT 286.814000 916.166000 289.186000 917.184000 ;
      RECT 282.974000 916.166000 285.346000 917.184000 ;
      RECT 279.134000 916.166000 281.506000 917.184000 ;
      RECT 275.294000 916.166000 277.666000 917.184000 ;
      RECT 271.454000 916.166000 273.826000 917.184000 ;
      RECT 267.614000 916.166000 269.986000 917.184000 ;
      RECT 263.774000 916.166000 266.146000 917.184000 ;
      RECT 259.934000 916.166000 262.306000 917.184000 ;
      RECT 256.094000 916.166000 258.466000 917.184000 ;
      RECT 252.254000 916.166000 254.626000 917.184000 ;
      RECT 248.414000 916.166000 250.786000 917.184000 ;
      RECT 244.574000 916.166000 246.946000 917.184000 ;
      RECT 240.734000 916.166000 243.106000 917.184000 ;
      RECT 236.894000 916.166000 239.266000 917.184000 ;
      RECT 233.054000 916.166000 235.426000 917.184000 ;
      RECT 229.214000 916.166000 231.586000 917.184000 ;
      RECT 225.374000 916.166000 227.746000 917.184000 ;
      RECT 221.534000 916.166000 223.906000 917.184000 ;
      RECT 217.694000 916.166000 220.066000 917.184000 ;
      RECT 213.854000 916.166000 216.226000 917.184000 ;
      RECT 210.014000 916.166000 212.386000 917.184000 ;
      RECT 206.174000 916.166000 208.546000 917.184000 ;
      RECT 202.334000 916.166000 204.706000 917.184000 ;
      RECT 198.494000 916.166000 200.866000 917.184000 ;
      RECT 194.654000 916.166000 197.026000 917.184000 ;
      RECT 190.814000 916.166000 193.186000 917.184000 ;
      RECT 186.974000 916.166000 189.346000 917.184000 ;
      RECT 183.134000 916.166000 185.506000 917.184000 ;
      RECT 179.294000 916.166000 181.666000 917.184000 ;
      RECT 175.454000 916.166000 177.826000 917.184000 ;
      RECT 171.614000 916.166000 173.986000 917.184000 ;
      RECT 167.774000 916.166000 170.146000 917.184000 ;
      RECT 163.934000 916.166000 166.306000 917.184000 ;
      RECT 160.094000 916.166000 162.466000 917.184000 ;
      RECT 156.254000 916.166000 158.626000 917.184000 ;
      RECT 152.414000 916.166000 154.786000 917.184000 ;
      RECT 148.574000 916.166000 150.946000 917.184000 ;
      RECT 144.734000 916.166000 147.106000 917.184000 ;
      RECT 140.894000 916.166000 143.266000 917.184000 ;
      RECT 137.054000 916.166000 139.426000 917.184000 ;
      RECT 133.214000 916.166000 135.586000 917.184000 ;
      RECT 129.374000 916.166000 131.746000 917.184000 ;
      RECT 125.534000 916.166000 127.906000 917.184000 ;
      RECT 121.694000 916.166000 124.066000 917.184000 ;
      RECT 117.854000 916.166000 120.226000 917.184000 ;
      RECT 114.014000 916.166000 116.386000 917.184000 ;
      RECT 110.174000 916.166000 112.546000 917.184000 ;
      RECT 106.334000 916.166000 108.706000 917.184000 ;
      RECT 102.494000 916.166000 104.866000 917.184000 ;
      RECT 98.654000 916.166000 101.026000 917.184000 ;
      RECT 94.814000 916.166000 97.186000 917.184000 ;
      RECT 90.974000 916.166000 93.346000 917.184000 ;
      RECT 87.134000 916.166000 89.506000 917.184000 ;
      RECT 83.294000 916.166000 85.666000 917.184000 ;
      RECT 79.454000 916.166000 81.826000 917.184000 ;
      RECT 75.614000 916.166000 77.986000 917.184000 ;
      RECT 71.774000 916.166000 74.146000 917.184000 ;
      RECT 67.934000 916.166000 70.306000 917.184000 ;
      RECT 64.094000 916.166000 66.466000 917.184000 ;
      RECT 60.254000 916.166000 62.626000 917.184000 ;
      RECT 56.414000 916.166000 58.786000 917.184000 ;
      RECT 52.574000 916.166000 54.946000 917.184000 ;
      RECT 48.734000 916.166000 51.106000 917.184000 ;
      RECT 44.894000 916.166000 47.266000 917.184000 ;
      RECT 41.054000 916.166000 43.426000 917.184000 ;
      RECT 37.214000 916.166000 39.586000 917.184000 ;
      RECT 33.374000 916.166000 35.746000 917.184000 ;
      RECT 29.534000 916.166000 31.906000 917.184000 ;
      RECT 25.694000 916.166000 28.066000 917.184000 ;
      RECT 21.854000 916.166000 24.226000 917.184000 ;
      RECT 18.014000 916.166000 20.386000 917.184000 ;
      RECT 14.174000 916.166000 16.546000 917.184000 ;
      RECT 10.334000 916.166000 12.706000 917.184000 ;
      RECT 6.494000 916.166000 8.866000 917.184000 ;
      RECT 2.654000 916.166000 5.026000 917.184000 ;
      RECT 0.000000 916.166000 1.186000 917.184000 ;
      RECT 0.000000 0.000000 504.136000 916.166000 ;
    LAYER M10 ;
      RECT 7.344000 910.320000 496.792000 917.184000 ;
      RECT 10.650000 506.640000 493.486000 910.320000 ;
      RECT 0.000000 0.000000 504.136000 506.640000 ;
    LAYER M11 ;
      RECT 0.000000 0.000000 504.136000 500.796000 ;
    LAYER AP ;
      RECT 0.000000 0.000000 504.136000 917.184000 ;
  END
END CortexM3Integration

END LIBRARY
